VERSION 5.8 ;
BUSBITCHARS "[]" ;
DIVIDERCHAR "/" ;
UNITS
    DATABASE MICRONS 1000 ;
END UNITS

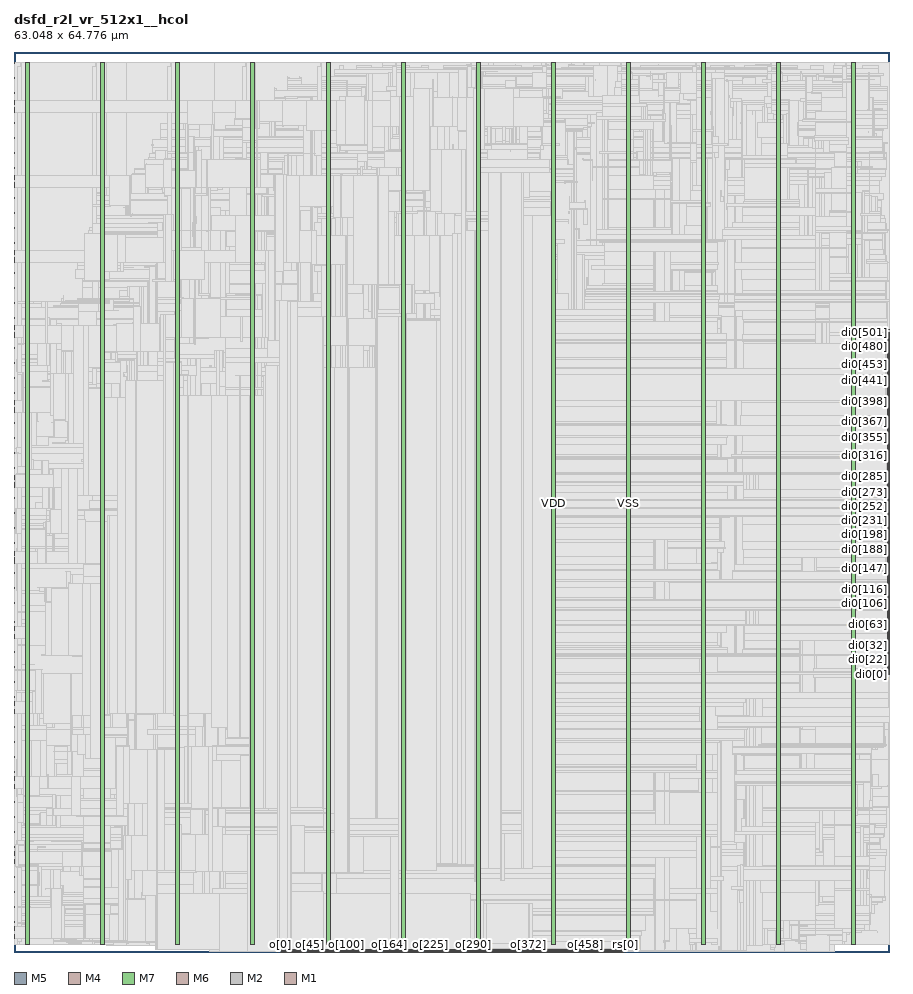
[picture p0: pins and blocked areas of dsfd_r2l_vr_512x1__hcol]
MACRO dsfd_r2l_vr_512x1__hcol
  FOREIGN dsfd_r2l_vr_512x1__hcol 0 0 ;
  CLASS BLOCK ;
  SIZE 63.048 BY 64.776 ;
  PIN ck[0]
    DIRECTION INPUT ;
    USE SIGNAL ;
    PORT
      LAYER M5 ;
        RECT  18.96 0 18.984 0.192 ;
    END
  END ck[0]
  PIN di0[0]
    DIRECTION INPUT ;
    USE SIGNAL ;
    PORT
      LAYER M4 ;
        RECT  62.856 19.968 63.048 19.992 ;
    END
  END di0[0]
  PIN di0[100]
    DIRECTION INPUT ;
    USE SIGNAL ;
    PORT
      LAYER M4 ;
        RECT  62.856 24.768 63.048 24.792 ;
    END
  END di0[100]
  PIN di0[101]
    DIRECTION INPUT ;
    USE SIGNAL ;
    PORT
      LAYER M4 ;
        RECT  62.856 24.816 63.048 24.84 ;
    END
  END di0[101]
  PIN di0[102]
    DIRECTION INPUT ;
    USE SIGNAL ;
    PORT
      LAYER M4 ;
        RECT  62.856 24.864 63.048 24.888 ;
    END
  END di0[102]
  PIN di0[103]
    DIRECTION INPUT ;
    USE SIGNAL ;
    PORT
      LAYER M4 ;
        RECT  62.856 24.912 63.048 24.936 ;
    END
  END di0[103]
  PIN di0[104]
    DIRECTION INPUT ;
    USE SIGNAL ;
    PORT
      LAYER M4 ;
        RECT  62.856 24.96 63.048 24.984 ;
    END
  END di0[104]
  PIN di0[105]
    DIRECTION INPUT ;
    USE SIGNAL ;
    PORT
      LAYER M4 ;
        RECT  62.856 25.008 63.048 25.032 ;
    END
  END di0[105]
  PIN di0[106]
    DIRECTION INPUT ;
    USE SIGNAL ;
    PORT
      LAYER M4 ;
        RECT  62.856 25.056 63.048 25.08 ;
    END
  END di0[106]
  PIN di0[107]
    DIRECTION INPUT ;
    USE SIGNAL ;
    PORT
      LAYER M4 ;
        RECT  62.856 25.104 63.048 25.128 ;
    END
  END di0[107]
  PIN di0[108]
    DIRECTION INPUT ;
    USE SIGNAL ;
    PORT
      LAYER M4 ;
        RECT  62.856 25.152 63.048 25.176 ;
    END
  END di0[108]
  PIN di0[109]
    DIRECTION INPUT ;
    USE SIGNAL ;
    PORT
      LAYER M4 ;
        RECT  62.856 25.2 63.048 25.224 ;
    END
  END di0[109]
  PIN di0[10]
    DIRECTION INPUT ;
    USE SIGNAL ;
    PORT
      LAYER M4 ;
        RECT  62.856 20.448 63.048 20.472 ;
    END
  END di0[10]
  PIN di0[110]
    DIRECTION INPUT ;
    USE SIGNAL ;
    PORT
      LAYER M4 ;
        RECT  62.856 25.248 63.048 25.272 ;
    END
  END di0[110]
  PIN di0[111]
    DIRECTION INPUT ;
    USE SIGNAL ;
    PORT
      LAYER M4 ;
        RECT  62.856 25.296 63.048 25.32 ;
    END
  END di0[111]
  PIN di0[112]
    DIRECTION INPUT ;
    USE SIGNAL ;
    PORT
      LAYER M4 ;
        RECT  62.856 25.344 63.048 25.368 ;
    END
  END di0[112]
  PIN di0[113]
    DIRECTION INPUT ;
    USE SIGNAL ;
    PORT
      LAYER M4 ;
        RECT  62.856 25.392 63.048 25.416 ;
    END
  END di0[113]
  PIN di0[114]
    DIRECTION INPUT ;
    USE SIGNAL ;
    PORT
      LAYER M4 ;
        RECT  62.856 25.44 63.048 25.464 ;
    END
  END di0[114]
  PIN di0[115]
    DIRECTION INPUT ;
    USE SIGNAL ;
    PORT
      LAYER M4 ;
        RECT  62.856 25.488 63.048 25.512 ;
    END
  END di0[115]
  PIN di0[116]
    DIRECTION INPUT ;
    USE SIGNAL ;
    PORT
      LAYER M4 ;
        RECT  62.856 25.536 63.048 25.56 ;
    END
  END di0[116]
  PIN di0[117]
    DIRECTION INPUT ;
    USE SIGNAL ;
    PORT
      LAYER M4 ;
        RECT  62.856 25.584 63.048 25.608 ;
    END
  END di0[117]
  PIN di0[118]
    DIRECTION INPUT ;
    USE SIGNAL ;
    PORT
      LAYER M4 ;
        RECT  62.856 25.632 63.048 25.656 ;
    END
  END di0[118]
  PIN di0[119]
    DIRECTION INPUT ;
    USE SIGNAL ;
    PORT
      LAYER M4 ;
        RECT  62.856 25.68 63.048 25.704 ;
    END
  END di0[119]
  PIN di0[11]
    DIRECTION INPUT ;
    USE SIGNAL ;
    PORT
      LAYER M4 ;
        RECT  62.856 20.496 63.048 20.52 ;
    END
  END di0[11]
  PIN di0[120]
    DIRECTION INPUT ;
    USE SIGNAL ;
    PORT
      LAYER M4 ;
        RECT  62.856 25.728 63.048 25.752 ;
    END
  END di0[120]
  PIN di0[121]
    DIRECTION INPUT ;
    USE SIGNAL ;
    PORT
      LAYER M4 ;
        RECT  62.856 25.776 63.048 25.8 ;
    END
  END di0[121]
  PIN di0[122]
    DIRECTION INPUT ;
    USE SIGNAL ;
    PORT
      LAYER M4 ;
        RECT  62.856 25.824 63.048 25.848 ;
    END
  END di0[122]
  PIN di0[123]
    DIRECTION INPUT ;
    USE SIGNAL ;
    PORT
      LAYER M4 ;
        RECT  62.856 25.872 63.048 25.896 ;
    END
  END di0[123]
  PIN di0[124]
    DIRECTION INPUT ;
    USE SIGNAL ;
    PORT
      LAYER M4 ;
        RECT  62.856 25.92 63.048 25.944 ;
    END
  END di0[124]
  PIN di0[125]
    DIRECTION INPUT ;
    USE SIGNAL ;
    PORT
      LAYER M4 ;
        RECT  62.856 25.968 63.048 25.992 ;
    END
  END di0[125]
  PIN di0[126]
    DIRECTION INPUT ;
    USE SIGNAL ;
    PORT
      LAYER M4 ;
        RECT  62.856 26.016 63.048 26.04 ;
    END
  END di0[126]
  PIN di0[127]
    DIRECTION INPUT ;
    USE SIGNAL ;
    PORT
      LAYER M4 ;
        RECT  62.856 26.064 63.048 26.088 ;
    END
  END di0[127]
  PIN di0[128]
    DIRECTION INPUT ;
    USE SIGNAL ;
    PORT
      LAYER M4 ;
        RECT  62.856 26.112 63.048 26.136 ;
    END
  END di0[128]
  PIN di0[129]
    DIRECTION INPUT ;
    USE SIGNAL ;
    PORT
      LAYER M4 ;
        RECT  62.856 26.16 63.048 26.184 ;
    END
  END di0[129]
  PIN di0[12]
    DIRECTION INPUT ;
    USE SIGNAL ;
    PORT
      LAYER M4 ;
        RECT  62.856 20.544 63.048 20.568 ;
    END
  END di0[12]
  PIN di0[130]
    DIRECTION INPUT ;
    USE SIGNAL ;
    PORT
      LAYER M4 ;
        RECT  62.856 26.208 63.048 26.232 ;
    END
  END di0[130]
  PIN di0[131]
    DIRECTION INPUT ;
    USE SIGNAL ;
    PORT
      LAYER M4 ;
        RECT  62.856 26.256 63.048 26.28 ;
    END
  END di0[131]
  PIN di0[132]
    DIRECTION INPUT ;
    USE SIGNAL ;
    PORT
      LAYER M4 ;
        RECT  62.856 26.304 63.048 26.328 ;
    END
  END di0[132]
  PIN di0[133]
    DIRECTION INPUT ;
    USE SIGNAL ;
    PORT
      LAYER M4 ;
        RECT  62.856 26.352 63.048 26.376 ;
    END
  END di0[133]
  PIN di0[134]
    DIRECTION INPUT ;
    USE SIGNAL ;
    PORT
      LAYER M4 ;
        RECT  62.856 26.4 63.048 26.424 ;
    END
  END di0[134]
  PIN di0[135]
    DIRECTION INPUT ;
    USE SIGNAL ;
    PORT
      LAYER M4 ;
        RECT  62.856 26.448 63.048 26.472 ;
    END
  END di0[135]
  PIN di0[136]
    DIRECTION INPUT ;
    USE SIGNAL ;
    PORT
      LAYER M4 ;
        RECT  62.856 26.496 63.048 26.52 ;
    END
  END di0[136]
  PIN di0[137]
    DIRECTION INPUT ;
    USE SIGNAL ;
    PORT
      LAYER M4 ;
        RECT  62.856 26.544 63.048 26.568 ;
    END
  END di0[137]
  PIN di0[138]
    DIRECTION INPUT ;
    USE SIGNAL ;
    PORT
      LAYER M4 ;
        RECT  62.856 26.592 63.048 26.616 ;
    END
  END di0[138]
  PIN di0[139]
    DIRECTION INPUT ;
    USE SIGNAL ;
    PORT
      LAYER M4 ;
        RECT  62.856 26.64 63.048 26.664 ;
    END
  END di0[139]
  PIN di0[13]
    DIRECTION INPUT ;
    USE SIGNAL ;
    PORT
      LAYER M4 ;
        RECT  62.856 20.592 63.048 20.616 ;
    END
  END di0[13]
  PIN di0[140]
    DIRECTION INPUT ;
    USE SIGNAL ;
    PORT
      LAYER M4 ;
        RECT  62.856 26.688 63.048 26.712 ;
    END
  END di0[140]
  PIN di0[141]
    DIRECTION INPUT ;
    USE SIGNAL ;
    PORT
      LAYER M4 ;
        RECT  62.856 26.736 63.048 26.76 ;
    END
  END di0[141]
  PIN di0[142]
    DIRECTION INPUT ;
    USE SIGNAL ;
    PORT
      LAYER M4 ;
        RECT  62.856 26.784 63.048 26.808 ;
    END
  END di0[142]
  PIN di0[143]
    DIRECTION INPUT ;
    USE SIGNAL ;
    PORT
      LAYER M4 ;
        RECT  62.856 26.832 63.048 26.856 ;
    END
  END di0[143]
  PIN di0[144]
    DIRECTION INPUT ;
    USE SIGNAL ;
    PORT
      LAYER M4 ;
        RECT  62.856 26.88 63.048 26.904 ;
    END
  END di0[144]
  PIN di0[145]
    DIRECTION INPUT ;
    USE SIGNAL ;
    PORT
      LAYER M4 ;
        RECT  62.856 26.928 63.048 26.952 ;
    END
  END di0[145]
  PIN di0[146]
    DIRECTION INPUT ;
    USE SIGNAL ;
    PORT
      LAYER M4 ;
        RECT  62.856 26.976 63.048 27 ;
    END
  END di0[146]
  PIN di0[147]
    DIRECTION INPUT ;
    USE SIGNAL ;
    PORT
      LAYER M4 ;
        RECT  62.856 27.024 63.048 27.048 ;
    END
  END di0[147]
  PIN di0[148]
    DIRECTION INPUT ;
    USE SIGNAL ;
    PORT
      LAYER M4 ;
        RECT  62.856 27.072 63.048 27.096 ;
    END
  END di0[148]
  PIN di0[149]
    DIRECTION INPUT ;
    USE SIGNAL ;
    PORT
      LAYER M4 ;
        RECT  62.856 27.12 63.048 27.144 ;
    END
  END di0[149]
  PIN di0[14]
    DIRECTION INPUT ;
    USE SIGNAL ;
    PORT
      LAYER M4 ;
        RECT  62.856 20.64 63.048 20.664 ;
    END
  END di0[14]
  PIN di0[150]
    DIRECTION INPUT ;
    USE SIGNAL ;
    PORT
      LAYER M4 ;
        RECT  62.856 27.168 63.048 27.192 ;
    END
  END di0[150]
  PIN di0[151]
    DIRECTION INPUT ;
    USE SIGNAL ;
    PORT
      LAYER M4 ;
        RECT  62.856 27.216 63.048 27.24 ;
    END
  END di0[151]
  PIN di0[152]
    DIRECTION INPUT ;
    USE SIGNAL ;
    PORT
      LAYER M4 ;
        RECT  62.856 27.264 63.048 27.288 ;
    END
  END di0[152]
  PIN di0[153]
    DIRECTION INPUT ;
    USE SIGNAL ;
    PORT
      LAYER M4 ;
        RECT  62.856 27.312 63.048 27.336 ;
    END
  END di0[153]
  PIN di0[154]
    DIRECTION INPUT ;
    USE SIGNAL ;
    PORT
      LAYER M4 ;
        RECT  62.856 27.36 63.048 27.384 ;
    END
  END di0[154]
  PIN di0[155]
    DIRECTION INPUT ;
    USE SIGNAL ;
    PORT
      LAYER M4 ;
        RECT  62.856 27.408 63.048 27.432 ;
    END
  END di0[155]
  PIN di0[156]
    DIRECTION INPUT ;
    USE SIGNAL ;
    PORT
      LAYER M4 ;
        RECT  62.856 27.456 63.048 27.48 ;
    END
  END di0[156]
  PIN di0[157]
    DIRECTION INPUT ;
    USE SIGNAL ;
    PORT
      LAYER M4 ;
        RECT  62.856 27.504 63.048 27.528 ;
    END
  END di0[157]
  PIN di0[158]
    DIRECTION INPUT ;
    USE SIGNAL ;
    PORT
      LAYER M4 ;
        RECT  62.856 27.552 63.048 27.576 ;
    END
  END di0[158]
  PIN di0[159]
    DIRECTION INPUT ;
    USE SIGNAL ;
    PORT
      LAYER M4 ;
        RECT  62.856 27.6 63.048 27.624 ;
    END
  END di0[159]
  PIN di0[15]
    DIRECTION INPUT ;
    USE SIGNAL ;
    PORT
      LAYER M4 ;
        RECT  62.856 20.688 63.048 20.712 ;
    END
  END di0[15]
  PIN di0[160]
    DIRECTION INPUT ;
    USE SIGNAL ;
    PORT
      LAYER M4 ;
        RECT  62.856 27.648 63.048 27.672 ;
    END
  END di0[160]
  PIN di0[161]
    DIRECTION INPUT ;
    USE SIGNAL ;
    PORT
      LAYER M4 ;
        RECT  62.856 27.696 63.048 27.72 ;
    END
  END di0[161]
  PIN di0[162]
    DIRECTION INPUT ;
    USE SIGNAL ;
    PORT
      LAYER M4 ;
        RECT  62.856 27.744 63.048 27.768 ;
    END
  END di0[162]
  PIN di0[163]
    DIRECTION INPUT ;
    USE SIGNAL ;
    PORT
      LAYER M4 ;
        RECT  62.856 27.792 63.048 27.816 ;
    END
  END di0[163]
  PIN di0[164]
    DIRECTION INPUT ;
    USE SIGNAL ;
    PORT
      LAYER M4 ;
        RECT  62.856 27.84 63.048 27.864 ;
    END
  END di0[164]
  PIN di0[165]
    DIRECTION INPUT ;
    USE SIGNAL ;
    PORT
      LAYER M4 ;
        RECT  62.856 27.888 63.048 27.912 ;
    END
  END di0[165]
  PIN di0[166]
    DIRECTION INPUT ;
    USE SIGNAL ;
    PORT
      LAYER M4 ;
        RECT  62.856 27.936 63.048 27.96 ;
    END
  END di0[166]
  PIN di0[167]
    DIRECTION INPUT ;
    USE SIGNAL ;
    PORT
      LAYER M4 ;
        RECT  62.856 27.984 63.048 28.008 ;
    END
  END di0[167]
  PIN di0[168]
    DIRECTION INPUT ;
    USE SIGNAL ;
    PORT
      LAYER M4 ;
        RECT  62.856 28.032 63.048 28.056 ;
    END
  END di0[168]
  PIN di0[169]
    DIRECTION INPUT ;
    USE SIGNAL ;
    PORT
      LAYER M4 ;
        RECT  62.856 28.08 63.048 28.104 ;
    END
  END di0[169]
  PIN di0[16]
    DIRECTION INPUT ;
    USE SIGNAL ;
    PORT
      LAYER M4 ;
        RECT  62.856 20.736 63.048 20.76 ;
    END
  END di0[16]
  PIN di0[170]
    DIRECTION INPUT ;
    USE SIGNAL ;
    PORT
      LAYER M4 ;
        RECT  62.856 28.128 63.048 28.152 ;
    END
  END di0[170]
  PIN di0[171]
    DIRECTION INPUT ;
    USE SIGNAL ;
    PORT
      LAYER M4 ;
        RECT  62.856 28.176 63.048 28.2 ;
    END
  END di0[171]
  PIN di0[172]
    DIRECTION INPUT ;
    USE SIGNAL ;
    PORT
      LAYER M4 ;
        RECT  62.856 28.224 63.048 28.248 ;
    END
  END di0[172]
  PIN di0[173]
    DIRECTION INPUT ;
    USE SIGNAL ;
    PORT
      LAYER M4 ;
        RECT  62.856 28.272 63.048 28.296 ;
    END
  END di0[173]
  PIN di0[174]
    DIRECTION INPUT ;
    USE SIGNAL ;
    PORT
      LAYER M4 ;
        RECT  62.856 28.32 63.048 28.344 ;
    END
  END di0[174]
  PIN di0[175]
    DIRECTION INPUT ;
    USE SIGNAL ;
    PORT
      LAYER M4 ;
        RECT  62.856 28.368 63.048 28.392 ;
    END
  END di0[175]
  PIN di0[176]
    DIRECTION INPUT ;
    USE SIGNAL ;
    PORT
      LAYER M4 ;
        RECT  62.856 28.416 63.048 28.44 ;
    END
  END di0[176]
  PIN di0[177]
    DIRECTION INPUT ;
    USE SIGNAL ;
    PORT
      LAYER M4 ;
        RECT  62.856 28.464 63.048 28.488 ;
    END
  END di0[177]
  PIN di0[178]
    DIRECTION INPUT ;
    USE SIGNAL ;
    PORT
      LAYER M4 ;
        RECT  62.856 28.512 63.048 28.536 ;
    END
  END di0[178]
  PIN di0[179]
    DIRECTION INPUT ;
    USE SIGNAL ;
    PORT
      LAYER M4 ;
        RECT  62.856 28.56 63.048 28.584 ;
    END
  END di0[179]
  PIN di0[17]
    DIRECTION INPUT ;
    USE SIGNAL ;
    PORT
      LAYER M4 ;
        RECT  62.856 20.784 63.048 20.808 ;
    END
  END di0[17]
  PIN di0[180]
    DIRECTION INPUT ;
    USE SIGNAL ;
    PORT
      LAYER M4 ;
        RECT  62.856 28.608 63.048 28.632 ;
    END
  END di0[180]
  PIN di0[181]
    DIRECTION INPUT ;
    USE SIGNAL ;
    PORT
      LAYER M4 ;
        RECT  62.856 28.656 63.048 28.68 ;
    END
  END di0[181]
  PIN di0[182]
    DIRECTION INPUT ;
    USE SIGNAL ;
    PORT
      LAYER M4 ;
        RECT  62.856 28.704 63.048 28.728 ;
    END
  END di0[182]
  PIN di0[183]
    DIRECTION INPUT ;
    USE SIGNAL ;
    PORT
      LAYER M4 ;
        RECT  62.856 28.752 63.048 28.776 ;
    END
  END di0[183]
  PIN di0[184]
    DIRECTION INPUT ;
    USE SIGNAL ;
    PORT
      LAYER M4 ;
        RECT  62.856 28.8 63.048 28.824 ;
    END
  END di0[184]
  PIN di0[185]
    DIRECTION INPUT ;
    USE SIGNAL ;
    PORT
      LAYER M4 ;
        RECT  62.856 28.848 63.048 28.872 ;
    END
  END di0[185]
  PIN di0[186]
    DIRECTION INPUT ;
    USE SIGNAL ;
    PORT
      LAYER M4 ;
        RECT  62.856 28.896 63.048 28.92 ;
    END
  END di0[186]
  PIN di0[187]
    DIRECTION INPUT ;
    USE SIGNAL ;
    PORT
      LAYER M4 ;
        RECT  62.856 28.944 63.048 28.968 ;
    END
  END di0[187]
  PIN di0[188]
    DIRECTION INPUT ;
    USE SIGNAL ;
    PORT
      LAYER M4 ;
        RECT  62.856 28.992 63.048 29.016 ;
    END
  END di0[188]
  PIN di0[189]
    DIRECTION INPUT ;
    USE SIGNAL ;
    PORT
      LAYER M4 ;
        RECT  62.856 29.04 63.048 29.064 ;
    END
  END di0[189]
  PIN di0[18]
    DIRECTION INPUT ;
    USE SIGNAL ;
    PORT
      LAYER M4 ;
        RECT  62.856 20.832 63.048 20.856 ;
    END
  END di0[18]
  PIN di0[190]
    DIRECTION INPUT ;
    USE SIGNAL ;
    PORT
      LAYER M4 ;
        RECT  62.856 29.088 63.048 29.112 ;
    END
  END di0[190]
  PIN di0[191]
    DIRECTION INPUT ;
    USE SIGNAL ;
    PORT
      LAYER M4 ;
        RECT  62.856 29.136 63.048 29.16 ;
    END
  END di0[191]
  PIN di0[192]
    DIRECTION INPUT ;
    USE SIGNAL ;
    PORT
      LAYER M4 ;
        RECT  62.856 29.184 63.048 29.208 ;
    END
  END di0[192]
  PIN di0[193]
    DIRECTION INPUT ;
    USE SIGNAL ;
    PORT
      LAYER M4 ;
        RECT  62.856 29.232 63.048 29.256 ;
    END
  END di0[193]
  PIN di0[194]
    DIRECTION INPUT ;
    USE SIGNAL ;
    PORT
      LAYER M4 ;
        RECT  62.856 29.28 63.048 29.304 ;
    END
  END di0[194]
  PIN di0[195]
    DIRECTION INPUT ;
    USE SIGNAL ;
    PORT
      LAYER M4 ;
        RECT  62.856 29.328 63.048 29.352 ;
    END
  END di0[195]
  PIN di0[196]
    DIRECTION INPUT ;
    USE SIGNAL ;
    PORT
      LAYER M4 ;
        RECT  62.856 29.376 63.048 29.4 ;
    END
  END di0[196]
  PIN di0[197]
    DIRECTION INPUT ;
    USE SIGNAL ;
    PORT
      LAYER M4 ;
        RECT  62.856 29.424 63.048 29.448 ;
    END
  END di0[197]
  PIN di0[198]
    DIRECTION INPUT ;
    USE SIGNAL ;
    PORT
      LAYER M4 ;
        RECT  62.856 29.472 63.048 29.496 ;
    END
  END di0[198]
  PIN di0[199]
    DIRECTION INPUT ;
    USE SIGNAL ;
    PORT
      LAYER M4 ;
        RECT  62.856 29.52 63.048 29.544 ;
    END
  END di0[199]
  PIN di0[19]
    DIRECTION INPUT ;
    USE SIGNAL ;
    PORT
      LAYER M4 ;
        RECT  62.856 20.88 63.048 20.904 ;
    END
  END di0[19]
  PIN di0[1]
    DIRECTION INPUT ;
    USE SIGNAL ;
    PORT
      LAYER M4 ;
        RECT  62.856 20.016 63.048 20.04 ;
    END
  END di0[1]
  PIN di0[200]
    DIRECTION INPUT ;
    USE SIGNAL ;
    PORT
      LAYER M4 ;
        RECT  62.856 29.568 63.048 29.592 ;
    END
  END di0[200]
  PIN di0[201]
    DIRECTION INPUT ;
    USE SIGNAL ;
    PORT
      LAYER M4 ;
        RECT  62.856 29.616 63.048 29.64 ;
    END
  END di0[201]
  PIN di0[202]
    DIRECTION INPUT ;
    USE SIGNAL ;
    PORT
      LAYER M4 ;
        RECT  62.856 29.664 63.048 29.688 ;
    END
  END di0[202]
  PIN di0[203]
    DIRECTION INPUT ;
    USE SIGNAL ;
    PORT
      LAYER M4 ;
        RECT  62.856 29.712 63.048 29.736 ;
    END
  END di0[203]
  PIN di0[204]
    DIRECTION INPUT ;
    USE SIGNAL ;
    PORT
      LAYER M4 ;
        RECT  62.856 29.76 63.048 29.784 ;
    END
  END di0[204]
  PIN di0[205]
    DIRECTION INPUT ;
    USE SIGNAL ;
    PORT
      LAYER M4 ;
        RECT  62.856 29.808 63.048 29.832 ;
    END
  END di0[205]
  PIN di0[206]
    DIRECTION INPUT ;
    USE SIGNAL ;
    PORT
      LAYER M4 ;
        RECT  62.856 29.856 63.048 29.88 ;
    END
  END di0[206]
  PIN di0[207]
    DIRECTION INPUT ;
    USE SIGNAL ;
    PORT
      LAYER M4 ;
        RECT  62.856 29.904 63.048 29.928 ;
    END
  END di0[207]
  PIN di0[208]
    DIRECTION INPUT ;
    USE SIGNAL ;
    PORT
      LAYER M4 ;
        RECT  62.856 29.952 63.048 29.976 ;
    END
  END di0[208]
  PIN di0[209]
    DIRECTION INPUT ;
    USE SIGNAL ;
    PORT
      LAYER M4 ;
        RECT  62.856 30 63.048 30.024 ;
    END
  END di0[209]
  PIN di0[20]
    DIRECTION INPUT ;
    USE SIGNAL ;
    PORT
      LAYER M4 ;
        RECT  62.856 20.928 63.048 20.952 ;
    END
  END di0[20]
  PIN di0[210]
    DIRECTION INPUT ;
    USE SIGNAL ;
    PORT
      LAYER M4 ;
        RECT  62.856 30.048 63.048 30.072 ;
    END
  END di0[210]
  PIN di0[211]
    DIRECTION INPUT ;
    USE SIGNAL ;
    PORT
      LAYER M4 ;
        RECT  62.856 30.096 63.048 30.12 ;
    END
  END di0[211]
  PIN di0[212]
    DIRECTION INPUT ;
    USE SIGNAL ;
    PORT
      LAYER M4 ;
        RECT  62.856 30.144 63.048 30.168 ;
    END
  END di0[212]
  PIN di0[213]
    DIRECTION INPUT ;
    USE SIGNAL ;
    PORT
      LAYER M4 ;
        RECT  62.856 30.192 63.048 30.216 ;
    END
  END di0[213]
  PIN di0[214]
    DIRECTION INPUT ;
    USE SIGNAL ;
    PORT
      LAYER M4 ;
        RECT  62.856 30.24 63.048 30.264 ;
    END
  END di0[214]
  PIN di0[215]
    DIRECTION INPUT ;
    USE SIGNAL ;
    PORT
      LAYER M4 ;
        RECT  62.856 30.288 63.048 30.312 ;
    END
  END di0[215]
  PIN di0[216]
    DIRECTION INPUT ;
    USE SIGNAL ;
    PORT
      LAYER M4 ;
        RECT  62.856 30.336 63.048 30.36 ;
    END
  END di0[216]
  PIN di0[217]
    DIRECTION INPUT ;
    USE SIGNAL ;
    PORT
      LAYER M4 ;
        RECT  62.856 30.384 63.048 30.408 ;
    END
  END di0[217]
  PIN di0[218]
    DIRECTION INPUT ;
    USE SIGNAL ;
    PORT
      LAYER M4 ;
        RECT  62.856 30.432 63.048 30.456 ;
    END
  END di0[218]
  PIN di0[219]
    DIRECTION INPUT ;
    USE SIGNAL ;
    PORT
      LAYER M4 ;
        RECT  62.856 30.48 63.048 30.504 ;
    END
  END di0[219]
  PIN di0[21]
    DIRECTION INPUT ;
    USE SIGNAL ;
    PORT
      LAYER M4 ;
        RECT  62.856 20.976 63.048 21 ;
    END
  END di0[21]
  PIN di0[220]
    DIRECTION INPUT ;
    USE SIGNAL ;
    PORT
      LAYER M4 ;
        RECT  62.856 30.528 63.048 30.552 ;
    END
  END di0[220]
  PIN di0[221]
    DIRECTION INPUT ;
    USE SIGNAL ;
    PORT
      LAYER M4 ;
        RECT  62.856 30.576 63.048 30.6 ;
    END
  END di0[221]
  PIN di0[222]
    DIRECTION INPUT ;
    USE SIGNAL ;
    PORT
      LAYER M4 ;
        RECT  62.856 30.624 63.048 30.648 ;
    END
  END di0[222]
  PIN di0[223]
    DIRECTION INPUT ;
    USE SIGNAL ;
    PORT
      LAYER M4 ;
        RECT  62.856 30.672 63.048 30.696 ;
    END
  END di0[223]
  PIN di0[224]
    DIRECTION INPUT ;
    USE SIGNAL ;
    PORT
      LAYER M4 ;
        RECT  62.856 30.72 63.048 30.744 ;
    END
  END di0[224]
  PIN di0[225]
    DIRECTION INPUT ;
    USE SIGNAL ;
    PORT
      LAYER M4 ;
        RECT  62.856 30.768 63.048 30.792 ;
    END
  END di0[225]
  PIN di0[226]
    DIRECTION INPUT ;
    USE SIGNAL ;
    PORT
      LAYER M4 ;
        RECT  62.856 30.816 63.048 30.84 ;
    END
  END di0[226]
  PIN di0[227]
    DIRECTION INPUT ;
    USE SIGNAL ;
    PORT
      LAYER M4 ;
        RECT  62.856 30.864 63.048 30.888 ;
    END
  END di0[227]
  PIN di0[228]
    DIRECTION INPUT ;
    USE SIGNAL ;
    PORT
      LAYER M4 ;
        RECT  62.856 30.912 63.048 30.936 ;
    END
  END di0[228]
  PIN di0[229]
    DIRECTION INPUT ;
    USE SIGNAL ;
    PORT
      LAYER M4 ;
        RECT  62.856 30.96 63.048 30.984 ;
    END
  END di0[229]
  PIN di0[22]
    DIRECTION INPUT ;
    USE SIGNAL ;
    PORT
      LAYER M4 ;
        RECT  62.856 21.024 63.048 21.048 ;
    END
  END di0[22]
  PIN di0[230]
    DIRECTION INPUT ;
    USE SIGNAL ;
    PORT
      LAYER M4 ;
        RECT  62.856 31.008 63.048 31.032 ;
    END
  END di0[230]
  PIN di0[231]
    DIRECTION INPUT ;
    USE SIGNAL ;
    PORT
      LAYER M4 ;
        RECT  62.856 31.056 63.048 31.08 ;
    END
  END di0[231]
  PIN di0[232]
    DIRECTION INPUT ;
    USE SIGNAL ;
    PORT
      LAYER M4 ;
        RECT  62.856 31.104 63.048 31.128 ;
    END
  END di0[232]
  PIN di0[233]
    DIRECTION INPUT ;
    USE SIGNAL ;
    PORT
      LAYER M4 ;
        RECT  62.856 31.152 63.048 31.176 ;
    END
  END di0[233]
  PIN di0[234]
    DIRECTION INPUT ;
    USE SIGNAL ;
    PORT
      LAYER M4 ;
        RECT  62.856 31.2 63.048 31.224 ;
    END
  END di0[234]
  PIN di0[235]
    DIRECTION INPUT ;
    USE SIGNAL ;
    PORT
      LAYER M4 ;
        RECT  62.856 31.248 63.048 31.272 ;
    END
  END di0[235]
  PIN di0[236]
    DIRECTION INPUT ;
    USE SIGNAL ;
    PORT
      LAYER M4 ;
        RECT  62.856 31.296 63.048 31.32 ;
    END
  END di0[236]
  PIN di0[237]
    DIRECTION INPUT ;
    USE SIGNAL ;
    PORT
      LAYER M4 ;
        RECT  62.856 31.344 63.048 31.368 ;
    END
  END di0[237]
  PIN di0[238]
    DIRECTION INPUT ;
    USE SIGNAL ;
    PORT
      LAYER M4 ;
        RECT  62.856 31.392 63.048 31.416 ;
    END
  END di0[238]
  PIN di0[239]
    DIRECTION INPUT ;
    USE SIGNAL ;
    PORT
      LAYER M4 ;
        RECT  62.856 31.44 63.048 31.464 ;
    END
  END di0[239]
  PIN di0[23]
    DIRECTION INPUT ;
    USE SIGNAL ;
    PORT
      LAYER M4 ;
        RECT  62.856 21.072 63.048 21.096 ;
    END
  END di0[23]
  PIN di0[240]
    DIRECTION INPUT ;
    USE SIGNAL ;
    PORT
      LAYER M4 ;
        RECT  62.856 31.488 63.048 31.512 ;
    END
  END di0[240]
  PIN di0[241]
    DIRECTION INPUT ;
    USE SIGNAL ;
    PORT
      LAYER M4 ;
        RECT  62.856 31.536 63.048 31.56 ;
    END
  END di0[241]
  PIN di0[242]
    DIRECTION INPUT ;
    USE SIGNAL ;
    PORT
      LAYER M4 ;
        RECT  62.856 31.584 63.048 31.608 ;
    END
  END di0[242]
  PIN di0[243]
    DIRECTION INPUT ;
    USE SIGNAL ;
    PORT
      LAYER M4 ;
        RECT  62.856 31.632 63.048 31.656 ;
    END
  END di0[243]
  PIN di0[244]
    DIRECTION INPUT ;
    USE SIGNAL ;
    PORT
      LAYER M4 ;
        RECT  62.856 31.68 63.048 31.704 ;
    END
  END di0[244]
  PIN di0[245]
    DIRECTION INPUT ;
    USE SIGNAL ;
    PORT
      LAYER M4 ;
        RECT  62.856 31.728 63.048 31.752 ;
    END
  END di0[245]
  PIN di0[246]
    DIRECTION INPUT ;
    USE SIGNAL ;
    PORT
      LAYER M4 ;
        RECT  62.856 31.776 63.048 31.8 ;
    END
  END di0[246]
  PIN di0[247]
    DIRECTION INPUT ;
    USE SIGNAL ;
    PORT
      LAYER M4 ;
        RECT  62.856 31.824 63.048 31.848 ;
    END
  END di0[247]
  PIN di0[248]
    DIRECTION INPUT ;
    USE SIGNAL ;
    PORT
      LAYER M4 ;
        RECT  62.856 31.872 63.048 31.896 ;
    END
  END di0[248]
  PIN di0[249]
    DIRECTION INPUT ;
    USE SIGNAL ;
    PORT
      LAYER M4 ;
        RECT  62.856 31.92 63.048 31.944 ;
    END
  END di0[249]
  PIN di0[24]
    DIRECTION INPUT ;
    USE SIGNAL ;
    PORT
      LAYER M4 ;
        RECT  62.856 21.12 63.048 21.144 ;
    END
  END di0[24]
  PIN di0[250]
    DIRECTION INPUT ;
    USE SIGNAL ;
    PORT
      LAYER M4 ;
        RECT  62.856 31.968 63.048 31.992 ;
    END
  END di0[250]
  PIN di0[251]
    DIRECTION INPUT ;
    USE SIGNAL ;
    PORT
      LAYER M4 ;
        RECT  62.856 32.016 63.048 32.04 ;
    END
  END di0[251]
  PIN di0[252]
    DIRECTION INPUT ;
    USE SIGNAL ;
    PORT
      LAYER M4 ;
        RECT  62.856 32.064 63.048 32.088 ;
    END
  END di0[252]
  PIN di0[253]
    DIRECTION INPUT ;
    USE SIGNAL ;
    PORT
      LAYER M4 ;
        RECT  62.856 32.112 63.048 32.136 ;
    END
  END di0[253]
  PIN di0[254]
    DIRECTION INPUT ;
    USE SIGNAL ;
    PORT
      LAYER M4 ;
        RECT  62.856 32.16 63.048 32.184 ;
    END
  END di0[254]
  PIN di0[255]
    DIRECTION INPUT ;
    USE SIGNAL ;
    PORT
      LAYER M4 ;
        RECT  62.856 32.208 63.048 32.232 ;
    END
  END di0[255]
  PIN di0[256]
    DIRECTION INPUT ;
    USE SIGNAL ;
    PORT
      LAYER M4 ;
        RECT  62.856 32.256 63.048 32.28 ;
    END
  END di0[256]
  PIN di0[257]
    DIRECTION INPUT ;
    USE SIGNAL ;
    PORT
      LAYER M4 ;
        RECT  62.856 32.304 63.048 32.328 ;
    END
  END di0[257]
  PIN di0[258]
    DIRECTION INPUT ;
    USE SIGNAL ;
    PORT
      LAYER M4 ;
        RECT  62.856 32.352 63.048 32.376 ;
    END
  END di0[258]
  PIN di0[259]
    DIRECTION INPUT ;
    USE SIGNAL ;
    PORT
      LAYER M4 ;
        RECT  62.856 32.4 63.048 32.424 ;
    END
  END di0[259]
  PIN di0[25]
    DIRECTION INPUT ;
    USE SIGNAL ;
    PORT
      LAYER M4 ;
        RECT  62.856 21.168 63.048 21.192 ;
    END
  END di0[25]
  PIN di0[260]
    DIRECTION INPUT ;
    USE SIGNAL ;
    PORT
      LAYER M4 ;
        RECT  62.856 32.448 63.048 32.472 ;
    END
  END di0[260]
  PIN di0[261]
    DIRECTION INPUT ;
    USE SIGNAL ;
    PORT
      LAYER M4 ;
        RECT  62.856 32.496 63.048 32.52 ;
    END
  END di0[261]
  PIN di0[262]
    DIRECTION INPUT ;
    USE SIGNAL ;
    PORT
      LAYER M4 ;
        RECT  62.856 32.544 63.048 32.568 ;
    END
  END di0[262]
  PIN di0[263]
    DIRECTION INPUT ;
    USE SIGNAL ;
    PORT
      LAYER M4 ;
        RECT  62.856 32.592 63.048 32.616 ;
    END
  END di0[263]
  PIN di0[264]
    DIRECTION INPUT ;
    USE SIGNAL ;
    PORT
      LAYER M4 ;
        RECT  62.856 32.64 63.048 32.664 ;
    END
  END di0[264]
  PIN di0[265]
    DIRECTION INPUT ;
    USE SIGNAL ;
    PORT
      LAYER M4 ;
        RECT  62.856 32.688 63.048 32.712 ;
    END
  END di0[265]
  PIN di0[266]
    DIRECTION INPUT ;
    USE SIGNAL ;
    PORT
      LAYER M4 ;
        RECT  62.856 32.736 63.048 32.76 ;
    END
  END di0[266]
  PIN di0[267]
    DIRECTION INPUT ;
    USE SIGNAL ;
    PORT
      LAYER M4 ;
        RECT  62.856 32.784 63.048 32.808 ;
    END
  END di0[267]
  PIN di0[268]
    DIRECTION INPUT ;
    USE SIGNAL ;
    PORT
      LAYER M4 ;
        RECT  62.856 32.832 63.048 32.856 ;
    END
  END di0[268]
  PIN di0[269]
    DIRECTION INPUT ;
    USE SIGNAL ;
    PORT
      LAYER M4 ;
        RECT  62.856 32.88 63.048 32.904 ;
    END
  END di0[269]
  PIN di0[26]
    DIRECTION INPUT ;
    USE SIGNAL ;
    PORT
      LAYER M4 ;
        RECT  62.856 21.216 63.048 21.24 ;
    END
  END di0[26]
  PIN di0[270]
    DIRECTION INPUT ;
    USE SIGNAL ;
    PORT
      LAYER M4 ;
        RECT  62.856 32.928 63.048 32.952 ;
    END
  END di0[270]
  PIN di0[271]
    DIRECTION INPUT ;
    USE SIGNAL ;
    PORT
      LAYER M4 ;
        RECT  62.856 32.976 63.048 33 ;
    END
  END di0[271]
  PIN di0[272]
    DIRECTION INPUT ;
    USE SIGNAL ;
    PORT
      LAYER M4 ;
        RECT  62.856 33.024 63.048 33.048 ;
    END
  END di0[272]
  PIN di0[273]
    DIRECTION INPUT ;
    USE SIGNAL ;
    PORT
      LAYER M4 ;
        RECT  62.856 33.072 63.048 33.096 ;
    END
  END di0[273]
  PIN di0[274]
    DIRECTION INPUT ;
    USE SIGNAL ;
    PORT
      LAYER M4 ;
        RECT  62.856 33.12 63.048 33.144 ;
    END
  END di0[274]
  PIN di0[275]
    DIRECTION INPUT ;
    USE SIGNAL ;
    PORT
      LAYER M4 ;
        RECT  62.856 33.168 63.048 33.192 ;
    END
  END di0[275]
  PIN di0[276]
    DIRECTION INPUT ;
    USE SIGNAL ;
    PORT
      LAYER M4 ;
        RECT  62.856 33.216 63.048 33.24 ;
    END
  END di0[276]
  PIN di0[277]
    DIRECTION INPUT ;
    USE SIGNAL ;
    PORT
      LAYER M4 ;
        RECT  62.856 33.264 63.048 33.288 ;
    END
  END di0[277]
  PIN di0[278]
    DIRECTION INPUT ;
    USE SIGNAL ;
    PORT
      LAYER M4 ;
        RECT  62.856 33.312 63.048 33.336 ;
    END
  END di0[278]
  PIN di0[279]
    DIRECTION INPUT ;
    USE SIGNAL ;
    PORT
      LAYER M4 ;
        RECT  62.856 33.36 63.048 33.384 ;
    END
  END di0[279]
  PIN di0[27]
    DIRECTION INPUT ;
    USE SIGNAL ;
    PORT
      LAYER M4 ;
        RECT  62.856 21.264 63.048 21.288 ;
    END
  END di0[27]
  PIN di0[280]
    DIRECTION INPUT ;
    USE SIGNAL ;
    PORT
      LAYER M4 ;
        RECT  62.856 33.408 63.048 33.432 ;
    END
  END di0[280]
  PIN di0[281]
    DIRECTION INPUT ;
    USE SIGNAL ;
    PORT
      LAYER M4 ;
        RECT  62.856 33.456 63.048 33.48 ;
    END
  END di0[281]
  PIN di0[282]
    DIRECTION INPUT ;
    USE SIGNAL ;
    PORT
      LAYER M4 ;
        RECT  62.856 33.504 63.048 33.528 ;
    END
  END di0[282]
  PIN di0[283]
    DIRECTION INPUT ;
    USE SIGNAL ;
    PORT
      LAYER M4 ;
        RECT  62.856 33.552 63.048 33.576 ;
    END
  END di0[283]
  PIN di0[284]
    DIRECTION INPUT ;
    USE SIGNAL ;
    PORT
      LAYER M4 ;
        RECT  62.856 33.6 63.048 33.624 ;
    END
  END di0[284]
  PIN di0[285]
    DIRECTION INPUT ;
    USE SIGNAL ;
    PORT
      LAYER M4 ;
        RECT  62.856 33.648 63.048 33.672 ;
    END
  END di0[285]
  PIN di0[286]
    DIRECTION INPUT ;
    USE SIGNAL ;
    PORT
      LAYER M4 ;
        RECT  62.856 33.696 63.048 33.72 ;
    END
  END di0[286]
  PIN di0[287]
    DIRECTION INPUT ;
    USE SIGNAL ;
    PORT
      LAYER M4 ;
        RECT  62.856 33.744 63.048 33.768 ;
    END
  END di0[287]
  PIN di0[288]
    DIRECTION INPUT ;
    USE SIGNAL ;
    PORT
      LAYER M4 ;
        RECT  62.856 33.792 63.048 33.816 ;
    END
  END di0[288]
  PIN di0[289]
    DIRECTION INPUT ;
    USE SIGNAL ;
    PORT
      LAYER M4 ;
        RECT  62.856 33.84 63.048 33.864 ;
    END
  END di0[289]
  PIN di0[28]
    DIRECTION INPUT ;
    USE SIGNAL ;
    PORT
      LAYER M4 ;
        RECT  62.856 21.312 63.048 21.336 ;
    END
  END di0[28]
  PIN di0[290]
    DIRECTION INPUT ;
    USE SIGNAL ;
    PORT
      LAYER M4 ;
        RECT  62.856 33.888 63.048 33.912 ;
    END
  END di0[290]
  PIN di0[291]
    DIRECTION INPUT ;
    USE SIGNAL ;
    PORT
      LAYER M4 ;
        RECT  62.856 33.936 63.048 33.96 ;
    END
  END di0[291]
  PIN di0[292]
    DIRECTION INPUT ;
    USE SIGNAL ;
    PORT
      LAYER M4 ;
        RECT  62.856 33.984 63.048 34.008 ;
    END
  END di0[292]
  PIN di0[293]
    DIRECTION INPUT ;
    USE SIGNAL ;
    PORT
      LAYER M4 ;
        RECT  62.856 34.032 63.048 34.056 ;
    END
  END di0[293]
  PIN di0[294]
    DIRECTION INPUT ;
    USE SIGNAL ;
    PORT
      LAYER M4 ;
        RECT  62.856 34.08 63.048 34.104 ;
    END
  END di0[294]
  PIN di0[295]
    DIRECTION INPUT ;
    USE SIGNAL ;
    PORT
      LAYER M4 ;
        RECT  62.856 34.128 63.048 34.152 ;
    END
  END di0[295]
  PIN di0[296]
    DIRECTION INPUT ;
    USE SIGNAL ;
    PORT
      LAYER M4 ;
        RECT  62.856 34.176 63.048 34.2 ;
    END
  END di0[296]
  PIN di0[297]
    DIRECTION INPUT ;
    USE SIGNAL ;
    PORT
      LAYER M4 ;
        RECT  62.856 34.224 63.048 34.248 ;
    END
  END di0[297]
  PIN di0[298]
    DIRECTION INPUT ;
    USE SIGNAL ;
    PORT
      LAYER M4 ;
        RECT  62.856 34.272 63.048 34.296 ;
    END
  END di0[298]
  PIN di0[299]
    DIRECTION INPUT ;
    USE SIGNAL ;
    PORT
      LAYER M4 ;
        RECT  62.856 34.32 63.048 34.344 ;
    END
  END di0[299]
  PIN di0[29]
    DIRECTION INPUT ;
    USE SIGNAL ;
    PORT
      LAYER M4 ;
        RECT  62.856 21.36 63.048 21.384 ;
    END
  END di0[29]
  PIN di0[2]
    DIRECTION INPUT ;
    USE SIGNAL ;
    PORT
      LAYER M4 ;
        RECT  62.856 20.064 63.048 20.088 ;
    END
  END di0[2]
  PIN di0[300]
    DIRECTION INPUT ;
    USE SIGNAL ;
    PORT
      LAYER M4 ;
        RECT  62.856 34.368 63.048 34.392 ;
    END
  END di0[300]
  PIN di0[301]
    DIRECTION INPUT ;
    USE SIGNAL ;
    PORT
      LAYER M4 ;
        RECT  62.856 34.416 63.048 34.44 ;
    END
  END di0[301]
  PIN di0[302]
    DIRECTION INPUT ;
    USE SIGNAL ;
    PORT
      LAYER M4 ;
        RECT  62.856 34.464 63.048 34.488 ;
    END
  END di0[302]
  PIN di0[303]
    DIRECTION INPUT ;
    USE SIGNAL ;
    PORT
      LAYER M4 ;
        RECT  62.856 34.512 63.048 34.536 ;
    END
  END di0[303]
  PIN di0[304]
    DIRECTION INPUT ;
    USE SIGNAL ;
    PORT
      LAYER M4 ;
        RECT  62.856 34.56 63.048 34.584 ;
    END
  END di0[304]
  PIN di0[305]
    DIRECTION INPUT ;
    USE SIGNAL ;
    PORT
      LAYER M4 ;
        RECT  62.856 34.608 63.048 34.632 ;
    END
  END di0[305]
  PIN di0[306]
    DIRECTION INPUT ;
    USE SIGNAL ;
    PORT
      LAYER M4 ;
        RECT  62.856 34.656 63.048 34.68 ;
    END
  END di0[306]
  PIN di0[307]
    DIRECTION INPUT ;
    USE SIGNAL ;
    PORT
      LAYER M4 ;
        RECT  62.856 34.704 63.048 34.728 ;
    END
  END di0[307]
  PIN di0[308]
    DIRECTION INPUT ;
    USE SIGNAL ;
    PORT
      LAYER M4 ;
        RECT  62.856 34.752 63.048 34.776 ;
    END
  END di0[308]
  PIN di0[309]
    DIRECTION INPUT ;
    USE SIGNAL ;
    PORT
      LAYER M4 ;
        RECT  62.856 34.8 63.048 34.824 ;
    END
  END di0[309]
  PIN di0[30]
    DIRECTION INPUT ;
    USE SIGNAL ;
    PORT
      LAYER M4 ;
        RECT  62.856 21.408 63.048 21.432 ;
    END
  END di0[30]
  PIN di0[310]
    DIRECTION INPUT ;
    USE SIGNAL ;
    PORT
      LAYER M4 ;
        RECT  62.856 34.848 63.048 34.872 ;
    END
  END di0[310]
  PIN di0[311]
    DIRECTION INPUT ;
    USE SIGNAL ;
    PORT
      LAYER M4 ;
        RECT  62.856 34.896 63.048 34.92 ;
    END
  END di0[311]
  PIN di0[312]
    DIRECTION INPUT ;
    USE SIGNAL ;
    PORT
      LAYER M4 ;
        RECT  62.856 34.944 63.048 34.968 ;
    END
  END di0[312]
  PIN di0[313]
    DIRECTION INPUT ;
    USE SIGNAL ;
    PORT
      LAYER M4 ;
        RECT  62.856 34.992 63.048 35.016 ;
    END
  END di0[313]
  PIN di0[314]
    DIRECTION INPUT ;
    USE SIGNAL ;
    PORT
      LAYER M4 ;
        RECT  62.856 35.04 63.048 35.064 ;
    END
  END di0[314]
  PIN di0[315]
    DIRECTION INPUT ;
    USE SIGNAL ;
    PORT
      LAYER M4 ;
        RECT  62.856 35.088 63.048 35.112 ;
    END
  END di0[315]
  PIN di0[316]
    DIRECTION INPUT ;
    USE SIGNAL ;
    PORT
      LAYER M4 ;
        RECT  62.856 35.136 63.048 35.16 ;
    END
  END di0[316]
  PIN di0[317]
    DIRECTION INPUT ;
    USE SIGNAL ;
    PORT
      LAYER M4 ;
        RECT  62.856 35.184 63.048 35.208 ;
    END
  END di0[317]
  PIN di0[318]
    DIRECTION INPUT ;
    USE SIGNAL ;
    PORT
      LAYER M4 ;
        RECT  62.856 35.232 63.048 35.256 ;
    END
  END di0[318]
  PIN di0[319]
    DIRECTION INPUT ;
    USE SIGNAL ;
    PORT
      LAYER M4 ;
        RECT  62.856 35.28 63.048 35.304 ;
    END
  END di0[319]
  PIN di0[31]
    DIRECTION INPUT ;
    USE SIGNAL ;
    PORT
      LAYER M4 ;
        RECT  62.856 21.456 63.048 21.48 ;
    END
  END di0[31]
  PIN di0[320]
    DIRECTION INPUT ;
    USE SIGNAL ;
    PORT
      LAYER M4 ;
        RECT  62.856 35.328 63.048 35.352 ;
    END
  END di0[320]
  PIN di0[321]
    DIRECTION INPUT ;
    USE SIGNAL ;
    PORT
      LAYER M4 ;
        RECT  62.856 35.376 63.048 35.4 ;
    END
  END di0[321]
  PIN di0[322]
    DIRECTION INPUT ;
    USE SIGNAL ;
    PORT
      LAYER M4 ;
        RECT  62.856 35.424 63.048 35.448 ;
    END
  END di0[322]
  PIN di0[323]
    DIRECTION INPUT ;
    USE SIGNAL ;
    PORT
      LAYER M4 ;
        RECT  62.856 35.472 63.048 35.496 ;
    END
  END di0[323]
  PIN di0[324]
    DIRECTION INPUT ;
    USE SIGNAL ;
    PORT
      LAYER M4 ;
        RECT  62.856 35.52 63.048 35.544 ;
    END
  END di0[324]
  PIN di0[325]
    DIRECTION INPUT ;
    USE SIGNAL ;
    PORT
      LAYER M4 ;
        RECT  62.856 35.568 63.048 35.592 ;
    END
  END di0[325]
  PIN di0[326]
    DIRECTION INPUT ;
    USE SIGNAL ;
    PORT
      LAYER M4 ;
        RECT  62.856 35.616 63.048 35.64 ;
    END
  END di0[326]
  PIN di0[327]
    DIRECTION INPUT ;
    USE SIGNAL ;
    PORT
      LAYER M4 ;
        RECT  62.856 35.664 63.048 35.688 ;
    END
  END di0[327]
  PIN di0[328]
    DIRECTION INPUT ;
    USE SIGNAL ;
    PORT
      LAYER M4 ;
        RECT  62.856 35.712 63.048 35.736 ;
    END
  END di0[328]
  PIN di0[329]
    DIRECTION INPUT ;
    USE SIGNAL ;
    PORT
      LAYER M4 ;
        RECT  62.856 35.76 63.048 35.784 ;
    END
  END di0[329]
  PIN di0[32]
    DIRECTION INPUT ;
    USE SIGNAL ;
    PORT
      LAYER M4 ;
        RECT  62.856 21.504 63.048 21.528 ;
    END
  END di0[32]
  PIN di0[330]
    DIRECTION INPUT ;
    USE SIGNAL ;
    PORT
      LAYER M4 ;
        RECT  62.856 35.808 63.048 35.832 ;
    END
  END di0[330]
  PIN di0[331]
    DIRECTION INPUT ;
    USE SIGNAL ;
    PORT
      LAYER M4 ;
        RECT  62.856 35.856 63.048 35.88 ;
    END
  END di0[331]
  PIN di0[332]
    DIRECTION INPUT ;
    USE SIGNAL ;
    PORT
      LAYER M4 ;
        RECT  62.856 35.904 63.048 35.928 ;
    END
  END di0[332]
  PIN di0[333]
    DIRECTION INPUT ;
    USE SIGNAL ;
    PORT
      LAYER M4 ;
        RECT  62.856 35.952 63.048 35.976 ;
    END
  END di0[333]
  PIN di0[334]
    DIRECTION INPUT ;
    USE SIGNAL ;
    PORT
      LAYER M4 ;
        RECT  62.856 36 63.048 36.024 ;
    END
  END di0[334]
  PIN di0[335]
    DIRECTION INPUT ;
    USE SIGNAL ;
    PORT
      LAYER M4 ;
        RECT  62.856 36.048 63.048 36.072 ;
    END
  END di0[335]
  PIN di0[336]
    DIRECTION INPUT ;
    USE SIGNAL ;
    PORT
      LAYER M4 ;
        RECT  62.856 36.096 63.048 36.12 ;
    END
  END di0[336]
  PIN di0[337]
    DIRECTION INPUT ;
    USE SIGNAL ;
    PORT
      LAYER M4 ;
        RECT  62.856 36.144 63.048 36.168 ;
    END
  END di0[337]
  PIN di0[338]
    DIRECTION INPUT ;
    USE SIGNAL ;
    PORT
      LAYER M4 ;
        RECT  62.856 36.192 63.048 36.216 ;
    END
  END di0[338]
  PIN di0[339]
    DIRECTION INPUT ;
    USE SIGNAL ;
    PORT
      LAYER M4 ;
        RECT  62.856 36.24 63.048 36.264 ;
    END
  END di0[339]
  PIN di0[33]
    DIRECTION INPUT ;
    USE SIGNAL ;
    PORT
      LAYER M4 ;
        RECT  62.856 21.552 63.048 21.576 ;
    END
  END di0[33]
  PIN di0[340]
    DIRECTION INPUT ;
    USE SIGNAL ;
    PORT
      LAYER M4 ;
        RECT  62.856 36.288 63.048 36.312 ;
    END
  END di0[340]
  PIN di0[341]
    DIRECTION INPUT ;
    USE SIGNAL ;
    PORT
      LAYER M4 ;
        RECT  62.856 36.336 63.048 36.36 ;
    END
  END di0[341]
  PIN di0[342]
    DIRECTION INPUT ;
    USE SIGNAL ;
    PORT
      LAYER M4 ;
        RECT  62.856 36.384 63.048 36.408 ;
    END
  END di0[342]
  PIN di0[343]
    DIRECTION INPUT ;
    USE SIGNAL ;
    PORT
      LAYER M4 ;
        RECT  62.856 36.432 63.048 36.456 ;
    END
  END di0[343]
  PIN di0[344]
    DIRECTION INPUT ;
    USE SIGNAL ;
    PORT
      LAYER M4 ;
        RECT  62.856 36.48 63.048 36.504 ;
    END
  END di0[344]
  PIN di0[345]
    DIRECTION INPUT ;
    USE SIGNAL ;
    PORT
      LAYER M4 ;
        RECT  62.856 36.528 63.048 36.552 ;
    END
  END di0[345]
  PIN di0[346]
    DIRECTION INPUT ;
    USE SIGNAL ;
    PORT
      LAYER M4 ;
        RECT  62.856 36.576 63.048 36.6 ;
    END
  END di0[346]
  PIN di0[347]
    DIRECTION INPUT ;
    USE SIGNAL ;
    PORT
      LAYER M4 ;
        RECT  62.856 36.624 63.048 36.648 ;
    END
  END di0[347]
  PIN di0[348]
    DIRECTION INPUT ;
    USE SIGNAL ;
    PORT
      LAYER M4 ;
        RECT  62.856 36.672 63.048 36.696 ;
    END
  END di0[348]
  PIN di0[349]
    DIRECTION INPUT ;
    USE SIGNAL ;
    PORT
      LAYER M4 ;
        RECT  62.856 36.72 63.048 36.744 ;
    END
  END di0[349]
  PIN di0[34]
    DIRECTION INPUT ;
    USE SIGNAL ;
    PORT
      LAYER M4 ;
        RECT  62.856 21.6 63.048 21.624 ;
    END
  END di0[34]
  PIN di0[350]
    DIRECTION INPUT ;
    USE SIGNAL ;
    PORT
      LAYER M4 ;
        RECT  62.856 36.768 63.048 36.792 ;
    END
  END di0[350]
  PIN di0[351]
    DIRECTION INPUT ;
    USE SIGNAL ;
    PORT
      LAYER M4 ;
        RECT  62.856 36.816 63.048 36.84 ;
    END
  END di0[351]
  PIN di0[352]
    DIRECTION INPUT ;
    USE SIGNAL ;
    PORT
      LAYER M4 ;
        RECT  62.856 36.864 63.048 36.888 ;
    END
  END di0[352]
  PIN di0[353]
    DIRECTION INPUT ;
    USE SIGNAL ;
    PORT
      LAYER M4 ;
        RECT  62.856 36.912 63.048 36.936 ;
    END
  END di0[353]
  PIN di0[354]
    DIRECTION INPUT ;
    USE SIGNAL ;
    PORT
      LAYER M4 ;
        RECT  62.856 36.96 63.048 36.984 ;
    END
  END di0[354]
  PIN di0[355]
    DIRECTION INPUT ;
    USE SIGNAL ;
    PORT
      LAYER M4 ;
        RECT  62.856 37.008 63.048 37.032 ;
    END
  END di0[355]
  PIN di0[356]
    DIRECTION INPUT ;
    USE SIGNAL ;
    PORT
      LAYER M4 ;
        RECT  62.856 37.056 63.048 37.08 ;
    END
  END di0[356]
  PIN di0[357]
    DIRECTION INPUT ;
    USE SIGNAL ;
    PORT
      LAYER M4 ;
        RECT  62.856 37.104 63.048 37.128 ;
    END
  END di0[357]
  PIN di0[358]
    DIRECTION INPUT ;
    USE SIGNAL ;
    PORT
      LAYER M4 ;
        RECT  62.856 37.152 63.048 37.176 ;
    END
  END di0[358]
  PIN di0[359]
    DIRECTION INPUT ;
    USE SIGNAL ;
    PORT
      LAYER M4 ;
        RECT  62.856 37.2 63.048 37.224 ;
    END
  END di0[359]
  PIN di0[35]
    DIRECTION INPUT ;
    USE SIGNAL ;
    PORT
      LAYER M4 ;
        RECT  62.856 21.648 63.048 21.672 ;
    END
  END di0[35]
  PIN di0[360]
    DIRECTION INPUT ;
    USE SIGNAL ;
    PORT
      LAYER M4 ;
        RECT  62.856 37.248 63.048 37.272 ;
    END
  END di0[360]
  PIN di0[361]
    DIRECTION INPUT ;
    USE SIGNAL ;
    PORT
      LAYER M4 ;
        RECT  62.856 37.296 63.048 37.32 ;
    END
  END di0[361]
  PIN di0[362]
    DIRECTION INPUT ;
    USE SIGNAL ;
    PORT
      LAYER M4 ;
        RECT  62.856 37.344 63.048 37.368 ;
    END
  END di0[362]
  PIN di0[363]
    DIRECTION INPUT ;
    USE SIGNAL ;
    PORT
      LAYER M4 ;
        RECT  62.856 37.392 63.048 37.416 ;
    END
  END di0[363]
  PIN di0[364]
    DIRECTION INPUT ;
    USE SIGNAL ;
    PORT
      LAYER M4 ;
        RECT  62.856 37.44 63.048 37.464 ;
    END
  END di0[364]
  PIN di0[365]
    DIRECTION INPUT ;
    USE SIGNAL ;
    PORT
      LAYER M4 ;
        RECT  62.856 37.488 63.048 37.512 ;
    END
  END di0[365]
  PIN di0[366]
    DIRECTION INPUT ;
    USE SIGNAL ;
    PORT
      LAYER M4 ;
        RECT  62.856 37.536 63.048 37.56 ;
    END
  END di0[366]
  PIN di0[367]
    DIRECTION INPUT ;
    USE SIGNAL ;
    PORT
      LAYER M4 ;
        RECT  62.856 37.584 63.048 37.608 ;
    END
  END di0[367]
  PIN di0[368]
    DIRECTION INPUT ;
    USE SIGNAL ;
    PORT
      LAYER M4 ;
        RECT  62.856 37.632 63.048 37.656 ;
    END
  END di0[368]
  PIN di0[369]
    DIRECTION INPUT ;
    USE SIGNAL ;
    PORT
      LAYER M4 ;
        RECT  62.856 37.68 63.048 37.704 ;
    END
  END di0[369]
  PIN di0[36]
    DIRECTION INPUT ;
    USE SIGNAL ;
    PORT
      LAYER M4 ;
        RECT  62.856 21.696 63.048 21.72 ;
    END
  END di0[36]
  PIN di0[370]
    DIRECTION INPUT ;
    USE SIGNAL ;
    PORT
      LAYER M4 ;
        RECT  62.856 37.728 63.048 37.752 ;
    END
  END di0[370]
  PIN di0[371]
    DIRECTION INPUT ;
    USE SIGNAL ;
    PORT
      LAYER M4 ;
        RECT  62.856 37.776 63.048 37.8 ;
    END
  END di0[371]
  PIN di0[372]
    DIRECTION INPUT ;
    USE SIGNAL ;
    PORT
      LAYER M4 ;
        RECT  62.856 37.824 63.048 37.848 ;
    END
  END di0[372]
  PIN di0[373]
    DIRECTION INPUT ;
    USE SIGNAL ;
    PORT
      LAYER M4 ;
        RECT  62.856 37.872 63.048 37.896 ;
    END
  END di0[373]
  PIN di0[374]
    DIRECTION INPUT ;
    USE SIGNAL ;
    PORT
      LAYER M4 ;
        RECT  62.856 37.92 63.048 37.944 ;
    END
  END di0[374]
  PIN di0[375]
    DIRECTION INPUT ;
    USE SIGNAL ;
    PORT
      LAYER M4 ;
        RECT  62.856 37.968 63.048 37.992 ;
    END
  END di0[375]
  PIN di0[376]
    DIRECTION INPUT ;
    USE SIGNAL ;
    PORT
      LAYER M4 ;
        RECT  62.856 38.016 63.048 38.04 ;
    END
  END di0[376]
  PIN di0[377]
    DIRECTION INPUT ;
    USE SIGNAL ;
    PORT
      LAYER M4 ;
        RECT  62.856 38.064 63.048 38.088 ;
    END
  END di0[377]
  PIN di0[378]
    DIRECTION INPUT ;
    USE SIGNAL ;
    PORT
      LAYER M4 ;
        RECT  62.856 38.112 63.048 38.136 ;
    END
  END di0[378]
  PIN di0[379]
    DIRECTION INPUT ;
    USE SIGNAL ;
    PORT
      LAYER M4 ;
        RECT  62.856 38.16 63.048 38.184 ;
    END
  END di0[379]
  PIN di0[37]
    DIRECTION INPUT ;
    USE SIGNAL ;
    PORT
      LAYER M4 ;
        RECT  62.856 21.744 63.048 21.768 ;
    END
  END di0[37]
  PIN di0[380]
    DIRECTION INPUT ;
    USE SIGNAL ;
    PORT
      LAYER M4 ;
        RECT  62.856 38.208 63.048 38.232 ;
    END
  END di0[380]
  PIN di0[381]
    DIRECTION INPUT ;
    USE SIGNAL ;
    PORT
      LAYER M4 ;
        RECT  62.856 38.256 63.048 38.28 ;
    END
  END di0[381]
  PIN di0[382]
    DIRECTION INPUT ;
    USE SIGNAL ;
    PORT
      LAYER M4 ;
        RECT  62.856 38.304 63.048 38.328 ;
    END
  END di0[382]
  PIN di0[383]
    DIRECTION INPUT ;
    USE SIGNAL ;
    PORT
      LAYER M4 ;
        RECT  62.856 38.352 63.048 38.376 ;
    END
  END di0[383]
  PIN di0[384]
    DIRECTION INPUT ;
    USE SIGNAL ;
    PORT
      LAYER M4 ;
        RECT  62.856 38.4 63.048 38.424 ;
    END
  END di0[384]
  PIN di0[385]
    DIRECTION INPUT ;
    USE SIGNAL ;
    PORT
      LAYER M4 ;
        RECT  62.856 38.448 63.048 38.472 ;
    END
  END di0[385]
  PIN di0[386]
    DIRECTION INPUT ;
    USE SIGNAL ;
    PORT
      LAYER M4 ;
        RECT  62.856 38.496 63.048 38.52 ;
    END
  END di0[386]
  PIN di0[387]
    DIRECTION INPUT ;
    USE SIGNAL ;
    PORT
      LAYER M4 ;
        RECT  62.856 38.544 63.048 38.568 ;
    END
  END di0[387]
  PIN di0[388]
    DIRECTION INPUT ;
    USE SIGNAL ;
    PORT
      LAYER M4 ;
        RECT  62.856 38.592 63.048 38.616 ;
    END
  END di0[388]
  PIN di0[389]
    DIRECTION INPUT ;
    USE SIGNAL ;
    PORT
      LAYER M4 ;
        RECT  62.856 38.64 63.048 38.664 ;
    END
  END di0[389]
  PIN di0[38]
    DIRECTION INPUT ;
    USE SIGNAL ;
    PORT
      LAYER M4 ;
        RECT  62.856 21.792 63.048 21.816 ;
    END
  END di0[38]
  PIN di0[390]
    DIRECTION INPUT ;
    USE SIGNAL ;
    PORT
      LAYER M4 ;
        RECT  62.856 38.688 63.048 38.712 ;
    END
  END di0[390]
  PIN di0[391]
    DIRECTION INPUT ;
    USE SIGNAL ;
    PORT
      LAYER M4 ;
        RECT  62.856 38.736 63.048 38.76 ;
    END
  END di0[391]
  PIN di0[392]
    DIRECTION INPUT ;
    USE SIGNAL ;
    PORT
      LAYER M4 ;
        RECT  62.856 38.784 63.048 38.808 ;
    END
  END di0[392]
  PIN di0[393]
    DIRECTION INPUT ;
    USE SIGNAL ;
    PORT
      LAYER M4 ;
        RECT  62.856 38.832 63.048 38.856 ;
    END
  END di0[393]
  PIN di0[394]
    DIRECTION INPUT ;
    USE SIGNAL ;
    PORT
      LAYER M4 ;
        RECT  62.856 38.88 63.048 38.904 ;
    END
  END di0[394]
  PIN di0[395]
    DIRECTION INPUT ;
    USE SIGNAL ;
    PORT
      LAYER M4 ;
        RECT  62.856 38.928 63.048 38.952 ;
    END
  END di0[395]
  PIN di0[396]
    DIRECTION INPUT ;
    USE SIGNAL ;
    PORT
      LAYER M4 ;
        RECT  62.856 38.976 63.048 39 ;
    END
  END di0[396]
  PIN di0[397]
    DIRECTION INPUT ;
    USE SIGNAL ;
    PORT
      LAYER M4 ;
        RECT  62.856 39.024 63.048 39.048 ;
    END
  END di0[397]
  PIN di0[398]
    DIRECTION INPUT ;
    USE SIGNAL ;
    PORT
      LAYER M4 ;
        RECT  62.856 39.072 63.048 39.096 ;
    END
  END di0[398]
  PIN di0[399]
    DIRECTION INPUT ;
    USE SIGNAL ;
    PORT
      LAYER M4 ;
        RECT  62.856 39.12 63.048 39.144 ;
    END
  END di0[399]
  PIN di0[39]
    DIRECTION INPUT ;
    USE SIGNAL ;
    PORT
      LAYER M4 ;
        RECT  62.856 21.84 63.048 21.864 ;
    END
  END di0[39]
  PIN di0[3]
    DIRECTION INPUT ;
    USE SIGNAL ;
    PORT
      LAYER M4 ;
        RECT  62.856 20.112 63.048 20.136 ;
    END
  END di0[3]
  PIN di0[400]
    DIRECTION INPUT ;
    USE SIGNAL ;
    PORT
      LAYER M4 ;
        RECT  62.856 39.168 63.048 39.192 ;
    END
  END di0[400]
  PIN di0[401]
    DIRECTION INPUT ;
    USE SIGNAL ;
    PORT
      LAYER M4 ;
        RECT  62.856 39.216 63.048 39.24 ;
    END
  END di0[401]
  PIN di0[402]
    DIRECTION INPUT ;
    USE SIGNAL ;
    PORT
      LAYER M4 ;
        RECT  62.856 39.264 63.048 39.288 ;
    END
  END di0[402]
  PIN di0[403]
    DIRECTION INPUT ;
    USE SIGNAL ;
    PORT
      LAYER M4 ;
        RECT  62.856 39.312 63.048 39.336 ;
    END
  END di0[403]
  PIN di0[404]
    DIRECTION INPUT ;
    USE SIGNAL ;
    PORT
      LAYER M4 ;
        RECT  62.856 39.36 63.048 39.384 ;
    END
  END di0[404]
  PIN di0[405]
    DIRECTION INPUT ;
    USE SIGNAL ;
    PORT
      LAYER M4 ;
        RECT  62.856 39.408 63.048 39.432 ;
    END
  END di0[405]
  PIN di0[406]
    DIRECTION INPUT ;
    USE SIGNAL ;
    PORT
      LAYER M4 ;
        RECT  62.856 39.456 63.048 39.48 ;
    END
  END di0[406]
  PIN di0[407]
    DIRECTION INPUT ;
    USE SIGNAL ;
    PORT
      LAYER M4 ;
        RECT  62.856 39.504 63.048 39.528 ;
    END
  END di0[407]
  PIN di0[408]
    DIRECTION INPUT ;
    USE SIGNAL ;
    PORT
      LAYER M4 ;
        RECT  62.856 39.552 63.048 39.576 ;
    END
  END di0[408]
  PIN di0[409]
    DIRECTION INPUT ;
    USE SIGNAL ;
    PORT
      LAYER M4 ;
        RECT  62.856 39.6 63.048 39.624 ;
    END
  END di0[409]
  PIN di0[40]
    DIRECTION INPUT ;
    USE SIGNAL ;
    PORT
      LAYER M4 ;
        RECT  62.856 21.888 63.048 21.912 ;
    END
  END di0[40]
  PIN di0[410]
    DIRECTION INPUT ;
    USE SIGNAL ;
    PORT
      LAYER M4 ;
        RECT  62.856 39.648 63.048 39.672 ;
    END
  END di0[410]
  PIN di0[411]
    DIRECTION INPUT ;
    USE SIGNAL ;
    PORT
      LAYER M4 ;
        RECT  62.856 39.696 63.048 39.72 ;
    END
  END di0[411]
  PIN di0[412]
    DIRECTION INPUT ;
    USE SIGNAL ;
    PORT
      LAYER M4 ;
        RECT  62.856 39.744 63.048 39.768 ;
    END
  END di0[412]
  PIN di0[413]
    DIRECTION INPUT ;
    USE SIGNAL ;
    PORT
      LAYER M4 ;
        RECT  62.856 39.792 63.048 39.816 ;
    END
  END di0[413]
  PIN di0[414]
    DIRECTION INPUT ;
    USE SIGNAL ;
    PORT
      LAYER M4 ;
        RECT  62.856 39.84 63.048 39.864 ;
    END
  END di0[414]
  PIN di0[415]
    DIRECTION INPUT ;
    USE SIGNAL ;
    PORT
      LAYER M4 ;
        RECT  62.856 39.888 63.048 39.912 ;
    END
  END di0[415]
  PIN di0[416]
    DIRECTION INPUT ;
    USE SIGNAL ;
    PORT
      LAYER M4 ;
        RECT  62.856 39.936 63.048 39.96 ;
    END
  END di0[416]
  PIN di0[417]
    DIRECTION INPUT ;
    USE SIGNAL ;
    PORT
      LAYER M4 ;
        RECT  62.856 39.984 63.048 40.008 ;
    END
  END di0[417]
  PIN di0[418]
    DIRECTION INPUT ;
    USE SIGNAL ;
    PORT
      LAYER M4 ;
        RECT  62.856 40.032 63.048 40.056 ;
    END
  END di0[418]
  PIN di0[419]
    DIRECTION INPUT ;
    USE SIGNAL ;
    PORT
      LAYER M4 ;
        RECT  62.856 40.08 63.048 40.104 ;
    END
  END di0[419]
  PIN di0[41]
    DIRECTION INPUT ;
    USE SIGNAL ;
    PORT
      LAYER M4 ;
        RECT  62.856 21.936 63.048 21.96 ;
    END
  END di0[41]
  PIN di0[420]
    DIRECTION INPUT ;
    USE SIGNAL ;
    PORT
      LAYER M4 ;
        RECT  62.856 40.128 63.048 40.152 ;
    END
  END di0[420]
  PIN di0[421]
    DIRECTION INPUT ;
    USE SIGNAL ;
    PORT
      LAYER M4 ;
        RECT  62.856 40.176 63.048 40.2 ;
    END
  END di0[421]
  PIN di0[422]
    DIRECTION INPUT ;
    USE SIGNAL ;
    PORT
      LAYER M4 ;
        RECT  62.856 40.224 63.048 40.248 ;
    END
  END di0[422]
  PIN di0[423]
    DIRECTION INPUT ;
    USE SIGNAL ;
    PORT
      LAYER M4 ;
        RECT  62.856 40.272 63.048 40.296 ;
    END
  END di0[423]
  PIN di0[424]
    DIRECTION INPUT ;
    USE SIGNAL ;
    PORT
      LAYER M4 ;
        RECT  62.856 40.32 63.048 40.344 ;
    END
  END di0[424]
  PIN di0[425]
    DIRECTION INPUT ;
    USE SIGNAL ;
    PORT
      LAYER M4 ;
        RECT  62.856 40.368 63.048 40.392 ;
    END
  END di0[425]
  PIN di0[426]
    DIRECTION INPUT ;
    USE SIGNAL ;
    PORT
      LAYER M4 ;
        RECT  62.856 40.416 63.048 40.44 ;
    END
  END di0[426]
  PIN di0[427]
    DIRECTION INPUT ;
    USE SIGNAL ;
    PORT
      LAYER M4 ;
        RECT  62.856 40.464 63.048 40.488 ;
    END
  END di0[427]
  PIN di0[428]
    DIRECTION INPUT ;
    USE SIGNAL ;
    PORT
      LAYER M4 ;
        RECT  62.856 40.512 63.048 40.536 ;
    END
  END di0[428]
  PIN di0[429]
    DIRECTION INPUT ;
    USE SIGNAL ;
    PORT
      LAYER M4 ;
        RECT  62.856 40.56 63.048 40.584 ;
    END
  END di0[429]
  PIN di0[42]
    DIRECTION INPUT ;
    USE SIGNAL ;
    PORT
      LAYER M4 ;
        RECT  62.856 21.984 63.048 22.008 ;
    END
  END di0[42]
  PIN di0[430]
    DIRECTION INPUT ;
    USE SIGNAL ;
    PORT
      LAYER M4 ;
        RECT  62.856 40.608 63.048 40.632 ;
    END
  END di0[430]
  PIN di0[431]
    DIRECTION INPUT ;
    USE SIGNAL ;
    PORT
      LAYER M4 ;
        RECT  62.856 40.656 63.048 40.68 ;
    END
  END di0[431]
  PIN di0[432]
    DIRECTION INPUT ;
    USE SIGNAL ;
    PORT
      LAYER M4 ;
        RECT  62.856 40.704 63.048 40.728 ;
    END
  END di0[432]
  PIN di0[433]
    DIRECTION INPUT ;
    USE SIGNAL ;
    PORT
      LAYER M4 ;
        RECT  62.856 40.752 63.048 40.776 ;
    END
  END di0[433]
  PIN di0[434]
    DIRECTION INPUT ;
    USE SIGNAL ;
    PORT
      LAYER M4 ;
        RECT  62.856 40.8 63.048 40.824 ;
    END
  END di0[434]
  PIN di0[435]
    DIRECTION INPUT ;
    USE SIGNAL ;
    PORT
      LAYER M4 ;
        RECT  62.856 40.848 63.048 40.872 ;
    END
  END di0[435]
  PIN di0[436]
    DIRECTION INPUT ;
    USE SIGNAL ;
    PORT
      LAYER M4 ;
        RECT  62.856 40.896 63.048 40.92 ;
    END
  END di0[436]
  PIN di0[437]
    DIRECTION INPUT ;
    USE SIGNAL ;
    PORT
      LAYER M4 ;
        RECT  62.856 40.944 63.048 40.968 ;
    END
  END di0[437]
  PIN di0[438]
    DIRECTION INPUT ;
    USE SIGNAL ;
    PORT
      LAYER M4 ;
        RECT  62.856 40.992 63.048 41.016 ;
    END
  END di0[438]
  PIN di0[439]
    DIRECTION INPUT ;
    USE SIGNAL ;
    PORT
      LAYER M4 ;
        RECT  62.856 41.04 63.048 41.064 ;
    END
  END di0[439]
  PIN di0[43]
    DIRECTION INPUT ;
    USE SIGNAL ;
    PORT
      LAYER M4 ;
        RECT  62.856 22.032 63.048 22.056 ;
    END
  END di0[43]
  PIN di0[440]
    DIRECTION INPUT ;
    USE SIGNAL ;
    PORT
      LAYER M4 ;
        RECT  62.856 41.088 63.048 41.112 ;
    END
  END di0[440]
  PIN di0[441]
    DIRECTION INPUT ;
    USE SIGNAL ;
    PORT
      LAYER M4 ;
        RECT  62.856 41.136 63.048 41.16 ;
    END
  END di0[441]
  PIN di0[442]
    DIRECTION INPUT ;
    USE SIGNAL ;
    PORT
      LAYER M4 ;
        RECT  62.856 41.184 63.048 41.208 ;
    END
  END di0[442]
  PIN di0[443]
    DIRECTION INPUT ;
    USE SIGNAL ;
    PORT
      LAYER M4 ;
        RECT  62.856 41.232 63.048 41.256 ;
    END
  END di0[443]
  PIN di0[444]
    DIRECTION INPUT ;
    USE SIGNAL ;
    PORT
      LAYER M4 ;
        RECT  62.856 41.28 63.048 41.304 ;
    END
  END di0[444]
  PIN di0[445]
    DIRECTION INPUT ;
    USE SIGNAL ;
    PORT
      LAYER M4 ;
        RECT  62.856 41.328 63.048 41.352 ;
    END
  END di0[445]
  PIN di0[446]
    DIRECTION INPUT ;
    USE SIGNAL ;
    PORT
      LAYER M4 ;
        RECT  62.856 41.376 63.048 41.4 ;
    END
  END di0[446]
  PIN di0[447]
    DIRECTION INPUT ;
    USE SIGNAL ;
    PORT
      LAYER M4 ;
        RECT  62.856 41.424 63.048 41.448 ;
    END
  END di0[447]
  PIN di0[448]
    DIRECTION INPUT ;
    USE SIGNAL ;
    PORT
      LAYER M4 ;
        RECT  62.856 41.472 63.048 41.496 ;
    END
  END di0[448]
  PIN di0[449]
    DIRECTION INPUT ;
    USE SIGNAL ;
    PORT
      LAYER M4 ;
        RECT  62.856 41.52 63.048 41.544 ;
    END
  END di0[449]
  PIN di0[44]
    DIRECTION INPUT ;
    USE SIGNAL ;
    PORT
      LAYER M4 ;
        RECT  62.856 22.08 63.048 22.104 ;
    END
  END di0[44]
  PIN di0[450]
    DIRECTION INPUT ;
    USE SIGNAL ;
    PORT
      LAYER M4 ;
        RECT  62.856 41.568 63.048 41.592 ;
    END
  END di0[450]
  PIN di0[451]
    DIRECTION INPUT ;
    USE SIGNAL ;
    PORT
      LAYER M4 ;
        RECT  62.856 41.616 63.048 41.64 ;
    END
  END di0[451]
  PIN di0[452]
    DIRECTION INPUT ;
    USE SIGNAL ;
    PORT
      LAYER M4 ;
        RECT  62.856 41.664 63.048 41.688 ;
    END
  END di0[452]
  PIN di0[453]
    DIRECTION INPUT ;
    USE SIGNAL ;
    PORT
      LAYER M4 ;
        RECT  62.856 41.712 63.048 41.736 ;
    END
  END di0[453]
  PIN di0[454]
    DIRECTION INPUT ;
    USE SIGNAL ;
    PORT
      LAYER M4 ;
        RECT  62.856 41.76 63.048 41.784 ;
    END
  END di0[454]
  PIN di0[455]
    DIRECTION INPUT ;
    USE SIGNAL ;
    PORT
      LAYER M4 ;
        RECT  62.856 41.808 63.048 41.832 ;
    END
  END di0[455]
  PIN di0[456]
    DIRECTION INPUT ;
    USE SIGNAL ;
    PORT
      LAYER M4 ;
        RECT  62.856 41.856 63.048 41.88 ;
    END
  END di0[456]
  PIN di0[457]
    DIRECTION INPUT ;
    USE SIGNAL ;
    PORT
      LAYER M4 ;
        RECT  62.856 41.904 63.048 41.928 ;
    END
  END di0[457]
  PIN di0[458]
    DIRECTION INPUT ;
    USE SIGNAL ;
    PORT
      LAYER M4 ;
        RECT  62.856 41.952 63.048 41.976 ;
    END
  END di0[458]
  PIN di0[459]
    DIRECTION INPUT ;
    USE SIGNAL ;
    PORT
      LAYER M4 ;
        RECT  62.856 42 63.048 42.024 ;
    END
  END di0[459]
  PIN di0[45]
    DIRECTION INPUT ;
    USE SIGNAL ;
    PORT
      LAYER M4 ;
        RECT  62.856 22.128 63.048 22.152 ;
    END
  END di0[45]
  PIN di0[460]
    DIRECTION INPUT ;
    USE SIGNAL ;
    PORT
      LAYER M4 ;
        RECT  62.856 42.048 63.048 42.072 ;
    END
  END di0[460]
  PIN di0[461]
    DIRECTION INPUT ;
    USE SIGNAL ;
    PORT
      LAYER M4 ;
        RECT  62.856 42.096 63.048 42.12 ;
    END
  END di0[461]
  PIN di0[462]
    DIRECTION INPUT ;
    USE SIGNAL ;
    PORT
      LAYER M4 ;
        RECT  62.856 42.144 63.048 42.168 ;
    END
  END di0[462]
  PIN di0[463]
    DIRECTION INPUT ;
    USE SIGNAL ;
    PORT
      LAYER M4 ;
        RECT  62.856 42.192 63.048 42.216 ;
    END
  END di0[463]
  PIN di0[464]
    DIRECTION INPUT ;
    USE SIGNAL ;
    PORT
      LAYER M4 ;
        RECT  62.856 42.24 63.048 42.264 ;
    END
  END di0[464]
  PIN di0[465]
    DIRECTION INPUT ;
    USE SIGNAL ;
    PORT
      LAYER M4 ;
        RECT  62.856 42.288 63.048 42.312 ;
    END
  END di0[465]
  PIN di0[466]
    DIRECTION INPUT ;
    USE SIGNAL ;
    PORT
      LAYER M4 ;
        RECT  62.856 42.336 63.048 42.36 ;
    END
  END di0[466]
  PIN di0[467]
    DIRECTION INPUT ;
    USE SIGNAL ;
    PORT
      LAYER M4 ;
        RECT  62.856 42.384 63.048 42.408 ;
    END
  END di0[467]
  PIN di0[468]
    DIRECTION INPUT ;
    USE SIGNAL ;
    PORT
      LAYER M4 ;
        RECT  62.856 42.432 63.048 42.456 ;
    END
  END di0[468]
  PIN di0[469]
    DIRECTION INPUT ;
    USE SIGNAL ;
    PORT
      LAYER M4 ;
        RECT  62.856 42.48 63.048 42.504 ;
    END
  END di0[469]
  PIN di0[46]
    DIRECTION INPUT ;
    USE SIGNAL ;
    PORT
      LAYER M4 ;
        RECT  62.856 22.176 63.048 22.2 ;
    END
  END di0[46]
  PIN di0[470]
    DIRECTION INPUT ;
    USE SIGNAL ;
    PORT
      LAYER M4 ;
        RECT  62.856 42.528 63.048 42.552 ;
    END
  END di0[470]
  PIN di0[471]
    DIRECTION INPUT ;
    USE SIGNAL ;
    PORT
      LAYER M4 ;
        RECT  62.856 42.576 63.048 42.6 ;
    END
  END di0[471]
  PIN di0[472]
    DIRECTION INPUT ;
    USE SIGNAL ;
    PORT
      LAYER M4 ;
        RECT  62.856 42.624 63.048 42.648 ;
    END
  END di0[472]
  PIN di0[473]
    DIRECTION INPUT ;
    USE SIGNAL ;
    PORT
      LAYER M4 ;
        RECT  62.856 42.672 63.048 42.696 ;
    END
  END di0[473]
  PIN di0[474]
    DIRECTION INPUT ;
    USE SIGNAL ;
    PORT
      LAYER M4 ;
        RECT  62.856 42.72 63.048 42.744 ;
    END
  END di0[474]
  PIN di0[475]
    DIRECTION INPUT ;
    USE SIGNAL ;
    PORT
      LAYER M4 ;
        RECT  62.856 42.768 63.048 42.792 ;
    END
  END di0[475]
  PIN di0[476]
    DIRECTION INPUT ;
    USE SIGNAL ;
    PORT
      LAYER M4 ;
        RECT  62.856 42.816 63.048 42.84 ;
    END
  END di0[476]
  PIN di0[477]
    DIRECTION INPUT ;
    USE SIGNAL ;
    PORT
      LAYER M4 ;
        RECT  62.856 42.864 63.048 42.888 ;
    END
  END di0[477]
  PIN di0[478]
    DIRECTION INPUT ;
    USE SIGNAL ;
    PORT
      LAYER M4 ;
        RECT  62.856 42.912 63.048 42.936 ;
    END
  END di0[478]
  PIN di0[479]
    DIRECTION INPUT ;
    USE SIGNAL ;
    PORT
      LAYER M4 ;
        RECT  62.856 42.96 63.048 42.984 ;
    END
  END di0[479]
  PIN di0[47]
    DIRECTION INPUT ;
    USE SIGNAL ;
    PORT
      LAYER M4 ;
        RECT  62.856 22.224 63.048 22.248 ;
    END
  END di0[47]
  PIN di0[480]
    DIRECTION INPUT ;
    USE SIGNAL ;
    PORT
      LAYER M4 ;
        RECT  62.856 43.008 63.048 43.032 ;
    END
  END di0[480]
  PIN di0[481]
    DIRECTION INPUT ;
    USE SIGNAL ;
    PORT
      LAYER M4 ;
        RECT  62.856 43.056 63.048 43.08 ;
    END
  END di0[481]
  PIN di0[482]
    DIRECTION INPUT ;
    USE SIGNAL ;
    PORT
      LAYER M4 ;
        RECT  62.856 43.104 63.048 43.128 ;
    END
  END di0[482]
  PIN di0[483]
    DIRECTION INPUT ;
    USE SIGNAL ;
    PORT
      LAYER M4 ;
        RECT  62.856 43.152 63.048 43.176 ;
    END
  END di0[483]
  PIN di0[484]
    DIRECTION INPUT ;
    USE SIGNAL ;
    PORT
      LAYER M4 ;
        RECT  62.856 43.2 63.048 43.224 ;
    END
  END di0[484]
  PIN di0[485]
    DIRECTION INPUT ;
    USE SIGNAL ;
    PORT
      LAYER M4 ;
        RECT  62.856 43.248 63.048 43.272 ;
    END
  END di0[485]
  PIN di0[486]
    DIRECTION INPUT ;
    USE SIGNAL ;
    PORT
      LAYER M4 ;
        RECT  62.856 43.296 63.048 43.32 ;
    END
  END di0[486]
  PIN di0[487]
    DIRECTION INPUT ;
    USE SIGNAL ;
    PORT
      LAYER M4 ;
        RECT  62.856 43.344 63.048 43.368 ;
    END
  END di0[487]
  PIN di0[488]
    DIRECTION INPUT ;
    USE SIGNAL ;
    PORT
      LAYER M4 ;
        RECT  62.856 43.392 63.048 43.416 ;
    END
  END di0[488]
  PIN di0[489]
    DIRECTION INPUT ;
    USE SIGNAL ;
    PORT
      LAYER M4 ;
        RECT  62.856 43.44 63.048 43.464 ;
    END
  END di0[489]
  PIN di0[48]
    DIRECTION INPUT ;
    USE SIGNAL ;
    PORT
      LAYER M4 ;
        RECT  62.856 22.272 63.048 22.296 ;
    END
  END di0[48]
  PIN di0[490]
    DIRECTION INPUT ;
    USE SIGNAL ;
    PORT
      LAYER M4 ;
        RECT  62.856 43.488 63.048 43.512 ;
    END
  END di0[490]
  PIN di0[491]
    DIRECTION INPUT ;
    USE SIGNAL ;
    PORT
      LAYER M4 ;
        RECT  62.856 43.536 63.048 43.56 ;
    END
  END di0[491]
  PIN di0[492]
    DIRECTION INPUT ;
    USE SIGNAL ;
    PORT
      LAYER M4 ;
        RECT  62.856 43.584 63.048 43.608 ;
    END
  END di0[492]
  PIN di0[493]
    DIRECTION INPUT ;
    USE SIGNAL ;
    PORT
      LAYER M4 ;
        RECT  62.856 43.632 63.048 43.656 ;
    END
  END di0[493]
  PIN di0[494]
    DIRECTION INPUT ;
    USE SIGNAL ;
    PORT
      LAYER M4 ;
        RECT  62.856 43.68 63.048 43.704 ;
    END
  END di0[494]
  PIN di0[495]
    DIRECTION INPUT ;
    USE SIGNAL ;
    PORT
      LAYER M4 ;
        RECT  62.856 43.728 63.048 43.752 ;
    END
  END di0[495]
  PIN di0[496]
    DIRECTION INPUT ;
    USE SIGNAL ;
    PORT
      LAYER M4 ;
        RECT  62.856 43.776 63.048 43.8 ;
    END
  END di0[496]
  PIN di0[497]
    DIRECTION INPUT ;
    USE SIGNAL ;
    PORT
      LAYER M4 ;
        RECT  62.856 43.824 63.048 43.848 ;
    END
  END di0[497]
  PIN di0[498]
    DIRECTION INPUT ;
    USE SIGNAL ;
    PORT
      LAYER M4 ;
        RECT  62.856 43.872 63.048 43.896 ;
    END
  END di0[498]
  PIN di0[499]
    DIRECTION INPUT ;
    USE SIGNAL ;
    PORT
      LAYER M4 ;
        RECT  62.856 43.92 63.048 43.944 ;
    END
  END di0[499]
  PIN di0[49]
    DIRECTION INPUT ;
    USE SIGNAL ;
    PORT
      LAYER M4 ;
        RECT  62.856 22.32 63.048 22.344 ;
    END
  END di0[49]
  PIN di0[4]
    DIRECTION INPUT ;
    USE SIGNAL ;
    PORT
      LAYER M4 ;
        RECT  62.856 20.16 63.048 20.184 ;
    END
  END di0[4]
  PIN di0[500]
    DIRECTION INPUT ;
    USE SIGNAL ;
    PORT
      LAYER M4 ;
        RECT  62.856 43.968 63.048 43.992 ;
    END
  END di0[500]
  PIN di0[501]
    DIRECTION INPUT ;
    USE SIGNAL ;
    PORT
      LAYER M4 ;
        RECT  62.856 44.016 63.048 44.04 ;
    END
  END di0[501]
  PIN di0[502]
    DIRECTION INPUT ;
    USE SIGNAL ;
    PORT
      LAYER M4 ;
        RECT  62.856 44.064 63.048 44.088 ;
    END
  END di0[502]
  PIN di0[503]
    DIRECTION INPUT ;
    USE SIGNAL ;
    PORT
      LAYER M4 ;
        RECT  62.856 44.112 63.048 44.136 ;
    END
  END di0[503]
  PIN di0[504]
    DIRECTION INPUT ;
    USE SIGNAL ;
    PORT
      LAYER M4 ;
        RECT  62.856 44.16 63.048 44.184 ;
    END
  END di0[504]
  PIN di0[505]
    DIRECTION INPUT ;
    USE SIGNAL ;
    PORT
      LAYER M4 ;
        RECT  62.856 44.208 63.048 44.232 ;
    END
  END di0[505]
  PIN di0[506]
    DIRECTION INPUT ;
    USE SIGNAL ;
    PORT
      LAYER M4 ;
        RECT  62.856 44.256 63.048 44.28 ;
    END
  END di0[506]
  PIN di0[507]
    DIRECTION INPUT ;
    USE SIGNAL ;
    PORT
      LAYER M4 ;
        RECT  62.856 44.304 63.048 44.328 ;
    END
  END di0[507]
  PIN di0[508]
    DIRECTION INPUT ;
    USE SIGNAL ;
    PORT
      LAYER M4 ;
        RECT  62.856 44.352 63.048 44.376 ;
    END
  END di0[508]
  PIN di0[509]
    DIRECTION INPUT ;
    USE SIGNAL ;
    PORT
      LAYER M4 ;
        RECT  62.856 44.4 63.048 44.424 ;
    END
  END di0[509]
  PIN di0[50]
    DIRECTION INPUT ;
    USE SIGNAL ;
    PORT
      LAYER M4 ;
        RECT  62.856 22.368 63.048 22.392 ;
    END
  END di0[50]
  PIN di0[510]
    DIRECTION INPUT ;
    USE SIGNAL ;
    PORT
      LAYER M4 ;
        RECT  62.856 44.448 63.048 44.472 ;
    END
  END di0[510]
  PIN di0[511]
    DIRECTION INPUT ;
    USE SIGNAL ;
    PORT
      LAYER M4 ;
        RECT  62.856 44.496 63.048 44.52 ;
    END
  END di0[511]
  PIN di0[512]
    DIRECTION INPUT ;
    USE SIGNAL ;
    PORT
      LAYER M4 ;
        RECT  62.856 44.544 63.048 44.568 ;
    END
  END di0[512]
  PIN di0[513]
    DIRECTION INPUT ;
    USE SIGNAL ;
    PORT
      LAYER M4 ;
        RECT  62.856 44.592 63.048 44.616 ;
    END
  END di0[513]
  PIN di0[51]
    DIRECTION INPUT ;
    USE SIGNAL ;
    PORT
      LAYER M4 ;
        RECT  62.856 22.416 63.048 22.44 ;
    END
  END di0[51]
  PIN di0[52]
    DIRECTION INPUT ;
    USE SIGNAL ;
    PORT
      LAYER M4 ;
        RECT  62.856 22.464 63.048 22.488 ;
    END
  END di0[52]
  PIN di0[53]
    DIRECTION INPUT ;
    USE SIGNAL ;
    PORT
      LAYER M4 ;
        RECT  62.856 22.512 63.048 22.536 ;
    END
  END di0[53]
  PIN di0[54]
    DIRECTION INPUT ;
    USE SIGNAL ;
    PORT
      LAYER M4 ;
        RECT  62.856 22.56 63.048 22.584 ;
    END
  END di0[54]
  PIN di0[55]
    DIRECTION INPUT ;
    USE SIGNAL ;
    PORT
      LAYER M4 ;
        RECT  62.856 22.608 63.048 22.632 ;
    END
  END di0[55]
  PIN di0[56]
    DIRECTION INPUT ;
    USE SIGNAL ;
    PORT
      LAYER M4 ;
        RECT  62.856 22.656 63.048 22.68 ;
    END
  END di0[56]
  PIN di0[57]
    DIRECTION INPUT ;
    USE SIGNAL ;
    PORT
      LAYER M4 ;
        RECT  62.856 22.704 63.048 22.728 ;
    END
  END di0[57]
  PIN di0[58]
    DIRECTION INPUT ;
    USE SIGNAL ;
    PORT
      LAYER M4 ;
        RECT  62.856 22.752 63.048 22.776 ;
    END
  END di0[58]
  PIN di0[59]
    DIRECTION INPUT ;
    USE SIGNAL ;
    PORT
      LAYER M4 ;
        RECT  62.856 22.8 63.048 22.824 ;
    END
  END di0[59]
  PIN di0[5]
    DIRECTION INPUT ;
    USE SIGNAL ;
    PORT
      LAYER M4 ;
        RECT  62.856 20.208 63.048 20.232 ;
    END
  END di0[5]
  PIN di0[60]
    DIRECTION INPUT ;
    USE SIGNAL ;
    PORT
      LAYER M4 ;
        RECT  62.856 22.848 63.048 22.872 ;
    END
  END di0[60]
  PIN di0[61]
    DIRECTION INPUT ;
    USE SIGNAL ;
    PORT
      LAYER M4 ;
        RECT  62.856 22.896 63.048 22.92 ;
    END
  END di0[61]
  PIN di0[62]
    DIRECTION INPUT ;
    USE SIGNAL ;
    PORT
      LAYER M4 ;
        RECT  62.856 22.944 63.048 22.968 ;
    END
  END di0[62]
  PIN di0[63]
    DIRECTION INPUT ;
    USE SIGNAL ;
    PORT
      LAYER M4 ;
        RECT  62.856 22.992 63.048 23.016 ;
    END
  END di0[63]
  PIN di0[64]
    DIRECTION INPUT ;
    USE SIGNAL ;
    PORT
      LAYER M4 ;
        RECT  62.856 23.04 63.048 23.064 ;
    END
  END di0[64]
  PIN di0[65]
    DIRECTION INPUT ;
    USE SIGNAL ;
    PORT
      LAYER M4 ;
        RECT  62.856 23.088 63.048 23.112 ;
    END
  END di0[65]
  PIN di0[66]
    DIRECTION INPUT ;
    USE SIGNAL ;
    PORT
      LAYER M4 ;
        RECT  62.856 23.136 63.048 23.16 ;
    END
  END di0[66]
  PIN di0[67]
    DIRECTION INPUT ;
    USE SIGNAL ;
    PORT
      LAYER M4 ;
        RECT  62.856 23.184 63.048 23.208 ;
    END
  END di0[67]
  PIN di0[68]
    DIRECTION INPUT ;
    USE SIGNAL ;
    PORT
      LAYER M4 ;
        RECT  62.856 23.232 63.048 23.256 ;
    END
  END di0[68]
  PIN di0[69]
    DIRECTION INPUT ;
    USE SIGNAL ;
    PORT
      LAYER M4 ;
        RECT  62.856 23.28 63.048 23.304 ;
    END
  END di0[69]
  PIN di0[6]
    DIRECTION INPUT ;
    USE SIGNAL ;
    PORT
      LAYER M4 ;
        RECT  62.856 20.256 63.048 20.28 ;
    END
  END di0[6]
  PIN di0[70]
    DIRECTION INPUT ;
    USE SIGNAL ;
    PORT
      LAYER M4 ;
        RECT  62.856 23.328 63.048 23.352 ;
    END
  END di0[70]
  PIN di0[71]
    DIRECTION INPUT ;
    USE SIGNAL ;
    PORT
      LAYER M4 ;
        RECT  62.856 23.376 63.048 23.4 ;
    END
  END di0[71]
  PIN di0[72]
    DIRECTION INPUT ;
    USE SIGNAL ;
    PORT
      LAYER M4 ;
        RECT  62.856 23.424 63.048 23.448 ;
    END
  END di0[72]
  PIN di0[73]
    DIRECTION INPUT ;
    USE SIGNAL ;
    PORT
      LAYER M4 ;
        RECT  62.856 23.472 63.048 23.496 ;
    END
  END di0[73]
  PIN di0[74]
    DIRECTION INPUT ;
    USE SIGNAL ;
    PORT
      LAYER M4 ;
        RECT  62.856 23.52 63.048 23.544 ;
    END
  END di0[74]
  PIN di0[75]
    DIRECTION INPUT ;
    USE SIGNAL ;
    PORT
      LAYER M4 ;
        RECT  62.856 23.568 63.048 23.592 ;
    END
  END di0[75]
  PIN di0[76]
    DIRECTION INPUT ;
    USE SIGNAL ;
    PORT
      LAYER M4 ;
        RECT  62.856 23.616 63.048 23.64 ;
    END
  END di0[76]
  PIN di0[77]
    DIRECTION INPUT ;
    USE SIGNAL ;
    PORT
      LAYER M4 ;
        RECT  62.856 23.664 63.048 23.688 ;
    END
  END di0[77]
  PIN di0[78]
    DIRECTION INPUT ;
    USE SIGNAL ;
    PORT
      LAYER M4 ;
        RECT  62.856 23.712 63.048 23.736 ;
    END
  END di0[78]
  PIN di0[79]
    DIRECTION INPUT ;
    USE SIGNAL ;
    PORT
      LAYER M4 ;
        RECT  62.856 23.76 63.048 23.784 ;
    END
  END di0[79]
  PIN di0[7]
    DIRECTION INPUT ;
    USE SIGNAL ;
    PORT
      LAYER M4 ;
        RECT  62.856 20.304 63.048 20.328 ;
    END
  END di0[7]
  PIN di0[80]
    DIRECTION INPUT ;
    USE SIGNAL ;
    PORT
      LAYER M4 ;
        RECT  62.856 23.808 63.048 23.832 ;
    END
  END di0[80]
  PIN di0[81]
    DIRECTION INPUT ;
    USE SIGNAL ;
    PORT
      LAYER M4 ;
        RECT  62.856 23.856 63.048 23.88 ;
    END
  END di0[81]
  PIN di0[82]
    DIRECTION INPUT ;
    USE SIGNAL ;
    PORT
      LAYER M4 ;
        RECT  62.856 23.904 63.048 23.928 ;
    END
  END di0[82]
  PIN di0[83]
    DIRECTION INPUT ;
    USE SIGNAL ;
    PORT
      LAYER M4 ;
        RECT  62.856 23.952 63.048 23.976 ;
    END
  END di0[83]
  PIN di0[84]
    DIRECTION INPUT ;
    USE SIGNAL ;
    PORT
      LAYER M4 ;
        RECT  62.856 24 63.048 24.024 ;
    END
  END di0[84]
  PIN di0[85]
    DIRECTION INPUT ;
    USE SIGNAL ;
    PORT
      LAYER M4 ;
        RECT  62.856 24.048 63.048 24.072 ;
    END
  END di0[85]
  PIN di0[86]
    DIRECTION INPUT ;
    USE SIGNAL ;
    PORT
      LAYER M4 ;
        RECT  62.856 24.096 63.048 24.12 ;
    END
  END di0[86]
  PIN di0[87]
    DIRECTION INPUT ;
    USE SIGNAL ;
    PORT
      LAYER M4 ;
        RECT  62.856 24.144 63.048 24.168 ;
    END
  END di0[87]
  PIN di0[88]
    DIRECTION INPUT ;
    USE SIGNAL ;
    PORT
      LAYER M4 ;
        RECT  62.856 24.192 63.048 24.216 ;
    END
  END di0[88]
  PIN di0[89]
    DIRECTION INPUT ;
    USE SIGNAL ;
    PORT
      LAYER M4 ;
        RECT  62.856 24.24 63.048 24.264 ;
    END
  END di0[89]
  PIN di0[8]
    DIRECTION INPUT ;
    USE SIGNAL ;
    PORT
      LAYER M4 ;
        RECT  62.856 20.352 63.048 20.376 ;
    END
  END di0[8]
  PIN di0[90]
    DIRECTION INPUT ;
    USE SIGNAL ;
    PORT
      LAYER M4 ;
        RECT  62.856 24.288 63.048 24.312 ;
    END
  END di0[90]
  PIN di0[91]
    DIRECTION INPUT ;
    USE SIGNAL ;
    PORT
      LAYER M4 ;
        RECT  62.856 24.336 63.048 24.36 ;
    END
  END di0[91]
  PIN di0[92]
    DIRECTION INPUT ;
    USE SIGNAL ;
    PORT
      LAYER M4 ;
        RECT  62.856 24.384 63.048 24.408 ;
    END
  END di0[92]
  PIN di0[93]
    DIRECTION INPUT ;
    USE SIGNAL ;
    PORT
      LAYER M4 ;
        RECT  62.856 24.432 63.048 24.456 ;
    END
  END di0[93]
  PIN di0[94]
    DIRECTION INPUT ;
    USE SIGNAL ;
    PORT
      LAYER M4 ;
        RECT  62.856 24.48 63.048 24.504 ;
    END
  END di0[94]
  PIN di0[95]
    DIRECTION INPUT ;
    USE SIGNAL ;
    PORT
      LAYER M4 ;
        RECT  62.856 24.528 63.048 24.552 ;
    END
  END di0[95]
  PIN di0[96]
    DIRECTION INPUT ;
    USE SIGNAL ;
    PORT
      LAYER M4 ;
        RECT  62.856 24.576 63.048 24.6 ;
    END
  END di0[96]
  PIN di0[97]
    DIRECTION INPUT ;
    USE SIGNAL ;
    PORT
      LAYER M4 ;
        RECT  62.856 24.624 63.048 24.648 ;
    END
  END di0[97]
  PIN di0[98]
    DIRECTION INPUT ;
    USE SIGNAL ;
    PORT
      LAYER M4 ;
        RECT  62.856 24.672 63.048 24.696 ;
    END
  END di0[98]
  PIN di0[99]
    DIRECTION INPUT ;
    USE SIGNAL ;
    PORT
      LAYER M4 ;
        RECT  62.856 24.72 63.048 24.744 ;
    END
  END di0[99]
  PIN di0[9]
    DIRECTION INPUT ;
    USE SIGNAL ;
    PORT
      LAYER M4 ;
        RECT  62.856 20.4 63.048 20.424 ;
    END
  END di0[9]
  PIN fi0[0]
    DIRECTION INPUT ;
    USE SIGNAL ;
    PORT
      LAYER M4 ;
        RECT  62.856 44.784 63.048 44.808 ;
    END
  END fi0[0]
  PIN o[0]
    DIRECTION OUTPUT ;
    USE SIGNAL ;
    PORT
      LAYER M5 ;
        RECT  19.152 0 19.176 0.192 ;
    END
  END o[0]
  PIN o[100]
    DIRECTION OUTPUT ;
    USE SIGNAL ;
    PORT
      LAYER M5 ;
        RECT  23.952 0 23.976 0.192 ;
    END
  END o[100]
  PIN o[101]
    DIRECTION OUTPUT ;
    USE SIGNAL ;
    PORT
      LAYER M5 ;
        RECT  24 0 24.024 0.192 ;
    END
  END o[101]
  PIN o[102]
    DIRECTION OUTPUT ;
    USE SIGNAL ;
    PORT
      LAYER M5 ;
        RECT  24.048 0 24.072 0.192 ;
    END
  END o[102]
  PIN o[103]
    DIRECTION OUTPUT ;
    USE SIGNAL ;
    PORT
      LAYER M5 ;
        RECT  24.096 0 24.12 0.192 ;
    END
  END o[103]
  PIN o[104]
    DIRECTION OUTPUT ;
    USE SIGNAL ;
    PORT
      LAYER M5 ;
        RECT  24.144 0 24.168 0.192 ;
    END
  END o[104]
  PIN o[105]
    DIRECTION OUTPUT ;
    USE SIGNAL ;
    PORT
      LAYER M5 ;
        RECT  24.192 0 24.216 0.192 ;
    END
  END o[105]
  PIN o[106]
    DIRECTION OUTPUT ;
    USE SIGNAL ;
    PORT
      LAYER M5 ;
        RECT  24.24 0 24.264 0.192 ;
    END
  END o[106]
  PIN o[107]
    DIRECTION OUTPUT ;
    USE SIGNAL ;
    PORT
      LAYER M5 ;
        RECT  24.288 0 24.312 0.192 ;
    END
  END o[107]
  PIN o[108]
    DIRECTION OUTPUT ;
    USE SIGNAL ;
    PORT
      LAYER M5 ;
        RECT  24.336 0 24.36 0.192 ;
    END
  END o[108]
  PIN o[109]
    DIRECTION OUTPUT ;
    USE SIGNAL ;
    PORT
      LAYER M5 ;
        RECT  24.384 0 24.408 0.192 ;
    END
  END o[109]
  PIN o[10]
    DIRECTION OUTPUT ;
    USE SIGNAL ;
    PORT
      LAYER M5 ;
        RECT  19.632 0 19.656 0.192 ;
    END
  END o[10]
  PIN o[110]
    DIRECTION OUTPUT ;
    USE SIGNAL ;
    PORT
      LAYER M5 ;
        RECT  24.432 0 24.456 0.192 ;
    END
  END o[110]
  PIN o[111]
    DIRECTION OUTPUT ;
    USE SIGNAL ;
    PORT
      LAYER M5 ;
        RECT  24.48 0 24.504 0.192 ;
    END
  END o[111]
  PIN o[112]
    DIRECTION OUTPUT ;
    USE SIGNAL ;
    PORT
      LAYER M5 ;
        RECT  24.528 0 24.552 0.192 ;
    END
  END o[112]
  PIN o[113]
    DIRECTION OUTPUT ;
    USE SIGNAL ;
    PORT
      LAYER M5 ;
        RECT  24.576 0 24.6 0.192 ;
    END
  END o[113]
  PIN o[114]
    DIRECTION OUTPUT ;
    USE SIGNAL ;
    PORT
      LAYER M5 ;
        RECT  24.624 0 24.648 0.192 ;
    END
  END o[114]
  PIN o[115]
    DIRECTION OUTPUT ;
    USE SIGNAL ;
    PORT
      LAYER M5 ;
        RECT  24.672 0 24.696 0.192 ;
    END
  END o[115]
  PIN o[116]
    DIRECTION OUTPUT ;
    USE SIGNAL ;
    PORT
      LAYER M5 ;
        RECT  24.72 0 24.744 0.192 ;
    END
  END o[116]
  PIN o[117]
    DIRECTION OUTPUT ;
    USE SIGNAL ;
    PORT
      LAYER M5 ;
        RECT  24.768 0 24.792 0.192 ;
    END
  END o[117]
  PIN o[118]
    DIRECTION OUTPUT ;
    USE SIGNAL ;
    PORT
      LAYER M5 ;
        RECT  24.816 0 24.84 0.192 ;
    END
  END o[118]
  PIN o[119]
    DIRECTION OUTPUT ;
    USE SIGNAL ;
    PORT
      LAYER M5 ;
        RECT  24.864 0 24.888 0.192 ;
    END
  END o[119]
  PIN o[11]
    DIRECTION OUTPUT ;
    USE SIGNAL ;
    PORT
      LAYER M5 ;
        RECT  19.68 0 19.704 0.192 ;
    END
  END o[11]
  PIN o[120]
    DIRECTION OUTPUT ;
    USE SIGNAL ;
    PORT
      LAYER M5 ;
        RECT  24.912 0 24.936 0.192 ;
    END
  END o[120]
  PIN o[121]
    DIRECTION OUTPUT ;
    USE SIGNAL ;
    PORT
      LAYER M5 ;
        RECT  24.96 0 24.984 0.192 ;
    END
  END o[121]
  PIN o[122]
    DIRECTION OUTPUT ;
    USE SIGNAL ;
    PORT
      LAYER M5 ;
        RECT  25.008 0 25.032 0.192 ;
    END
  END o[122]
  PIN o[123]
    DIRECTION OUTPUT ;
    USE SIGNAL ;
    PORT
      LAYER M5 ;
        RECT  25.056 0 25.08 0.192 ;
    END
  END o[123]
  PIN o[124]
    DIRECTION OUTPUT ;
    USE SIGNAL ;
    PORT
      LAYER M5 ;
        RECT  25.104 0 25.128 0.192 ;
    END
  END o[124]
  PIN o[125]
    DIRECTION OUTPUT ;
    USE SIGNAL ;
    PORT
      LAYER M5 ;
        RECT  25.152 0 25.176 0.192 ;
    END
  END o[125]
  PIN o[126]
    DIRECTION OUTPUT ;
    USE SIGNAL ;
    PORT
      LAYER M5 ;
        RECT  25.2 0 25.224 0.192 ;
    END
  END o[126]
  PIN o[127]
    DIRECTION OUTPUT ;
    USE SIGNAL ;
    PORT
      LAYER M5 ;
        RECT  25.248 0 25.272 0.192 ;
    END
  END o[127]
  PIN o[128]
    DIRECTION OUTPUT ;
    USE SIGNAL ;
    PORT
      LAYER M5 ;
        RECT  25.296 0 25.32 0.192 ;
    END
  END o[128]
  PIN o[129]
    DIRECTION OUTPUT ;
    USE SIGNAL ;
    PORT
      LAYER M5 ;
        RECT  25.344 0 25.368 0.192 ;
    END
  END o[129]
  PIN o[12]
    DIRECTION OUTPUT ;
    USE SIGNAL ;
    PORT
      LAYER M5 ;
        RECT  19.728 0 19.752 0.192 ;
    END
  END o[12]
  PIN o[130]
    DIRECTION OUTPUT ;
    USE SIGNAL ;
    PORT
      LAYER M5 ;
        RECT  25.392 0 25.416 0.192 ;
    END
  END o[130]
  PIN o[131]
    DIRECTION OUTPUT ;
    USE SIGNAL ;
    PORT
      LAYER M5 ;
        RECT  25.44 0 25.464 0.192 ;
    END
  END o[131]
  PIN o[132]
    DIRECTION OUTPUT ;
    USE SIGNAL ;
    PORT
      LAYER M5 ;
        RECT  25.488 0 25.512 0.192 ;
    END
  END o[132]
  PIN o[133]
    DIRECTION OUTPUT ;
    USE SIGNAL ;
    PORT
      LAYER M5 ;
        RECT  25.536 0 25.56 0.192 ;
    END
  END o[133]
  PIN o[134]
    DIRECTION OUTPUT ;
    USE SIGNAL ;
    PORT
      LAYER M5 ;
        RECT  25.584 0 25.608 0.192 ;
    END
  END o[134]
  PIN o[135]
    DIRECTION OUTPUT ;
    USE SIGNAL ;
    PORT
      LAYER M5 ;
        RECT  25.632 0 25.656 0.192 ;
    END
  END o[135]
  PIN o[136]
    DIRECTION OUTPUT ;
    USE SIGNAL ;
    PORT
      LAYER M5 ;
        RECT  25.68 0 25.704 0.192 ;
    END
  END o[136]
  PIN o[137]
    DIRECTION OUTPUT ;
    USE SIGNAL ;
    PORT
      LAYER M5 ;
        RECT  25.728 0 25.752 0.192 ;
    END
  END o[137]
  PIN o[138]
    DIRECTION OUTPUT ;
    USE SIGNAL ;
    PORT
      LAYER M5 ;
        RECT  25.776 0 25.8 0.192 ;
    END
  END o[138]
  PIN o[139]
    DIRECTION OUTPUT ;
    USE SIGNAL ;
    PORT
      LAYER M5 ;
        RECT  25.824 0 25.848 0.192 ;
    END
  END o[139]
  PIN o[13]
    DIRECTION OUTPUT ;
    USE SIGNAL ;
    PORT
      LAYER M5 ;
        RECT  19.776 0 19.8 0.192 ;
    END
  END o[13]
  PIN o[140]
    DIRECTION OUTPUT ;
    USE SIGNAL ;
    PORT
      LAYER M5 ;
        RECT  25.872 0 25.896 0.192 ;
    END
  END o[140]
  PIN o[141]
    DIRECTION OUTPUT ;
    USE SIGNAL ;
    PORT
      LAYER M5 ;
        RECT  25.92 0 25.944 0.192 ;
    END
  END o[141]
  PIN o[142]
    DIRECTION OUTPUT ;
    USE SIGNAL ;
    PORT
      LAYER M5 ;
        RECT  25.968 0 25.992 0.192 ;
    END
  END o[142]
  PIN o[143]
    DIRECTION OUTPUT ;
    USE SIGNAL ;
    PORT
      LAYER M5 ;
        RECT  26.016 0 26.04 0.192 ;
    END
  END o[143]
  PIN o[144]
    DIRECTION OUTPUT ;
    USE SIGNAL ;
    PORT
      LAYER M5 ;
        RECT  26.064 0 26.088 0.192 ;
    END
  END o[144]
  PIN o[145]
    DIRECTION OUTPUT ;
    USE SIGNAL ;
    PORT
      LAYER M5 ;
        RECT  26.112 0 26.136 0.192 ;
    END
  END o[145]
  PIN o[146]
    DIRECTION OUTPUT ;
    USE SIGNAL ;
    PORT
      LAYER M5 ;
        RECT  26.16 0 26.184 0.192 ;
    END
  END o[146]
  PIN o[147]
    DIRECTION OUTPUT ;
    USE SIGNAL ;
    PORT
      LAYER M5 ;
        RECT  26.208 0 26.232 0.192 ;
    END
  END o[147]
  PIN o[148]
    DIRECTION OUTPUT ;
    USE SIGNAL ;
    PORT
      LAYER M5 ;
        RECT  26.256 0 26.28 0.192 ;
    END
  END o[148]
  PIN o[149]
    DIRECTION OUTPUT ;
    USE SIGNAL ;
    PORT
      LAYER M5 ;
        RECT  26.304 0 26.328 0.192 ;
    END
  END o[149]
  PIN o[14]
    DIRECTION OUTPUT ;
    USE SIGNAL ;
    PORT
      LAYER M5 ;
        RECT  19.824 0 19.848 0.192 ;
    END
  END o[14]
  PIN o[150]
    DIRECTION OUTPUT ;
    USE SIGNAL ;
    PORT
      LAYER M5 ;
        RECT  26.352 0 26.376 0.192 ;
    END
  END o[150]
  PIN o[151]
    DIRECTION OUTPUT ;
    USE SIGNAL ;
    PORT
      LAYER M5 ;
        RECT  26.4 0 26.424 0.192 ;
    END
  END o[151]
  PIN o[152]
    DIRECTION OUTPUT ;
    USE SIGNAL ;
    PORT
      LAYER M5 ;
        RECT  26.448 0 26.472 0.192 ;
    END
  END o[152]
  PIN o[153]
    DIRECTION OUTPUT ;
    USE SIGNAL ;
    PORT
      LAYER M5 ;
        RECT  26.496 0 26.52 0.192 ;
    END
  END o[153]
  PIN o[154]
    DIRECTION OUTPUT ;
    USE SIGNAL ;
    PORT
      LAYER M5 ;
        RECT  26.544 0 26.568 0.192 ;
    END
  END o[154]
  PIN o[155]
    DIRECTION OUTPUT ;
    USE SIGNAL ;
    PORT
      LAYER M5 ;
        RECT  26.592 0 26.616 0.192 ;
    END
  END o[155]
  PIN o[156]
    DIRECTION OUTPUT ;
    USE SIGNAL ;
    PORT
      LAYER M5 ;
        RECT  26.64 0 26.664 0.192 ;
    END
  END o[156]
  PIN o[157]
    DIRECTION OUTPUT ;
    USE SIGNAL ;
    PORT
      LAYER M5 ;
        RECT  26.688 0 26.712 0.192 ;
    END
  END o[157]
  PIN o[158]
    DIRECTION OUTPUT ;
    USE SIGNAL ;
    PORT
      LAYER M5 ;
        RECT  26.736 0 26.76 0.192 ;
    END
  END o[158]
  PIN o[159]
    DIRECTION OUTPUT ;
    USE SIGNAL ;
    PORT
      LAYER M5 ;
        RECT  26.784 0 26.808 0.192 ;
    END
  END o[159]
  PIN o[15]
    DIRECTION OUTPUT ;
    USE SIGNAL ;
    PORT
      LAYER M5 ;
        RECT  19.872 0 19.896 0.192 ;
    END
  END o[15]
  PIN o[160]
    DIRECTION OUTPUT ;
    USE SIGNAL ;
    PORT
      LAYER M5 ;
        RECT  26.832 0 26.856 0.192 ;
    END
  END o[160]
  PIN o[161]
    DIRECTION OUTPUT ;
    USE SIGNAL ;
    PORT
      LAYER M5 ;
        RECT  26.88 0 26.904 0.192 ;
    END
  END o[161]
  PIN o[162]
    DIRECTION OUTPUT ;
    USE SIGNAL ;
    PORT
      LAYER M5 ;
        RECT  26.928 0 26.952 0.192 ;
    END
  END o[162]
  PIN o[163]
    DIRECTION OUTPUT ;
    USE SIGNAL ;
    PORT
      LAYER M5 ;
        RECT  26.976 0 27 0.192 ;
    END
  END o[163]
  PIN o[164]
    DIRECTION OUTPUT ;
    USE SIGNAL ;
    PORT
      LAYER M5 ;
        RECT  27.024 0 27.048 0.192 ;
    END
  END o[164]
  PIN o[165]
    DIRECTION OUTPUT ;
    USE SIGNAL ;
    PORT
      LAYER M5 ;
        RECT  27.072 0 27.096 0.192 ;
    END
  END o[165]
  PIN o[166]
    DIRECTION OUTPUT ;
    USE SIGNAL ;
    PORT
      LAYER M5 ;
        RECT  27.12 0 27.144 0.192 ;
    END
  END o[166]
  PIN o[167]
    DIRECTION OUTPUT ;
    USE SIGNAL ;
    PORT
      LAYER M5 ;
        RECT  27.168 0 27.192 0.192 ;
    END
  END o[167]
  PIN o[168]
    DIRECTION OUTPUT ;
    USE SIGNAL ;
    PORT
      LAYER M5 ;
        RECT  27.216 0 27.24 0.192 ;
    END
  END o[168]
  PIN o[169]
    DIRECTION OUTPUT ;
    USE SIGNAL ;
    PORT
      LAYER M5 ;
        RECT  27.264 0 27.288 0.192 ;
    END
  END o[169]
  PIN o[16]
    DIRECTION OUTPUT ;
    USE SIGNAL ;
    PORT
      LAYER M5 ;
        RECT  19.92 0 19.944 0.192 ;
    END
  END o[16]
  PIN o[170]
    DIRECTION OUTPUT ;
    USE SIGNAL ;
    PORT
      LAYER M5 ;
        RECT  27.312 0 27.336 0.192 ;
    END
  END o[170]
  PIN o[171]
    DIRECTION OUTPUT ;
    USE SIGNAL ;
    PORT
      LAYER M5 ;
        RECT  27.36 0 27.384 0.192 ;
    END
  END o[171]
  PIN o[172]
    DIRECTION OUTPUT ;
    USE SIGNAL ;
    PORT
      LAYER M5 ;
        RECT  27.408 0 27.432 0.192 ;
    END
  END o[172]
  PIN o[173]
    DIRECTION OUTPUT ;
    USE SIGNAL ;
    PORT
      LAYER M5 ;
        RECT  27.456 0 27.48 0.192 ;
    END
  END o[173]
  PIN o[174]
    DIRECTION OUTPUT ;
    USE SIGNAL ;
    PORT
      LAYER M5 ;
        RECT  27.504 0 27.528 0.192 ;
    END
  END o[174]
  PIN o[175]
    DIRECTION OUTPUT ;
    USE SIGNAL ;
    PORT
      LAYER M5 ;
        RECT  27.552 0 27.576 0.192 ;
    END
  END o[175]
  PIN o[176]
    DIRECTION OUTPUT ;
    USE SIGNAL ;
    PORT
      LAYER M5 ;
        RECT  27.6 0 27.624 0.192 ;
    END
  END o[176]
  PIN o[177]
    DIRECTION OUTPUT ;
    USE SIGNAL ;
    PORT
      LAYER M5 ;
        RECT  27.648 0 27.672 0.192 ;
    END
  END o[177]
  PIN o[178]
    DIRECTION OUTPUT ;
    USE SIGNAL ;
    PORT
      LAYER M5 ;
        RECT  27.696 0 27.72 0.192 ;
    END
  END o[178]
  PIN o[179]
    DIRECTION OUTPUT ;
    USE SIGNAL ;
    PORT
      LAYER M5 ;
        RECT  27.744 0 27.768 0.192 ;
    END
  END o[179]
  PIN o[17]
    DIRECTION OUTPUT ;
    USE SIGNAL ;
    PORT
      LAYER M5 ;
        RECT  19.968 0 19.992 0.192 ;
    END
  END o[17]
  PIN o[180]
    DIRECTION OUTPUT ;
    USE SIGNAL ;
    PORT
      LAYER M5 ;
        RECT  27.792 0 27.816 0.192 ;
    END
  END o[180]
  PIN o[181]
    DIRECTION OUTPUT ;
    USE SIGNAL ;
    PORT
      LAYER M5 ;
        RECT  27.84 0 27.864 0.192 ;
    END
  END o[181]
  PIN o[182]
    DIRECTION OUTPUT ;
    USE SIGNAL ;
    PORT
      LAYER M5 ;
        RECT  27.888 0 27.912 0.192 ;
    END
  END o[182]
  PIN o[183]
    DIRECTION OUTPUT ;
    USE SIGNAL ;
    PORT
      LAYER M5 ;
        RECT  27.936 0 27.96 0.192 ;
    END
  END o[183]
  PIN o[184]
    DIRECTION OUTPUT ;
    USE SIGNAL ;
    PORT
      LAYER M5 ;
        RECT  27.984 0 28.008 0.192 ;
    END
  END o[184]
  PIN o[185]
    DIRECTION OUTPUT ;
    USE SIGNAL ;
    PORT
      LAYER M5 ;
        RECT  28.032 0 28.056 0.192 ;
    END
  END o[185]
  PIN o[186]
    DIRECTION OUTPUT ;
    USE SIGNAL ;
    PORT
      LAYER M5 ;
        RECT  28.08 0 28.104 0.192 ;
    END
  END o[186]
  PIN o[187]
    DIRECTION OUTPUT ;
    USE SIGNAL ;
    PORT
      LAYER M5 ;
        RECT  28.128 0 28.152 0.192 ;
    END
  END o[187]
  PIN o[188]
    DIRECTION OUTPUT ;
    USE SIGNAL ;
    PORT
      LAYER M5 ;
        RECT  28.176 0 28.2 0.192 ;
    END
  END o[188]
  PIN o[189]
    DIRECTION OUTPUT ;
    USE SIGNAL ;
    PORT
      LAYER M5 ;
        RECT  28.224 0 28.248 0.192 ;
    END
  END o[189]
  PIN o[18]
    DIRECTION OUTPUT ;
    USE SIGNAL ;
    PORT
      LAYER M5 ;
        RECT  20.016 0 20.04 0.192 ;
    END
  END o[18]
  PIN o[190]
    DIRECTION OUTPUT ;
    USE SIGNAL ;
    PORT
      LAYER M5 ;
        RECT  28.272 0 28.296 0.192 ;
    END
  END o[190]
  PIN o[191]
    DIRECTION OUTPUT ;
    USE SIGNAL ;
    PORT
      LAYER M5 ;
        RECT  28.32 0 28.344 0.192 ;
    END
  END o[191]
  PIN o[192]
    DIRECTION OUTPUT ;
    USE SIGNAL ;
    PORT
      LAYER M5 ;
        RECT  28.368 0 28.392 0.192 ;
    END
  END o[192]
  PIN o[193]
    DIRECTION OUTPUT ;
    USE SIGNAL ;
    PORT
      LAYER M5 ;
        RECT  28.416 0 28.44 0.192 ;
    END
  END o[193]
  PIN o[194]
    DIRECTION OUTPUT ;
    USE SIGNAL ;
    PORT
      LAYER M5 ;
        RECT  28.464 0 28.488 0.192 ;
    END
  END o[194]
  PIN o[195]
    DIRECTION OUTPUT ;
    USE SIGNAL ;
    PORT
      LAYER M5 ;
        RECT  28.512 0 28.536 0.192 ;
    END
  END o[195]
  PIN o[196]
    DIRECTION OUTPUT ;
    USE SIGNAL ;
    PORT
      LAYER M5 ;
        RECT  28.56 0 28.584 0.192 ;
    END
  END o[196]
  PIN o[197]
    DIRECTION OUTPUT ;
    USE SIGNAL ;
    PORT
      LAYER M5 ;
        RECT  28.608 0 28.632 0.192 ;
    END
  END o[197]
  PIN o[198]
    DIRECTION OUTPUT ;
    USE SIGNAL ;
    PORT
      LAYER M5 ;
        RECT  28.656 0 28.68 0.192 ;
    END
  END o[198]
  PIN o[199]
    DIRECTION OUTPUT ;
    USE SIGNAL ;
    PORT
      LAYER M5 ;
        RECT  28.704 0 28.728 0.192 ;
    END
  END o[199]
  PIN o[19]
    DIRECTION OUTPUT ;
    USE SIGNAL ;
    PORT
      LAYER M5 ;
        RECT  20.064 0 20.088 0.192 ;
    END
  END o[19]
  PIN o[1]
    DIRECTION OUTPUT ;
    USE SIGNAL ;
    PORT
      LAYER M5 ;
        RECT  19.2 0 19.224 0.192 ;
    END
  END o[1]
  PIN o[200]
    DIRECTION OUTPUT ;
    USE SIGNAL ;
    PORT
      LAYER M5 ;
        RECT  28.752 0 28.776 0.192 ;
    END
  END o[200]
  PIN o[201]
    DIRECTION OUTPUT ;
    USE SIGNAL ;
    PORT
      LAYER M5 ;
        RECT  28.8 0 28.824 0.192 ;
    END
  END o[201]
  PIN o[202]
    DIRECTION OUTPUT ;
    USE SIGNAL ;
    PORT
      LAYER M5 ;
        RECT  28.848 0 28.872 0.192 ;
    END
  END o[202]
  PIN o[203]
    DIRECTION OUTPUT ;
    USE SIGNAL ;
    PORT
      LAYER M5 ;
        RECT  28.896 0 28.92 0.192 ;
    END
  END o[203]
  PIN o[204]
    DIRECTION OUTPUT ;
    USE SIGNAL ;
    PORT
      LAYER M5 ;
        RECT  28.944 0 28.968 0.192 ;
    END
  END o[204]
  PIN o[205]
    DIRECTION OUTPUT ;
    USE SIGNAL ;
    PORT
      LAYER M5 ;
        RECT  28.992 0 29.016 0.192 ;
    END
  END o[205]
  PIN o[206]
    DIRECTION OUTPUT ;
    USE SIGNAL ;
    PORT
      LAYER M5 ;
        RECT  29.04 0 29.064 0.192 ;
    END
  END o[206]
  PIN o[207]
    DIRECTION OUTPUT ;
    USE SIGNAL ;
    PORT
      LAYER M5 ;
        RECT  29.088 0 29.112 0.192 ;
    END
  END o[207]
  PIN o[208]
    DIRECTION OUTPUT ;
    USE SIGNAL ;
    PORT
      LAYER M5 ;
        RECT  29.136 0 29.16 0.192 ;
    END
  END o[208]
  PIN o[209]
    DIRECTION OUTPUT ;
    USE SIGNAL ;
    PORT
      LAYER M5 ;
        RECT  29.184 0 29.208 0.192 ;
    END
  END o[209]
  PIN o[20]
    DIRECTION OUTPUT ;
    USE SIGNAL ;
    PORT
      LAYER M5 ;
        RECT  20.112 0 20.136 0.192 ;
    END
  END o[20]
  PIN o[210]
    DIRECTION OUTPUT ;
    USE SIGNAL ;
    PORT
      LAYER M5 ;
        RECT  29.232 0 29.256 0.192 ;
    END
  END o[210]
  PIN o[211]
    DIRECTION OUTPUT ;
    USE SIGNAL ;
    PORT
      LAYER M5 ;
        RECT  29.28 0 29.304 0.192 ;
    END
  END o[211]
  PIN o[212]
    DIRECTION OUTPUT ;
    USE SIGNAL ;
    PORT
      LAYER M5 ;
        RECT  29.328 0 29.352 0.192 ;
    END
  END o[212]
  PIN o[213]
    DIRECTION OUTPUT ;
    USE SIGNAL ;
    PORT
      LAYER M5 ;
        RECT  29.376 0 29.4 0.192 ;
    END
  END o[213]
  PIN o[214]
    DIRECTION OUTPUT ;
    USE SIGNAL ;
    PORT
      LAYER M5 ;
        RECT  29.424 0 29.448 0.192 ;
    END
  END o[214]
  PIN o[215]
    DIRECTION OUTPUT ;
    USE SIGNAL ;
    PORT
      LAYER M5 ;
        RECT  29.472 0 29.496 0.192 ;
    END
  END o[215]
  PIN o[216]
    DIRECTION OUTPUT ;
    USE SIGNAL ;
    PORT
      LAYER M5 ;
        RECT  29.52 0 29.544 0.192 ;
    END
  END o[216]
  PIN o[217]
    DIRECTION OUTPUT ;
    USE SIGNAL ;
    PORT
      LAYER M5 ;
        RECT  29.568 0 29.592 0.192 ;
    END
  END o[217]
  PIN o[218]
    DIRECTION OUTPUT ;
    USE SIGNAL ;
    PORT
      LAYER M5 ;
        RECT  29.616 0 29.64 0.192 ;
    END
  END o[218]
  PIN o[219]
    DIRECTION OUTPUT ;
    USE SIGNAL ;
    PORT
      LAYER M5 ;
        RECT  29.664 0 29.688 0.192 ;
    END
  END o[219]
  PIN o[21]
    DIRECTION OUTPUT ;
    USE SIGNAL ;
    PORT
      LAYER M5 ;
        RECT  20.16 0 20.184 0.192 ;
    END
  END o[21]
  PIN o[220]
    DIRECTION OUTPUT ;
    USE SIGNAL ;
    PORT
      LAYER M5 ;
        RECT  29.712 0 29.736 0.192 ;
    END
  END o[220]
  PIN o[221]
    DIRECTION OUTPUT ;
    USE SIGNAL ;
    PORT
      LAYER M5 ;
        RECT  29.76 0 29.784 0.192 ;
    END
  END o[221]
  PIN o[222]
    DIRECTION OUTPUT ;
    USE SIGNAL ;
    PORT
      LAYER M5 ;
        RECT  29.808 0 29.832 0.192 ;
    END
  END o[222]
  PIN o[223]
    DIRECTION OUTPUT ;
    USE SIGNAL ;
    PORT
      LAYER M5 ;
        RECT  29.856 0 29.88 0.192 ;
    END
  END o[223]
  PIN o[224]
    DIRECTION OUTPUT ;
    USE SIGNAL ;
    PORT
      LAYER M5 ;
        RECT  29.904 0 29.928 0.192 ;
    END
  END o[224]
  PIN o[225]
    DIRECTION OUTPUT ;
    USE SIGNAL ;
    PORT
      LAYER M5 ;
        RECT  29.952 0 29.976 0.192 ;
    END
  END o[225]
  PIN o[226]
    DIRECTION OUTPUT ;
    USE SIGNAL ;
    PORT
      LAYER M5 ;
        RECT  30 0 30.024 0.192 ;
    END
  END o[226]
  PIN o[227]
    DIRECTION OUTPUT ;
    USE SIGNAL ;
    PORT
      LAYER M5 ;
        RECT  30.048 0 30.072 0.192 ;
    END
  END o[227]
  PIN o[228]
    DIRECTION OUTPUT ;
    USE SIGNAL ;
    PORT
      LAYER M5 ;
        RECT  30.096 0 30.12 0.192 ;
    END
  END o[228]
  PIN o[229]
    DIRECTION OUTPUT ;
    USE SIGNAL ;
    PORT
      LAYER M5 ;
        RECT  30.144 0 30.168 0.192 ;
    END
  END o[229]
  PIN o[22]
    DIRECTION OUTPUT ;
    USE SIGNAL ;
    PORT
      LAYER M5 ;
        RECT  20.208 0 20.232 0.192 ;
    END
  END o[22]
  PIN o[230]
    DIRECTION OUTPUT ;
    USE SIGNAL ;
    PORT
      LAYER M5 ;
        RECT  30.192 0 30.216 0.192 ;
    END
  END o[230]
  PIN o[231]
    DIRECTION OUTPUT ;
    USE SIGNAL ;
    PORT
      LAYER M5 ;
        RECT  30.24 0 30.264 0.192 ;
    END
  END o[231]
  PIN o[232]
    DIRECTION OUTPUT ;
    USE SIGNAL ;
    PORT
      LAYER M5 ;
        RECT  30.288 0 30.312 0.192 ;
    END
  END o[232]
  PIN o[233]
    DIRECTION OUTPUT ;
    USE SIGNAL ;
    PORT
      LAYER M5 ;
        RECT  30.336 0 30.36 0.192 ;
    END
  END o[233]
  PIN o[234]
    DIRECTION OUTPUT ;
    USE SIGNAL ;
    PORT
      LAYER M5 ;
        RECT  30.384 0 30.408 0.192 ;
    END
  END o[234]
  PIN o[235]
    DIRECTION OUTPUT ;
    USE SIGNAL ;
    PORT
      LAYER M5 ;
        RECT  30.432 0 30.456 0.192 ;
    END
  END o[235]
  PIN o[236]
    DIRECTION OUTPUT ;
    USE SIGNAL ;
    PORT
      LAYER M5 ;
        RECT  30.48 0 30.504 0.192 ;
    END
  END o[236]
  PIN o[237]
    DIRECTION OUTPUT ;
    USE SIGNAL ;
    PORT
      LAYER M5 ;
        RECT  30.528 0 30.552 0.192 ;
    END
  END o[237]
  PIN o[238]
    DIRECTION OUTPUT ;
    USE SIGNAL ;
    PORT
      LAYER M5 ;
        RECT  30.576 0 30.6 0.192 ;
    END
  END o[238]
  PIN o[239]
    DIRECTION OUTPUT ;
    USE SIGNAL ;
    PORT
      LAYER M5 ;
        RECT  30.624 0 30.648 0.192 ;
    END
  END o[239]
  PIN o[23]
    DIRECTION OUTPUT ;
    USE SIGNAL ;
    PORT
      LAYER M5 ;
        RECT  20.256 0 20.28 0.192 ;
    END
  END o[23]
  PIN o[240]
    DIRECTION OUTPUT ;
    USE SIGNAL ;
    PORT
      LAYER M5 ;
        RECT  30.672 0 30.696 0.192 ;
    END
  END o[240]
  PIN o[241]
    DIRECTION OUTPUT ;
    USE SIGNAL ;
    PORT
      LAYER M5 ;
        RECT  30.72 0 30.744 0.192 ;
    END
  END o[241]
  PIN o[242]
    DIRECTION OUTPUT ;
    USE SIGNAL ;
    PORT
      LAYER M5 ;
        RECT  30.768 0 30.792 0.192 ;
    END
  END o[242]
  PIN o[243]
    DIRECTION OUTPUT ;
    USE SIGNAL ;
    PORT
      LAYER M5 ;
        RECT  30.816 0 30.84 0.192 ;
    END
  END o[243]
  PIN o[244]
    DIRECTION OUTPUT ;
    USE SIGNAL ;
    PORT
      LAYER M5 ;
        RECT  30.864 0 30.888 0.192 ;
    END
  END o[244]
  PIN o[245]
    DIRECTION OUTPUT ;
    USE SIGNAL ;
    PORT
      LAYER M5 ;
        RECT  30.912 0 30.936 0.192 ;
    END
  END o[245]
  PIN o[246]
    DIRECTION OUTPUT ;
    USE SIGNAL ;
    PORT
      LAYER M5 ;
        RECT  30.96 0 30.984 0.192 ;
    END
  END o[246]
  PIN o[247]
    DIRECTION OUTPUT ;
    USE SIGNAL ;
    PORT
      LAYER M5 ;
        RECT  31.008 0 31.032 0.192 ;
    END
  END o[247]
  PIN o[248]
    DIRECTION OUTPUT ;
    USE SIGNAL ;
    PORT
      LAYER M5 ;
        RECT  31.056 0 31.08 0.192 ;
    END
  END o[248]
  PIN o[249]
    DIRECTION OUTPUT ;
    USE SIGNAL ;
    PORT
      LAYER M5 ;
        RECT  31.104 0 31.128 0.192 ;
    END
  END o[249]
  PIN o[24]
    DIRECTION OUTPUT ;
    USE SIGNAL ;
    PORT
      LAYER M5 ;
        RECT  20.304 0 20.328 0.192 ;
    END
  END o[24]
  PIN o[250]
    DIRECTION OUTPUT ;
    USE SIGNAL ;
    PORT
      LAYER M5 ;
        RECT  31.152 0 31.176 0.192 ;
    END
  END o[250]
  PIN o[251]
    DIRECTION OUTPUT ;
    USE SIGNAL ;
    PORT
      LAYER M5 ;
        RECT  31.2 0 31.224 0.192 ;
    END
  END o[251]
  PIN o[252]
    DIRECTION OUTPUT ;
    USE SIGNAL ;
    PORT
      LAYER M5 ;
        RECT  31.248 0 31.272 0.192 ;
    END
  END o[252]
  PIN o[253]
    DIRECTION OUTPUT ;
    USE SIGNAL ;
    PORT
      LAYER M5 ;
        RECT  31.296 0 31.32 0.192 ;
    END
  END o[253]
  PIN o[254]
    DIRECTION OUTPUT ;
    USE SIGNAL ;
    PORT
      LAYER M5 ;
        RECT  31.344 0 31.368 0.192 ;
    END
  END o[254]
  PIN o[255]
    DIRECTION OUTPUT ;
    USE SIGNAL ;
    PORT
      LAYER M5 ;
        RECT  31.392 0 31.416 0.192 ;
    END
  END o[255]
  PIN o[256]
    DIRECTION OUTPUT ;
    USE SIGNAL ;
    PORT
      LAYER M5 ;
        RECT  31.44 0 31.464 0.192 ;
    END
  END o[256]
  PIN o[257]
    DIRECTION OUTPUT ;
    USE SIGNAL ;
    PORT
      LAYER M5 ;
        RECT  31.488 0 31.512 0.192 ;
    END
  END o[257]
  PIN o[258]
    DIRECTION OUTPUT ;
    USE SIGNAL ;
    PORT
      LAYER M5 ;
        RECT  31.536 0 31.56 0.192 ;
    END
  END o[258]
  PIN o[259]
    DIRECTION OUTPUT ;
    USE SIGNAL ;
    PORT
      LAYER M5 ;
        RECT  31.584 0 31.608 0.192 ;
    END
  END o[259]
  PIN o[25]
    DIRECTION OUTPUT ;
    USE SIGNAL ;
    PORT
      LAYER M5 ;
        RECT  20.352 0 20.376 0.192 ;
    END
  END o[25]
  PIN o[260]
    DIRECTION OUTPUT ;
    USE SIGNAL ;
    PORT
      LAYER M5 ;
        RECT  31.632 0 31.656 0.192 ;
    END
  END o[260]
  PIN o[261]
    DIRECTION OUTPUT ;
    USE SIGNAL ;
    PORT
      LAYER M5 ;
        RECT  31.68 0 31.704 0.192 ;
    END
  END o[261]
  PIN o[262]
    DIRECTION OUTPUT ;
    USE SIGNAL ;
    PORT
      LAYER M5 ;
        RECT  31.728 0 31.752 0.192 ;
    END
  END o[262]
  PIN o[263]
    DIRECTION OUTPUT ;
    USE SIGNAL ;
    PORT
      LAYER M5 ;
        RECT  31.776 0 31.8 0.192 ;
    END
  END o[263]
  PIN o[264]
    DIRECTION OUTPUT ;
    USE SIGNAL ;
    PORT
      LAYER M5 ;
        RECT  31.824 0 31.848 0.192 ;
    END
  END o[264]
  PIN o[265]
    DIRECTION OUTPUT ;
    USE SIGNAL ;
    PORT
      LAYER M5 ;
        RECT  31.872 0 31.896 0.192 ;
    END
  END o[265]
  PIN o[266]
    DIRECTION OUTPUT ;
    USE SIGNAL ;
    PORT
      LAYER M5 ;
        RECT  31.92 0 31.944 0.192 ;
    END
  END o[266]
  PIN o[267]
    DIRECTION OUTPUT ;
    USE SIGNAL ;
    PORT
      LAYER M5 ;
        RECT  31.968 0 31.992 0.192 ;
    END
  END o[267]
  PIN o[268]
    DIRECTION OUTPUT ;
    USE SIGNAL ;
    PORT
      LAYER M5 ;
        RECT  32.016 0 32.04 0.192 ;
    END
  END o[268]
  PIN o[269]
    DIRECTION OUTPUT ;
    USE SIGNAL ;
    PORT
      LAYER M5 ;
        RECT  32.064 0 32.088 0.192 ;
    END
  END o[269]
  PIN o[26]
    DIRECTION OUTPUT ;
    USE SIGNAL ;
    PORT
      LAYER M5 ;
        RECT  20.4 0 20.424 0.192 ;
    END
  END o[26]
  PIN o[270]
    DIRECTION OUTPUT ;
    USE SIGNAL ;
    PORT
      LAYER M5 ;
        RECT  32.112 0 32.136 0.192 ;
    END
  END o[270]
  PIN o[271]
    DIRECTION OUTPUT ;
    USE SIGNAL ;
    PORT
      LAYER M5 ;
        RECT  32.16 0 32.184 0.192 ;
    END
  END o[271]
  PIN o[272]
    DIRECTION OUTPUT ;
    USE SIGNAL ;
    PORT
      LAYER M5 ;
        RECT  32.208 0 32.232 0.192 ;
    END
  END o[272]
  PIN o[273]
    DIRECTION OUTPUT ;
    USE SIGNAL ;
    PORT
      LAYER M5 ;
        RECT  32.256 0 32.28 0.192 ;
    END
  END o[273]
  PIN o[274]
    DIRECTION OUTPUT ;
    USE SIGNAL ;
    PORT
      LAYER M5 ;
        RECT  32.304 0 32.328 0.192 ;
    END
  END o[274]
  PIN o[275]
    DIRECTION OUTPUT ;
    USE SIGNAL ;
    PORT
      LAYER M5 ;
        RECT  32.352 0 32.376 0.192 ;
    END
  END o[275]
  PIN o[276]
    DIRECTION OUTPUT ;
    USE SIGNAL ;
    PORT
      LAYER M5 ;
        RECT  32.4 0 32.424 0.192 ;
    END
  END o[276]
  PIN o[277]
    DIRECTION OUTPUT ;
    USE SIGNAL ;
    PORT
      LAYER M5 ;
        RECT  32.448 0 32.472 0.192 ;
    END
  END o[277]
  PIN o[278]
    DIRECTION OUTPUT ;
    USE SIGNAL ;
    PORT
      LAYER M5 ;
        RECT  32.496 0 32.52 0.192 ;
    END
  END o[278]
  PIN o[279]
    DIRECTION OUTPUT ;
    USE SIGNAL ;
    PORT
      LAYER M5 ;
        RECT  32.544 0 32.568 0.192 ;
    END
  END o[279]
  PIN o[27]
    DIRECTION OUTPUT ;
    USE SIGNAL ;
    PORT
      LAYER M5 ;
        RECT  20.448 0 20.472 0.192 ;
    END
  END o[27]
  PIN o[280]
    DIRECTION OUTPUT ;
    USE SIGNAL ;
    PORT
      LAYER M5 ;
        RECT  32.592 0 32.616 0.192 ;
    END
  END o[280]
  PIN o[281]
    DIRECTION OUTPUT ;
    USE SIGNAL ;
    PORT
      LAYER M5 ;
        RECT  32.64 0 32.664 0.192 ;
    END
  END o[281]
  PIN o[282]
    DIRECTION OUTPUT ;
    USE SIGNAL ;
    PORT
      LAYER M5 ;
        RECT  32.688 0 32.712 0.192 ;
    END
  END o[282]
  PIN o[283]
    DIRECTION OUTPUT ;
    USE SIGNAL ;
    PORT
      LAYER M5 ;
        RECT  32.736 0 32.76 0.192 ;
    END
  END o[283]
  PIN o[284]
    DIRECTION OUTPUT ;
    USE SIGNAL ;
    PORT
      LAYER M5 ;
        RECT  32.784 0 32.808 0.192 ;
    END
  END o[284]
  PIN o[285]
    DIRECTION OUTPUT ;
    USE SIGNAL ;
    PORT
      LAYER M5 ;
        RECT  32.832 0 32.856 0.192 ;
    END
  END o[285]
  PIN o[286]
    DIRECTION OUTPUT ;
    USE SIGNAL ;
    PORT
      LAYER M5 ;
        RECT  32.88 0 32.904 0.192 ;
    END
  END o[286]
  PIN o[287]
    DIRECTION OUTPUT ;
    USE SIGNAL ;
    PORT
      LAYER M5 ;
        RECT  32.928 0 32.952 0.192 ;
    END
  END o[287]
  PIN o[288]
    DIRECTION OUTPUT ;
    USE SIGNAL ;
    PORT
      LAYER M5 ;
        RECT  32.976 0 33 0.192 ;
    END
  END o[288]
  PIN o[289]
    DIRECTION OUTPUT ;
    USE SIGNAL ;
    PORT
      LAYER M5 ;
        RECT  33.024 0 33.048 0.192 ;
    END
  END o[289]
  PIN o[28]
    DIRECTION OUTPUT ;
    USE SIGNAL ;
    PORT
      LAYER M5 ;
        RECT  20.496 0 20.52 0.192 ;
    END
  END o[28]
  PIN o[290]
    DIRECTION OUTPUT ;
    USE SIGNAL ;
    PORT
      LAYER M5 ;
        RECT  33.072 0 33.096 0.192 ;
    END
  END o[290]
  PIN o[291]
    DIRECTION OUTPUT ;
    USE SIGNAL ;
    PORT
      LAYER M5 ;
        RECT  33.12 0 33.144 0.192 ;
    END
  END o[291]
  PIN o[292]
    DIRECTION OUTPUT ;
    USE SIGNAL ;
    PORT
      LAYER M5 ;
        RECT  33.168 0 33.192 0.192 ;
    END
  END o[292]
  PIN o[293]
    DIRECTION OUTPUT ;
    USE SIGNAL ;
    PORT
      LAYER M5 ;
        RECT  33.216 0 33.24 0.192 ;
    END
  END o[293]
  PIN o[294]
    DIRECTION OUTPUT ;
    USE SIGNAL ;
    PORT
      LAYER M5 ;
        RECT  33.264 0 33.288 0.192 ;
    END
  END o[294]
  PIN o[295]
    DIRECTION OUTPUT ;
    USE SIGNAL ;
    PORT
      LAYER M5 ;
        RECT  33.312 0 33.336 0.192 ;
    END
  END o[295]
  PIN o[296]
    DIRECTION OUTPUT ;
    USE SIGNAL ;
    PORT
      LAYER M5 ;
        RECT  33.36 0 33.384 0.192 ;
    END
  END o[296]
  PIN o[297]
    DIRECTION OUTPUT ;
    USE SIGNAL ;
    PORT
      LAYER M5 ;
        RECT  33.408 0 33.432 0.192 ;
    END
  END o[297]
  PIN o[298]
    DIRECTION OUTPUT ;
    USE SIGNAL ;
    PORT
      LAYER M5 ;
        RECT  33.456 0 33.48 0.192 ;
    END
  END o[298]
  PIN o[299]
    DIRECTION OUTPUT ;
    USE SIGNAL ;
    PORT
      LAYER M5 ;
        RECT  33.504 0 33.528 0.192 ;
    END
  END o[299]
  PIN o[29]
    DIRECTION OUTPUT ;
    USE SIGNAL ;
    PORT
      LAYER M5 ;
        RECT  20.544 0 20.568 0.192 ;
    END
  END o[29]
  PIN o[2]
    DIRECTION OUTPUT ;
    USE SIGNAL ;
    PORT
      LAYER M5 ;
        RECT  19.248 0 19.272 0.192 ;
    END
  END o[2]
  PIN o[300]
    DIRECTION OUTPUT ;
    USE SIGNAL ;
    PORT
      LAYER M5 ;
        RECT  33.552 0 33.576 0.192 ;
    END
  END o[300]
  PIN o[301]
    DIRECTION OUTPUT ;
    USE SIGNAL ;
    PORT
      LAYER M5 ;
        RECT  33.6 0 33.624 0.192 ;
    END
  END o[301]
  PIN o[302]
    DIRECTION OUTPUT ;
    USE SIGNAL ;
    PORT
      LAYER M5 ;
        RECT  33.648 0 33.672 0.192 ;
    END
  END o[302]
  PIN o[303]
    DIRECTION OUTPUT ;
    USE SIGNAL ;
    PORT
      LAYER M5 ;
        RECT  33.696 0 33.72 0.192 ;
    END
  END o[303]
  PIN o[304]
    DIRECTION OUTPUT ;
    USE SIGNAL ;
    PORT
      LAYER M5 ;
        RECT  33.744 0 33.768 0.192 ;
    END
  END o[304]
  PIN o[305]
    DIRECTION OUTPUT ;
    USE SIGNAL ;
    PORT
      LAYER M5 ;
        RECT  33.792 0 33.816 0.192 ;
    END
  END o[305]
  PIN o[306]
    DIRECTION OUTPUT ;
    USE SIGNAL ;
    PORT
      LAYER M5 ;
        RECT  33.84 0 33.864 0.192 ;
    END
  END o[306]
  PIN o[307]
    DIRECTION OUTPUT ;
    USE SIGNAL ;
    PORT
      LAYER M5 ;
        RECT  33.888 0 33.912 0.192 ;
    END
  END o[307]
  PIN o[308]
    DIRECTION OUTPUT ;
    USE SIGNAL ;
    PORT
      LAYER M5 ;
        RECT  33.936 0 33.96 0.192 ;
    END
  END o[308]
  PIN o[309]
    DIRECTION OUTPUT ;
    USE SIGNAL ;
    PORT
      LAYER M5 ;
        RECT  33.984 0 34.008 0.192 ;
    END
  END o[309]
  PIN o[30]
    DIRECTION OUTPUT ;
    USE SIGNAL ;
    PORT
      LAYER M5 ;
        RECT  20.592 0 20.616 0.192 ;
    END
  END o[30]
  PIN o[310]
    DIRECTION OUTPUT ;
    USE SIGNAL ;
    PORT
      LAYER M5 ;
        RECT  34.032 0 34.056 0.192 ;
    END
  END o[310]
  PIN o[311]
    DIRECTION OUTPUT ;
    USE SIGNAL ;
    PORT
      LAYER M5 ;
        RECT  34.08 0 34.104 0.192 ;
    END
  END o[311]
  PIN o[312]
    DIRECTION OUTPUT ;
    USE SIGNAL ;
    PORT
      LAYER M5 ;
        RECT  34.128 0 34.152 0.192 ;
    END
  END o[312]
  PIN o[313]
    DIRECTION OUTPUT ;
    USE SIGNAL ;
    PORT
      LAYER M5 ;
        RECT  34.176 0 34.2 0.192 ;
    END
  END o[313]
  PIN o[314]
    DIRECTION OUTPUT ;
    USE SIGNAL ;
    PORT
      LAYER M5 ;
        RECT  34.224 0 34.248 0.192 ;
    END
  END o[314]
  PIN o[315]
    DIRECTION OUTPUT ;
    USE SIGNAL ;
    PORT
      LAYER M5 ;
        RECT  34.272 0 34.296 0.192 ;
    END
  END o[315]
  PIN o[316]
    DIRECTION OUTPUT ;
    USE SIGNAL ;
    PORT
      LAYER M5 ;
        RECT  34.32 0 34.344 0.192 ;
    END
  END o[316]
  PIN o[317]
    DIRECTION OUTPUT ;
    USE SIGNAL ;
    PORT
      LAYER M5 ;
        RECT  34.368 0 34.392 0.192 ;
    END
  END o[317]
  PIN o[318]
    DIRECTION OUTPUT ;
    USE SIGNAL ;
    PORT
      LAYER M5 ;
        RECT  34.416 0 34.44 0.192 ;
    END
  END o[318]
  PIN o[319]
    DIRECTION OUTPUT ;
    USE SIGNAL ;
    PORT
      LAYER M5 ;
        RECT  34.464 0 34.488 0.192 ;
    END
  END o[319]
  PIN o[31]
    DIRECTION OUTPUT ;
    USE SIGNAL ;
    PORT
      LAYER M5 ;
        RECT  20.64 0 20.664 0.192 ;
    END
  END o[31]
  PIN o[320]
    DIRECTION OUTPUT ;
    USE SIGNAL ;
    PORT
      LAYER M5 ;
        RECT  34.512 0 34.536 0.192 ;
    END
  END o[320]
  PIN o[321]
    DIRECTION OUTPUT ;
    USE SIGNAL ;
    PORT
      LAYER M5 ;
        RECT  34.56 0 34.584 0.192 ;
    END
  END o[321]
  PIN o[322]
    DIRECTION OUTPUT ;
    USE SIGNAL ;
    PORT
      LAYER M5 ;
        RECT  34.608 0 34.632 0.192 ;
    END
  END o[322]
  PIN o[323]
    DIRECTION OUTPUT ;
    USE SIGNAL ;
    PORT
      LAYER M5 ;
        RECT  34.656 0 34.68 0.192 ;
    END
  END o[323]
  PIN o[324]
    DIRECTION OUTPUT ;
    USE SIGNAL ;
    PORT
      LAYER M5 ;
        RECT  34.704 0 34.728 0.192 ;
    END
  END o[324]
  PIN o[325]
    DIRECTION OUTPUT ;
    USE SIGNAL ;
    PORT
      LAYER M5 ;
        RECT  34.752 0 34.776 0.192 ;
    END
  END o[325]
  PIN o[326]
    DIRECTION OUTPUT ;
    USE SIGNAL ;
    PORT
      LAYER M5 ;
        RECT  34.8 0 34.824 0.192 ;
    END
  END o[326]
  PIN o[327]
    DIRECTION OUTPUT ;
    USE SIGNAL ;
    PORT
      LAYER M5 ;
        RECT  34.848 0 34.872 0.192 ;
    END
  END o[327]
  PIN o[328]
    DIRECTION OUTPUT ;
    USE SIGNAL ;
    PORT
      LAYER M5 ;
        RECT  34.896 0 34.92 0.192 ;
    END
  END o[328]
  PIN o[329]
    DIRECTION OUTPUT ;
    USE SIGNAL ;
    PORT
      LAYER M5 ;
        RECT  34.944 0 34.968 0.192 ;
    END
  END o[329]
  PIN o[32]
    DIRECTION OUTPUT ;
    USE SIGNAL ;
    PORT
      LAYER M5 ;
        RECT  20.688 0 20.712 0.192 ;
    END
  END o[32]
  PIN o[330]
    DIRECTION OUTPUT ;
    USE SIGNAL ;
    PORT
      LAYER M5 ;
        RECT  34.992 0 35.016 0.192 ;
    END
  END o[330]
  PIN o[331]
    DIRECTION OUTPUT ;
    USE SIGNAL ;
    PORT
      LAYER M5 ;
        RECT  35.04 0 35.064 0.192 ;
    END
  END o[331]
  PIN o[332]
    DIRECTION OUTPUT ;
    USE SIGNAL ;
    PORT
      LAYER M5 ;
        RECT  35.088 0 35.112 0.192 ;
    END
  END o[332]
  PIN o[333]
    DIRECTION OUTPUT ;
    USE SIGNAL ;
    PORT
      LAYER M5 ;
        RECT  35.136 0 35.16 0.192 ;
    END
  END o[333]
  PIN o[334]
    DIRECTION OUTPUT ;
    USE SIGNAL ;
    PORT
      LAYER M5 ;
        RECT  35.184 0 35.208 0.192 ;
    END
  END o[334]
  PIN o[335]
    DIRECTION OUTPUT ;
    USE SIGNAL ;
    PORT
      LAYER M5 ;
        RECT  35.232 0 35.256 0.192 ;
    END
  END o[335]
  PIN o[336]
    DIRECTION OUTPUT ;
    USE SIGNAL ;
    PORT
      LAYER M5 ;
        RECT  35.28 0 35.304 0.192 ;
    END
  END o[336]
  PIN o[337]
    DIRECTION OUTPUT ;
    USE SIGNAL ;
    PORT
      LAYER M5 ;
        RECT  35.328 0 35.352 0.192 ;
    END
  END o[337]
  PIN o[338]
    DIRECTION OUTPUT ;
    USE SIGNAL ;
    PORT
      LAYER M5 ;
        RECT  35.376 0 35.4 0.192 ;
    END
  END o[338]
  PIN o[339]
    DIRECTION OUTPUT ;
    USE SIGNAL ;
    PORT
      LAYER M5 ;
        RECT  35.424 0 35.448 0.192 ;
    END
  END o[339]
  PIN o[33]
    DIRECTION OUTPUT ;
    USE SIGNAL ;
    PORT
      LAYER M5 ;
        RECT  20.736 0 20.76 0.192 ;
    END
  END o[33]
  PIN o[340]
    DIRECTION OUTPUT ;
    USE SIGNAL ;
    PORT
      LAYER M5 ;
        RECT  35.472 0 35.496 0.192 ;
    END
  END o[340]
  PIN o[341]
    DIRECTION OUTPUT ;
    USE SIGNAL ;
    PORT
      LAYER M5 ;
        RECT  35.52 0 35.544 0.192 ;
    END
  END o[341]
  PIN o[342]
    DIRECTION OUTPUT ;
    USE SIGNAL ;
    PORT
      LAYER M5 ;
        RECT  35.568 0 35.592 0.192 ;
    END
  END o[342]
  PIN o[343]
    DIRECTION OUTPUT ;
    USE SIGNAL ;
    PORT
      LAYER M5 ;
        RECT  35.616 0 35.64 0.192 ;
    END
  END o[343]
  PIN o[344]
    DIRECTION OUTPUT ;
    USE SIGNAL ;
    PORT
      LAYER M5 ;
        RECT  35.664 0 35.688 0.192 ;
    END
  END o[344]
  PIN o[345]
    DIRECTION OUTPUT ;
    USE SIGNAL ;
    PORT
      LAYER M5 ;
        RECT  35.712 0 35.736 0.192 ;
    END
  END o[345]
  PIN o[346]
    DIRECTION OUTPUT ;
    USE SIGNAL ;
    PORT
      LAYER M5 ;
        RECT  35.76 0 35.784 0.192 ;
    END
  END o[346]
  PIN o[347]
    DIRECTION OUTPUT ;
    USE SIGNAL ;
    PORT
      LAYER M5 ;
        RECT  35.808 0 35.832 0.192 ;
    END
  END o[347]
  PIN o[348]
    DIRECTION OUTPUT ;
    USE SIGNAL ;
    PORT
      LAYER M5 ;
        RECT  35.856 0 35.88 0.192 ;
    END
  END o[348]
  PIN o[349]
    DIRECTION OUTPUT ;
    USE SIGNAL ;
    PORT
      LAYER M5 ;
        RECT  35.904 0 35.928 0.192 ;
    END
  END o[349]
  PIN o[34]
    DIRECTION OUTPUT ;
    USE SIGNAL ;
    PORT
      LAYER M5 ;
        RECT  20.784 0 20.808 0.192 ;
    END
  END o[34]
  PIN o[350]
    DIRECTION OUTPUT ;
    USE SIGNAL ;
    PORT
      LAYER M5 ;
        RECT  35.952 0 35.976 0.192 ;
    END
  END o[350]
  PIN o[351]
    DIRECTION OUTPUT ;
    USE SIGNAL ;
    PORT
      LAYER M5 ;
        RECT  36 0 36.024 0.192 ;
    END
  END o[351]
  PIN o[352]
    DIRECTION OUTPUT ;
    USE SIGNAL ;
    PORT
      LAYER M5 ;
        RECT  36.048 0 36.072 0.192 ;
    END
  END o[352]
  PIN o[353]
    DIRECTION OUTPUT ;
    USE SIGNAL ;
    PORT
      LAYER M5 ;
        RECT  36.096 0 36.12 0.192 ;
    END
  END o[353]
  PIN o[354]
    DIRECTION OUTPUT ;
    USE SIGNAL ;
    PORT
      LAYER M5 ;
        RECT  36.144 0 36.168 0.192 ;
    END
  END o[354]
  PIN o[355]
    DIRECTION OUTPUT ;
    USE SIGNAL ;
    PORT
      LAYER M5 ;
        RECT  36.192 0 36.216 0.192 ;
    END
  END o[355]
  PIN o[356]
    DIRECTION OUTPUT ;
    USE SIGNAL ;
    PORT
      LAYER M5 ;
        RECT  36.24 0 36.264 0.192 ;
    END
  END o[356]
  PIN o[357]
    DIRECTION OUTPUT ;
    USE SIGNAL ;
    PORT
      LAYER M5 ;
        RECT  36.288 0 36.312 0.192 ;
    END
  END o[357]
  PIN o[358]
    DIRECTION OUTPUT ;
    USE SIGNAL ;
    PORT
      LAYER M5 ;
        RECT  36.336 0 36.36 0.192 ;
    END
  END o[358]
  PIN o[359]
    DIRECTION OUTPUT ;
    USE SIGNAL ;
    PORT
      LAYER M5 ;
        RECT  36.384 0 36.408 0.192 ;
    END
  END o[359]
  PIN o[35]
    DIRECTION OUTPUT ;
    USE SIGNAL ;
    PORT
      LAYER M5 ;
        RECT  20.832 0 20.856 0.192 ;
    END
  END o[35]
  PIN o[360]
    DIRECTION OUTPUT ;
    USE SIGNAL ;
    PORT
      LAYER M5 ;
        RECT  36.432 0 36.456 0.192 ;
    END
  END o[360]
  PIN o[361]
    DIRECTION OUTPUT ;
    USE SIGNAL ;
    PORT
      LAYER M5 ;
        RECT  36.48 0 36.504 0.192 ;
    END
  END o[361]
  PIN o[362]
    DIRECTION OUTPUT ;
    USE SIGNAL ;
    PORT
      LAYER M5 ;
        RECT  36.528 0 36.552 0.192 ;
    END
  END o[362]
  PIN o[363]
    DIRECTION OUTPUT ;
    USE SIGNAL ;
    PORT
      LAYER M5 ;
        RECT  36.576 0 36.6 0.192 ;
    END
  END o[363]
  PIN o[364]
    DIRECTION OUTPUT ;
    USE SIGNAL ;
    PORT
      LAYER M5 ;
        RECT  36.624 0 36.648 0.192 ;
    END
  END o[364]
  PIN o[365]
    DIRECTION OUTPUT ;
    USE SIGNAL ;
    PORT
      LAYER M5 ;
        RECT  36.672 0 36.696 0.192 ;
    END
  END o[365]
  PIN o[366]
    DIRECTION OUTPUT ;
    USE SIGNAL ;
    PORT
      LAYER M5 ;
        RECT  36.72 0 36.744 0.192 ;
    END
  END o[366]
  PIN o[367]
    DIRECTION OUTPUT ;
    USE SIGNAL ;
    PORT
      LAYER M5 ;
        RECT  36.768 0 36.792 0.192 ;
    END
  END o[367]
  PIN o[368]
    DIRECTION OUTPUT ;
    USE SIGNAL ;
    PORT
      LAYER M5 ;
        RECT  36.816 0 36.84 0.192 ;
    END
  END o[368]
  PIN o[369]
    DIRECTION OUTPUT ;
    USE SIGNAL ;
    PORT
      LAYER M5 ;
        RECT  36.864 0 36.888 0.192 ;
    END
  END o[369]
  PIN o[36]
    DIRECTION OUTPUT ;
    USE SIGNAL ;
    PORT
      LAYER M5 ;
        RECT  20.88 0 20.904 0.192 ;
    END
  END o[36]
  PIN o[370]
    DIRECTION OUTPUT ;
    USE SIGNAL ;
    PORT
      LAYER M5 ;
        RECT  36.912 0 36.936 0.192 ;
    END
  END o[370]
  PIN o[371]
    DIRECTION OUTPUT ;
    USE SIGNAL ;
    PORT
      LAYER M5 ;
        RECT  36.96 0 36.984 0.192 ;
    END
  END o[371]
  PIN o[372]
    DIRECTION OUTPUT ;
    USE SIGNAL ;
    PORT
      LAYER M5 ;
        RECT  37.008 0 37.032 0.192 ;
    END
  END o[372]
  PIN o[373]
    DIRECTION OUTPUT ;
    USE SIGNAL ;
    PORT
      LAYER M5 ;
        RECT  37.056 0 37.08 0.192 ;
    END
  END o[373]
  PIN o[374]
    DIRECTION OUTPUT ;
    USE SIGNAL ;
    PORT
      LAYER M5 ;
        RECT  37.104 0 37.128 0.192 ;
    END
  END o[374]
  PIN o[375]
    DIRECTION OUTPUT ;
    USE SIGNAL ;
    PORT
      LAYER M5 ;
        RECT  37.152 0 37.176 0.192 ;
    END
  END o[375]
  PIN o[376]
    DIRECTION OUTPUT ;
    USE SIGNAL ;
    PORT
      LAYER M5 ;
        RECT  37.2 0 37.224 0.192 ;
    END
  END o[376]
  PIN o[377]
    DIRECTION OUTPUT ;
    USE SIGNAL ;
    PORT
      LAYER M5 ;
        RECT  37.248 0 37.272 0.192 ;
    END
  END o[377]
  PIN o[378]
    DIRECTION OUTPUT ;
    USE SIGNAL ;
    PORT
      LAYER M5 ;
        RECT  37.296 0 37.32 0.192 ;
    END
  END o[378]
  PIN o[379]
    DIRECTION OUTPUT ;
    USE SIGNAL ;
    PORT
      LAYER M5 ;
        RECT  37.344 0 37.368 0.192 ;
    END
  END o[379]
  PIN o[37]
    DIRECTION OUTPUT ;
    USE SIGNAL ;
    PORT
      LAYER M5 ;
        RECT  20.928 0 20.952 0.192 ;
    END
  END o[37]
  PIN o[380]
    DIRECTION OUTPUT ;
    USE SIGNAL ;
    PORT
      LAYER M5 ;
        RECT  37.392 0 37.416 0.192 ;
    END
  END o[380]
  PIN o[381]
    DIRECTION OUTPUT ;
    USE SIGNAL ;
    PORT
      LAYER M5 ;
        RECT  37.44 0 37.464 0.192 ;
    END
  END o[381]
  PIN o[382]
    DIRECTION OUTPUT ;
    USE SIGNAL ;
    PORT
      LAYER M5 ;
        RECT  37.488 0 37.512 0.192 ;
    END
  END o[382]
  PIN o[383]
    DIRECTION OUTPUT ;
    USE SIGNAL ;
    PORT
      LAYER M5 ;
        RECT  37.536 0 37.56 0.192 ;
    END
  END o[383]
  PIN o[384]
    DIRECTION OUTPUT ;
    USE SIGNAL ;
    PORT
      LAYER M5 ;
        RECT  37.584 0 37.608 0.192 ;
    END
  END o[384]
  PIN o[385]
    DIRECTION OUTPUT ;
    USE SIGNAL ;
    PORT
      LAYER M5 ;
        RECT  37.632 0 37.656 0.192 ;
    END
  END o[385]
  PIN o[386]
    DIRECTION OUTPUT ;
    USE SIGNAL ;
    PORT
      LAYER M5 ;
        RECT  37.68 0 37.704 0.192 ;
    END
  END o[386]
  PIN o[387]
    DIRECTION OUTPUT ;
    USE SIGNAL ;
    PORT
      LAYER M5 ;
        RECT  37.728 0 37.752 0.192 ;
    END
  END o[387]
  PIN o[388]
    DIRECTION OUTPUT ;
    USE SIGNAL ;
    PORT
      LAYER M5 ;
        RECT  37.776 0 37.8 0.192 ;
    END
  END o[388]
  PIN o[389]
    DIRECTION OUTPUT ;
    USE SIGNAL ;
    PORT
      LAYER M5 ;
        RECT  37.824 0 37.848 0.192 ;
    END
  END o[389]
  PIN o[38]
    DIRECTION OUTPUT ;
    USE SIGNAL ;
    PORT
      LAYER M5 ;
        RECT  20.976 0 21 0.192 ;
    END
  END o[38]
  PIN o[390]
    DIRECTION OUTPUT ;
    USE SIGNAL ;
    PORT
      LAYER M5 ;
        RECT  37.872 0 37.896 0.192 ;
    END
  END o[390]
  PIN o[391]
    DIRECTION OUTPUT ;
    USE SIGNAL ;
    PORT
      LAYER M5 ;
        RECT  37.92 0 37.944 0.192 ;
    END
  END o[391]
  PIN o[392]
    DIRECTION OUTPUT ;
    USE SIGNAL ;
    PORT
      LAYER M5 ;
        RECT  37.968 0 37.992 0.192 ;
    END
  END o[392]
  PIN o[393]
    DIRECTION OUTPUT ;
    USE SIGNAL ;
    PORT
      LAYER M5 ;
        RECT  38.016 0 38.04 0.192 ;
    END
  END o[393]
  PIN o[394]
    DIRECTION OUTPUT ;
    USE SIGNAL ;
    PORT
      LAYER M5 ;
        RECT  38.064 0 38.088 0.192 ;
    END
  END o[394]
  PIN o[395]
    DIRECTION OUTPUT ;
    USE SIGNAL ;
    PORT
      LAYER M5 ;
        RECT  38.112 0 38.136 0.192 ;
    END
  END o[395]
  PIN o[396]
    DIRECTION OUTPUT ;
    USE SIGNAL ;
    PORT
      LAYER M5 ;
        RECT  38.16 0 38.184 0.192 ;
    END
  END o[396]
  PIN o[397]
    DIRECTION OUTPUT ;
    USE SIGNAL ;
    PORT
      LAYER M5 ;
        RECT  38.208 0 38.232 0.192 ;
    END
  END o[397]
  PIN o[398]
    DIRECTION OUTPUT ;
    USE SIGNAL ;
    PORT
      LAYER M5 ;
        RECT  38.256 0 38.28 0.192 ;
    END
  END o[398]
  PIN o[399]
    DIRECTION OUTPUT ;
    USE SIGNAL ;
    PORT
      LAYER M5 ;
        RECT  38.304 0 38.328 0.192 ;
    END
  END o[399]
  PIN o[39]
    DIRECTION OUTPUT ;
    USE SIGNAL ;
    PORT
      LAYER M5 ;
        RECT  21.024 0 21.048 0.192 ;
    END
  END o[39]
  PIN o[3]
    DIRECTION OUTPUT ;
    USE SIGNAL ;
    PORT
      LAYER M5 ;
        RECT  19.296 0 19.32 0.192 ;
    END
  END o[3]
  PIN o[400]
    DIRECTION OUTPUT ;
    USE SIGNAL ;
    PORT
      LAYER M5 ;
        RECT  38.352 0 38.376 0.192 ;
    END
  END o[400]
  PIN o[401]
    DIRECTION OUTPUT ;
    USE SIGNAL ;
    PORT
      LAYER M5 ;
        RECT  38.4 0 38.424 0.192 ;
    END
  END o[401]
  PIN o[402]
    DIRECTION OUTPUT ;
    USE SIGNAL ;
    PORT
      LAYER M5 ;
        RECT  38.448 0 38.472 0.192 ;
    END
  END o[402]
  PIN o[403]
    DIRECTION OUTPUT ;
    USE SIGNAL ;
    PORT
      LAYER M5 ;
        RECT  38.496 0 38.52 0.192 ;
    END
  END o[403]
  PIN o[404]
    DIRECTION OUTPUT ;
    USE SIGNAL ;
    PORT
      LAYER M5 ;
        RECT  38.544 0 38.568 0.192 ;
    END
  END o[404]
  PIN o[405]
    DIRECTION OUTPUT ;
    USE SIGNAL ;
    PORT
      LAYER M5 ;
        RECT  38.592 0 38.616 0.192 ;
    END
  END o[405]
  PIN o[406]
    DIRECTION OUTPUT ;
    USE SIGNAL ;
    PORT
      LAYER M5 ;
        RECT  38.64 0 38.664 0.192 ;
    END
  END o[406]
  PIN o[407]
    DIRECTION OUTPUT ;
    USE SIGNAL ;
    PORT
      LAYER M5 ;
        RECT  38.688 0 38.712 0.192 ;
    END
  END o[407]
  PIN o[408]
    DIRECTION OUTPUT ;
    USE SIGNAL ;
    PORT
      LAYER M5 ;
        RECT  38.736 0 38.76 0.192 ;
    END
  END o[408]
  PIN o[409]
    DIRECTION OUTPUT ;
    USE SIGNAL ;
    PORT
      LAYER M5 ;
        RECT  38.784 0 38.808 0.192 ;
    END
  END o[409]
  PIN o[40]
    DIRECTION OUTPUT ;
    USE SIGNAL ;
    PORT
      LAYER M5 ;
        RECT  21.072 0 21.096 0.192 ;
    END
  END o[40]
  PIN o[410]
    DIRECTION OUTPUT ;
    USE SIGNAL ;
    PORT
      LAYER M5 ;
        RECT  38.832 0 38.856 0.192 ;
    END
  END o[410]
  PIN o[411]
    DIRECTION OUTPUT ;
    USE SIGNAL ;
    PORT
      LAYER M5 ;
        RECT  38.88 0 38.904 0.192 ;
    END
  END o[411]
  PIN o[412]
    DIRECTION OUTPUT ;
    USE SIGNAL ;
    PORT
      LAYER M5 ;
        RECT  38.928 0 38.952 0.192 ;
    END
  END o[412]
  PIN o[413]
    DIRECTION OUTPUT ;
    USE SIGNAL ;
    PORT
      LAYER M5 ;
        RECT  38.976 0 39 0.192 ;
    END
  END o[413]
  PIN o[414]
    DIRECTION OUTPUT ;
    USE SIGNAL ;
    PORT
      LAYER M5 ;
        RECT  39.024 0 39.048 0.192 ;
    END
  END o[414]
  PIN o[415]
    DIRECTION OUTPUT ;
    USE SIGNAL ;
    PORT
      LAYER M5 ;
        RECT  39.072 0 39.096 0.192 ;
    END
  END o[415]
  PIN o[416]
    DIRECTION OUTPUT ;
    USE SIGNAL ;
    PORT
      LAYER M5 ;
        RECT  39.12 0 39.144 0.192 ;
    END
  END o[416]
  PIN o[417]
    DIRECTION OUTPUT ;
    USE SIGNAL ;
    PORT
      LAYER M5 ;
        RECT  39.168 0 39.192 0.192 ;
    END
  END o[417]
  PIN o[418]
    DIRECTION OUTPUT ;
    USE SIGNAL ;
    PORT
      LAYER M5 ;
        RECT  39.216 0 39.24 0.192 ;
    END
  END o[418]
  PIN o[419]
    DIRECTION OUTPUT ;
    USE SIGNAL ;
    PORT
      LAYER M5 ;
        RECT  39.264 0 39.288 0.192 ;
    END
  END o[419]
  PIN o[41]
    DIRECTION OUTPUT ;
    USE SIGNAL ;
    PORT
      LAYER M5 ;
        RECT  21.12 0 21.144 0.192 ;
    END
  END o[41]
  PIN o[420]
    DIRECTION OUTPUT ;
    USE SIGNAL ;
    PORT
      LAYER M5 ;
        RECT  39.312 0 39.336 0.192 ;
    END
  END o[420]
  PIN o[421]
    DIRECTION OUTPUT ;
    USE SIGNAL ;
    PORT
      LAYER M5 ;
        RECT  39.36 0 39.384 0.192 ;
    END
  END o[421]
  PIN o[422]
    DIRECTION OUTPUT ;
    USE SIGNAL ;
    PORT
      LAYER M5 ;
        RECT  39.408 0 39.432 0.192 ;
    END
  END o[422]
  PIN o[423]
    DIRECTION OUTPUT ;
    USE SIGNAL ;
    PORT
      LAYER M5 ;
        RECT  39.456 0 39.48 0.192 ;
    END
  END o[423]
  PIN o[424]
    DIRECTION OUTPUT ;
    USE SIGNAL ;
    PORT
      LAYER M5 ;
        RECT  39.504 0 39.528 0.192 ;
    END
  END o[424]
  PIN o[425]
    DIRECTION OUTPUT ;
    USE SIGNAL ;
    PORT
      LAYER M5 ;
        RECT  39.552 0 39.576 0.192 ;
    END
  END o[425]
  PIN o[426]
    DIRECTION OUTPUT ;
    USE SIGNAL ;
    PORT
      LAYER M5 ;
        RECT  39.6 0 39.624 0.192 ;
    END
  END o[426]
  PIN o[427]
    DIRECTION OUTPUT ;
    USE SIGNAL ;
    PORT
      LAYER M5 ;
        RECT  39.648 0 39.672 0.192 ;
    END
  END o[427]
  PIN o[428]
    DIRECTION OUTPUT ;
    USE SIGNAL ;
    PORT
      LAYER M5 ;
        RECT  39.696 0 39.72 0.192 ;
    END
  END o[428]
  PIN o[429]
    DIRECTION OUTPUT ;
    USE SIGNAL ;
    PORT
      LAYER M5 ;
        RECT  39.744 0 39.768 0.192 ;
    END
  END o[429]
  PIN o[42]
    DIRECTION OUTPUT ;
    USE SIGNAL ;
    PORT
      LAYER M5 ;
        RECT  21.168 0 21.192 0.192 ;
    END
  END o[42]
  PIN o[430]
    DIRECTION OUTPUT ;
    USE SIGNAL ;
    PORT
      LAYER M5 ;
        RECT  39.792 0 39.816 0.192 ;
    END
  END o[430]
  PIN o[431]
    DIRECTION OUTPUT ;
    USE SIGNAL ;
    PORT
      LAYER M5 ;
        RECT  39.84 0 39.864 0.192 ;
    END
  END o[431]
  PIN o[432]
    DIRECTION OUTPUT ;
    USE SIGNAL ;
    PORT
      LAYER M5 ;
        RECT  39.888 0 39.912 0.192 ;
    END
  END o[432]
  PIN o[433]
    DIRECTION OUTPUT ;
    USE SIGNAL ;
    PORT
      LAYER M5 ;
        RECT  39.936 0 39.96 0.192 ;
    END
  END o[433]
  PIN o[434]
    DIRECTION OUTPUT ;
    USE SIGNAL ;
    PORT
      LAYER M5 ;
        RECT  39.984 0 40.008 0.192 ;
    END
  END o[434]
  PIN o[435]
    DIRECTION OUTPUT ;
    USE SIGNAL ;
    PORT
      LAYER M5 ;
        RECT  40.032 0 40.056 0.192 ;
    END
  END o[435]
  PIN o[436]
    DIRECTION OUTPUT ;
    USE SIGNAL ;
    PORT
      LAYER M5 ;
        RECT  40.08 0 40.104 0.192 ;
    END
  END o[436]
  PIN o[437]
    DIRECTION OUTPUT ;
    USE SIGNAL ;
    PORT
      LAYER M5 ;
        RECT  40.128 0 40.152 0.192 ;
    END
  END o[437]
  PIN o[438]
    DIRECTION OUTPUT ;
    USE SIGNAL ;
    PORT
      LAYER M5 ;
        RECT  40.176 0 40.2 0.192 ;
    END
  END o[438]
  PIN o[439]
    DIRECTION OUTPUT ;
    USE SIGNAL ;
    PORT
      LAYER M5 ;
        RECT  40.224 0 40.248 0.192 ;
    END
  END o[439]
  PIN o[43]
    DIRECTION OUTPUT ;
    USE SIGNAL ;
    PORT
      LAYER M5 ;
        RECT  21.216 0 21.24 0.192 ;
    END
  END o[43]
  PIN o[440]
    DIRECTION OUTPUT ;
    USE SIGNAL ;
    PORT
      LAYER M5 ;
        RECT  40.272 0 40.296 0.192 ;
    END
  END o[440]
  PIN o[441]
    DIRECTION OUTPUT ;
    USE SIGNAL ;
    PORT
      LAYER M5 ;
        RECT  40.32 0 40.344 0.192 ;
    END
  END o[441]
  PIN o[442]
    DIRECTION OUTPUT ;
    USE SIGNAL ;
    PORT
      LAYER M5 ;
        RECT  40.368 0 40.392 0.192 ;
    END
  END o[442]
  PIN o[443]
    DIRECTION OUTPUT ;
    USE SIGNAL ;
    PORT
      LAYER M5 ;
        RECT  40.416 0 40.44 0.192 ;
    END
  END o[443]
  PIN o[444]
    DIRECTION OUTPUT ;
    USE SIGNAL ;
    PORT
      LAYER M5 ;
        RECT  40.464 0 40.488 0.192 ;
    END
  END o[444]
  PIN o[445]
    DIRECTION OUTPUT ;
    USE SIGNAL ;
    PORT
      LAYER M5 ;
        RECT  40.512 0 40.536 0.192 ;
    END
  END o[445]
  PIN o[446]
    DIRECTION OUTPUT ;
    USE SIGNAL ;
    PORT
      LAYER M5 ;
        RECT  40.56 0 40.584 0.192 ;
    END
  END o[446]
  PIN o[447]
    DIRECTION OUTPUT ;
    USE SIGNAL ;
    PORT
      LAYER M5 ;
        RECT  40.608 0 40.632 0.192 ;
    END
  END o[447]
  PIN o[448]
    DIRECTION OUTPUT ;
    USE SIGNAL ;
    PORT
      LAYER M5 ;
        RECT  40.656 0 40.68 0.192 ;
    END
  END o[448]
  PIN o[449]
    DIRECTION OUTPUT ;
    USE SIGNAL ;
    PORT
      LAYER M5 ;
        RECT  40.704 0 40.728 0.192 ;
    END
  END o[449]
  PIN o[44]
    DIRECTION OUTPUT ;
    USE SIGNAL ;
    PORT
      LAYER M5 ;
        RECT  21.264 0 21.288 0.192 ;
    END
  END o[44]
  PIN o[450]
    DIRECTION OUTPUT ;
    USE SIGNAL ;
    PORT
      LAYER M5 ;
        RECT  40.752 0 40.776 0.192 ;
    END
  END o[450]
  PIN o[451]
    DIRECTION OUTPUT ;
    USE SIGNAL ;
    PORT
      LAYER M5 ;
        RECT  40.8 0 40.824 0.192 ;
    END
  END o[451]
  PIN o[452]
    DIRECTION OUTPUT ;
    USE SIGNAL ;
    PORT
      LAYER M5 ;
        RECT  40.848 0 40.872 0.192 ;
    END
  END o[452]
  PIN o[453]
    DIRECTION OUTPUT ;
    USE SIGNAL ;
    PORT
      LAYER M5 ;
        RECT  40.896 0 40.92 0.192 ;
    END
  END o[453]
  PIN o[454]
    DIRECTION OUTPUT ;
    USE SIGNAL ;
    PORT
      LAYER M5 ;
        RECT  40.944 0 40.968 0.192 ;
    END
  END o[454]
  PIN o[455]
    DIRECTION OUTPUT ;
    USE SIGNAL ;
    PORT
      LAYER M5 ;
        RECT  40.992 0 41.016 0.192 ;
    END
  END o[455]
  PIN o[456]
    DIRECTION OUTPUT ;
    USE SIGNAL ;
    PORT
      LAYER M5 ;
        RECT  41.04 0 41.064 0.192 ;
    END
  END o[456]
  PIN o[457]
    DIRECTION OUTPUT ;
    USE SIGNAL ;
    PORT
      LAYER M5 ;
        RECT  41.088 0 41.112 0.192 ;
    END
  END o[457]
  PIN o[458]
    DIRECTION OUTPUT ;
    USE SIGNAL ;
    PORT
      LAYER M5 ;
        RECT  41.136 0 41.16 0.192 ;
    END
  END o[458]
  PIN o[459]
    DIRECTION OUTPUT ;
    USE SIGNAL ;
    PORT
      LAYER M5 ;
        RECT  41.184 0 41.208 0.192 ;
    END
  END o[459]
  PIN o[45]
    DIRECTION OUTPUT ;
    USE SIGNAL ;
    PORT
      LAYER M5 ;
        RECT  21.312 0 21.336 0.192 ;
    END
  END o[45]
  PIN o[460]
    DIRECTION OUTPUT ;
    USE SIGNAL ;
    PORT
      LAYER M5 ;
        RECT  41.232 0 41.256 0.192 ;
    END
  END o[460]
  PIN o[461]
    DIRECTION OUTPUT ;
    USE SIGNAL ;
    PORT
      LAYER M5 ;
        RECT  41.28 0 41.304 0.192 ;
    END
  END o[461]
  PIN o[462]
    DIRECTION OUTPUT ;
    USE SIGNAL ;
    PORT
      LAYER M5 ;
        RECT  41.328 0 41.352 0.192 ;
    END
  END o[462]
  PIN o[463]
    DIRECTION OUTPUT ;
    USE SIGNAL ;
    PORT
      LAYER M5 ;
        RECT  41.376 0 41.4 0.192 ;
    END
  END o[463]
  PIN o[464]
    DIRECTION OUTPUT ;
    USE SIGNAL ;
    PORT
      LAYER M5 ;
        RECT  41.424 0 41.448 0.192 ;
    END
  END o[464]
  PIN o[465]
    DIRECTION OUTPUT ;
    USE SIGNAL ;
    PORT
      LAYER M5 ;
        RECT  41.472 0 41.496 0.192 ;
    END
  END o[465]
  PIN o[466]
    DIRECTION OUTPUT ;
    USE SIGNAL ;
    PORT
      LAYER M5 ;
        RECT  41.52 0 41.544 0.192 ;
    END
  END o[466]
  PIN o[467]
    DIRECTION OUTPUT ;
    USE SIGNAL ;
    PORT
      LAYER M5 ;
        RECT  41.568 0 41.592 0.192 ;
    END
  END o[467]
  PIN o[468]
    DIRECTION OUTPUT ;
    USE SIGNAL ;
    PORT
      LAYER M5 ;
        RECT  41.616 0 41.64 0.192 ;
    END
  END o[468]
  PIN o[469]
    DIRECTION OUTPUT ;
    USE SIGNAL ;
    PORT
      LAYER M5 ;
        RECT  41.664 0 41.688 0.192 ;
    END
  END o[469]
  PIN o[46]
    DIRECTION OUTPUT ;
    USE SIGNAL ;
    PORT
      LAYER M5 ;
        RECT  21.36 0 21.384 0.192 ;
    END
  END o[46]
  PIN o[470]
    DIRECTION OUTPUT ;
    USE SIGNAL ;
    PORT
      LAYER M5 ;
        RECT  41.712 0 41.736 0.192 ;
    END
  END o[470]
  PIN o[471]
    DIRECTION OUTPUT ;
    USE SIGNAL ;
    PORT
      LAYER M5 ;
        RECT  41.76 0 41.784 0.192 ;
    END
  END o[471]
  PIN o[472]
    DIRECTION OUTPUT ;
    USE SIGNAL ;
    PORT
      LAYER M5 ;
        RECT  41.808 0 41.832 0.192 ;
    END
  END o[472]
  PIN o[473]
    DIRECTION OUTPUT ;
    USE SIGNAL ;
    PORT
      LAYER M5 ;
        RECT  41.856 0 41.88 0.192 ;
    END
  END o[473]
  PIN o[474]
    DIRECTION OUTPUT ;
    USE SIGNAL ;
    PORT
      LAYER M5 ;
        RECT  41.904 0 41.928 0.192 ;
    END
  END o[474]
  PIN o[475]
    DIRECTION OUTPUT ;
    USE SIGNAL ;
    PORT
      LAYER M5 ;
        RECT  41.952 0 41.976 0.192 ;
    END
  END o[475]
  PIN o[476]
    DIRECTION OUTPUT ;
    USE SIGNAL ;
    PORT
      LAYER M5 ;
        RECT  42 0 42.024 0.192 ;
    END
  END o[476]
  PIN o[477]
    DIRECTION OUTPUT ;
    USE SIGNAL ;
    PORT
      LAYER M5 ;
        RECT  42.048 0 42.072 0.192 ;
    END
  END o[477]
  PIN o[478]
    DIRECTION OUTPUT ;
    USE SIGNAL ;
    PORT
      LAYER M5 ;
        RECT  42.096 0 42.12 0.192 ;
    END
  END o[478]
  PIN o[479]
    DIRECTION OUTPUT ;
    USE SIGNAL ;
    PORT
      LAYER M5 ;
        RECT  42.144 0 42.168 0.192 ;
    END
  END o[479]
  PIN o[47]
    DIRECTION OUTPUT ;
    USE SIGNAL ;
    PORT
      LAYER M5 ;
        RECT  21.408 0 21.432 0.192 ;
    END
  END o[47]
  PIN o[480]
    DIRECTION OUTPUT ;
    USE SIGNAL ;
    PORT
      LAYER M5 ;
        RECT  42.192 0 42.216 0.192 ;
    END
  END o[480]
  PIN o[481]
    DIRECTION OUTPUT ;
    USE SIGNAL ;
    PORT
      LAYER M5 ;
        RECT  42.24 0 42.264 0.192 ;
    END
  END o[481]
  PIN o[482]
    DIRECTION OUTPUT ;
    USE SIGNAL ;
    PORT
      LAYER M5 ;
        RECT  42.288 0 42.312 0.192 ;
    END
  END o[482]
  PIN o[483]
    DIRECTION OUTPUT ;
    USE SIGNAL ;
    PORT
      LAYER M5 ;
        RECT  42.336 0 42.36 0.192 ;
    END
  END o[483]
  PIN o[484]
    DIRECTION OUTPUT ;
    USE SIGNAL ;
    PORT
      LAYER M5 ;
        RECT  42.384 0 42.408 0.192 ;
    END
  END o[484]
  PIN o[485]
    DIRECTION OUTPUT ;
    USE SIGNAL ;
    PORT
      LAYER M5 ;
        RECT  42.432 0 42.456 0.192 ;
    END
  END o[485]
  PIN o[486]
    DIRECTION OUTPUT ;
    USE SIGNAL ;
    PORT
      LAYER M5 ;
        RECT  42.48 0 42.504 0.192 ;
    END
  END o[486]
  PIN o[487]
    DIRECTION OUTPUT ;
    USE SIGNAL ;
    PORT
      LAYER M5 ;
        RECT  42.528 0 42.552 0.192 ;
    END
  END o[487]
  PIN o[488]
    DIRECTION OUTPUT ;
    USE SIGNAL ;
    PORT
      LAYER M5 ;
        RECT  42.576 0 42.6 0.192 ;
    END
  END o[488]
  PIN o[489]
    DIRECTION OUTPUT ;
    USE SIGNAL ;
    PORT
      LAYER M5 ;
        RECT  42.624 0 42.648 0.192 ;
    END
  END o[489]
  PIN o[48]
    DIRECTION OUTPUT ;
    USE SIGNAL ;
    PORT
      LAYER M5 ;
        RECT  21.456 0 21.48 0.192 ;
    END
  END o[48]
  PIN o[490]
    DIRECTION OUTPUT ;
    USE SIGNAL ;
    PORT
      LAYER M5 ;
        RECT  42.672 0 42.696 0.192 ;
    END
  END o[490]
  PIN o[491]
    DIRECTION OUTPUT ;
    USE SIGNAL ;
    PORT
      LAYER M5 ;
        RECT  42.72 0 42.744 0.192 ;
    END
  END o[491]
  PIN o[492]
    DIRECTION OUTPUT ;
    USE SIGNAL ;
    PORT
      LAYER M5 ;
        RECT  42.768 0 42.792 0.192 ;
    END
  END o[492]
  PIN o[493]
    DIRECTION OUTPUT ;
    USE SIGNAL ;
    PORT
      LAYER M5 ;
        RECT  42.816 0 42.84 0.192 ;
    END
  END o[493]
  PIN o[494]
    DIRECTION OUTPUT ;
    USE SIGNAL ;
    PORT
      LAYER M5 ;
        RECT  42.864 0 42.888 0.192 ;
    END
  END o[494]
  PIN o[495]
    DIRECTION OUTPUT ;
    USE SIGNAL ;
    PORT
      LAYER M5 ;
        RECT  42.912 0 42.936 0.192 ;
    END
  END o[495]
  PIN o[496]
    DIRECTION OUTPUT ;
    USE SIGNAL ;
    PORT
      LAYER M5 ;
        RECT  42.96 0 42.984 0.192 ;
    END
  END o[496]
  PIN o[497]
    DIRECTION OUTPUT ;
    USE SIGNAL ;
    PORT
      LAYER M5 ;
        RECT  43.008 0 43.032 0.192 ;
    END
  END o[497]
  PIN o[498]
    DIRECTION OUTPUT ;
    USE SIGNAL ;
    PORT
      LAYER M5 ;
        RECT  43.056 0 43.08 0.192 ;
    END
  END o[498]
  PIN o[499]
    DIRECTION OUTPUT ;
    USE SIGNAL ;
    PORT
      LAYER M5 ;
        RECT  43.104 0 43.128 0.192 ;
    END
  END o[499]
  PIN o[49]
    DIRECTION OUTPUT ;
    USE SIGNAL ;
    PORT
      LAYER M5 ;
        RECT  21.504 0 21.528 0.192 ;
    END
  END o[49]
  PIN o[4]
    DIRECTION OUTPUT ;
    USE SIGNAL ;
    PORT
      LAYER M5 ;
        RECT  19.344 0 19.368 0.192 ;
    END
  END o[4]
  PIN o[500]
    DIRECTION OUTPUT ;
    USE SIGNAL ;
    PORT
      LAYER M5 ;
        RECT  43.152 0 43.176 0.192 ;
    END
  END o[500]
  PIN o[501]
    DIRECTION OUTPUT ;
    USE SIGNAL ;
    PORT
      LAYER M5 ;
        RECT  43.2 0 43.224 0.192 ;
    END
  END o[501]
  PIN o[502]
    DIRECTION OUTPUT ;
    USE SIGNAL ;
    PORT
      LAYER M5 ;
        RECT  43.248 0 43.272 0.192 ;
    END
  END o[502]
  PIN o[503]
    DIRECTION OUTPUT ;
    USE SIGNAL ;
    PORT
      LAYER M5 ;
        RECT  43.296 0 43.32 0.192 ;
    END
  END o[503]
  PIN o[504]
    DIRECTION OUTPUT ;
    USE SIGNAL ;
    PORT
      LAYER M5 ;
        RECT  43.344 0 43.368 0.192 ;
    END
  END o[504]
  PIN o[505]
    DIRECTION OUTPUT ;
    USE SIGNAL ;
    PORT
      LAYER M5 ;
        RECT  43.392 0 43.416 0.192 ;
    END
  END o[505]
  PIN o[506]
    DIRECTION OUTPUT ;
    USE SIGNAL ;
    PORT
      LAYER M5 ;
        RECT  43.44 0 43.464 0.192 ;
    END
  END o[506]
  PIN o[507]
    DIRECTION OUTPUT ;
    USE SIGNAL ;
    PORT
      LAYER M5 ;
        RECT  43.488 0 43.512 0.192 ;
    END
  END o[507]
  PIN o[508]
    DIRECTION OUTPUT ;
    USE SIGNAL ;
    PORT
      LAYER M5 ;
        RECT  43.536 0 43.56 0.192 ;
    END
  END o[508]
  PIN o[509]
    DIRECTION OUTPUT ;
    USE SIGNAL ;
    PORT
      LAYER M5 ;
        RECT  43.584 0 43.608 0.192 ;
    END
  END o[509]
  PIN o[50]
    DIRECTION OUTPUT ;
    USE SIGNAL ;
    PORT
      LAYER M5 ;
        RECT  21.552 0 21.576 0.192 ;
    END
  END o[50]
  PIN o[510]
    DIRECTION OUTPUT ;
    USE SIGNAL ;
    PORT
      LAYER M5 ;
        RECT  43.632 0 43.656 0.192 ;
    END
  END o[510]
  PIN o[511]
    DIRECTION OUTPUT ;
    USE SIGNAL ;
    PORT
      LAYER M5 ;
        RECT  43.68 0 43.704 0.192 ;
    END
  END o[511]
  PIN o[512]
    DIRECTION OUTPUT ;
    USE SIGNAL ;
    PORT
      LAYER M5 ;
        RECT  43.728 0 43.752 0.192 ;
    END
  END o[512]
  PIN o[513]
    DIRECTION OUTPUT ;
    USE SIGNAL ;
    PORT
      LAYER M5 ;
        RECT  43.776 0 43.8 0.192 ;
    END
  END o[513]
  PIN o[514]
    DIRECTION OUTPUT ;
    USE SIGNAL ;
    PORT
      LAYER M5 ;
        RECT  43.824 0 43.848 0.192 ;
    END
  END o[514]
  PIN o[51]
    DIRECTION OUTPUT ;
    USE SIGNAL ;
    PORT
      LAYER M5 ;
        RECT  21.6 0 21.624 0.192 ;
    END
  END o[51]
  PIN o[52]
    DIRECTION OUTPUT ;
    USE SIGNAL ;
    PORT
      LAYER M5 ;
        RECT  21.648 0 21.672 0.192 ;
    END
  END o[52]
  PIN o[53]
    DIRECTION OUTPUT ;
    USE SIGNAL ;
    PORT
      LAYER M5 ;
        RECT  21.696 0 21.72 0.192 ;
    END
  END o[53]
  PIN o[54]
    DIRECTION OUTPUT ;
    USE SIGNAL ;
    PORT
      LAYER M5 ;
        RECT  21.744 0 21.768 0.192 ;
    END
  END o[54]
  PIN o[55]
    DIRECTION OUTPUT ;
    USE SIGNAL ;
    PORT
      LAYER M5 ;
        RECT  21.792 0 21.816 0.192 ;
    END
  END o[55]
  PIN o[56]
    DIRECTION OUTPUT ;
    USE SIGNAL ;
    PORT
      LAYER M5 ;
        RECT  21.84 0 21.864 0.192 ;
    END
  END o[56]
  PIN o[57]
    DIRECTION OUTPUT ;
    USE SIGNAL ;
    PORT
      LAYER M5 ;
        RECT  21.888 0 21.912 0.192 ;
    END
  END o[57]
  PIN o[58]
    DIRECTION OUTPUT ;
    USE SIGNAL ;
    PORT
      LAYER M5 ;
        RECT  21.936 0 21.96 0.192 ;
    END
  END o[58]
  PIN o[59]
    DIRECTION OUTPUT ;
    USE SIGNAL ;
    PORT
      LAYER M5 ;
        RECT  21.984 0 22.008 0.192 ;
    END
  END o[59]
  PIN o[5]
    DIRECTION OUTPUT ;
    USE SIGNAL ;
    PORT
      LAYER M5 ;
        RECT  19.392 0 19.416 0.192 ;
    END
  END o[5]
  PIN o[60]
    DIRECTION OUTPUT ;
    USE SIGNAL ;
    PORT
      LAYER M5 ;
        RECT  22.032 0 22.056 0.192 ;
    END
  END o[60]
  PIN o[61]
    DIRECTION OUTPUT ;
    USE SIGNAL ;
    PORT
      LAYER M5 ;
        RECT  22.08 0 22.104 0.192 ;
    END
  END o[61]
  PIN o[62]
    DIRECTION OUTPUT ;
    USE SIGNAL ;
    PORT
      LAYER M5 ;
        RECT  22.128 0 22.152 0.192 ;
    END
  END o[62]
  PIN o[63]
    DIRECTION OUTPUT ;
    USE SIGNAL ;
    PORT
      LAYER M5 ;
        RECT  22.176 0 22.2 0.192 ;
    END
  END o[63]
  PIN o[64]
    DIRECTION OUTPUT ;
    USE SIGNAL ;
    PORT
      LAYER M5 ;
        RECT  22.224 0 22.248 0.192 ;
    END
  END o[64]
  PIN o[65]
    DIRECTION OUTPUT ;
    USE SIGNAL ;
    PORT
      LAYER M5 ;
        RECT  22.272 0 22.296 0.192 ;
    END
  END o[65]
  PIN o[66]
    DIRECTION OUTPUT ;
    USE SIGNAL ;
    PORT
      LAYER M5 ;
        RECT  22.32 0 22.344 0.192 ;
    END
  END o[66]
  PIN o[67]
    DIRECTION OUTPUT ;
    USE SIGNAL ;
    PORT
      LAYER M5 ;
        RECT  22.368 0 22.392 0.192 ;
    END
  END o[67]
  PIN o[68]
    DIRECTION OUTPUT ;
    USE SIGNAL ;
    PORT
      LAYER M5 ;
        RECT  22.416 0 22.44 0.192 ;
    END
  END o[68]
  PIN o[69]
    DIRECTION OUTPUT ;
    USE SIGNAL ;
    PORT
      LAYER M5 ;
        RECT  22.464 0 22.488 0.192 ;
    END
  END o[69]
  PIN o[6]
    DIRECTION OUTPUT ;
    USE SIGNAL ;
    PORT
      LAYER M5 ;
        RECT  19.44 0 19.464 0.192 ;
    END
  END o[6]
  PIN o[70]
    DIRECTION OUTPUT ;
    USE SIGNAL ;
    PORT
      LAYER M5 ;
        RECT  22.512 0 22.536 0.192 ;
    END
  END o[70]
  PIN o[71]
    DIRECTION OUTPUT ;
    USE SIGNAL ;
    PORT
      LAYER M5 ;
        RECT  22.56 0 22.584 0.192 ;
    END
  END o[71]
  PIN o[72]
    DIRECTION OUTPUT ;
    USE SIGNAL ;
    PORT
      LAYER M5 ;
        RECT  22.608 0 22.632 0.192 ;
    END
  END o[72]
  PIN o[73]
    DIRECTION OUTPUT ;
    USE SIGNAL ;
    PORT
      LAYER M5 ;
        RECT  22.656 0 22.68 0.192 ;
    END
  END o[73]
  PIN o[74]
    DIRECTION OUTPUT ;
    USE SIGNAL ;
    PORT
      LAYER M5 ;
        RECT  22.704 0 22.728 0.192 ;
    END
  END o[74]
  PIN o[75]
    DIRECTION OUTPUT ;
    USE SIGNAL ;
    PORT
      LAYER M5 ;
        RECT  22.752 0 22.776 0.192 ;
    END
  END o[75]
  PIN o[76]
    DIRECTION OUTPUT ;
    USE SIGNAL ;
    PORT
      LAYER M5 ;
        RECT  22.8 0 22.824 0.192 ;
    END
  END o[76]
  PIN o[77]
    DIRECTION OUTPUT ;
    USE SIGNAL ;
    PORT
      LAYER M5 ;
        RECT  22.848 0 22.872 0.192 ;
    END
  END o[77]
  PIN o[78]
    DIRECTION OUTPUT ;
    USE SIGNAL ;
    PORT
      LAYER M5 ;
        RECT  22.896 0 22.92 0.192 ;
    END
  END o[78]
  PIN o[79]
    DIRECTION OUTPUT ;
    USE SIGNAL ;
    PORT
      LAYER M5 ;
        RECT  22.944 0 22.968 0.192 ;
    END
  END o[79]
  PIN o[7]
    DIRECTION OUTPUT ;
    USE SIGNAL ;
    PORT
      LAYER M5 ;
        RECT  19.488 0 19.512 0.192 ;
    END
  END o[7]
  PIN o[80]
    DIRECTION OUTPUT ;
    USE SIGNAL ;
    PORT
      LAYER M5 ;
        RECT  22.992 0 23.016 0.192 ;
    END
  END o[80]
  PIN o[81]
    DIRECTION OUTPUT ;
    USE SIGNAL ;
    PORT
      LAYER M5 ;
        RECT  23.04 0 23.064 0.192 ;
    END
  END o[81]
  PIN o[82]
    DIRECTION OUTPUT ;
    USE SIGNAL ;
    PORT
      LAYER M5 ;
        RECT  23.088 0 23.112 0.192 ;
    END
  END o[82]
  PIN o[83]
    DIRECTION OUTPUT ;
    USE SIGNAL ;
    PORT
      LAYER M5 ;
        RECT  23.136 0 23.16 0.192 ;
    END
  END o[83]
  PIN o[84]
    DIRECTION OUTPUT ;
    USE SIGNAL ;
    PORT
      LAYER M5 ;
        RECT  23.184 0 23.208 0.192 ;
    END
  END o[84]
  PIN o[85]
    DIRECTION OUTPUT ;
    USE SIGNAL ;
    PORT
      LAYER M5 ;
        RECT  23.232 0 23.256 0.192 ;
    END
  END o[85]
  PIN o[86]
    DIRECTION OUTPUT ;
    USE SIGNAL ;
    PORT
      LAYER M5 ;
        RECT  23.28 0 23.304 0.192 ;
    END
  END o[86]
  PIN o[87]
    DIRECTION OUTPUT ;
    USE SIGNAL ;
    PORT
      LAYER M5 ;
        RECT  23.328 0 23.352 0.192 ;
    END
  END o[87]
  PIN o[88]
    DIRECTION OUTPUT ;
    USE SIGNAL ;
    PORT
      LAYER M5 ;
        RECT  23.376 0 23.4 0.192 ;
    END
  END o[88]
  PIN o[89]
    DIRECTION OUTPUT ;
    USE SIGNAL ;
    PORT
      LAYER M5 ;
        RECT  23.424 0 23.448 0.192 ;
    END
  END o[89]
  PIN o[8]
    DIRECTION OUTPUT ;
    USE SIGNAL ;
    PORT
      LAYER M5 ;
        RECT  19.536 0 19.56 0.192 ;
    END
  END o[8]
  PIN o[90]
    DIRECTION OUTPUT ;
    USE SIGNAL ;
    PORT
      LAYER M5 ;
        RECT  23.472 0 23.496 0.192 ;
    END
  END o[90]
  PIN o[91]
    DIRECTION OUTPUT ;
    USE SIGNAL ;
    PORT
      LAYER M5 ;
        RECT  23.52 0 23.544 0.192 ;
    END
  END o[91]
  PIN o[92]
    DIRECTION OUTPUT ;
    USE SIGNAL ;
    PORT
      LAYER M5 ;
        RECT  23.568 0 23.592 0.192 ;
    END
  END o[92]
  PIN o[93]
    DIRECTION OUTPUT ;
    USE SIGNAL ;
    PORT
      LAYER M5 ;
        RECT  23.616 0 23.64 0.192 ;
    END
  END o[93]
  PIN o[94]
    DIRECTION OUTPUT ;
    USE SIGNAL ;
    PORT
      LAYER M5 ;
        RECT  23.664 0 23.688 0.192 ;
    END
  END o[94]
  PIN o[95]
    DIRECTION OUTPUT ;
    USE SIGNAL ;
    PORT
      LAYER M5 ;
        RECT  23.712 0 23.736 0.192 ;
    END
  END o[95]
  PIN o[96]
    DIRECTION OUTPUT ;
    USE SIGNAL ;
    PORT
      LAYER M5 ;
        RECT  23.76 0 23.784 0.192 ;
    END
  END o[96]
  PIN o[97]
    DIRECTION OUTPUT ;
    USE SIGNAL ;
    PORT
      LAYER M5 ;
        RECT  23.808 0 23.832 0.192 ;
    END
  END o[97]
  PIN o[98]
    DIRECTION OUTPUT ;
    USE SIGNAL ;
    PORT
      LAYER M5 ;
        RECT  23.856 0 23.88 0.192 ;
    END
  END o[98]
  PIN o[99]
    DIRECTION OUTPUT ;
    USE SIGNAL ;
    PORT
      LAYER M5 ;
        RECT  23.904 0 23.928 0.192 ;
    END
  END o[99]
  PIN o[9]
    DIRECTION OUTPUT ;
    USE SIGNAL ;
    PORT
      LAYER M5 ;
        RECT  19.584 0 19.608 0.192 ;
    END
  END o[9]
  PIN rs[0]
    DIRECTION INPUT ;
    USE SIGNAL ;
    PORT
      LAYER M5 ;
        RECT  44.016 0 44.04 0.192 ;
    END
  END rs[0]
  PIN VDD
    DIRECTION INOUT ;
    USE POWER ;
    PORT
      LAYER M7 ;
        RECT  60.256 0.531 60.544 63.999 ;
        RECT  49.456 0.531 49.744 63.999 ;
        RECT  38.656 0.531 38.944 63.999 ;
        RECT  27.856 0.531 28.144 63.999 ;
        RECT  17.056 0.531 17.344 63.999 ;
        RECT  6.256 0.531 6.544 63.999 ;
      LAYER M6 ;
        RECT  0 60.972 0.032 61.26 ;
        RECT  0 55.572 0.032 55.86 ;
        RECT  0 50.172 0.032 50.46 ;
        RECT  0 44.772 0.032 45.06 ;
        RECT  0 39.372 0.032 39.66 ;
        RECT  0 33.972 0.032 34.26 ;
        RECT  0 28.572 0.032 28.86 ;
        RECT  0 23.172 0.032 23.46 ;
        RECT  0 17.772 0.032 18.06 ;
        RECT  0 12.372 0.032 12.66 ;
        RECT  0 6.972 0.032 7.26 ;
        RECT  0 1.572 0.032 1.86 ;
      LAYER M2 ;
        RECT  0 63.981 0.018 63.999 ;
        RECT  0 63.441 0.018 63.459 ;
        RECT  0 62.901 0.018 62.919 ;
        RECT  0 62.361 0.018 62.379 ;
        RECT  0 61.821 0.018 61.839 ;
        RECT  0 61.281 0.018 61.299 ;
        RECT  0 60.741 0.018 60.759 ;
        RECT  0 60.201 0.018 60.219 ;
        RECT  0 59.661 0.018 59.679 ;
        RECT  0 59.121 0.018 59.139 ;
        RECT  0 58.581 0.018 58.599 ;
        RECT  0 58.041 0.018 58.059 ;
        RECT  0 57.501 0.018 57.519 ;
        RECT  0 56.961 0.018 56.979 ;
        RECT  0 56.421 0.018 56.439 ;
        RECT  0 55.881 0.018 55.899 ;
        RECT  0 55.341 0.018 55.359 ;
        RECT  0 54.801 0.018 54.819 ;
        RECT  0 54.261 0.018 54.279 ;
        RECT  0 53.721 0.018 53.739 ;
        RECT  0 53.181 0.018 53.199 ;
        RECT  0 52.641 0.018 52.659 ;
        RECT  0 52.101 0.018 52.119 ;
        RECT  0 51.561 0.018 51.579 ;
        RECT  0 51.021 0.018 51.039 ;
        RECT  0 50.481 0.018 50.499 ;
        RECT  0 49.941 0.018 49.959 ;
        RECT  0 49.401 0.018 49.419 ;
        RECT  0 48.861 0.018 48.879 ;
        RECT  0 48.321 0.018 48.339 ;
        RECT  0 47.781 0.018 47.799 ;
        RECT  0 47.241 0.018 47.259 ;
        RECT  0 46.701 0.018 46.719 ;
        RECT  0 46.161 0.018 46.179 ;
        RECT  0 45.621 0.018 45.639 ;
        RECT  0 45.081 0.018 45.099 ;
        RECT  0 44.541 0.018 44.559 ;
        RECT  0 44.001 0.018 44.019 ;
        RECT  0 43.461 0.018 43.479 ;
        RECT  0 42.921 0.018 42.939 ;
        RECT  0 42.381 0.018 42.399 ;
        RECT  0 41.841 0.018 41.859 ;
        RECT  0 41.301 0.018 41.319 ;
        RECT  0 40.761 0.018 40.779 ;
        RECT  0 40.221 0.018 40.239 ;
        RECT  0 39.681 0.018 39.699 ;
        RECT  0 39.141 0.018 39.159 ;
        RECT  0 38.601 0.018 38.619 ;
        RECT  0 38.061 0.018 38.079 ;
        RECT  0 37.521 0.018 37.539 ;
        RECT  0 36.981 0.018 36.999 ;
        RECT  0 36.441 0.018 36.459 ;
        RECT  0 35.901 0.018 35.919 ;
        RECT  0 35.361 0.018 35.379 ;
        RECT  0 34.821 0.018 34.839 ;
        RECT  0 34.281 0.018 34.299 ;
        RECT  0 33.741 0.018 33.759 ;
        RECT  0 33.201 0.018 33.219 ;
        RECT  0 32.661 0.018 32.679 ;
        RECT  0 32.121 0.018 32.139 ;
        RECT  0 31.581 0.018 31.599 ;
        RECT  0 31.041 0.018 31.059 ;
        RECT  0 30.501 0.018 30.519 ;
        RECT  0 29.961 0.018 29.979 ;
        RECT  0 29.421 0.018 29.439 ;
        RECT  0 28.881 0.018 28.899 ;
        RECT  0 28.341 0.018 28.359 ;
        RECT  0 27.801 0.018 27.819 ;
        RECT  0 27.261 0.018 27.279 ;
        RECT  0 26.721 0.018 26.739 ;
        RECT  0 26.181 0.018 26.199 ;
        RECT  0 25.641 0.018 25.659 ;
        RECT  0 25.101 0.018 25.119 ;
        RECT  0 24.561 0.018 24.579 ;
        RECT  0 24.021 0.018 24.039 ;
        RECT  0 23.481 0.018 23.499 ;
        RECT  0 22.941 0.018 22.959 ;
        RECT  0 22.401 0.018 22.419 ;
        RECT  0 21.861 0.018 21.879 ;
        RECT  0 21.321 0.018 21.339 ;
        RECT  0 20.781 0.018 20.799 ;
        RECT  0 20.241 0.018 20.259 ;
        RECT  0 19.701 0.018 19.719 ;
        RECT  0 19.161 0.018 19.179 ;
        RECT  0 18.621 0.018 18.639 ;
        RECT  0 18.081 0.018 18.099 ;
        RECT  0 17.541 0.018 17.559 ;
        RECT  0 17.001 0.018 17.019 ;
        RECT  0 16.461 0.018 16.479 ;
        RECT  0 15.921 0.018 15.939 ;
        RECT  0 15.381 0.018 15.399 ;
        RECT  0 14.841 0.018 14.859 ;
        RECT  0 14.301 0.018 14.319 ;
        RECT  0 13.761 0.018 13.779 ;
        RECT  0 13.221 0.018 13.239 ;
        RECT  0 12.681 0.018 12.699 ;
        RECT  0 12.141 0.018 12.159 ;
        RECT  0 11.601 0.018 11.619 ;
        RECT  0 11.061 0.018 11.079 ;
        RECT  0 10.521 0.018 10.539 ;
        RECT  0 9.981 0.018 9.999 ;
        RECT  0 9.441 0.018 9.459 ;
        RECT  0 8.901 0.018 8.919 ;
        RECT  0 8.361 0.018 8.379 ;
        RECT  0 7.821 0.018 7.839 ;
        RECT  0 7.281 0.018 7.299 ;
        RECT  0 6.741 0.018 6.759 ;
        RECT  0 6.201 0.018 6.219 ;
        RECT  0 5.661 0.018 5.679 ;
        RECT  0 5.121 0.018 5.139 ;
        RECT  0 4.581 0.018 4.599 ;
        RECT  0 4.041 0.018 4.059 ;
        RECT  0 3.501 0.018 3.519 ;
        RECT  0 2.961 0.018 2.979 ;
        RECT  0 2.421 0.018 2.439 ;
        RECT  0 1.881 0.018 1.899 ;
        RECT  0 1.341 0.018 1.359 ;
        RECT  0 0.801 0.018 0.819 ;
      LAYER M1 ;
        RECT  0 63.981 0.018 63.999 ;
        RECT  0 63.441 0.018 63.459 ;
        RECT  0 62.901 0.018 62.919 ;
        RECT  0 62.361 0.018 62.379 ;
        RECT  0 61.821 0.018 61.839 ;
        RECT  0 61.281 0.018 61.299 ;
        RECT  0 60.741 0.018 60.759 ;
        RECT  0 60.201 0.018 60.219 ;
        RECT  0 59.661 0.018 59.679 ;
        RECT  0 59.121 0.018 59.139 ;
        RECT  0 58.581 0.018 58.599 ;
        RECT  0 58.041 0.018 58.059 ;
        RECT  0 57.501 0.018 57.519 ;
        RECT  0 56.961 0.018 56.979 ;
        RECT  0 56.421 0.018 56.439 ;
        RECT  0 55.881 0.018 55.899 ;
        RECT  0 55.341 0.018 55.359 ;
        RECT  0 54.801 0.018 54.819 ;
        RECT  0 54.261 0.018 54.279 ;
        RECT  0 53.721 0.018 53.739 ;
        RECT  0 53.181 0.018 53.199 ;
        RECT  0 52.641 0.018 52.659 ;
        RECT  0 52.101 0.018 52.119 ;
        RECT  0 51.561 0.018 51.579 ;
        RECT  0 51.021 0.018 51.039 ;
        RECT  0 50.481 0.018 50.499 ;
        RECT  0 49.941 0.018 49.959 ;
        RECT  0 49.401 0.018 49.419 ;
        RECT  0 48.861 0.018 48.879 ;
        RECT  0 48.321 0.018 48.339 ;
        RECT  0 47.781 0.018 47.799 ;
        RECT  0 47.241 0.018 47.259 ;
        RECT  0 46.701 0.018 46.719 ;
        RECT  0 46.161 0.018 46.179 ;
        RECT  0 45.621 0.018 45.639 ;
        RECT  0 45.081 0.018 45.099 ;
        RECT  0 44.541 0.018 44.559 ;
        RECT  0 44.001 0.018 44.019 ;
        RECT  0 43.461 0.018 43.479 ;
        RECT  0 42.921 0.018 42.939 ;
        RECT  0 42.381 0.018 42.399 ;
        RECT  0 41.841 0.018 41.859 ;
        RECT  0 41.301 0.018 41.319 ;
        RECT  0 40.761 0.018 40.779 ;
        RECT  0 40.221 0.018 40.239 ;
        RECT  0 39.681 0.018 39.699 ;
        RECT  0 39.141 0.018 39.159 ;
        RECT  0 38.601 0.018 38.619 ;
        RECT  0 38.061 0.018 38.079 ;
        RECT  0 37.521 0.018 37.539 ;
        RECT  0 36.981 0.018 36.999 ;
        RECT  0 36.441 0.018 36.459 ;
        RECT  0 35.901 0.018 35.919 ;
        RECT  0 35.361 0.018 35.379 ;
        RECT  0 34.821 0.018 34.839 ;
        RECT  0 34.281 0.018 34.299 ;
        RECT  0 33.741 0.018 33.759 ;
        RECT  0 33.201 0.018 33.219 ;
        RECT  0 32.661 0.018 32.679 ;
        RECT  0 32.121 0.018 32.139 ;
        RECT  0 31.581 0.018 31.599 ;
        RECT  0 31.041 0.018 31.059 ;
        RECT  0 30.501 0.018 30.519 ;
        RECT  0 29.961 0.018 29.979 ;
        RECT  0 29.421 0.018 29.439 ;
        RECT  0 28.881 0.018 28.899 ;
        RECT  0 28.341 0.018 28.359 ;
        RECT  0 27.801 0.018 27.819 ;
        RECT  0 27.261 0.018 27.279 ;
        RECT  0 26.721 0.018 26.739 ;
        RECT  0 26.181 0.018 26.199 ;
        RECT  0 25.641 0.018 25.659 ;
        RECT  0 25.101 0.018 25.119 ;
        RECT  0 24.561 0.018 24.579 ;
        RECT  0 24.021 0.018 24.039 ;
        RECT  0 23.481 0.018 23.499 ;
        RECT  0 22.941 0.018 22.959 ;
        RECT  0 22.401 0.018 22.419 ;
        RECT  0 21.861 0.018 21.879 ;
        RECT  0 21.321 0.018 21.339 ;
        RECT  0 20.781 0.018 20.799 ;
        RECT  0 20.241 0.018 20.259 ;
        RECT  0 19.701 0.018 19.719 ;
        RECT  0 19.161 0.018 19.179 ;
        RECT  0 18.621 0.018 18.639 ;
        RECT  0 18.081 0.018 18.099 ;
        RECT  0 17.541 0.018 17.559 ;
        RECT  0 17.001 0.018 17.019 ;
        RECT  0 16.461 0.018 16.479 ;
        RECT  0 15.921 0.018 15.939 ;
        RECT  0 15.381 0.018 15.399 ;
        RECT  0 14.841 0.018 14.859 ;
        RECT  0 14.301 0.018 14.319 ;
        RECT  0 13.761 0.018 13.779 ;
        RECT  0 13.221 0.018 13.239 ;
        RECT  0 12.681 0.018 12.699 ;
        RECT  0 12.141 0.018 12.159 ;
        RECT  0 11.601 0.018 11.619 ;
        RECT  0 11.061 0.018 11.079 ;
        RECT  0 10.521 0.018 10.539 ;
        RECT  0 9.981 0.018 9.999 ;
        RECT  0 9.441 0.018 9.459 ;
        RECT  0 8.901 0.018 8.919 ;
        RECT  0 8.361 0.018 8.379 ;
        RECT  0 7.821 0.018 7.839 ;
        RECT  0 7.281 0.018 7.299 ;
        RECT  0 6.741 0.018 6.759 ;
        RECT  0 6.201 0.018 6.219 ;
        RECT  0 5.661 0.018 5.679 ;
        RECT  0 5.121 0.018 5.139 ;
        RECT  0 4.581 0.018 4.599 ;
        RECT  0 4.041 0.018 4.059 ;
        RECT  0 3.501 0.018 3.519 ;
        RECT  0 2.961 0.018 2.979 ;
        RECT  0 2.421 0.018 2.439 ;
        RECT  0 1.881 0.018 1.899 ;
        RECT  0 1.341 0.018 1.359 ;
        RECT  0 0.801 0.018 0.819 ;
    END
  END VDD
  PIN VSS
    DIRECTION INOUT ;
    USE GROUND ;
    PORT
      LAYER M7 ;
        RECT  54.856 0.531 55.144 63.999 ;
        RECT  44.056 0.531 44.344 63.999 ;
        RECT  33.256 0.531 33.544 63.999 ;
        RECT  22.456 0.531 22.744 63.999 ;
        RECT  11.656 0.531 11.944 63.999 ;
        RECT  0.856 0.531 1.144 63.999 ;
      LAYER M6 ;
        RECT  0 60.396 0.032 60.684 ;
        RECT  0 54.996 0.032 55.284 ;
        RECT  0 49.596 0.032 49.884 ;
        RECT  0 44.196 0.032 44.484 ;
        RECT  0 38.796 0.032 39.084 ;
        RECT  0 33.396 0.032 33.684 ;
        RECT  0 27.996 0.032 28.284 ;
        RECT  0 22.596 0.032 22.884 ;
        RECT  0 17.196 0.032 17.484 ;
        RECT  0 11.796 0.032 12.084 ;
        RECT  0 6.396 0.032 6.684 ;
        RECT  0 0.996 0.032 1.284 ;
      LAYER M2 ;
        RECT  0 63.711 0.018 63.729 ;
        RECT  0 63.171 0.018 63.189 ;
        RECT  0 62.631 0.018 62.649 ;
        RECT  0 62.091 0.018 62.109 ;
        RECT  0 61.551 0.018 61.569 ;
        RECT  0 61.011 0.018 61.029 ;
        RECT  0 60.471 0.018 60.489 ;
        RECT  0 59.931 0.018 59.949 ;
        RECT  0 59.391 0.018 59.409 ;
        RECT  0 58.851 0.018 58.869 ;
        RECT  0 58.311 0.018 58.329 ;
        RECT  0 57.771 0.018 57.789 ;
        RECT  0 57.231 0.018 57.249 ;
        RECT  0 56.691 0.018 56.709 ;
        RECT  0 56.151 0.018 56.169 ;
        RECT  0 55.611 0.018 55.629 ;
        RECT  0 55.071 0.018 55.089 ;
        RECT  0 54.531 0.018 54.549 ;
        RECT  0 53.991 0.018 54.009 ;
        RECT  0 53.451 0.018 53.469 ;
        RECT  0 52.911 0.018 52.929 ;
        RECT  0 52.371 0.018 52.389 ;
        RECT  0 51.831 0.018 51.849 ;
        RECT  0 51.291 0.018 51.309 ;
        RECT  0 50.751 0.018 50.769 ;
        RECT  0 50.211 0.018 50.229 ;
        RECT  0 49.671 0.018 49.689 ;
        RECT  0 49.131 0.018 49.149 ;
        RECT  0 48.591 0.018 48.609 ;
        RECT  0 48.051 0.018 48.069 ;
        RECT  0 47.511 0.018 47.529 ;
        RECT  0 46.971 0.018 46.989 ;
        RECT  0 46.431 0.018 46.449 ;
        RECT  0 45.891 0.018 45.909 ;
        RECT  0 45.351 0.018 45.369 ;
        RECT  0 44.811 0.018 44.829 ;
        RECT  0 44.271 0.018 44.289 ;
        RECT  0 43.731 0.018 43.749 ;
        RECT  0 43.191 0.018 43.209 ;
        RECT  0 42.651 0.018 42.669 ;
        RECT  0 42.111 0.018 42.129 ;
        RECT  0 41.571 0.018 41.589 ;
        RECT  0 41.031 0.018 41.049 ;
        RECT  0 40.491 0.018 40.509 ;
        RECT  0 39.951 0.018 39.969 ;
        RECT  0 39.411 0.018 39.429 ;
        RECT  0 38.871 0.018 38.889 ;
        RECT  0 38.331 0.018 38.349 ;
        RECT  0 37.791 0.018 37.809 ;
        RECT  0 37.251 0.018 37.269 ;
        RECT  0 36.711 0.018 36.729 ;
        RECT  0 36.171 0.018 36.189 ;
        RECT  0 35.631 0.018 35.649 ;
        RECT  0 35.091 0.018 35.109 ;
        RECT  0 34.551 0.018 34.569 ;
        RECT  0 34.011 0.018 34.029 ;
        RECT  0 33.471 0.018 33.489 ;
        RECT  0 32.931 0.018 32.949 ;
        RECT  0 32.391 0.018 32.409 ;
        RECT  0 31.851 0.018 31.869 ;
        RECT  0 31.311 0.018 31.329 ;
        RECT  0 30.771 0.018 30.789 ;
        RECT  0 30.231 0.018 30.249 ;
        RECT  0 29.691 0.018 29.709 ;
        RECT  0 29.151 0.018 29.169 ;
        RECT  0 28.611 0.018 28.629 ;
        RECT  0 28.071 0.018 28.089 ;
        RECT  0 27.531 0.018 27.549 ;
        RECT  0 26.991 0.018 27.009 ;
        RECT  0 26.451 0.018 26.469 ;
        RECT  0 25.911 0.018 25.929 ;
        RECT  0 25.371 0.018 25.389 ;
        RECT  0 24.831 0.018 24.849 ;
        RECT  0 24.291 0.018 24.309 ;
        RECT  0 23.751 0.018 23.769 ;
        RECT  0 23.211 0.018 23.229 ;
        RECT  0 22.671 0.018 22.689 ;
        RECT  0 22.131 0.018 22.149 ;
        RECT  0 21.591 0.018 21.609 ;
        RECT  0 21.051 0.018 21.069 ;
        RECT  0 20.511 0.018 20.529 ;
        RECT  0 19.971 0.018 19.989 ;
        RECT  0 19.431 0.018 19.449 ;
        RECT  0 18.891 0.018 18.909 ;
        RECT  0 18.351 0.018 18.369 ;
        RECT  0 17.811 0.018 17.829 ;
        RECT  0 17.271 0.018 17.289 ;
        RECT  0 16.731 0.018 16.749 ;
        RECT  0 16.191 0.018 16.209 ;
        RECT  0 15.651 0.018 15.669 ;
        RECT  0 15.111 0.018 15.129 ;
        RECT  0 14.571 0.018 14.589 ;
        RECT  0 14.031 0.018 14.049 ;
        RECT  0 13.491 0.018 13.509 ;
        RECT  0 12.951 0.018 12.969 ;
        RECT  0 12.411 0.018 12.429 ;
        RECT  0 11.871 0.018 11.889 ;
        RECT  0 11.331 0.018 11.349 ;
        RECT  0 10.791 0.018 10.809 ;
        RECT  0 10.251 0.018 10.269 ;
        RECT  0 9.711 0.018 9.729 ;
        RECT  0 9.171 0.018 9.189 ;
        RECT  0 8.631 0.018 8.649 ;
        RECT  0 8.091 0.018 8.109 ;
        RECT  0 7.551 0.018 7.569 ;
        RECT  0 7.011 0.018 7.029 ;
        RECT  0 6.471 0.018 6.489 ;
        RECT  0 5.931 0.018 5.949 ;
        RECT  0 5.391 0.018 5.409 ;
        RECT  0 4.851 0.018 4.869 ;
        RECT  0 4.311 0.018 4.329 ;
        RECT  0 3.771 0.018 3.789 ;
        RECT  0 3.231 0.018 3.249 ;
        RECT  0 2.691 0.018 2.709 ;
        RECT  0 2.151 0.018 2.169 ;
        RECT  0 1.611 0.018 1.629 ;
        RECT  0 1.071 0.018 1.089 ;
        RECT  0 0.531 0.018 0.549 ;
      LAYER M1 ;
        RECT  0 63.711 0.018 63.729 ;
        RECT  0 63.171 0.018 63.189 ;
        RECT  0 62.631 0.018 62.649 ;
        RECT  0 62.091 0.018 62.109 ;
        RECT  0 61.551 0.018 61.569 ;
        RECT  0 61.011 0.018 61.029 ;
        RECT  0 60.471 0.018 60.489 ;
        RECT  0 59.931 0.018 59.949 ;
        RECT  0 59.391 0.018 59.409 ;
        RECT  0 58.851 0.018 58.869 ;
        RECT  0 58.311 0.018 58.329 ;
        RECT  0 57.771 0.018 57.789 ;
        RECT  0 57.231 0.018 57.249 ;
        RECT  0 56.691 0.018 56.709 ;
        RECT  0 56.151 0.018 56.169 ;
        RECT  0 55.611 0.018 55.629 ;
        RECT  0 55.071 0.018 55.089 ;
        RECT  0 54.531 0.018 54.549 ;
        RECT  0 53.991 0.018 54.009 ;
        RECT  0 53.451 0.018 53.469 ;
        RECT  0 52.911 0.018 52.929 ;
        RECT  0 52.371 0.018 52.389 ;
        RECT  0 51.831 0.018 51.849 ;
        RECT  0 51.291 0.018 51.309 ;
        RECT  0 50.751 0.018 50.769 ;
        RECT  0 50.211 0.018 50.229 ;
        RECT  0 49.671 0.018 49.689 ;
        RECT  0 49.131 0.018 49.149 ;
        RECT  0 48.591 0.018 48.609 ;
        RECT  0 48.051 0.018 48.069 ;
        RECT  0 47.511 0.018 47.529 ;
        RECT  0 46.971 0.018 46.989 ;
        RECT  0 46.431 0.018 46.449 ;
        RECT  0 45.891 0.018 45.909 ;
        RECT  0 45.351 0.018 45.369 ;
        RECT  0 44.811 0.018 44.829 ;
        RECT  0 44.271 0.018 44.289 ;
        RECT  0 43.731 0.018 43.749 ;
        RECT  0 43.191 0.018 43.209 ;
        RECT  0 42.651 0.018 42.669 ;
        RECT  0 42.111 0.018 42.129 ;
        RECT  0 41.571 0.018 41.589 ;
        RECT  0 41.031 0.018 41.049 ;
        RECT  0 40.491 0.018 40.509 ;
        RECT  0 39.951 0.018 39.969 ;
        RECT  0 39.411 0.018 39.429 ;
        RECT  0 38.871 0.018 38.889 ;
        RECT  0 38.331 0.018 38.349 ;
        RECT  0 37.791 0.018 37.809 ;
        RECT  0 37.251 0.018 37.269 ;
        RECT  0 36.711 0.018 36.729 ;
        RECT  0 36.171 0.018 36.189 ;
        RECT  0 35.631 0.018 35.649 ;
        RECT  0 35.091 0.018 35.109 ;
        RECT  0 34.551 0.018 34.569 ;
        RECT  0 34.011 0.018 34.029 ;
        RECT  0 33.471 0.018 33.489 ;
        RECT  0 32.931 0.018 32.949 ;
        RECT  0 32.391 0.018 32.409 ;
        RECT  0 31.851 0.018 31.869 ;
        RECT  0 31.311 0.018 31.329 ;
        RECT  0 30.771 0.018 30.789 ;
        RECT  0 30.231 0.018 30.249 ;
        RECT  0 29.691 0.018 29.709 ;
        RECT  0 29.151 0.018 29.169 ;
        RECT  0 28.611 0.018 28.629 ;
        RECT  0 28.071 0.018 28.089 ;
        RECT  0 27.531 0.018 27.549 ;
        RECT  0 26.991 0.018 27.009 ;
        RECT  0 26.451 0.018 26.469 ;
        RECT  0 25.911 0.018 25.929 ;
        RECT  0 25.371 0.018 25.389 ;
        RECT  0 24.831 0.018 24.849 ;
        RECT  0 24.291 0.018 24.309 ;
        RECT  0 23.751 0.018 23.769 ;
        RECT  0 23.211 0.018 23.229 ;
        RECT  0 22.671 0.018 22.689 ;
        RECT  0 22.131 0.018 22.149 ;
        RECT  0 21.591 0.018 21.609 ;
        RECT  0 21.051 0.018 21.069 ;
        RECT  0 20.511 0.018 20.529 ;
        RECT  0 19.971 0.018 19.989 ;
        RECT  0 19.431 0.018 19.449 ;
        RECT  0 18.891 0.018 18.909 ;
        RECT  0 18.351 0.018 18.369 ;
        RECT  0 17.811 0.018 17.829 ;
        RECT  0 17.271 0.018 17.289 ;
        RECT  0 16.731 0.018 16.749 ;
        RECT  0 16.191 0.018 16.209 ;
        RECT  0 15.651 0.018 15.669 ;
        RECT  0 15.111 0.018 15.129 ;
        RECT  0 14.571 0.018 14.589 ;
        RECT  0 14.031 0.018 14.049 ;
        RECT  0 13.491 0.018 13.509 ;
        RECT  0 12.951 0.018 12.969 ;
        RECT  0 12.411 0.018 12.429 ;
        RECT  0 11.871 0.018 11.889 ;
        RECT  0 11.331 0.018 11.349 ;
        RECT  0 10.791 0.018 10.809 ;
        RECT  0 10.251 0.018 10.269 ;
        RECT  0 9.711 0.018 9.729 ;
        RECT  0 9.171 0.018 9.189 ;
        RECT  0 8.631 0.018 8.649 ;
        RECT  0 8.091 0.018 8.109 ;
        RECT  0 7.551 0.018 7.569 ;
        RECT  0 7.011 0.018 7.029 ;
        RECT  0 6.471 0.018 6.489 ;
        RECT  0 5.931 0.018 5.949 ;
        RECT  0 5.391 0.018 5.409 ;
        RECT  0 4.851 0.018 4.869 ;
        RECT  0 4.311 0.018 4.329 ;
        RECT  0 3.771 0.018 3.789 ;
        RECT  0 3.231 0.018 3.249 ;
        RECT  0 2.691 0.018 2.709 ;
        RECT  0 2.151 0.018 2.169 ;
        RECT  0 1.611 0.018 1.629 ;
        RECT  0 1.071 0.018 1.089 ;
        RECT  0 0.531 0.018 0.549 ;
    END
  END VSS
  OBS
    LAYER RVTN ;
     RECT  0 0.54 63.018 0.675 ;
     RECT  0 0.945 63.018 1.215 ;
     RECT  0 1.485 63.018 1.755 ;
     RECT  0 2.025 63.018 2.295 ;
     RECT  0 2.565 63.018 2.835 ;
     RECT  0 3.105 63.018 3.375 ;
     RECT  0 3.645 63.018 3.915 ;
     RECT  0 4.185 63.018 4.455 ;
     RECT  0 4.725 63.018 4.995 ;
     RECT  0 5.265 63.018 5.535 ;
     RECT  0 5.805 63.018 6.075 ;
     RECT  0 6.345 63.018 6.615 ;
     RECT  0 6.885 63.018 7.155 ;
     RECT  0 7.425 63.018 7.695 ;
     RECT  0 7.965 63.018 8.235 ;
     RECT  0 8.505 63.018 8.775 ;
     RECT  0 9.045 63.018 9.315 ;
     RECT  0 9.585 63.018 9.855 ;
     RECT  0 10.125 63.018 10.395 ;
     RECT  0 10.665 63.018 10.935 ;
     RECT  0 11.205 63.018 11.475 ;
     RECT  0 11.745 63.018 12.015 ;
     RECT  0 12.285 63.018 12.555 ;
     RECT  0 12.825 63.018 13.095 ;
     RECT  0 13.365 63.018 13.635 ;
     RECT  0 13.905 63.018 14.175 ;
     RECT  0 14.445 63.018 14.715 ;
     RECT  0 14.985 63.018 15.255 ;
     RECT  0 15.525 63.018 15.795 ;
     RECT  0 16.065 63.018 16.335 ;
     RECT  0 16.605 63.018 16.875 ;
     RECT  0 17.145 63.018 17.415 ;
     RECT  0 17.685 63.018 17.955 ;
     RECT  0 18.225 63.018 18.495 ;
     RECT  0 18.765 63.018 19.035 ;
     RECT  0 19.305 63.018 19.575 ;
     RECT  0 19.845 63.018 20.115 ;
     RECT  0 20.385 63.018 20.655 ;
     RECT  0 20.925 63.018 21.195 ;
     RECT  0 21.465 63.018 21.735 ;
     RECT  0 22.005 63.018 22.275 ;
     RECT  0 22.545 63.018 22.815 ;
     RECT  0 23.085 63.018 23.355 ;
     RECT  0 23.625 63.018 23.895 ;
     RECT  0 24.165 63.018 24.435 ;
     RECT  0 24.705 63.018 24.975 ;
     RECT  0 25.245 63.018 25.515 ;
     RECT  0 25.785 63.018 26.055 ;
     RECT  0 26.325 63.018 26.595 ;
     RECT  0 26.865 63.018 27.135 ;
     RECT  0 27.405 63.018 27.675 ;
     RECT  0 27.945 63.018 28.215 ;
     RECT  0 28.485 63.018 28.755 ;
     RECT  0 29.025 63.018 29.295 ;
     RECT  0 29.565 63.018 29.835 ;
     RECT  0 30.105 63.018 30.375 ;
     RECT  0 30.645 63.018 30.915 ;
     RECT  0 31.185 63.018 31.455 ;
     RECT  0 31.725 63.018 31.995 ;
     RECT  0 32.265 63.018 32.535 ;
     RECT  0 32.805 63.018 33.075 ;
     RECT  0 33.345 63.018 33.615 ;
     RECT  0 33.885 63.018 34.155 ;
     RECT  0 34.425 63.018 34.695 ;
     RECT  0 34.965 63.018 35.235 ;
     RECT  0 35.505 63.018 35.775 ;
     RECT  0 36.045 63.018 36.315 ;
     RECT  0 36.585 63.018 36.855 ;
     RECT  0 37.125 63.018 37.395 ;
     RECT  0 37.665 63.018 37.935 ;
     RECT  0 38.205 63.018 38.475 ;
     RECT  0 38.745 63.018 39.015 ;
     RECT  0 39.285 63.018 39.555 ;
     RECT  0 39.825 63.018 40.095 ;
     RECT  0 40.365 63.018 40.635 ;
     RECT  0 40.905 63.018 41.175 ;
     RECT  0 41.445 63.018 41.715 ;
     RECT  0 41.985 63.018 42.255 ;
     RECT  0 42.525 63.018 42.795 ;
     RECT  0 43.065 63.018 43.335 ;
     RECT  0 43.605 63.018 43.875 ;
     RECT  0 44.145 63.018 44.415 ;
     RECT  0 44.685 63.018 44.955 ;
     RECT  0 45.225 63.018 45.495 ;
     RECT  0 45.765 63.018 46.035 ;
     RECT  0 46.305 63.018 46.575 ;
     RECT  0 46.845 63.018 47.115 ;
     RECT  0 47.385 63.018 47.655 ;
     RECT  0 47.925 63.018 48.195 ;
     RECT  0 48.465 63.018 48.735 ;
     RECT  0 49.005 63.018 49.275 ;
     RECT  0 49.545 63.018 49.815 ;
     RECT  0 50.085 63.018 50.355 ;
     RECT  0 50.625 63.018 50.895 ;
     RECT  0 51.165 63.018 51.435 ;
     RECT  0 51.705 63.018 51.975 ;
     RECT  0 52.245 63.018 52.515 ;
     RECT  0 52.785 63.018 53.055 ;
     RECT  0 53.325 63.018 53.595 ;
     RECT  0 53.865 63.018 54.135 ;
     RECT  0 54.405 63.018 54.675 ;
     RECT  0 54.945 63.018 55.215 ;
     RECT  0 55.485 63.018 55.755 ;
     RECT  0 56.025 63.018 56.295 ;
     RECT  0 56.565 63.018 56.835 ;
     RECT  0 57.105 63.018 57.375 ;
     RECT  0 57.645 63.018 57.915 ;
     RECT  0 58.185 63.018 58.455 ;
     RECT  0 58.725 63.018 58.995 ;
     RECT  0 59.265 63.018 59.535 ;
     RECT  0 59.805 63.018 60.075 ;
     RECT  0 60.345 63.018 60.615 ;
     RECT  0 60.885 63.018 61.155 ;
     RECT  0 61.425 63.018 61.695 ;
     RECT  0 61.965 63.018 62.235 ;
     RECT  0 62.505 63.018 62.775 ;
     RECT  0 63.045 63.018 63.315 ;
     RECT  0 63.585 63.018 63.855 ;
    LAYER RVTP ;
     RECT  0 0.675 63.018 0.945 ;
     RECT  0 1.215 63.018 1.485 ;
     RECT  0 1.755 63.018 2.025 ;
     RECT  0 2.295 63.018 2.565 ;
     RECT  0 2.835 63.018 3.105 ;
     RECT  0 3.375 63.018 3.645 ;
     RECT  0 3.915 63.018 4.185 ;
     RECT  0 4.455 63.018 4.725 ;
     RECT  0 4.995 63.018 5.265 ;
     RECT  0 5.535 63.018 5.805 ;
     RECT  0 6.075 63.018 6.345 ;
     RECT  0 6.615 63.018 6.885 ;
     RECT  0 7.155 63.018 7.425 ;
     RECT  0 7.695 63.018 7.965 ;
     RECT  0 8.235 63.018 8.505 ;
     RECT  0 8.775 63.018 9.045 ;
     RECT  0 9.315 63.018 9.585 ;
     RECT  0 9.855 63.018 10.125 ;
     RECT  0 10.395 63.018 10.665 ;
     RECT  0 10.935 63.018 11.205 ;
     RECT  0 11.475 63.018 11.745 ;
     RECT  0 12.015 63.018 12.285 ;
     RECT  0 12.555 63.018 12.825 ;
     RECT  0 13.095 63.018 13.365 ;
     RECT  0 13.635 63.018 13.905 ;
     RECT  0 14.175 63.018 14.445 ;
     RECT  0 14.715 63.018 14.985 ;
     RECT  0 15.255 63.018 15.525 ;
     RECT  0 15.795 63.018 16.065 ;
     RECT  0 16.335 63.018 16.605 ;
     RECT  0 16.875 63.018 17.145 ;
     RECT  0 17.415 63.018 17.685 ;
     RECT  0 17.955 63.018 18.225 ;
     RECT  0 18.495 63.018 18.765 ;
     RECT  0 19.035 63.018 19.305 ;
     RECT  0 19.575 63.018 19.845 ;
     RECT  0 20.115 63.018 20.385 ;
     RECT  0 20.655 63.018 20.925 ;
     RECT  0 21.195 63.018 21.465 ;
     RECT  0 21.735 63.018 22.005 ;
     RECT  0 22.275 63.018 22.545 ;
     RECT  0 22.815 63.018 23.085 ;
     RECT  0 23.355 63.018 23.625 ;
     RECT  0 23.895 63.018 24.165 ;
     RECT  0 24.435 63.018 24.705 ;
     RECT  0 24.975 63.018 25.245 ;
     RECT  0 25.515 63.018 25.785 ;
     RECT  0 26.055 63.018 26.325 ;
     RECT  0 26.595 63.018 26.865 ;
     RECT  0 27.135 63.018 27.405 ;
     RECT  0 27.675 63.018 27.945 ;
     RECT  0 28.215 63.018 28.485 ;
     RECT  0 28.755 63.018 29.025 ;
     RECT  0 29.295 63.018 29.565 ;
     RECT  0 29.835 63.018 30.105 ;
     RECT  0 30.375 63.018 30.645 ;
     RECT  0 30.915 63.018 31.185 ;
     RECT  0 31.455 63.018 31.725 ;
     RECT  0 31.995 63.018 32.265 ;
     RECT  0 32.535 63.018 32.805 ;
     RECT  0 33.075 63.018 33.345 ;
     RECT  0 33.615 63.018 33.885 ;
     RECT  0 34.155 63.018 34.425 ;
     RECT  0 34.695 63.018 34.965 ;
     RECT  0 35.235 63.018 35.505 ;
     RECT  0 35.775 63.018 36.045 ;
     RECT  0 36.315 63.018 36.585 ;
     RECT  0 36.855 63.018 37.125 ;
     RECT  0 37.395 63.018 37.665 ;
     RECT  0 37.935 63.018 38.205 ;
     RECT  0 38.475 63.018 38.745 ;
     RECT  0 39.015 63.018 39.285 ;
     RECT  0 39.555 63.018 39.825 ;
     RECT  0 40.095 63.018 40.365 ;
     RECT  0 40.635 63.018 40.905 ;
     RECT  0 41.175 63.018 41.445 ;
     RECT  0 41.715 63.018 41.985 ;
     RECT  0 42.255 63.018 42.525 ;
     RECT  0 42.795 63.018 43.065 ;
     RECT  0 43.335 63.018 43.605 ;
     RECT  0 43.875 63.018 44.145 ;
     RECT  0 44.415 63.018 44.685 ;
     RECT  0 44.955 63.018 45.225 ;
     RECT  0 45.495 63.018 45.765 ;
     RECT  0 46.035 63.018 46.305 ;
     RECT  0 46.575 63.018 46.845 ;
     RECT  0 47.115 63.018 47.385 ;
     RECT  0 47.655 63.018 47.925 ;
     RECT  0 48.195 63.018 48.465 ;
     RECT  0 48.735 63.018 49.005 ;
     RECT  0 49.275 63.018 49.545 ;
     RECT  0 49.815 63.018 50.085 ;
     RECT  0 50.355 63.018 50.625 ;
     RECT  0 50.895 63.018 51.165 ;
     RECT  0 51.435 63.018 51.705 ;
     RECT  0 51.975 63.018 52.245 ;
     RECT  0 52.515 63.018 52.785 ;
     RECT  0 53.055 63.018 53.325 ;
     RECT  0 53.595 63.018 53.865 ;
     RECT  0 54.135 63.018 54.405 ;
     RECT  0 54.675 63.018 54.945 ;
     RECT  0 55.215 63.018 55.485 ;
     RECT  0 55.755 63.018 56.025 ;
     RECT  0 56.295 63.018 56.565 ;
     RECT  0 56.835 63.018 57.105 ;
     RECT  0 57.375 63.018 57.645 ;
     RECT  0 57.915 63.018 58.185 ;
     RECT  0 58.455 63.018 58.725 ;
     RECT  0 58.995 63.018 59.265 ;
     RECT  0 59.535 63.018 59.805 ;
     RECT  0 60.075 63.018 60.345 ;
     RECT  0 60.615 63.018 60.885 ;
     RECT  0 61.155 63.018 61.425 ;
     RECT  0 61.695 63.018 61.965 ;
     RECT  0 62.235 63.018 62.505 ;
     RECT  0 62.775 63.018 63.045 ;
     RECT  0 63.315 63.018 63.585 ;
     RECT  0 63.855 63.018 63.99 ;
    LAYER M1 ;
     RECT  0 0.531 63.018 63.999 ;
    LAYER M2 ;
     RECT  0 0.531 6.691 63.999 ;
     RECT  6.691 0.486 8.095 63.999 ;
     RECT  8.095 0.45 14.395 63.999 ;
     RECT  14.395 0.072 17.347 63.999 ;
     RECT  17.347 0.036 26.519 63.999 ;
     RECT  26.519 0.072 27.967 63.999 ;
     RECT  27.967 0.036 34.187 63.999 ;
     RECT  34.187 0.216 34.547 63.999 ;
     RECT  34.547 0.531 37.939 63.999 ;
     RECT  37.939 0.486 38.623 63.999 ;
     RECT  38.623 0.342 38.795 63.999 ;
     RECT  38.795 0.531 40.135 63.999 ;
     RECT  40.135 0.261 40.999 63.999 ;
     RECT  40.999 0.216 41.035 63.999 ;
     RECT  41.035 0.144 42.151 63.999 ;
     RECT  42.151 0.036 59.027 63.999 ;
     RECT  59.027 0.531 63.018 63.999 ;
    LAYER M3 ;
     RECT  22.68 0.031 22.77 0.043 ;
     RECT  42.156 0.031 42.174 0.043 ;
     RECT  14.076 0.043 14.094 0.067 ;
     RECT  17.352 0.031 17.37 0.067 ;
     RECT  33.336 0.043 33.354 0.067 ;
     RECT  34.164 0.031 34.182 0.067 ;
     RECT  42.156 0.043 42.462 0.067 ;
     RECT  59.004 0.031 59.022 0.067 ;
     RECT  14.076 0.067 14.418 0.091 ;
     RECT  17.1 0.067 17.406 0.091 ;
     RECT  19.836 0.043 19.854 0.091 ;
     RECT  21.348 0.067 21.438 0.091 ;
     RECT  22.464 0.043 23.202 0.091 ;
     RECT  26.496 0.031 26.514 0.091 ;
     RECT  44.064 0.043 44.082 0.091 ;
     RECT  16.632 0.091 17.406 0.103 ;
     RECT  25.992 0.091 26.514 0.103 ;
     RECT  42.156 0.067 42.498 0.103 ;
     RECT  14.076 0.091 14.706 0.139 ;
     RECT  18.684 0.091 18.702 0.139 ;
     RECT  19.476 0.091 19.854 0.139 ;
     RECT  25.308 0.103 26.514 0.139 ;
     RECT  28.98 0.043 29.106 0.139 ;
     RECT  31.608 0.043 31.842 0.139 ;
     RECT  33.336 0.067 34.182 0.139 ;
     RECT  42.156 0.103 42.75 0.139 ;
     RECT  52.704 0.091 52.722 0.139 ;
     RECT  18.612 0.139 19.854 0.175 ;
     RECT  57.024 0.103 57.042 0.175 ;
     RECT  16.236 0.103 17.406 0.187 ;
     RECT  21.348 0.091 23.202 0.187 ;
     RECT  24.696 0.139 26.514 0.187 ;
     RECT  27.972 0.031 27.99 0.187 ;
     RECT  28.98 0.139 29.25 0.187 ;
     RECT  30.132 0.139 30.402 0.187 ;
     RECT  31.608 0.139 31.95 0.187 ;
     RECT  33.156 0.139 34.182 0.187 ;
     RECT  40.32 0.139 41.058 0.187 ;
     RECT  42.156 0.139 42.822 0.187 ;
     RECT  52.164 0.139 52.722 0.187 ;
     RECT  24.372 0.187 27.99 0.211 ;
     RECT  31.608 0.187 34.182 0.211 ;
     RECT  46.656 0.139 46.674 0.211 ;
     RECT  15.948 0.187 17.406 0.235 ;
     RECT  18.612 0.175 20.214 0.235 ;
     RECT  31.608 0.211 34.542 0.235 ;
     RECT  37.404 0.187 37.926 0.235 ;
     RECT  38.664 0.187 39.042 0.235 ;
     RECT  40.32 0.187 42.822 0.235 ;
     RECT  43.596 0.091 44.874 0.235 ;
     RECT  18.612 0.235 20.574 0.256 ;
     RECT  21.348 0.187 23.454 0.256 ;
     RECT  24.372 0.211 28.206 0.256 ;
     RECT  28.944 0.187 30.402 0.256 ;
     RECT  40.176 0.235 44.874 0.256 ;
     RECT  18.612 0.256 23.454 0.283 ;
     RECT  24.372 0.256 30.69 0.283 ;
     RECT  31.5 0.235 34.542 0.283 ;
     RECT  35.316 0.187 35.334 0.283 ;
     RECT  37.404 0.235 39.042 0.283 ;
     RECT  40.14 0.256 44.874 0.283 ;
     RECT  18.612 0.283 44.874 0.301 ;
     RECT  15.804 0.235 17.406 0.331 ;
     RECT  15.804 0.331 17.73 0.337 ;
     RECT  18.54 0.301 44.874 0.337 ;
     RECT  15.804 0.337 45.162 0.379 ;
     RECT  14.076 0.139 15.066 0.445 ;
     RECT  13.68 0.445 15.066 0.472 ;
     RECT  15.804 0.379 45.306 0.472 ;
     RECT  48.312 0.283 48.33 0.481 ;
     RECT  11.268 0.475 11.286 0.523 ;
     RECT  53.82 0.475 53.838 0.523 ;
     RECT  58.716 0.067 59.022 0.523 ;
     RECT  6.696 0.481 6.714 0.571 ;
     RECT  11.055 0.523 11.286 0.571 ;
     RECT  13.68 0.472 45.306 0.571 ;
     RECT  46.656 0.211 47.25 0.571 ;
     RECT  48.312 0.481 49.086 0.571 ;
     RECT  50.364 0.235 50.382 0.571 ;
     RECT  53.82 0.523 54.345 0.571 ;
     RECT  55.44 0.139 55.458 0.571 ;
     RECT  3.924 0.571 4.482 0.607 ;
     RECT  11.016 0.571 11.97 0.607 ;
     RECT  12.744 0.571 12.762 0.607 ;
     RECT  13.5 0.571 45.306 0.607 ;
     RECT  51.768 0.187 52.722 0.607 ;
     RECT  53.82 0.571 55.458 0.607 ;
     RECT  56.628 0.175 57.042 0.607 ;
     RECT  10.908 0.607 11.97 0.619 ;
     RECT  46.188 0.571 49.086 0.619 ;
     RECT  50.184 0.571 51.03 0.619 ;
     RECT  3.924 0.607 4.842 0.643 ;
     RECT  8.1 0.445 8.118 0.643 ;
     RECT  9.72 0.571 9.738 0.643 ;
     RECT  10.836 0.619 11.97 0.643 ;
     RECT  12.744 0.607 45.306 0.643 ;
     RECT  8.1 0.643 8.262 0.679 ;
     RECT  46.188 0.619 51.03 0.679 ;
     RECT  3.888 0.643 4.842 0.715 ;
     RECT  5.655 0.523 5.745 0.715 ;
     RECT  6.48 0.571 7.182 0.715 ;
     RECT  8.1 0.679 8.766 0.715 ;
     RECT  9.504 0.643 9.738 0.715 ;
     RECT  10.836 0.643 45.306 0.715 ;
     RECT  2.844 0.643 2.862 0.751 ;
     RECT  3.78 0.715 4.842 0.751 ;
     RECT  5.655 0.715 45.378 0.751 ;
     RECT  46.116 0.679 51.03 0.751 ;
     RECT  51.768 0.607 55.458 0.751 ;
     RECT  56.52 0.607 57.042 0.751 ;
     RECT  0.255 0.523 0.345 0.793 ;
     RECT  58.716 0.523 59.745 0.793 ;
     RECT  2.844 0.751 55.458 0.811 ;
     RECT  56.232 0.751 57.042 0.811 ;
     RECT  2.844 0.811 57.042 1.111 ;
     RECT  2.7 1.111 57.042 1.219 ;
     RECT  58.716 0.793 59.937 1.219 ;
     RECT  58.536 1.219 59.937 1.255 ;
     RECT  2.7 1.219 57.654 1.291 ;
     RECT  58.536 1.255 60.138 1.291 ;
     RECT  62.136 1.381 62.154 1.481 ;
     RECT  0.255 0.793 0.537 1.525 ;
     RECT  2.7 1.291 60.138 1.525 ;
     RECT  60.948 1.381 60.966 1.525 ;
     RECT  2.7 1.525 60.966 1.561 ;
     RECT  62.028 1.525 62.046 1.565 ;
     RECT  0.255 1.525 1.17 1.687 ;
     RECT  1.944 1.561 61.218 1.687 ;
     RECT  0.255 1.687 61.218 1.957 ;
     RECT  0.255 1.957 61.614 2.263 ;
     RECT  0.216 2.263 61.614 2.605 ;
     RECT  0.216 2.605 61.65 2.803 ;
     RECT  0.216 2.803 61.902 3.451 ;
     RECT  0.216 3.451 62.118 3.541 ;
     RECT  0.216 3.541 62.478 3.685 ;
     RECT  0.216 3.685 62.694 3.965 ;
     RECT  0.216 3.965 62.658 5.881 ;
     RECT  0.216 5.881 62.694 6.143 ;
     RECT  0.252 6.143 62.694 6.173 ;
     RECT  0.255 6.173 62.694 6.961 ;
     RECT  0.255 6.961 62.766 7.195 ;
     RECT  0.255 7.195 62.802 7.349 ;
     RECT  0.255 7.349 62.694 7.385 ;
     RECT  0.255 7.385 62.334 7.712 ;
     RECT  0.18 7.712 62.334 7.997 ;
     RECT  0.255 7.997 62.334 8.275 ;
     RECT  0.255 8.275 62.586 8.491 ;
     RECT  0.255 8.491 62.622 8.977 ;
     RECT  0.255 8.977 62.766 9.121 ;
     RECT  0.255 9.121 62.802 9.239 ;
     RECT  0.255 9.239 62.766 9.895 ;
     RECT  0.252 9.895 62.766 10.205 ;
     RECT  0.255 10.205 62.766 10.411 ;
     RECT  0.255 10.411 62.91 11.209 ;
     RECT  0.18 11.209 62.91 13.865 ;
     RECT  0.216 13.865 62.91 15.989 ;
     RECT  0.255 15.989 62.91 17.419 ;
     RECT  0.216 17.419 62.91 17.879 ;
     RECT  0.255 17.879 62.91 18.811 ;
     RECT  0.216 18.811 62.91 22.811 ;
     RECT  0.216 22.811 62.874 23.189 ;
     RECT  0.255 23.189 62.874 23.621 ;
     RECT  0.255 23.621 62.766 24.077 ;
     RECT  0.255 24.077 62.586 24.943 ;
     RECT  0.255 24.943 62.802 25.825 ;
     RECT  0.216 25.825 62.802 25.987 ;
     RECT  0.18 25.987 62.802 27.599 ;
     RECT  0.18 27.599 62.766 29.021 ;
     RECT  0.216 29.021 62.766 29.219 ;
     RECT  0.216 29.219 62.586 30.379 ;
     RECT  0.18 30.379 62.586 30.451 ;
     RECT  0.18 30.451 62.694 30.721 ;
     RECT  0.18 30.721 62.802 30.811 ;
     RECT  0.108 30.811 62.802 31.145 ;
     RECT  0.108 31.145 62.658 31.415 ;
     RECT  0.216 31.415 62.658 32.765 ;
     RECT  0.255 32.765 62.658 32.809 ;
     RECT  0.255 32.809 62.802 33.547 ;
     RECT  0.216 33.547 62.802 34.051 ;
     RECT  0.216 34.051 62.838 34.157 ;
     RECT  0.216 34.157 62.766 34.397 ;
     RECT  0.255 34.397 62.766 35.159 ;
     RECT  0.255 35.159 62.73 35.851 ;
     RECT  0.216 35.851 62.73 36.275 ;
     RECT  0.216 36.275 62.694 37.129 ;
     RECT  0.216 37.129 62.838 39.353 ;
     RECT  0.216 39.353 62.766 40.171 ;
     RECT  0.216 40.171 62.802 40.675 ;
     RECT  0.216 40.675 62.874 41.791 ;
     RECT  0.18 41.791 62.874 42.449 ;
     RECT  0.18 42.449 62.838 42.629 ;
     RECT  0.255 42.629 62.838 42.719 ;
     RECT  0.255 42.719 62.802 42.989 ;
     RECT  0.255 42.989 62.766 44.221 ;
     RECT  0.255 44.221 62.802 45.547 ;
     RECT  0.255 45.547 62.874 45.599 ;
     RECT  0.255 45.599 62.766 46.373 ;
     RECT  2.844 46.373 62.766 46.381 ;
     RECT  2.844 46.381 62.838 46.445 ;
     RECT  2.844 46.445 62.73 46.535 ;
     RECT  3.348 46.535 62.73 46.679 ;
     RECT  0.255 46.373 1.998 46.685 ;
     RECT  3.384 46.679 62.73 46.769 ;
     RECT  1.404 46.685 1.998 46.805 ;
     RECT  4.644 46.769 62.73 46.805 ;
     RECT  3.384 46.769 3.762 46.829 ;
     RECT  1.98 46.805 1.998 46.841 ;
     RECT  3.384 46.829 3.582 47.039 ;
     RECT  4.644 46.805 62.694 47.039 ;
     RECT  3.564 47.039 3.582 47.219 ;
     RECT  4.896 47.039 62.694 47.803 ;
     RECT  4.896 47.803 62.802 48.271 ;
     RECT  4.896 48.271 62.874 48.317 ;
     RECT  4.896 48.317 62.766 48.505 ;
     RECT  4.428 48.505 62.766 49.109 ;
     RECT  4.572 49.109 62.766 49.432 ;
     RECT  4.572 49.432 62.802 50.141 ;
     RECT  4.572 50.141 62.694 50.153 ;
     RECT  4.68 50.153 62.694 50.315 ;
     RECT  5.256 50.315 62.694 50.855 ;
     RECT  36.684 50.855 62.694 51.355 ;
     RECT  5.256 50.855 35.946 51.637 ;
     RECT  5.112 51.637 35.946 51.677 ;
     RECT  5.4 51.677 35.946 51.745 ;
     RECT  36.684 51.355 62.73 51.745 ;
     RECT  5.4 51.745 62.73 51.781 ;
     RECT  5.4 51.781 62.838 51.821 ;
     RECT  5.4 51.821 62.802 52.169 ;
     RECT  5.655 52.169 62.802 52.445 ;
     RECT  5.655 52.445 62.73 52.781 ;
     RECT  5.655 52.781 62.658 52.979 ;
     RECT  5.655 52.979 62.514 53.015 ;
     RECT  5.655 53.015 62.406 54.095 ;
     RECT  8.028 54.095 62.406 54.175 ;
     RECT  5.655 54.095 7.254 54.437 ;
     RECT  5.655 54.437 6.462 54.599 ;
     RECT  7.236 54.437 7.254 54.599 ;
     RECT  8.028 54.175 62.55 54.599 ;
     RECT  5.655 54.599 6.318 54.635 ;
     RECT  8.028 54.599 62.262 55.175 ;
     RECT  8.244 55.175 62.262 55.517 ;
     RECT  8.496 55.517 62.262 55.525 ;
     RECT  8.496 55.525 62.442 55.795 ;
     RECT  8.496 55.795 62.73 55.997 ;
     RECT  8.676 55.997 62.73 56.335 ;
     RECT  8.676 56.335 62.766 56.399 ;
     RECT  9.396 56.399 62.766 57.065 ;
     RECT  9.684 57.065 62.766 57.173 ;
     RECT  9.756 57.173 62.766 57.479 ;
     RECT  9.972 57.479 62.766 57.569 ;
     RECT  9.972 57.569 62.622 57.875 ;
     RECT  9.972 57.875 62.514 58.451 ;
     RECT  10.548 58.451 62.514 58.649 ;
     RECT  14.184 58.649 62.514 58.691 ;
     RECT  14.292 58.691 62.514 59.161 ;
     RECT  10.548 58.649 13.374 59.225 ;
     RECT  14.292 59.161 62.55 59.225 ;
     RECT  15.228 59.225 62.55 59.305 ;
     RECT  14.292 59.225 14.454 59.459 ;
     RECT  15.228 59.305 62.874 59.459 ;
     RECT  15.588 59.459 62.874 59.495 ;
     RECT  14.292 59.459 14.31 59.603 ;
     RECT  10.548 59.225 11.337 59.639 ;
     RECT  12.204 59.225 13.374 59.648 ;
     RECT  12.924 59.648 13.374 59.765 ;
     RECT  12.924 59.765 12.942 59.837 ;
     RECT  15.876 59.495 62.874 59.999 ;
     RECT  16.308 59.999 62.874 60.269 ;
     RECT  16.455 60.269 62.874 60.539 ;
     RECT  18.108 60.539 62.874 60.989 ;
     RECT  18.144 60.989 62.874 61.115 ;
     RECT  18.216 61.115 62.874 61.259 ;
     RECT  18.72 61.259 62.874 62.033 ;
     RECT  18.72 62.033 18.882 62.159 ;
     RECT  19.656 62.033 62.874 62.159 ;
     RECT  18.72 62.159 18.738 62.195 ;
     RECT  19.692 62.159 62.874 62.303 ;
     RECT  19.692 62.303 62.334 62.429 ;
     RECT  19.692 62.429 20.718 62.699 ;
     RECT  19.692 62.699 20.682 62.879 ;
     RECT  19.692 62.879 19.818 62.969 ;
     RECT  20.556 62.879 20.682 62.969 ;
     RECT  19.692 62.969 19.71 63.005 ;
     RECT  20.556 62.969 20.574 63.005 ;
     RECT  21.855 62.429 62.334 63.005 ;
     RECT  23.04 63.005 62.334 63.049 ;
     RECT  23.04 63.049 62.55 63.239 ;
     RECT  23.04 63.239 58.23 63.509 ;
     RECT  23.04 63.509 29.826 63.545 ;
     RECT  30.924 63.509 58.23 63.545 ;
     RECT  30.924 63.545 56.394 63.617 ;
     RECT  59.004 63.239 62.226 63.617 ;
     RECT  24.66 63.545 29.826 63.653 ;
     RECT  39.42 63.617 56.394 63.653 ;
     RECT  24.66 63.653 28.494 63.689 ;
     RECT  30.924 63.617 38.682 63.689 ;
     RECT  39.42 63.653 41.886 63.689 ;
     RECT  45.108 63.653 51.858 63.689 ;
     RECT  0.255 46.685 0.537 63.737 ;
     RECT  5.655 54.635 5.937 63.737 ;
     RECT  11.055 59.639 11.337 63.737 ;
     RECT  16.455 60.539 16.737 63.737 ;
     RECT  21.855 63.005 22.137 63.737 ;
     RECT  23.436 63.545 23.706 63.779 ;
     RECT  24.66 63.689 25.722 63.779 ;
     RECT  26.532 63.689 28.494 63.779 ;
     RECT  29.304 63.653 29.826 63.779 ;
     RECT  30.924 63.689 36.522 63.779 ;
     RECT  37.368 63.689 38.682 63.779 ;
     RECT  39.924 63.689 41.886 63.779 ;
     RECT  42.66 63.653 44.298 63.779 ;
     RECT  45.108 63.689 49.338 63.779 ;
     RECT  50.148 63.689 51.858 63.779 ;
     RECT  52.596 63.653 56.394 63.779 ;
     RECT  57.348 63.545 58.23 63.779 ;
     RECT  59.004 63.617 60.21 63.779 ;
     RECT  61.056 63.617 62.226 63.779 ;
     RECT  25.38 63.779 25.398 63.815 ;
     RECT  29.808 63.779 29.826 63.815 ;
     RECT  31.68 63.779 31.698 63.815 ;
     RECT  32.544 63.779 33.678 63.815 ;
     RECT  34.776 63.779 34.794 63.815 ;
     RECT  41.616 63.779 41.742 63.815 ;
     RECT  46.404 63.779 47.142 63.815 ;
     RECT  48.132 63.779 48.15 63.815 ;
     RECT  50.364 63.779 50.382 63.815 ;
     RECT  51.444 63.779 51.462 63.815 ;
     RECT  53.352 63.779 54.918 63.815 ;
     RECT  56.232 63.779 56.25 63.815 ;
     RECT  57.348 63.779 57.366 63.815 ;
     RECT  59.847 63.779 60.102 63.815 ;
     RECT  61.056 63.779 61.074 63.815 ;
     RECT  62.064 63.779 62.082 63.815 ;
     RECT  41.724 63.815 41.742 63.821 ;
     RECT  42.804 63.779 42.822 63.824 ;
     RECT  32.544 63.815 32.937 63.851 ;
     RECT  36.072 63.779 36.09 63.851 ;
     RECT  38.247 63.779 38.502 63.851 ;
     RECT  39.924 63.779 40.338 63.851 ;
     RECT  46.404 63.815 46.422 63.851 ;
     RECT  53.352 63.815 54.537 63.851 ;
     RECT  0.447 63.737 0.537 64.007 ;
     RECT  5.847 63.737 5.937 64.007 ;
     RECT  11.247 63.737 11.337 64.007 ;
     RECT  16.647 63.737 16.737 64.007 ;
     RECT  22.047 63.737 22.137 64.007 ;
     RECT  27.447 63.779 27.537 64.007 ;
     RECT  32.847 63.851 32.937 64.007 ;
     RECT  38.247 63.851 38.337 64.007 ;
     RECT  43.647 63.779 43.737 64.007 ;
     RECT  49.047 63.779 49.137 64.007 ;
     RECT  54.447 63.851 54.537 64.007 ;
     RECT  59.847 63.815 59.937 64.007 ;
    LAYER M4 ;
     RECT  0.125 7.728 0.169 7.752 ;
     RECT  0.133 6.144 0.248 6.168 ;
     RECT  0.169 7.728 0.248 7.992 ;
     RECT  0.241 10.176 0.248 10.2 ;
     RECT  0.133 17.616 0.248 17.64 ;
     RECT  0.133 18.816 0.248 18.84 ;
     RECT  0.133 20.304 0.248 20.328 ;
     RECT  0.169 28.992 0.248 29.016 ;
     RECT  0.133 30.144 0.248 31.944 ;
     RECT  0.133 34.368 0.248 34.392 ;
     RECT  0.133 36.24 0.248 36.264 ;
     RECT  0.205 42.192 0.248 42.216 ;
     RECT  0.248 0.528 0.352 63.732 ;
     RECT  0.352 0.798 0.44 63.732 ;
     RECT  0.44 0.798 0.544 64.002 ;
     RECT  0.544 9.12 0.659 10.776 ;
     RECT  0.659 10.176 0.677 10.776 ;
     RECT  0.677 10.752 0.707 10.776 ;
     RECT  0.544 43.728 0.707 44.712 ;
     RECT  0.544 6.288 0.755 8.04 ;
     RECT  0.544 2.112 0.899 2.136 ;
     RECT  0.544 16.272 0.929 18.84 ;
     RECT  0.544 23.952 0.947 24.504 ;
     RECT  0.544 34.752 1.001 42.216 ;
     RECT  0.755 7.968 1.073 8.04 ;
     RECT  0.544 22.08 1.139 22.104 ;
     RECT  0.544 46.656 1.139 46.68 ;
     RECT  0.544 3.264 1.18 3.288 ;
     RECT  0.707 44.688 1.181 44.712 ;
     RECT  0.544 12.288 1.253 15.192 ;
     RECT  1.001 34.752 1.289 40.68 ;
     RECT  0.929 16.32 1.379 18.84 ;
     RECT  1.073 7.968 1.397 7.992 ;
     RECT  1.289 34.752 1.433 35.448 ;
     RECT  0.544 20.688 1.469 20.712 ;
     RECT  1.532 19.632 1.537 19.656 ;
     RECT  0.544 31.92 1.537 31.944 ;
     RECT  0.947 23.952 1.573 23.976 ;
     RECT  0.544 28.416 1.573 29.016 ;
     RECT  0.659 9.12 1.609 9.144 ;
     RECT  1.537 19.632 1.619 20.328 ;
     RECT  1.289 36.48 1.649 40.68 ;
     RECT  0.544 4.8 1.681 4.824 ;
     RECT  0.755 6.288 1.681 6.84 ;
     RECT  1.001 42.192 1.681 42.216 ;
     RECT  1.379 16.32 1.715 18.12 ;
     RECT  1.619 20.016 1.715 20.328 ;
     RECT  1.649 38.16 1.715 40.68 ;
     RECT  1.681 3.984 1.717 6.84 ;
     RECT  1.681 42.192 1.717 42.984 ;
     RECT  1.717 3.984 1.721 7.56 ;
     RECT  1.573 28.368 1.721 29.016 ;
     RECT  1.715 38.16 1.756 38.184 ;
     RECT  1.721 3.984 1.763 6.312 ;
     RECT  1.609 9.072 1.825 9.144 ;
     RECT  1.717 26.208 1.825 26.232 ;
     RECT  1.715 16.32 1.829 17.928 ;
     RECT  1.715 39.648 1.829 40.68 ;
     RECT  1.825 9.072 1.897 9.96 ;
     RECT  1.253 12.48 1.901 15.192 ;
     RECT  0.544 33.408 1.969 33.432 ;
     RECT  1.433 34.752 1.969 35.352 ;
     RECT  1.763 3.984 1.973 6.168 ;
     RECT  1.537 31.92 2.041 32.376 ;
     RECT  1.969 33.408 2.041 35.352 ;
     RECT  1.715 20.304 2.044 20.328 ;
     RECT  1.825 25.92 2.221 26.232 ;
     RECT  2.221 25.248 2.245 26.232 ;
     RECT  2.113 30.528 2.252 30.888 ;
     RECT  1.721 28.368 2.257 28.584 ;
     RECT  1.721 7.536 2.261 7.56 ;
     RECT  1.969 21.36 2.291 21.384 ;
     RECT  1.573 23.088 2.293 23.976 ;
     RECT  2.245 25.056 2.293 26.232 ;
     RECT  2.293 23.088 2.329 26.232 ;
     RECT  1.897 9.072 2.365 10.056 ;
     RECT  1.901 12.576 2.365 15.192 ;
     RECT  1.829 16.32 2.365 16.824 ;
     RECT  1.717 42.192 2.365 43.848 ;
     RECT  2.341 45.648 2.365 45.672 ;
     RECT  2.365 12.576 2.369 16.824 ;
     RECT  2.041 41.04 2.473 41.112 ;
     RECT  2.041 31.92 2.477 35.352 ;
     RECT  1.649 36.48 2.477 37.128 ;
     RECT  2.477 31.92 2.483 34.824 ;
     RECT  2.365 42.192 2.585 45.672 ;
     RECT  2.252 30 2.588 30.888 ;
     RECT  2.483 31.92 2.588 34.776 ;
     RECT  2.581 2.448 2.617 2.472 ;
     RECT  1.973 3.984 2.617 5.928 ;
     RECT  2.473 41.04 2.617 41.208 ;
     RECT  2.585 42.192 2.617 45.528 ;
     RECT  2.617 21.648 2.725 21.672 ;
     RECT  2.329 23.04 2.725 26.232 ;
     RECT  2.365 9.072 2.761 10.344 ;
     RECT  1.813 11.328 2.761 11.352 ;
     RECT  2.257 28.176 2.761 28.584 ;
     RECT  2.588 30 2.761 34.776 ;
     RECT  2.369 16.128 2.797 16.824 ;
     RECT  1.829 17.904 2.797 17.928 ;
     RECT  2.617 2.448 2.821 5.928 ;
     RECT  2.689 38.112 2.828 38.136 ;
     RECT  2.477 37.056 2.833 37.128 ;
     RECT  2.828 38.112 2.833 38.616 ;
     RECT  2.821 1.68 2.867 5.928 ;
     RECT  2.761 28.176 2.867 34.776 ;
     RECT  2.369 12.576 2.915 14.856 ;
     RECT  2.867 28.176 2.915 34.488 ;
     RECT  2.833 37.056 2.915 38.616 ;
     RECT  2.797 16.128 2.945 17.928 ;
     RECT  2.725 21.648 2.945 26.232 ;
     RECT  2.867 1.68 3.017 1.704 ;
     RECT  2.761 9.072 3.017 11.352 ;
     RECT  3.017 9.072 3.049 11.256 ;
     RECT  2.915 12.576 3.053 13.56 ;
     RECT  2.617 41.04 3.053 45.528 ;
     RECT  3.053 44.4 3.089 45.528 ;
     RECT  1.829 39.648 3.125 39.912 ;
     RECT  2.945 16.512 3.148 17.928 ;
     RECT  3.041 19.632 3.253 19.656 ;
     RECT  3.148 16.512 3.34 17.064 ;
     RECT  3.253 18.144 3.34 19.656 ;
     RECT  2.867 2.736 3.341 5.928 ;
     RECT  3.049 8.976 3.341 11.256 ;
     RECT  3.089 44.4 3.413 45.24 ;
     RECT  3.053 41.04 3.443 43.368 ;
     RECT  3.125 39.888 3.481 39.912 ;
     RECT  3.341 5.808 3.493 5.928 ;
     RECT  3.341 2.736 3.521 4.776 ;
     RECT  2.915 28.176 3.521 28.44 ;
     RECT  3.521 4.128 3.557 4.776 ;
     RECT  3.557 4.128 3.58 4.632 ;
     RECT  3.481 39.888 3.589 40.008 ;
     RECT  3.443 41.04 3.589 43.224 ;
     RECT  2.945 21.648 3.661 25.176 ;
     RECT  3.521 2.736 3.665 3.096 ;
     RECT  3.665 2.832 3.676 3.096 ;
     RECT  3.589 39.888 3.676 43.224 ;
     RECT  3.413 44.4 3.773 45 ;
     RECT  3.685 46.8 3.773 46.824 ;
     RECT  2.945 26.208 3.805 26.232 ;
     RECT  3.733 27.36 3.805 27.384 ;
     RECT  3.053 12.768 3.877 13.56 ;
     RECT  2.915 14.784 3.877 14.856 ;
     RECT  2.915 37.056 3.877 38.28 ;
     RECT  3.493 5.808 4.057 6.84 ;
     RECT  3.34 16.512 4.057 17.016 ;
     RECT  3.805 26.208 4.061 27.384 ;
     RECT  2.915 29.76 4.061 34.488 ;
     RECT  3.877 12.768 4.117 14.856 ;
     RECT  4.057 16.368 4.117 17.016 ;
     RECT  4.061 29.76 4.169 30.792 ;
     RECT  3.661 21.552 4.201 25.176 ;
     RECT  4.061 26.208 4.201 27.192 ;
     RECT  4.117 12.768 4.204 17.016 ;
     RECT  4.204 12.768 4.237 14.808 ;
     RECT  4.22 28.464 4.261 28.488 ;
     RECT  4.169 29.76 4.261 30.6 ;
     RECT  4.261 28.464 4.307 30.6 ;
     RECT  4.307 28.704 4.348 30.6 ;
     RECT  3.676 41.616 4.355 43.224 ;
     RECT  3.877 36.816 4.381 38.28 ;
     RECT  4.061 31.776 4.385 34.488 ;
     RECT  4.057 19.68 4.453 19.704 ;
     RECT  3.373 0.912 4.489 0.936 ;
     RECT  3.34 18.144 4.508 18.216 ;
     RECT  4.453 19.68 4.508 19.992 ;
     RECT  4.508 18.144 4.565 19.992 ;
     RECT  4.355 41.616 4.573 42.312 ;
     RECT  4.565 18.768 4.643 19.992 ;
     RECT  3.773 44.976 4.645 45 ;
     RECT  4.057 5.808 4.741 6.936 ;
     RECT  4.381 36.816 4.777 38.76 ;
     RECT  3.676 39.888 4.777 39.912 ;
     RECT  4.741 5.52 4.837 6.936 ;
     RECT  2.689 7.968 4.837 7.992 ;
     RECT  4.204 16.176 4.892 17.016 ;
     RECT  4.489 0.816 5.029 0.936 ;
     RECT  3.58 4.128 5.029 4.248 ;
     RECT  4.837 5.52 5.029 7.992 ;
     RECT  4.892 16.176 5.029 17.064 ;
     RECT  4.777 36.816 5.057 39.912 ;
     RECT  3.676 3.072 5.101 3.096 ;
     RECT  5.029 4.128 5.101 7.992 ;
     RECT  4.885 35.328 5.132 35.448 ;
     RECT  5.029 16.176 5.137 17.16 ;
     RECT  4.237 12.528 5.173 14.808 ;
     RECT  5.137 16.176 5.173 17.496 ;
     RECT  4.643 19.776 5.173 19.992 ;
     RECT  4.201 21.264 5.173 27.192 ;
     RECT  5.101 3.072 5.245 7.992 ;
     RECT  3.341 9.072 5.245 11.256 ;
     RECT  5.057 36.72 5.245 39.912 ;
     RECT  4.849 43.824 5.245 43.848 ;
     RECT  4.645 44.976 5.245 45.864 ;
     RECT  5.132 35.328 5.276 35.64 ;
     RECT  5.245 36.72 5.276 40.056 ;
     RECT  5.276 35.328 5.281 40.056 ;
     RECT  5.245 3.072 5.317 11.256 ;
     RECT  5.173 12.528 5.317 17.496 ;
     RECT  5.077 51.648 5.389 51.672 ;
     RECT  5.029 0.816 5.461 1.704 ;
     RECT  5.317 3.072 5.461 17.496 ;
     RECT  4.957 48.288 5.497 48.312 ;
     RECT  5.137 49.872 5.497 49.896 ;
     RECT  4.348 28.704 5.509 30.36 ;
     RECT  4.573 42.192 5.569 42.312 ;
     RECT  5.245 43.824 5.569 45.864 ;
     RECT  5.173 19.776 5.605 27.192 ;
     RECT  5.509 28.416 5.605 30.36 ;
     RECT  5.461 0.816 5.648 17.496 ;
     RECT  4.643 18.768 5.648 18.792 ;
     RECT  5.605 19.776 5.648 30.36 ;
     RECT  4.385 31.776 5.648 34.248 ;
     RECT  5.281 35.328 5.648 40.968 ;
     RECT  5.569 42.192 5.648 45.864 ;
     RECT  4.604 46.992 5.648 47.016 ;
     RECT  5.497 48.288 5.648 49.896 ;
     RECT  5.389 51.648 5.648 51.96 ;
     RECT  5.648 0.528 5.752 63.732 ;
     RECT  5.752 0.72 5.84 63.732 ;
     RECT  5.84 0.72 5.944 64.002 ;
     RECT  5.944 35.808 5.969 40.92 ;
     RECT  5.944 0.72 6.083 18.264 ;
     RECT  5.944 44.16 6.149 45 ;
     RECT  5.944 33.648 6.157 34.776 ;
     RECT  5.944 50.832 6.227 52.392 ;
     RECT  5.944 19.248 6.257 29.592 ;
     RECT  6.157 34.176 6.257 34.776 ;
     RECT  5.944 46.128 6.257 47.016 ;
     RECT  6.083 0.72 6.293 11.784 ;
     RECT  6.293 9.12 6.323 11.784 ;
     RECT  5.944 42.048 6.323 43.176 ;
     RECT  6.227 50.832 6.323 51.624 ;
     RECT  6.257 19.248 6.365 29.064 ;
     RECT  6.149 44.976 6.545 45 ;
     RECT  6.293 0.72 6.581 7.992 ;
     RECT  6.323 50.832 6.617 51.432 ;
     RECT  6.083 12.864 6.761 18.264 ;
     RECT  6.257 34.176 6.797 34.536 ;
     RECT  5.944 30.768 6.803 31.416 ;
     RECT  6.617 51.312 6.851 51.432 ;
     RECT  6.851 51.312 6.869 51.336 ;
     RECT  5.944 48.384 6.899 49.176 ;
     RECT  6.761 13.296 6.94 18.264 ;
     RECT  5.944 53.76 6.947 53.784 ;
     RECT  6.323 42.624 6.949 43.176 ;
     RECT  6.365 20.016 6.995 29.064 ;
     RECT  5.969 35.808 7.009 38.712 ;
     RECT  5.969 39.888 7.009 40.92 ;
     RECT  6.949 42.624 7.036 43.272 ;
     RECT  6.803 30.768 7.045 30.792 ;
     RECT  6.94 14.88 7.093 18.264 ;
     RECT  6.995 25.68 7.193 29.064 ;
     RECT  6.797 34.176 7.193 34.488 ;
     RECT  6.257 46.176 7.193 47.016 ;
     RECT  6.323 9.12 7.261 11.304 ;
     RECT  7.036 42.624 7.297 43.176 ;
     RECT  7.193 26.352 7.373 29.064 ;
     RECT  7.189 32.928 7.427 32.952 ;
     RECT  7.153 45.168 7.427 45.192 ;
     RECT  7.297 42.528 7.475 43.176 ;
     RECT  7.436 31.92 7.523 31.944 ;
     RECT  7.193 46.176 7.553 46.2 ;
     RECT  7.009 35.808 7.589 40.92 ;
     RECT  7.261 9.024 7.657 11.304 ;
     RECT  7.589 36.432 7.657 40.92 ;
     RECT  7.475 42.528 7.657 42.552 ;
     RECT  7.373 26.736 7.676 29.064 ;
     RECT  6.899 48.96 7.676 49.176 ;
     RECT  6.581 3.312 7.765 7.992 ;
     RECT  7.657 9.024 7.765 11.784 ;
     RECT  7.676 26.736 7.805 29.112 ;
     RECT  7.765 3.312 7.837 12.264 ;
     RECT  6.94 13.296 7.837 13.656 ;
     RECT  7.045 30.144 7.837 30.792 ;
     RECT  7.676 48.96 7.877 50.04 ;
     RECT  7.193 34.464 7.909 34.488 ;
     RECT  7.909 34.464 7.945 34.728 ;
     RECT  7.837 3.312 7.957 13.656 ;
     RECT  6.995 20.016 7.957 24.696 ;
     RECT  7.873 53.568 8.017 53.592 ;
     RECT  7.945 34.464 8.029 35.352 ;
     RECT  7.957 51.6 8.044 51.624 ;
     RECT  6.581 0.72 8.053 2.328 ;
     RECT  7.957 3.312 8.053 13.8 ;
     RECT  8.017 53.088 8.06 53.592 ;
     RECT  7.093 14.88 8.089 18.888 ;
     RECT  7.957 20.016 8.089 25.08 ;
     RECT  8.06 53.088 8.089 54.552 ;
     RECT  7.657 36.432 8.093 42.552 ;
     RECT  8.017 43.872 8.101 43.896 ;
     RECT  7.805 28.416 8.125 29.112 ;
     RECT  7.837 30.144 8.125 30.84 ;
     RECT  8.053 0.72 8.156 13.8 ;
     RECT  8.089 14.88 8.156 25.08 ;
     RECT  7.573 47.184 8.161 47.592 ;
     RECT  8.089 53.088 8.195 54.744 ;
     RECT  8.195 53.088 8.209 54.072 ;
     RECT  8.089 33.312 8.233 33.336 ;
     RECT  8.029 34.464 8.233 34.92 ;
     RECT  8.156 0.72 8.237 25.704 ;
     RECT  8.093 37.44 8.291 42.552 ;
     RECT  8.161 47.184 8.305 47.928 ;
     RECT  8.209 53.088 8.389 53.112 ;
     RECT  8.125 28.416 8.435 30.84 ;
     RECT  8.291 37.584 8.489 42.552 ;
     RECT  8.389 52.992 8.489 53.112 ;
     RECT  8.435 28.848 8.521 30.84 ;
     RECT  8.485 51.36 8.521 51.384 ;
     RECT  8.489 53.088 8.531 53.112 ;
     RECT  8.237 21.168 8.533 25.704 ;
     RECT  7.805 26.736 8.533 27.384 ;
     RECT  8.533 21.168 8.569 27.384 ;
     RECT  8.485 55.968 8.569 55.992 ;
     RECT  8.521 28.848 8.581 31.224 ;
     RECT  7.877 49.248 8.597 49.272 ;
     RECT  8.521 50.688 8.597 51.384 ;
     RECT  8.569 26.112 8.62 27.384 ;
     RECT  8.233 33.312 8.636 34.92 ;
     RECT  8.237 0.72 8.641 20.088 ;
     RECT  8.093 36.432 8.665 36.456 ;
     RECT  8.489 37.632 8.665 42.552 ;
     RECT  8.581 28.848 8.669 31.896 ;
     RECT  8.636 33.024 8.723 34.92 ;
     RECT  8.665 35.952 8.749 36.456 ;
     RECT  8.641 13.68 8.777 20.088 ;
     RECT  8.777 13.68 8.813 17.064 ;
     RECT  8.665 37.632 8.828 42.744 ;
     RECT  8.777 18.288 8.86 20.088 ;
     RECT  8.54 45.312 8.917 45.336 ;
     RECT  8.828 37.632 8.921 43.56 ;
     RECT  8.62 26.784 8.965 27.384 ;
     RECT  8.305 46.752 9.061 47.928 ;
     RECT  8.921 37.632 9.107 41.112 ;
     RECT  8.921 42.24 9.109 43.56 ;
     RECT  8.917 45.216 9.169 45.336 ;
     RECT  9.061 46.368 9.169 47.928 ;
     RECT  8.641 0.72 9.251 12.552 ;
     RECT  8.569 21.168 9.299 25.08 ;
     RECT  9.109 42.24 9.313 43.944 ;
     RECT  9.169 45.216 9.313 47.928 ;
     RECT  9.299 21.168 9.317 24.024 ;
     RECT  9.107 37.632 9.317 40.92 ;
     RECT  8.669 28.848 9.347 31.656 ;
     RECT  9.097 55.296 9.397 55.32 ;
     RECT  9.452 56.688 9.539 56.712 ;
     RECT  8.965 26.784 9.569 27.864 ;
     RECT  9.397 54.624 9.589 55.32 ;
     RECT  8.749 36.048 9.601 36.456 ;
     RECT  9.317 37.632 9.601 38.808 ;
     RECT  9.313 42.24 9.637 47.928 ;
     RECT  9.251 11.76 9.644 12.552 ;
     RECT  9.589 54.624 9.677 55.944 ;
     RECT  9.637 42.24 9.683 48.168 ;
     RECT  9.347 29.04 9.731 31.656 ;
     RECT  9.683 45.12 9.745 48.168 ;
     RECT  9.421 49.296 9.745 49.32 ;
     RECT  9.569 26.784 9.749 26.808 ;
     RECT  8.723 33.168 9.781 34.92 ;
     RECT  9.601 36.048 9.82 38.808 ;
     RECT  9.731 29.088 9.853 31.656 ;
     RECT  9.932 58.08 10.019 58.104 ;
     RECT  9.644 11.76 10.033 12.744 ;
     RECT  8.813 14.496 10.033 17.064 ;
     RECT  9.596 25.296 10.117 25.32 ;
     RECT  10.069 26.64 10.117 26.76 ;
     RECT  9.745 45.12 10.177 49.32 ;
     RECT  10.033 11.76 10.213 17.064 ;
     RECT  8.86 18.288 10.213 20.04 ;
     RECT  9.781 32.88 10.249 34.92 ;
     RECT  10.177 45.12 10.249 49.464 ;
     RECT  8.597 50.688 10.249 51.24 ;
     RECT  10.249 45.12 10.309 51.24 ;
     RECT  9.709 52.464 10.309 52.488 ;
     RECT  10.249 32.784 10.393 34.92 ;
     RECT  10.213 11.76 10.537 20.04 ;
     RECT  10.117 25.296 10.537 26.76 ;
     RECT  9.853 29.088 10.537 31.8 ;
     RECT  10.393 32.784 10.537 35.688 ;
     RECT  9.82 36.672 10.537 38.808 ;
     RECT  9.317 39.888 10.537 40.92 ;
     RECT  9.317 21.168 10.556 23.832 ;
     RECT  10.537 36.672 10.597 40.968 ;
     RECT  10.556 21.168 10.609 23.88 ;
     RECT  10.537 25.152 10.609 26.76 ;
     RECT  9.677 54.912 10.609 55.944 ;
     RECT  10.537 29.088 10.717 35.688 ;
     RECT  9.683 42.24 10.717 43.944 ;
     RECT  10.309 45.12 10.717 52.488 ;
     RECT  10.609 54.912 10.717 56.04 ;
     RECT  9.251 0.72 10.789 10.68 ;
     RECT  10.537 11.76 10.789 20.088 ;
     RECT  10.789 0.72 10.825 20.088 ;
     RECT  10.717 54.672 10.837 56.04 ;
     RECT  10.837 54.432 10.861 56.04 ;
     RECT  10.717 42.192 10.885 43.944 ;
     RECT  10.717 45.12 10.885 52.536 ;
     RECT  10.861 54.384 10.885 56.04 ;
     RECT  10.213 57.072 10.885 57.72 ;
     RECT  10.609 21.168 10.933 26.76 ;
     RECT  9.961 27.888 10.933 27.912 ;
     RECT  10.717 28.944 10.933 35.688 ;
     RECT  10.597 36.672 10.933 41.112 ;
     RECT  10.825 0.624 11.048 20.088 ;
     RECT  10.933 21.168 11.048 27.912 ;
     RECT  10.933 28.944 11.048 41.112 ;
     RECT  10.885 42.192 11.048 52.536 ;
     RECT  10.885 54.384 11.048 57.72 ;
     RECT  11.048 0.528 11.24 63.732 ;
     RECT  11.24 0.528 11.257 64.002 ;
     RECT  11.257 0.48 11.344 64.002 ;
     RECT  11.344 0.48 11.477 15.624 ;
     RECT  11.344 43.776 11.657 54.936 ;
     RECT  11.344 17.04 11.788 35.448 ;
     RECT  11.788 17.136 11.795 35.448 ;
     RECT  11.344 36.48 11.873 41.112 ;
     RECT  11.795 26.4 11.987 35.448 ;
     RECT  11.873 36.624 11.987 41.112 ;
     RECT  11.987 26.4 12.089 27.432 ;
     RECT  11.657 45.552 12.089 54.936 ;
     RECT  11.344 57.456 12.337 57.96 ;
     RECT  11.344 59.616 12.337 59.64 ;
     RECT  12.089 26.4 12.377 27.384 ;
     RECT  11.477 13.008 12.445 15.624 ;
     RECT  11.987 28.416 12.449 35.448 ;
     RECT  12.445 13.008 12.517 15.96 ;
     RECT  11.987 37.872 12.517 41.112 ;
     RECT  11.344 42.192 12.517 42.744 ;
     RECT  11.344 56.208 12.517 56.232 ;
     RECT  12.337 57.456 12.517 59.64 ;
     RECT  12.449 28.416 12.521 31.896 ;
     RECT  12.517 56.208 12.563 59.64 ;
     RECT  11.795 17.136 12.593 25.368 ;
     RECT  11.657 43.776 12.625 44.376 ;
     RECT  12.089 45.552 12.625 49.56 ;
     RECT  12.593 17.136 12.707 24.312 ;
     RECT  12.089 50.736 12.733 54.936 ;
     RECT  12.707 17.136 12.737 23.16 ;
     RECT  12.517 37.872 12.737 42.744 ;
     RECT  12.521 28.656 12.773 31.896 ;
     RECT  12.517 12.96 12.841 15.96 ;
     RECT  12.737 17.136 12.841 22.824 ;
     RECT  12.593 25.296 12.877 25.368 ;
     RECT  12.377 26.4 12.877 27.048 ;
     RECT  12.841 12.96 12.899 22.824 ;
     RECT  12.733 50.736 12.949 55.032 ;
     RECT  12.563 56.208 12.949 58.728 ;
     RECT  12.449 32.88 12.953 35.448 ;
     RECT  12.625 43.776 12.956 49.56 ;
     RECT  12.949 50.736 12.989 58.728 ;
     RECT  12.956 43.728 13.043 49.56 ;
     RECT  12.899 12.96 13.061 19.224 ;
     RECT  12.989 50.736 13.091 57.96 ;
     RECT  11.987 36.624 13.093 36.84 ;
     RECT  12.737 37.872 13.093 42.696 ;
     RECT  12.953 35.28 13.169 35.448 ;
     RECT  12.899 20.4 13.241 22.824 ;
     RECT  12.773 28.656 13.241 31.8 ;
     RECT  12.953 32.88 13.313 34.2 ;
     RECT  13.091 57.024 13.313 57.96 ;
     RECT  13.313 33.024 13.421 34.2 ;
     RECT  13.093 36.624 13.457 42.696 ;
     RECT  13.457 36.624 13.525 40.92 ;
     RECT  13.043 44.16 13.525 49.56 ;
     RECT  13.091 50.736 13.525 55.704 ;
     RECT  12.877 25.296 13.561 27.048 ;
     RECT  13.241 28.656 13.561 31.656 ;
     RECT  11.477 0.48 13.597 11.928 ;
     RECT  13.061 12.96 13.597 18.744 ;
     RECT  13.241 21.456 13.667 22.824 ;
     RECT  12.707 24.288 13.669 24.312 ;
     RECT  13.561 25.296 13.669 31.656 ;
     RECT  13.597 0.48 13.715 18.744 ;
     RECT  13.669 24.288 13.715 31.656 ;
     RECT  13.715 28.032 13.745 31.656 ;
     RECT  13.715 7.152 13.781 18.744 ;
     RECT  13.667 21.456 13.781 22.728 ;
     RECT  13.525 44.16 14.033 55.704 ;
     RECT  13.715 0.48 14.065 5.88 ;
     RECT  13.715 24.288 14.137 26.808 ;
     RECT  13.525 35.904 14.137 40.92 ;
     RECT  14.033 45.024 14.141 55.704 ;
     RECT  13.313 57.072 14.173 57.96 ;
     RECT  14.173 57.072 14.245 58.68 ;
     RECT  14.245 57.072 14.332 59.592 ;
     RECT  13.241 20.4 14.389 20.424 ;
     RECT  13.781 21.456 14.389 22.392 ;
     RECT  13.457 42.048 14.425 42.696 ;
     RECT  14.137 35.52 14.569 40.92 ;
     RECT  14.425 42.048 14.569 43.272 ;
     RECT  14.389 20.4 14.636 22.392 ;
     RECT  13.781 7.344 14.641 18.744 ;
     RECT  14.641 7.344 14.677 18.984 ;
     RECT  14.636 20.112 14.677 22.392 ;
     RECT  14.141 54.816 14.681 55.704 ;
     RECT  14.677 7.344 14.717 22.392 ;
     RECT  14.717 7.728 14.749 22.392 ;
     RECT  14.569 35.52 14.789 43.272 ;
     RECT  14.065 0.048 14.821 5.88 ;
     RECT  14.332 57.072 14.821 58.68 ;
     RECT  14.821 0.048 14.893 6.12 ;
     RECT  14.749 27.936 14.893 27.96 ;
     RECT  13.745 28.944 14.893 31.656 ;
     RECT  14.141 45.024 14.897 53.592 ;
     RECT  14.137 24.096 14.933 26.808 ;
     RECT  14.789 41.76 15.005 43.272 ;
     RECT  14.681 54.864 15.041 55.704 ;
     RECT  13.421 33.312 15.068 34.2 ;
     RECT  15.005 42.048 15.077 43.272 ;
     RECT  14.821 56.928 15.077 58.68 ;
     RECT  14.893 0.048 15.109 6.312 ;
     RECT  14.893 27.936 15.145 31.656 ;
     RECT  15.068 33.312 15.155 34.392 ;
     RECT  14.789 35.52 15.221 40.728 ;
     RECT  14.897 45.024 15.221 53.4 ;
     RECT  14.933 24.096 15.289 26.664 ;
     RECT  15.289 23.952 15.401 26.664 ;
     RECT  15.145 27.84 15.473 31.656 ;
     RECT  14.749 7.728 15.541 22.824 ;
     RECT  15.401 23.952 15.541 25.896 ;
     RECT  15.473 28.416 15.685 31.656 ;
     RECT  15.155 33.312 15.685 33.912 ;
     RECT  15.221 45.456 16.009 53.4 ;
     RECT  15.221 40.464 16.117 40.728 ;
     RECT  15.077 42.048 16.117 43.128 ;
     RECT  15.793 55.776 16.117 55.8 ;
     RECT  15.077 56.928 16.117 57.048 ;
     RECT  16.117 40.464 16.261 43.128 ;
     RECT  15.865 59.952 16.297 59.976 ;
     RECT  15.109 0.048 16.309 6.6 ;
     RECT  15.541 7.728 16.309 25.896 ;
     RECT  16.309 0.048 16.448 25.896 ;
     RECT  15.925 27.12 16.448 27.336 ;
     RECT  15.685 28.416 16.448 31.992 ;
     RECT  15.685 33.024 16.448 33.912 ;
     RECT  15.221 35.52 16.448 39.336 ;
     RECT  16.261 40.464 16.448 43.944 ;
     RECT  16.009 45.456 16.448 53.592 ;
     RECT  16.117 55.776 16.448 57.048 ;
     RECT  15.077 58.656 16.448 58.68 ;
     RECT  16.297 59.952 16.448 60.264 ;
     RECT  16.448 0.048 16.64 63.732 ;
     RECT  16.64 0.048 16.744 64.002 ;
     RECT  16.744 0.048 16.805 32.568 ;
     RECT  16.744 55.968 17.075 57.048 ;
     RECT  16.805 0.048 17.129 25.512 ;
     RECT  16.744 58.32 17.26 60.024 ;
     RECT  16.744 33.552 17.345 33.576 ;
     RECT  16.744 34.752 17.417 54.552 ;
     RECT  17.417 36.048 17.525 54.552 ;
     RECT  17.26 58.32 17.548 59.64 ;
     RECT  17.075 56.352 17.737 57.048 ;
     RECT  17.129 0.048 17.747 19.848 ;
     RECT  16.805 26.736 17.773 32.568 ;
     RECT  17.773 26.736 17.849 33.048 ;
     RECT  17.525 38.736 17.849 54.552 ;
     RECT  17.417 34.752 17.881 34.92 ;
     RECT  17.849 38.736 17.957 41.064 ;
     RECT  17.881 34.464 18.029 34.92 ;
     RECT  17.849 42.048 18.035 54.552 ;
     RECT  18.035 46.32 18.173 54.552 ;
     RECT  18.173 52.512 18.205 54.552 ;
     RECT  17.129 20.832 18.209 25.512 ;
     RECT  17.849 32.016 18.209 33.048 ;
     RECT  17.525 36.048 18.217 37.704 ;
     RECT  18.205 52.512 18.229 55.272 ;
     RECT  17.737 56.352 18.229 57.576 ;
     RECT  17.747 0.048 18.268 19.608 ;
     RECT  18.229 52.512 18.317 57.576 ;
     RECT  18.209 32.208 18.353 33.048 ;
     RECT  18.317 56.496 18.353 57.576 ;
     RECT  17.548 58.704 18.373 59.64 ;
     RECT  18.029 34.512 18.385 34.92 ;
     RECT  18.217 36.048 18.385 37.368 ;
     RECT  18.373 58.704 18.565 59.784 ;
     RECT  18.229 60.816 18.565 60.84 ;
     RECT  17.957 38.736 18.668 40.728 ;
     RECT  18.565 58.704 18.749 60.84 ;
     RECT  18.668 38.592 18.755 40.728 ;
     RECT  18.209 20.928 18.781 25.512 ;
     RECT  17.849 26.736 18.781 31.032 ;
     RECT  18.781 20.928 18.803 31.032 ;
     RECT  18.385 34.512 18.803 37.368 ;
     RECT  18.317 52.512 18.803 55.272 ;
     RECT  18.749 58.704 18.821 60.456 ;
     RECT  18.803 27.792 18.857 30.168 ;
     RECT  18.268 0.048 19.037 19.56 ;
     RECT  18.755 38.688 19.073 40.728 ;
     RECT  19.073 39.072 19.141 40.728 ;
     RECT  18.035 42.048 19.141 45 ;
     RECT  19.141 39.072 19.253 45 ;
     RECT  18.353 32.256 19.321 33.048 ;
     RECT  18.803 54.672 19.321 55.272 ;
     RECT  18.353 56.88 19.321 56.904 ;
     RECT  18.173 46.32 19.325 51.528 ;
     RECT  19.321 31.344 19.357 33.048 ;
     RECT  18.803 34.512 19.357 34.824 ;
     RECT  18.821 59.472 19.379 60.456 ;
     RECT  19.325 46.704 19.397 51.528 ;
     RECT  19.397 46.8 19.42 51.528 ;
     RECT  19.42 46.848 19.429 51.528 ;
     RECT  18.803 52.512 19.429 53.4 ;
     RECT  18.803 36 19.465 37.368 ;
     RECT  19.321 54.672 19.465 56.904 ;
     RECT  19.253 44.928 19.469 45 ;
     RECT  18.817 61.44 19.487 61.512 ;
     RECT  19.469 44.976 19.523 45 ;
     RECT  19.253 39.072 19.541 43.944 ;
     RECT  19.037 14.304 19.58 19.56 ;
     RECT  19.58 14.304 19.667 19.8 ;
     RECT  19.465 54.672 19.676 57.336 ;
     RECT  19.037 0.048 19.715 13.08 ;
     RECT  19.676 54.672 19.763 57.48 ;
     RECT  18.803 20.928 19.825 26.808 ;
     RECT  18.857 27.792 19.825 29.496 ;
     RECT  19.667 14.496 19.868 19.8 ;
     RECT  19.825 20.928 19.868 29.496 ;
     RECT  19.357 31.344 19.868 34.824 ;
     RECT  19.465 36 19.868 37.464 ;
     RECT  19.868 31.008 19.889 34.824 ;
     RECT  19.868 35.808 19.889 37.464 ;
     RECT  19.541 39.216 19.901 43.944 ;
     RECT  19.868 14.496 19.955 19.944 ;
     RECT  19.868 20.928 19.955 29.784 ;
     RECT  19.889 31.008 19.955 37.464 ;
     RECT  19.901 43.92 19.955 43.944 ;
     RECT  19.955 31.776 20.003 37.464 ;
     RECT  19.429 46.848 20.005 53.4 ;
     RECT  19.763 54.672 20.005 57.336 ;
     RECT  19.955 20.928 20.053 26.568 ;
     RECT  19.715 0.048 20.153 12.792 ;
     RECT  19.955 28.416 20.293 29.784 ;
     RECT  20.005 46.848 20.297 57.336 ;
     RECT  20.003 36.432 20.333 37.464 ;
     RECT  19.487 61.44 20.369 61.56 ;
     RECT  20.297 46.848 20.389 53.4 ;
     RECT  19.825 45.456 20.509 45.576 ;
     RECT  20.389 46.8 20.509 53.4 ;
     RECT  19.379 60.048 20.509 60.456 ;
     RECT  19.901 39.216 20.533 42.888 ;
     RECT  19.955 14.496 20.585 18.984 ;
     RECT  20.509 44.448 20.636 44.472 ;
     RECT  20.509 45.456 20.636 53.4 ;
     RECT  20.297 54.48 20.833 57.336 ;
     RECT  20.509 59.136 20.833 60.456 ;
     RECT  20.585 18.96 20.977 18.984 ;
     RECT  20.053 20.016 20.977 26.568 ;
     RECT  20.003 31.776 21.013 35.304 ;
     RECT  20.333 36.432 21.013 37.32 ;
     RECT  20.369 61.536 21.049 61.56 ;
     RECT  20.833 12.816 21.085 12.936 ;
     RECT  20.585 14.496 21.085 17.928 ;
     RECT  20.293 28.416 21.193 30.072 ;
     RECT  21.013 31.776 21.193 37.32 ;
     RECT  20.977 18.96 21.301 26.568 ;
     RECT  21.193 27.6 21.301 30.072 ;
     RECT  20.533 38.64 21.301 42.888 ;
     RECT  20.636 44.448 21.337 53.4 ;
     RECT  20.833 54.48 21.337 60.456 ;
     RECT  21.193 31.392 21.356 37.32 ;
     RECT  21.301 38.64 21.356 43.368 ;
     RECT  20.153 0.048 21.373 11.736 ;
     RECT  21.085 12.816 21.373 17.928 ;
     RECT  21.337 44.448 21.373 60.456 ;
     RECT  21.049 61.536 21.373 61.608 ;
     RECT  21.356 31.392 21.404 43.368 ;
     RECT  21.373 44.448 21.404 61.608 ;
     RECT  21.301 18.96 21.481 30.072 ;
     RECT  21.404 31.392 21.481 61.608 ;
     RECT  21.373 0.048 21.848 17.928 ;
     RECT  21.481 18.96 21.848 61.608 ;
     RECT  21.848 0.048 22.04 63.732 ;
     RECT  22.04 0.048 22.144 64.002 ;
     RECT  22.144 0.048 22.169 20.184 ;
     RECT  22.169 18.432 22.205 20.184 ;
     RECT  22.144 33.072 22.259 40.824 ;
     RECT  22.205 19.968 22.781 20.184 ;
     RECT  22.144 30.336 22.787 31.944 ;
     RECT  22.781 20.16 22.853 20.184 ;
     RECT  22.259 33.216 22.853 40.824 ;
     RECT  22.144 41.856 22.853 54.84 ;
     RECT  22.853 42.048 23.132 54.84 ;
     RECT  22.787 30.336 23.137 31.56 ;
     RECT  22.144 58.176 23.18 60.84 ;
     RECT  22.169 0.048 23.317 17.448 ;
     RECT  22.205 18.432 23.317 18.984 ;
     RECT  23.18 58.032 23.317 60.84 ;
     RECT  22.144 21.264 23.393 26.904 ;
     RECT  23.317 57.552 23.425 60.84 ;
     RECT  22.144 28.272 23.497 29.016 ;
     RECT  23.132 42.048 23.509 55.464 ;
     RECT  23.509 42.048 23.609 55.992 ;
     RECT  23.317 0.048 23.677 18.984 ;
     RECT  22.853 33.216 23.677 33.24 ;
     RECT  23.393 21.264 23.701 25.32 ;
     RECT  23.677 0.048 23.717 19.032 ;
     RECT  23.701 20.928 23.717 25.32 ;
     RECT  23.393 26.304 23.749 26.904 ;
     RECT  23.497 28.272 23.749 29.112 ;
     RECT  23.137 30.192 23.749 31.56 ;
     RECT  22.853 34.896 23.753 40.824 ;
     RECT  23.717 0.048 23.761 13.08 ;
     RECT  23.717 20.928 23.788 21.864 ;
     RECT  23.717 14.112 23.821 19.032 ;
     RECT  23.425 57.552 23.825 61.608 ;
     RECT  23.717 23.136 23.861 25.32 ;
     RECT  23.861 23.136 23.933 24.024 ;
     RECT  23.821 14.112 23.939 19.848 ;
     RECT  23.753 38.688 23.939 40.824 ;
     RECT  23.825 60.912 23.941 61.608 ;
     RECT  22.144 62.592 23.941 62.712 ;
     RECT  23.825 57.552 23.948 59.88 ;
     RECT  23.749 30.192 23.969 31.992 ;
     RECT  23.939 14.112 23.987 19.656 ;
     RECT  23.941 60.912 23.987 62.712 ;
     RECT  23.609 42.048 24.005 55.896 ;
     RECT  24.005 42.048 24.013 54.312 ;
     RECT  23.987 60.912 24.028 62.088 ;
     RECT  23.948 57.456 24.035 59.88 ;
     RECT  24.013 42.048 24.121 43.368 ;
     RECT  23.753 34.896 24.149 37.608 ;
     RECT  23.939 40.416 24.217 40.824 ;
     RECT  24.121 42.048 24.249 43.32 ;
     RECT  24.217 40.416 24.301 41.064 ;
     RECT  23.677 33.024 24.325 33.24 ;
     RECT  24.035 58.032 24.365 59.88 ;
     RECT  23.749 26.304 24.469 29.112 ;
     RECT  23.969 30.192 24.469 31.56 ;
     RECT  24.325 33.024 24.515 33.672 ;
     RECT  24.013 44.592 24.515 54.312 ;
     RECT  23.861 25.296 24.517 25.32 ;
     RECT  24.469 26.304 24.517 31.56 ;
     RECT  23.939 38.688 24.617 39.384 ;
     RECT  23.761 0.048 24.793 12.888 ;
     RECT  24.515 33.024 24.797 33.288 ;
     RECT  23.788 21.072 24.865 21.864 ;
     RECT  23.933 23.376 24.901 24.024 ;
     RECT  24.517 25.296 24.901 31.56 ;
     RECT  24.617 38.784 24.937 39.384 ;
     RECT  24.301 40.416 24.937 41.016 ;
     RECT  24.005 55.296 24.937 55.896 ;
     RECT  24.901 23.376 25.009 31.56 ;
     RECT  24.028 60.912 25.009 61.512 ;
     RECT  24.865 20.688 25.045 21.864 ;
     RECT  24.149 34.992 25.049 37.608 ;
     RECT  24.937 55.296 25.085 56.52 ;
     RECT  25.045 20.688 25.121 22.056 ;
     RECT  24.515 46.224 25.153 54.312 ;
     RECT  25.085 55.296 25.153 55.32 ;
     RECT  25.121 21.552 25.261 22.056 ;
     RECT  25.085 56.352 25.261 56.52 ;
     RECT  24.793 0.048 25.331 12.984 ;
     RECT  25.261 21.552 25.333 22.248 ;
     RECT  25.009 23.232 25.333 31.56 ;
     RECT  25.049 35.616 25.333 37.608 ;
     RECT  25.009 60.912 25.333 62.232 ;
     RECT  25.333 21.552 25.34 31.56 ;
     RECT  23.987 14.496 25.369 19.656 ;
     RECT  24.365 58.416 25.369 59.88 ;
     RECT  25.333 60.912 25.369 62.328 ;
     RECT  25.261 56.352 25.388 56.904 ;
     RECT  25.369 57.936 25.388 59.88 ;
     RECT  25.331 0.048 25.445 11.448 ;
     RECT  25.34 21.552 25.445 32.136 ;
     RECT  25.388 56.352 25.475 59.88 ;
     RECT  25.331 12.528 25.477 12.984 ;
     RECT  24.937 38.784 25.477 41.016 ;
     RECT  24.249 42.048 25.477 43.272 ;
     RECT  25.333 35.616 25.513 37.704 ;
     RECT  25.475 57.936 25.513 59.88 ;
     RECT  25.369 60.912 25.513 63.24 ;
     RECT  25.153 46.224 25.549 55.32 ;
     RECT  25.369 14.448 25.553 19.656 ;
     RECT  25.553 14.448 25.621 17.448 ;
     RECT  25.553 18.48 25.621 19.656 ;
     RECT  25.477 38.784 25.621 43.272 ;
     RECT  25.477 12.528 25.669 13.224 ;
     RECT  25.621 14.4 25.669 17.448 ;
     RECT  25.445 0.048 25.697 11.4 ;
     RECT  25.475 56.352 25.697 56.52 ;
     RECT  25.585 45.024 25.765 45.048 ;
     RECT  25.549 46.08 25.765 55.32 ;
     RECT  25.669 12.528 25.769 17.448 ;
     RECT  25.513 35.616 25.801 37.8 ;
     RECT  25.621 38.784 25.801 43.608 ;
     RECT  25.765 45.024 25.801 55.32 ;
     RECT  25.513 57.936 25.805 63.24 ;
     RECT  25.801 35.616 25.913 43.608 ;
     RECT  25.801 44.976 25.916 55.32 ;
     RECT  25.913 37.008 25.981 43.608 ;
     RECT  25.916 44.88 25.981 55.32 ;
     RECT  25.913 35.616 26.017 35.976 ;
     RECT  25.981 37.008 26.057 55.32 ;
     RECT  26.017 35.52 26.089 35.976 ;
     RECT  26.057 44.208 26.125 55.32 ;
     RECT  25.697 56.352 26.125 56.472 ;
     RECT  26.125 44.208 26.165 56.472 ;
     RECT  25.621 18.48 26.197 20.424 ;
     RECT  25.769 12.528 26.236 16.968 ;
     RECT  26.197 18.48 26.265 20.52 ;
     RECT  26.057 37.008 26.273 43.128 ;
     RECT  25.445 21.648 26.3 32.136 ;
     RECT  24.797 33.264 26.3 33.288 ;
     RECT  26.089 34.896 26.305 35.976 ;
     RECT  26.3 21.648 26.449 33.288 ;
     RECT  26.165 50.784 26.665 56.472 ;
     RECT  25.805 57.936 26.665 60.84 ;
     RECT  26.449 21.648 26.701 33.576 ;
     RECT  25.697 0.048 26.737 11.256 ;
     RECT  26.236 12.528 26.737 13.224 ;
     RECT  26.236 14.304 26.737 16.968 ;
     RECT  26.265 18.48 26.737 19.368 ;
     RECT  26.701 21.648 26.773 33.624 ;
     RECT  26.305 34.8 26.773 35.976 ;
     RECT  25.805 61.92 26.953 63.24 ;
     RECT  26.665 50.784 26.989 60.84 ;
     RECT  26.273 41.952 27.089 43.128 ;
     RECT  26.165 44.208 27.089 49.608 ;
     RECT  26.989 50.784 27.097 60.888 ;
     RECT  26.953 61.92 27.097 63.288 ;
     RECT  27.089 41.952 27.133 49.608 ;
     RECT  27.097 50.784 27.133 63.288 ;
     RECT  26.737 0.048 27.248 13.224 ;
     RECT  26.737 14.304 27.248 19.368 ;
     RECT  26.265 20.4 27.248 20.52 ;
     RECT  26.773 21.648 27.248 35.976 ;
     RECT  26.273 37.632 27.248 40.872 ;
     RECT  27.133 41.952 27.248 63.288 ;
     RECT  27.248 0.048 27.44 63.732 ;
     RECT  27.44 0.048 27.544 64.002 ;
     RECT  27.544 50.64 27.677 59.784 ;
     RECT  27.544 38.688 27.683 49.32 ;
     RECT  27.544 22.032 27.713 32.424 ;
     RECT  27.713 28.272 27.875 32.424 ;
     RECT  27.544 33.648 27.965 37.704 ;
     RECT  27.677 50.64 28.001 59.256 ;
     RECT  27.875 28.272 28.163 32.184 ;
     RECT  27.683 39.072 28.163 49.32 ;
     RECT  27.544 60.864 28.181 63.288 ;
     RECT  28.001 54.672 28.259 59.256 ;
     RECT  28.259 58.8 28.369 59.256 ;
     RECT  27.544 0.048 28.403 20.424 ;
     RECT  27.713 22.032 28.433 27.192 ;
     RECT  27.965 33.648 28.433 37.608 ;
     RECT  28.403 14.736 28.469 20.424 ;
     RECT  28.181 61.392 28.541 63.288 ;
     RECT  28.163 39.504 28.577 49.32 ;
     RECT  28.163 28.272 28.595 29.784 ;
     RECT  28.577 43.872 28.717 49.32 ;
     RECT  28.001 50.64 28.717 53.688 ;
     RECT  28.369 59.04 28.753 59.256 ;
     RECT  28.609 60.24 28.753 60.264 ;
     RECT  28.541 61.488 28.828 63.288 ;
     RECT  28.469 14.736 28.835 19.992 ;
     RECT  28.403 0.048 28.901 13.608 ;
     RECT  28.595 29.76 28.931 29.784 ;
     RECT  28.163 30.816 29.077 32.184 ;
     RECT  28.433 33.648 29.077 33.672 ;
     RECT  28.901 13.008 29.117 13.608 ;
     RECT  28.577 39.504 29.125 42.744 ;
     RECT  28.835 15.744 29.164 19.992 ;
     RECT  29.077 30.816 29.173 33.672 ;
     RECT  28.433 34.656 29.173 37.608 ;
     RECT  29.125 39.216 29.173 42.744 ;
     RECT  28.901 0.048 29.225 12.024 ;
     RECT  29.173 30.048 29.26 33.672 ;
     RECT  28.597 21.648 29.269 21.672 ;
     RECT  29.269 21.6 29.324 21.672 ;
     RECT  28.753 59.04 29.324 60.264 ;
     RECT  29.117 13.248 29.333 13.608 ;
     RECT  28.259 54.672 29.401 57.384 ;
     RECT  29.324 59.04 29.411 60.504 ;
     RECT  29.333 13.296 29.441 13.608 ;
     RECT  28.717 43.872 29.473 53.688 ;
     RECT  29.401 54.672 29.473 57.96 ;
     RECT  29.473 43.872 29.513 57.96 ;
     RECT  29.173 34.656 29.545 42.744 ;
     RECT  29.513 43.872 29.545 50.136 ;
     RECT  29.411 59.04 29.549 60.024 ;
     RECT  29.441 13.392 29.581 13.608 ;
     RECT  28.835 14.736 29.581 14.76 ;
     RECT  29.324 21.552 29.617 21.672 ;
     RECT  28.433 22.752 29.617 27.144 ;
     RECT  29.545 34.656 29.629 50.136 ;
     RECT  29.164 15.744 29.651 17.208 ;
     RECT  29.26 30.432 29.657 33.672 ;
     RECT  29.164 18.528 29.701 19.992 ;
     RECT  29.617 21.552 29.701 27.144 ;
     RECT  29.513 51.12 29.701 57.96 ;
     RECT  29.549 59.04 29.701 59.88 ;
     RECT  29.651 15.744 29.729 16.872 ;
     RECT  29.701 18.528 29.788 27.144 ;
     RECT  29.657 30.816 29.837 33.672 ;
     RECT  29.581 13.392 29.845 14.76 ;
     RECT  29.729 15.744 29.845 16.632 ;
     RECT  29.788 20.976 29.905 27.144 ;
     RECT  28.595 28.272 29.905 28.536 ;
     RECT  29.629 44.112 30.089 50.136 ;
     RECT  30.089 44.112 30.227 49.32 ;
     RECT  29.629 34.656 30.233 42.6 ;
     RECT  29.905 20.976 30.277 28.536 ;
     RECT  30.277 20.976 30.377 29.4 ;
     RECT  29.788 18.528 30.445 19.944 ;
     RECT  28.828 61.968 30.445 63.288 ;
     RECT  29.701 51.12 30.449 59.88 ;
     RECT  29.225 0.048 30.517 11.688 ;
     RECT  30.377 24.24 30.553 29.4 ;
     RECT  30.377 20.976 30.557 23.064 ;
     RECT  30.233 35.328 30.557 42.6 ;
     RECT  29.837 30.816 30.625 33.048 ;
     RECT  30.553 24.24 30.665 29.496 ;
     RECT  30.227 44.112 30.773 44.856 ;
     RECT  30.557 35.328 30.803 38.808 ;
     RECT  30.557 40.224 30.805 42.6 ;
     RECT  29.845 13.392 30.853 16.632 ;
     RECT  30.445 18.432 30.877 19.944 ;
     RECT  30.805 40.224 30.889 43.032 ;
     RECT  30.625 30.576 30.949 33.048 ;
     RECT  30.449 51.12 30.953 59.784 ;
     RECT  30.853 13.104 30.985 16.632 ;
     RECT  30.877 17.664 30.985 19.944 ;
     RECT  30.803 35.328 30.989 36.072 ;
     RECT  30.985 13.104 30.995 19.944 ;
     RECT  30.773 44.112 31.057 44.184 ;
     RECT  30.995 13.2 31.061 19.944 ;
     RECT  30.949 30.576 31.141 33.144 ;
     RECT  31.057 43.776 31.169 44.184 ;
     RECT  31.061 13.344 31.201 19.944 ;
     RECT  30.557 20.976 31.201 22.92 ;
     RECT  31.169 43.776 31.277 44.136 ;
     RECT  31.141 30.576 31.309 34.2 ;
     RECT  30.989 35.328 31.309 35.496 ;
     RECT  30.953 55.632 31.313 59.784 ;
     RECT  31.309 30.576 31.331 35.496 ;
     RECT  30.227 45.84 31.333 49.32 ;
     RECT  30.445 61.536 31.345 63.288 ;
     RECT  30.517 0.048 31.381 11.784 ;
     RECT  30.665 24.432 31.381 29.496 ;
     RECT  31.331 30.576 31.381 32.616 ;
     RECT  31.331 33.6 31.385 35.496 ;
     RECT  31.277 43.776 31.571 43.848 ;
     RECT  31.333 45.552 31.58 49.32 ;
     RECT  31.381 24.432 31.669 32.616 ;
     RECT  31.58 45.552 31.669 49.896 ;
     RECT  30.953 51.12 31.669 54.36 ;
     RECT  31.201 13.344 31.741 22.92 ;
     RECT  31.741 13.344 31.849 23.112 ;
     RECT  31.669 24.336 31.849 32.616 ;
     RECT  30.803 37.056 31.916 38.808 ;
     RECT  31.313 55.968 31.957 59.784 ;
     RECT  31.345 60.816 31.957 63.288 ;
     RECT  30.889 40.224 31.993 42.744 ;
     RECT  31.571 43.776 31.993 43.8 ;
     RECT  31.957 55.968 31.993 63.288 ;
     RECT  31.916 37.056 32.293 39.144 ;
     RECT  31.849 13.344 32.353 32.616 ;
     RECT  31.385 33.6 32.353 34.488 ;
     RECT  32.353 13.344 32.425 34.488 ;
     RECT  31.385 35.472 32.425 35.496 ;
     RECT  31.669 45.552 32.461 54.36 ;
     RECT  32.461 45.264 32.485 54.36 ;
     RECT  32.425 13.344 32.497 35.496 ;
     RECT  32.485 45.264 32.533 54.84 ;
     RECT  31.993 55.968 32.533 63.528 ;
     RECT  32.497 13.152 32.569 35.496 ;
     RECT  31.381 0.048 32.648 12.072 ;
     RECT  32.569 13.104 32.648 35.496 ;
     RECT  32.293 36.48 32.648 39.144 ;
     RECT  31.993 40.224 32.648 43.8 ;
     RECT  32.533 45.264 32.648 63.528 ;
     RECT  32.648 0.048 32.84 63.732 ;
     RECT  32.84 0.048 32.944 64.002 ;
     RECT  32.944 44.544 33.113 49.32 ;
     RECT  32.944 58.128 33.221 63.528 ;
     RECT  32.944 0.048 33.329 34.824 ;
     RECT  33.329 0.048 33.365 30.024 ;
     RECT  33.365 0.096 33.437 30.024 ;
     RECT  33.221 58.224 33.437 63.528 ;
     RECT  32.944 39.84 33.653 43.56 ;
     RECT  33.437 58.224 33.683 63.384 ;
     RECT  33.329 31.248 33.689 34.824 ;
     RECT  33.683 61.776 33.697 63.384 ;
     RECT  33.697 63.072 33.761 63.384 ;
     RECT  33.653 41.904 33.869 43.56 ;
     RECT  33.761 63.12 33.941 63.384 ;
     RECT  32.944 36.048 34.009 38.808 ;
     RECT  33.437 0.096 34.013 29.88 ;
     RECT  32.944 50.4 34.019 57.048 ;
     RECT  33.683 58.224 34.115 60.552 ;
     RECT  34.009 35.808 34.117 38.808 ;
     RECT  33.653 39.84 34.117 40.728 ;
     RECT  34.013 0.24 34.121 29.88 ;
     RECT  34.019 50.4 34.121 53.688 ;
     RECT  33.113 44.544 34.165 45.24 ;
     RECT  34.117 35.808 34.211 40.728 ;
     RECT  34.211 35.808 34.213 39.384 ;
     RECT  34.165 43.92 34.225 45.24 ;
     RECT  33.113 46.224 34.225 49.32 ;
     RECT  34.225 43.92 34.252 49.32 ;
     RECT  34.019 55.104 34.268 57.048 ;
     RECT  34.115 58.224 34.268 60.456 ;
     RECT  34.268 55.104 34.355 60.456 ;
     RECT  34.355 58.128 34.373 60.456 ;
     RECT  34.252 44.928 34.409 49.32 ;
     RECT  34.121 0.288 34.549 29.88 ;
     RECT  34.355 55.104 34.589 57.048 ;
     RECT  34.373 58.128 34.661 59.304 ;
     RECT  34.549 0.288 34.789 30.264 ;
     RECT  33.689 31.248 34.789 34.296 ;
     RECT  34.211 40.416 34.801 40.728 ;
     RECT  33.941 63.36 34.805 63.384 ;
     RECT  34.409 46.752 34.981 49.32 ;
     RECT  34.121 50.4 34.981 53.544 ;
     RECT  34.252 43.92 35.009 43.944 ;
     RECT  34.981 46.752 35.084 53.544 ;
     RECT  35.009 43.872 35.093 43.944 ;
     RECT  34.789 0.288 35.189 34.296 ;
     RECT  34.213 35.328 35.189 39.384 ;
     RECT  35.189 0.288 35.305 39.384 ;
     RECT  34.801 40.416 35.309 40.872 ;
     RECT  35.084 46.752 35.363 54.36 ;
     RECT  33.697 61.776 35.365 61.848 ;
     RECT  35.309 40.704 35.509 40.872 ;
     RECT  33.869 41.904 35.509 42.744 ;
     RECT  34.589 56.016 35.612 57.048 ;
     RECT  35.612 55.92 35.629 57.048 ;
     RECT  34.373 60.432 35.629 60.456 ;
     RECT  34.409 44.928 35.665 45.624 ;
     RECT  35.629 55.92 35.665 57.144 ;
     RECT  34.661 58.368 35.665 59.304 ;
     RECT  35.665 44.448 35.749 45.624 ;
     RECT  35.363 46.752 35.749 49.32 ;
     RECT  35.665 55.92 35.773 59.304 ;
     RECT  35.629 60.288 35.809 60.456 ;
     RECT  35.365 61.776 35.809 62.712 ;
     RECT  35.509 40.704 35.881 42.744 ;
     RECT  35.305 0.192 35.891 39.384 ;
     RECT  35.773 55.824 35.891 59.304 ;
     RECT  35.891 56.352 35.917 59.304 ;
     RECT  35.809 60.288 35.917 62.712 ;
     RECT  35.749 44.448 35.921 49.32 ;
     RECT  35.363 50.544 35.932 54.36 ;
     RECT  35.932 52.512 35.941 54.36 ;
     RECT  35.941 52.512 35.989 54.744 ;
     RECT  35.921 46.176 36.029 49.32 ;
     RECT  35.891 0.288 36.061 39.384 ;
     RECT  35.917 56.352 36.085 62.712 ;
     RECT  36.085 56.352 36.101 63 ;
     RECT  36.101 61.776 36.131 63 ;
     RECT  36.061 0.288 36.137 39.72 ;
     RECT  35.881 40.704 36.169 42.984 ;
     RECT  36.131 62.16 36.172 63 ;
     RECT  35.921 44.448 36.179 45.096 ;
     RECT  36.101 56.352 36.179 60.312 ;
     RECT  36.179 45.072 36.245 45.096 ;
     RECT  36.169 40.704 36.277 43.416 ;
     RECT  36.137 19.488 36.313 39.72 ;
     RECT  36.277 40.704 36.313 44.088 ;
     RECT  36.179 56.352 36.317 57.48 ;
     RECT  35.932 50.544 36.397 51.48 ;
     RECT  36.313 19.488 36.508 44.088 ;
     RECT  36.029 46.464 36.524 49.32 ;
     RECT  36.179 58.512 36.749 60.312 ;
     RECT  36.749 58.704 36.755 60.312 ;
     RECT  36.172 62.16 36.785 62.28 ;
     RECT  36.137 0.288 36.965 18.504 ;
     RECT  36.755 58.704 36.965 59.736 ;
     RECT  36.508 19.488 36.993 43.8 ;
     RECT  36.397 51.456 37.004 51.48 ;
     RECT  35.989 52.512 37.004 55.128 ;
     RECT  36.993 36 37.043 43.8 ;
     RECT  36.993 19.488 37.333 34.776 ;
     RECT  36.317 56.352 37.333 56.904 ;
     RECT  36.965 0.288 37.349 18.216 ;
     RECT  36.956 45.216 37.381 45.288 ;
     RECT  37.381 45.216 37.465 45.384 ;
     RECT  36.524 46.464 37.465 50.184 ;
     RECT  37.043 36.048 37.477 43.8 ;
     RECT  37.004 51.456 37.537 55.128 ;
     RECT  37.465 45.216 37.573 50.184 ;
     RECT  37.537 51.216 37.573 55.128 ;
     RECT  37.477 36.048 37.676 43.992 ;
     RECT  37.573 45.216 37.676 55.128 ;
     RECT  37.333 56.352 37.789 57.048 ;
     RECT  37.789 56.352 37.889 57.432 ;
     RECT  36.965 59.04 37.889 59.736 ;
     RECT  37.889 59.04 37.933 60.552 ;
     RECT  37.889 56.352 37.969 58.008 ;
     RECT  37.933 59.04 37.969 61.128 ;
     RECT  37.349 0.192 38.048 18.216 ;
     RECT  37.333 19.2 38.048 34.776 ;
     RECT  37.676 36.048 38.048 55.128 ;
     RECT  37.969 56.352 38.048 61.128 ;
     RECT  36.785 62.16 38.048 62.184 ;
     RECT  37.313 63.264 38.048 63.288 ;
     RECT  38.048 0.192 38.24 63.732 ;
     RECT  38.24 0.192 38.344 64.002 ;
     RECT  38.344 45.168 38.483 55.512 ;
     RECT  38.344 57.024 38.483 62.184 ;
     RECT  38.483 45.504 38.765 55.512 ;
     RECT  38.483 57.024 38.771 59.976 ;
     RECT  38.483 61.056 38.801 62.184 ;
     RECT  38.344 0.192 38.837 44.136 ;
     RECT  38.765 45.504 38.87 55.416 ;
     RECT  38.801 61.44 39.449 62.184 ;
     RECT  39.449 61.92 39.485 62.184 ;
     RECT  38.837 15.456 39.493 44.136 ;
     RECT  38.771 57.312 39.676 59.976 ;
     RECT  39.676 57.312 39.836 59.064 ;
     RECT  39.493 15.456 39.845 44.472 ;
     RECT  38.837 0.192 39.877 14.232 ;
     RECT  39.845 15.456 39.877 44.136 ;
     RECT  38.87 45.552 40.129 55.416 ;
     RECT  40.129 45.552 40.237 55.464 ;
     RECT  39.836 56.688 40.237 59.064 ;
     RECT  39.877 0.192 40.309 44.136 ;
     RECT  40.237 45.552 40.345 59.064 ;
     RECT  40.345 45.264 40.451 59.064 ;
     RECT  40.451 45.264 40.457 57.384 ;
     RECT  40.129 60.288 40.493 60.312 ;
     RECT  40.309 0.144 40.913 44.136 ;
     RECT  40.457 45.264 40.913 50.184 ;
     RECT  40.451 58.608 40.949 59.064 ;
     RECT  39.485 61.92 41.029 61.944 ;
     RECT  40.913 0.144 41.033 50.184 ;
     RECT  41.029 61.92 41.101 62.184 ;
     RECT  40.949 58.608 41.269 59.304 ;
     RECT  41.101 61.92 41.317 63 ;
     RECT  41.033 0.144 41.357 49.848 ;
     RECT  40.457 51.216 41.461 57.384 ;
     RECT  41.269 58.608 41.461 60.264 ;
     RECT  41.317 61.584 41.713 63 ;
     RECT  41.461 50.832 41.893 60.264 ;
     RECT  41.893 50.832 42.37 60.408 ;
     RECT  41.357 0.144 42.433 45.768 ;
     RECT  42.433 0.048 42.505 45.768 ;
     RECT  41.357 46.848 42.505 49.848 ;
     RECT  42.505 0.048 42.517 49.848 ;
     RECT  42.37 50.832 42.517 60.456 ;
     RECT  42.517 0.048 42.721 60.456 ;
     RECT  41.713 61.584 42.721 63.816 ;
     RECT  42.721 0.048 43.64 63.816 ;
     RECT  43.64 0.048 43.744 64.002 ;
     RECT  43.744 0.048 43.907 57.048 ;
     RECT  43.744 61.104 43.949 61.608 ;
     RECT  43.744 58.32 44.021 59.832 ;
     RECT  43.907 0.048 44.093 55.176 ;
     RECT  44.093 0.096 44.243 55.176 ;
     RECT  44.243 39.168 44.381 55.176 ;
     RECT  43.744 62.784 44.483 63.336 ;
     RECT  44.381 39.168 44.489 54.696 ;
     RECT  43.907 56.16 44.809 57.048 ;
     RECT  44.809 56.16 44.881 57.624 ;
     RECT  43.949 61.584 44.953 61.608 ;
     RECT  44.483 62.784 44.953 63.096 ;
     RECT  44.021 59.04 45.025 59.832 ;
     RECT  44.953 61.584 45.037 63.096 ;
     RECT  44.243 0.096 45.059 37.992 ;
     RECT  45.025 59.04 45.157 60.024 ;
     RECT  45.059 22.176 45.205 37.992 ;
     RECT  44.489 39.168 45.205 54.456 ;
     RECT  44.881 55.968 45.277 57.624 ;
     RECT  45.157 59.04 45.277 61.032 ;
     RECT  45.277 55.968 45.445 61.032 ;
     RECT  45.445 55.872 45.569 61.032 ;
     RECT  45.205 22.176 45.673 54.456 ;
     RECT  45.569 55.872 45.785 60.216 ;
     RECT  45.037 62.16 45.925 63.096 ;
     RECT  45.785 55.872 46.037 57.192 ;
     RECT  45.059 0.096 46.069 21.192 ;
     RECT  45.673 22.176 46.069 54.6 ;
     RECT  46.069 0.096 46.165 54.6 ;
     RECT  46.037 55.872 46.217 57.048 ;
     RECT  45.925 62.16 46.357 63.192 ;
     RECT  45.785 58.32 46.681 60.216 ;
     RECT  46.681 58.32 46.741 60.648 ;
     RECT  46.357 61.632 46.741 63.192 ;
     RECT  46.741 58.32 46.751 63.192 ;
     RECT  46.165 0.096 46.787 54.888 ;
     RECT  46.751 58.32 46.789 63.24 ;
     RECT  46.789 58.224 46.828 63.24 ;
     RECT  46.828 62.208 46.933 63.24 ;
     RECT  46.217 55.968 47.18 57.048 ;
     RECT  46.828 58.224 47.18 61.128 ;
     RECT  47.18 55.968 47.267 61.128 ;
     RECT  46.787 19.824 47.365 54.888 ;
     RECT  47.267 55.968 47.365 57.144 ;
     RECT  46.787 0.096 47.657 18.744 ;
     RECT  47.267 58.224 47.693 61.128 ;
     RECT  47.657 15.6 47.797 18.744 ;
     RECT  46.933 62.208 47.801 63.288 ;
     RECT  47.797 15.6 47.893 18.792 ;
     RECT  47.365 19.824 47.893 57.144 ;
     RECT  47.693 61.056 47.9 61.128 ;
     RECT  47.693 58.224 48.661 60.024 ;
     RECT  47.657 0.096 48.697 14.616 ;
     RECT  47.893 15.6 48.697 57.144 ;
     RECT  48.697 0.096 48.709 57.144 ;
     RECT  48.661 58.128 48.709 60.024 ;
     RECT  47.9 61.056 48.709 61.8 ;
     RECT  48.709 0.096 48.848 61.8 ;
     RECT  47.801 62.832 48.848 63.288 ;
     RECT  48.848 0.096 49.04 63.732 ;
     RECT  49.04 0.096 49.144 64.002 ;
     RECT  49.144 46.176 49.889 57.096 ;
     RECT  49.144 58.128 50.197 61.512 ;
     RECT  49.144 62.736 50.197 63.288 ;
     RECT  49.889 46.32 50.243 57.096 ;
     RECT  50.243 46.752 50.245 57.096 ;
     RECT  50.197 58.128 50.245 63.288 ;
     RECT  50.245 46.752 50.485 63.288 ;
     RECT  49.144 0.096 50.885 44.904 ;
     RECT  50.885 0.096 50.915 45.768 ;
     RECT  50.915 0.096 50.933 6.696 ;
     RECT  50.485 46.752 51.109 63.48 ;
     RECT  51.109 46.752 51.113 63.768 ;
     RECT  51.113 58.08 51.155 63.768 ;
     RECT  51.113 46.752 51.365 57.096 ;
     RECT  51.155 58.08 51.401 62.76 ;
     RECT  51.155 63.744 51.473 63.768 ;
     RECT  51.401 58.464 51.689 62.76 ;
     RECT  50.915 7.92 51.865 45.768 ;
     RECT  51.365 46.752 51.865 54.456 ;
     RECT  51.865 7.92 51.949 54.456 ;
     RECT  51.689 58.464 51.977 61.416 ;
     RECT  51.949 7.92 52.009 45.768 ;
     RECT  50.933 0.096 52.081 5.88 ;
     RECT  52.081 0.096 52.297 6.216 ;
     RECT  51.365 55.776 52.364 57.096 ;
     RECT  51.977 58.464 52.364 61.224 ;
     RECT  51.689 62.448 52.412 62.76 ;
     RECT  52.364 55.776 52.445 61.224 ;
     RECT  52.297 0.096 52.513 6.264 ;
     RECT  52.009 7.344 52.513 45.768 ;
     RECT  52.513 0.096 52.733 45.768 ;
     RECT  52.445 55.776 52.733 61.032 ;
     RECT  52.733 0.48 52.933 45.768 ;
     RECT  51.949 46.752 52.933 54.456 ;
     RECT  52.933 0.48 53.197 54.456 ;
     RECT  53.197 0.48 53.365 54.696 ;
     RECT  52.733 55.776 53.365 60.6 ;
     RECT  52.412 62.448 53.377 62.952 ;
     RECT  53.365 0.48 53.849 60.6 ;
     RECT  53.849 0.528 53.881 60.6 ;
     RECT  53.881 0.528 54.017 60.888 ;
     RECT  54.017 0.528 54.044 61.128 ;
     RECT  53.377 62.448 54.133 63.048 ;
     RECT  54.044 0.528 54.248 61.224 ;
     RECT  54.133 62.448 54.248 63.096 ;
     RECT  54.248 0.528 54.352 63.732 ;
     RECT  54.352 0.576 54.44 63.732 ;
     RECT  54.44 0.576 54.544 64.002 ;
     RECT  54.544 0.576 54.707 45.48 ;
     RECT  54.707 0.576 54.857 45.192 ;
     RECT  54.857 0.576 54.929 11.784 ;
     RECT  54.857 12.96 54.965 45.048 ;
     RECT  54.544 62.64 55.283 63.336 ;
     RECT  54.544 46.56 55.325 60.312 ;
     RECT  54.929 0.96 55.361 11.784 ;
     RECT  55.325 51.312 55.397 60.312 ;
     RECT  55.397 58.08 55.609 60.312 ;
     RECT  55.283 62.64 55.685 63.096 ;
     RECT  55.609 58.08 55.765 60.36 ;
     RECT  54.544 61.344 55.765 61.368 ;
     RECT  55.361 0.96 55.793 6.6 ;
     RECT  55.361 7.584 55.825 11.784 ;
     RECT  54.965 12.96 55.825 14.04 ;
     RECT  55.397 51.312 55.829 57.096 ;
     RECT  55.765 58.08 55.829 61.368 ;
     RECT  55.793 3.072 55.865 6.6 ;
     RECT  55.793 0.96 55.925 1.896 ;
     RECT  55.825 7.584 55.933 14.04 ;
     RECT  54.965 15.024 55.933 45.048 ;
     RECT  55.933 7.584 55.964 45.048 ;
     RECT  55.325 46.56 55.964 50.184 ;
     RECT  55.829 56.4 56.305 57.096 ;
     RECT  55.964 7.584 56.369 50.184 ;
     RECT  56.369 46.176 56.437 50.184 ;
     RECT  55.829 51.312 56.437 55.224 ;
     RECT  55.829 58.08 56.476 61.272 ;
     RECT  55.865 3.072 56.477 6.264 ;
     RECT  55.925 0.816 56.485 1.896 ;
     RECT  56.369 7.584 56.485 45.192 ;
     RECT  56.485 0.624 56.513 1.896 ;
     RECT  56.513 0.624 56.572 0.648 ;
     RECT  56.485 7.392 56.572 45.192 ;
     RECT  56.572 7.488 56.621 45.192 ;
     RECT  55.685 62.736 56.629 63.096 ;
     RECT  56.621 7.488 56.657 14.952 ;
     RECT  56.629 62.736 56.716 63.24 ;
     RECT  56.477 3.072 56.729 6.12 ;
     RECT  56.621 16.08 56.729 45.192 ;
     RECT  56.476 58.08 56.801 58.68 ;
     RECT  56.476 59.856 56.845 61.272 ;
     RECT  56.437 46.176 56.909 55.224 ;
     RECT  56.845 60 56.941 61.272 ;
     RECT  56.716 62.736 56.941 63.048 ;
     RECT  56.657 7.632 57.011 14.952 ;
     RECT  56.941 60 57.052 63.048 ;
     RECT  56.909 46.464 57.085 55.224 ;
     RECT  57.085 46.464 57.097 55.32 ;
     RECT  56.305 56.4 57.107 56.52 ;
     RECT  57.097 46.656 57.121 55.32 ;
     RECT  57.107 56.4 57.121 56.424 ;
     RECT  56.513 1.824 57.125 1.896 ;
     RECT  56.801 58.08 57.157 58.584 ;
     RECT  57.121 46.656 57.161 56.424 ;
     RECT  56.729 3.072 57.201 5.928 ;
     RECT  57.201 2.304 57.299 5.928 ;
     RECT  57.052 61.872 57.443 63.048 ;
     RECT  57.157 57.936 57.481 58.584 ;
     RECT  57.161 46.656 57.485 55.752 ;
     RECT  56.729 16.224 57.596 45.192 ;
     RECT  57.011 7.632 57.637 11.784 ;
     RECT  57.625 1.248 57.731 1.272 ;
     RECT  57.443 62.736 57.769 63.048 ;
     RECT  57.299 2.304 57.773 2.328 ;
     RECT  57.481 57.84 57.877 58.584 ;
     RECT  57.052 60 57.877 60.456 ;
     RECT  57.769 62.736 57.881 63.192 ;
     RECT  57.299 3.312 57.917 5.928 ;
     RECT  57.917 3.552 57.953 5.928 ;
     RECT  57.637 7.44 57.985 11.784 ;
     RECT  57.485 46.704 57.989 55.752 ;
     RECT  57.011 12.864 58.093 14.952 ;
     RECT  57.596 16.224 58.093 45.336 ;
     RECT  57.877 57.84 58.117 60.456 ;
     RECT  57.989 46.752 58.133 55.752 ;
     RECT  58.093 12.864 58.163 45.336 ;
     RECT  57.953 3.552 58.205 3.96 ;
     RECT  57.985 7.2 58.205 11.784 ;
     RECT  57.953 5.136 58.237 5.928 ;
     RECT  58.205 7.2 58.237 8.088 ;
     RECT  58.117 57.84 58.273 61.08 ;
     RECT  58.133 51.744 58.309 55.752 ;
     RECT  57.881 62.736 58.313 63.048 ;
     RECT  58.093 2.256 58.493 2.28 ;
     RECT  58.163 12.912 58.493 45.336 ;
     RECT  58.493 16.56 58.501 45.336 ;
     RECT  58.273 57.552 58.693 61.08 ;
     RECT  58.309 51.744 58.837 56.136 ;
     RECT  58.313 62.736 58.94 62.952 ;
     RECT  58.205 3.648 59.029 3.96 ;
     RECT  58.237 5.136 59.029 8.088 ;
     RECT  58.837 51.744 59.269 56.472 ;
     RECT  58.693 57.552 59.269 61.512 ;
     RECT  58.493 12.912 59.281 15.48 ;
     RECT  58.133 46.752 59.317 50.712 ;
     RECT  59.269 51.744 59.317 61.512 ;
     RECT  59.029 3.648 59.353 8.088 ;
     RECT  58.205 9.168 59.353 11.784 ;
     RECT  59.281 12.864 59.353 15.48 ;
     RECT  59.353 3.648 59.497 15.48 ;
     RECT  58.885 1.68 59.648 1.704 ;
     RECT  59.497 3.408 59.648 15.48 ;
     RECT  58.501 16.56 59.648 45.384 ;
     RECT  59.317 46.752 59.648 61.512 ;
     RECT  58.94 62.592 59.648 62.952 ;
     RECT  59.648 0.528 59.752 63.732 ;
     RECT  59.752 0.798 59.84 63.732 ;
     RECT  59.84 0.798 59.944 64.002 ;
     RECT  59.944 9.792 60.077 12.264 ;
     RECT  59.944 13.248 60.083 50.952 ;
     RECT  59.944 1.392 60.124 8.568 ;
     RECT  60.083 13.248 60.22 15.576 ;
     RECT  60.22 13.68 60.257 15.576 ;
     RECT  59.944 57.936 60.268 62.856 ;
     RECT  60.268 57.936 60.437 59.304 ;
     RECT  60.268 60.384 60.473 62.856 ;
     RECT  60.083 16.752 60.508 50.952 ;
     RECT  60.473 60.576 60.509 62.856 ;
     RECT  60.508 16.896 60.707 50.952 ;
     RECT  60.077 9.792 60.725 12.072 ;
     RECT  59.944 56.016 60.725 56.904 ;
     RECT  60.257 13.872 60.851 15.288 ;
     RECT  60.124 3.312 60.937 8.568 ;
     RECT  60.124 1.392 60.977 1.56 ;
     RECT  60.725 56.352 60.995 56.904 ;
     RECT  60.707 45.6 60.997 50.952 ;
     RECT  59.944 51.936 60.997 54.696 ;
     RECT  60.995 56.448 61.013 56.904 ;
     RECT  60.997 45.6 61.081 54.696 ;
     RECT  60.937 3.312 61.121 9.048 ;
     RECT  60.725 10.224 61.141 12.072 ;
     RECT  61.081 45.6 61.187 54.792 ;
     RECT  61.121 3.312 61.345 7.848 ;
     RECT  61.345 5.28 61.409 7.848 ;
     RECT  61.409 5.28 61.481 5.304 ;
     RECT  60.509 60.576 61.513 62.808 ;
     RECT  61.409 6.288 61.517 6.84 ;
     RECT  61.517 6.72 61.523 6.84 ;
     RECT  61.345 3.312 61.573 4.104 ;
     RECT  61.013 56.448 61.589 56.52 ;
     RECT  61.513 60.576 61.589 63.288 ;
     RECT  61.589 62.784 61.597 63.288 ;
     RECT  60.851 13.872 61.613 15.24 ;
     RECT  61.613 13.632 61.697 15.24 ;
     RECT  61.187 45.6 61.697 54.456 ;
     RECT  61.573 2.88 61.715 4.104 ;
     RECT  60.707 16.896 61.724 44.472 ;
     RECT  61.715 3.6 61.733 4.008 ;
     RECT  61.589 56.496 61.756 56.52 ;
     RECT  61.141 10.224 61.765 12.264 ;
     RECT  60.437 58.704 61.801 59.304 ;
     RECT  61.589 60.576 61.801 61.512 ;
     RECT  61.765 10.224 61.811 12.792 ;
     RECT  61.697 14.544 61.82 15.24 ;
     RECT  61.724 16.416 61.82 44.472 ;
     RECT  61.801 58.704 61.877 61.512 ;
     RECT  61.877 58.704 61.907 60.696 ;
     RECT  61.121 9.024 61.909 9.048 ;
     RECT  61.597 62.784 61.949 62.808 ;
     RECT  61.909 9.024 61.993 9.192 ;
     RECT  61.82 14.544 62.005 44.472 ;
     RECT  61.697 45.6 62.005 54.408 ;
     RECT  61.523 6.72 62.021 6.744 ;
     RECT  60.977 1.536 62.057 1.56 ;
     RECT  61.907 58.704 62.057 58.92 ;
     RECT  62.005 14.544 62.129 54.408 ;
     RECT  62.129 14.784 62.165 54.408 ;
     RECT  61.409 7.824 62.233 7.848 ;
     RECT  61.811 11.808 62.237 12.792 ;
     RECT  62.233 7.824 62.252 7.944 ;
     RECT  62.252 7.824 62.345 8.52 ;
     RECT  62.165 14.784 62.345 53.592 ;
     RECT  62.057 58.704 62.345 58.728 ;
     RECT  62.345 14.784 62.387 53.256 ;
     RECT  62.237 11.808 62.435 11.928 ;
     RECT  61.573 57.6 62.485 57.624 ;
     RECT  61.733 3.6 62.489 3.96 ;
     RECT  61.907 60.672 62.489 60.696 ;
     RECT  62.485 57.6 62.593 58.248 ;
     RECT  62.345 8.304 62.62 8.52 ;
     RECT  62.387 14.784 62.62 52.44 ;
     RECT  62.62 16.512 62.668 52.44 ;
     RECT  62.62 8.496 62.675 8.52 ;
     RECT  62.593 57.024 62.677 58.248 ;
     RECT  62.62 14.784 62.705 15.48 ;
     RECT  62.668 16.512 62.705 50.136 ;
     RECT  62.668 51.36 62.741 52.44 ;
     RECT  62.489 3.936 62.749 3.96 ;
     RECT  62.677 57.024 62.749 57.096 ;
     RECT  62.705 18.816 62.771 50.136 ;
     RECT  62.705 14.88 62.813 14.904 ;
     RECT  62.705 16.512 62.813 17.688 ;
     RECT  62.771 18.864 62.813 50.136 ;
     RECT  62.741 51.792 62.813 52.44 ;
     RECT  62.749 57.072 62.819 57.096 ;
     RECT  62.813 18.864 62.849 46.92 ;
     RECT  62.813 48.288 62.867 49.656 ;
     RECT  62.813 51.792 62.867 52.008 ;
     RECT  62.677 58.224 62.867 58.248 ;
     RECT  62.849 18.864 62.885 45.576 ;
     RECT  62.885 18.864 62.892 44.808 ;
     RECT  62.892 18.864 62.893 19.8 ;
     RECT  62.435 11.904 62.915 11.928 ;
     RECT  62.867 48.288 62.915 48.312 ;
     RECT  62.867 49.632 62.915 49.656 ;
     RECT  61.811 10.416 62.921 10.44 ;
     RECT  62.893 18.912 62.963 19.8 ;
     RECT  62.813 16.512 63.011 16.536 ;
     RECT  62.963 19.776 63.011 19.8 ;
     RECT  62.849 46.896 63.011 46.92 ;
     RECT  62.867 51.984 63.011 52.008 ;
    LAYER M5 ;
     RECT  19.056 0.037 19.08 0.144 ;
     RECT  18.96 0.144 44.04 0.147 ;
     RECT  54.72 0.053 54.744 0.181 ;
     RECT  18.864 0.147 44.04 0.229 ;
     RECT  14.832 0.053 14.856 0.235 ;
     RECT  54.432 0.181 54.744 0.309 ;
     RECT  50.736 0.117 50.76 0.363 ;
     RECT  17.616 0.325 17.64 0.421 ;
     RECT  10.224 0.181 10.248 0.517 ;
     RECT  17.52 0.421 17.64 0.517 ;
     RECT  54.432 0.309 54.84 0.517 ;
     RECT  15.36 0.309 15.384 0.531 ;
     RECT  16.44 0.517 17.64 0.531 ;
     RECT  48.84 0.517 48.96 0.565 ;
     RECT  46.848 0.245 46.872 0.661 ;
     RECT  48.624 0.565 48.96 0.661 ;
     RECT  50.208 0.565 50.616 0.661 ;
     RECT  15.36 0.531 17.64 0.757 ;
     RECT  18.864 0.229 45 0.757 ;
     RECT  46.752 0.661 46.872 0.757 ;
     RECT  0.24 0.517 0.36 0.787 ;
     RECT  5.64 0.517 5.76 0.787 ;
     RECT  10.224 0.517 11.16 0.787 ;
     RECT  59.64 0.517 59.76 0.787 ;
     RECT  56.496 0.613 56.52 0.805 ;
     RECT  5.64 0.787 5.952 0.821 ;
     RECT  46.752 0.757 47.208 0.851 ;
     RECT  55.968 0.805 56.52 0.889 ;
     RECT  48.624 0.661 50.616 0.995 ;
     RECT  8.16 0.757 8.184 1.093 ;
     RECT  10.224 0.787 11.352 1.093 ;
     RECT  15.36 0.757 45 1.189 ;
     RECT  8.16 1.093 11.352 1.331 ;
     RECT  48.624 0.995 49.152 1.333 ;
     RECT  10.656 1.331 11.352 1.363 ;
     RECT  59.64 0.787 59.952 1.381 ;
     RECT  14.208 1.093 14.232 1.451 ;
     RECT  15.36 1.189 45.192 1.475 ;
     RECT  20.112 1.475 45.192 1.525 ;
     RECT  54.24 0.517 54.84 1.573 ;
     RECT  5.64 0.821 6.936 1.669 ;
     RECT  10.656 1.363 11.448 1.669 ;
     RECT  12.528 1.573 12.552 1.669 ;
     RECT  15.36 1.475 18.984 1.669 ;
     RECT  47.184 0.851 47.208 1.669 ;
     RECT  48.576 1.333 49.152 1.669 ;
     RECT  54.24 1.573 55.416 1.669 ;
     RECT  59.64 1.381 60.456 1.669 ;
     RECT  5.088 1.669 6.936 1.973 ;
     RECT  0.24 0.787 0.552 2.067 ;
     RECT  0.24 2.067 0.888 2.155 ;
     RECT  15.216 1.669 18.984 2.219 ;
     RECT  53.904 1.669 55.416 2.293 ;
     RECT  56.496 0.889 56.52 2.293 ;
     RECT  57.696 1.237 57.72 2.293 ;
     RECT  2.832 1.669 2.856 2.437 ;
     RECT  14.112 1.669 14.136 2.437 ;
     RECT  15.216 2.219 18.216 2.437 ;
     RECT  20.112 1.525 45.48 2.629 ;
     RECT  8.16 1.331 9.528 2.677 ;
     RECT  10.656 1.669 12.552 2.677 ;
     RECT  20.112 2.629 46.056 2.731 ;
     RECT  2.64 2.437 2.856 2.783 ;
     RECT  2.64 2.783 3.624 2.867 ;
     RECT  8.16 2.677 12.552 2.869 ;
     RECT  61.584 1.525 61.608 2.869 ;
     RECT  20.112 2.731 46.008 2.917 ;
     RECT  50.64 1.669 50.664 2.917 ;
     RECT  19.488 2.917 46.008 3.107 ;
     RECT  0.24 2.155 0.552 3.189 ;
     RECT  14.112 2.437 18.216 3.205 ;
     RECT  0.24 3.189 1.128 3.299 ;
     RECT  8.16 2.869 12.696 3.301 ;
     RECT  14.112 3.205 18.264 3.301 ;
     RECT  4.992 1.973 6.936 3.397 ;
     RECT  8.16 3.301 18.264 3.397 ;
     RECT  19.488 3.107 22.248 3.397 ;
     RECT  4.992 3.397 18.264 3.499 ;
     RECT  2.64 2.867 2.904 3.539 ;
     RECT  52.512 0.997 52.536 3.541 ;
     RECT  23.376 3.107 46.008 3.695 ;
     RECT  47.184 1.669 49.152 3.695 ;
     RECT  23.376 3.695 49.152 3.779 ;
     RECT  4.992 3.499 12.888 3.819 ;
     RECT  61.584 2.869 61.704 3.925 ;
     RECT  61.584 3.925 62.712 4.011 ;
     RECT  9.168 3.819 12.888 4.075 ;
     RECT  61.584 4.011 61.704 4.115 ;
     RECT  23.376 3.779 46.008 4.165 ;
     RECT  14.256 3.499 18.264 4.213 ;
     RECT  47.184 3.779 49.152 4.213 ;
     RECT  50.16 2.917 50.664 4.213 ;
     RECT  53.904 2.293 57.72 4.261 ;
     RECT  9.168 4.075 9.192 4.307 ;
     RECT  19.392 3.397 22.248 4.345 ;
     RECT  3.264 4.277 3.288 4.365 ;
     RECT  52.224 3.541 52.536 4.405 ;
     RECT  59.04 1.669 60.456 4.453 ;
     RECT  61.584 4.115 61.608 4.453 ;
     RECT  52.08 4.405 52.536 4.533 ;
     RECT  2.256 4.501 2.28 4.587 ;
     RECT  47.184 4.213 50.664 4.587 ;
     RECT  59.04 4.453 61.608 4.587 ;
     RECT  14.256 4.213 18.312 4.595 ;
     RECT  51.648 4.533 52.536 4.691 ;
     RECT  3.504 4.597 3.528 4.739 ;
     RECT  10.272 4.075 12.888 4.883 ;
     RECT  15.216 4.595 18.312 4.933 ;
     RECT  19.392 4.345 22.152 4.933 ;
     RECT  50.16 4.587 50.664 5.125 ;
     RECT  52.512 4.691 52.536 5.125 ;
     RECT  53.712 4.261 57.72 5.125 ;
     RECT  59.04 4.587 60.552 5.125 ;
     RECT  4.992 3.819 8.184 5.237 ;
     RECT  4.992 5.237 8.472 5.291 ;
     RECT  23.232 4.165 46.008 5.317 ;
     RECT  50.16 5.125 51.096 5.411 ;
     RECT  15.216 4.933 22.152 5.685 ;
     RECT  23.232 5.317 46.2 5.685 ;
     RECT  1.776 4.789 1.8 5.699 ;
     RECT  10.32 4.883 12.888 5.749 ;
     RECT  10.32 5.749 13.128 5.893 ;
     RECT  52.512 5.125 60.552 5.971 ;
     RECT  61.584 4.587 61.608 5.971 ;
     RECT  0.24 3.299 0.552 6.099 ;
     RECT  52.512 5.971 61.608 6.131 ;
     RECT  8.16 5.291 8.472 6.181 ;
     RECT  0.144 6.099 0.552 6.187 ;
     RECT  15.216 5.685 46.2 6.187 ;
     RECT  52.512 6.131 52.632 6.191 ;
     RECT  19.392 6.187 46.2 6.227 ;
     RECT  53.904 6.131 61.608 6.251 ;
     RECT  0.24 6.187 0.552 6.261 ;
     RECT  1.728 6.133 1.752 6.261 ;
     RECT  8.16 6.181 9.096 6.265 ;
     RECT  52.416 6.191 52.632 6.275 ;
     RECT  19.536 6.227 46.2 6.285 ;
     RECT  0.24 6.261 1.752 6.323 ;
     RECT  10.32 5.893 13.416 6.805 ;
     RECT  0.24 6.323 1.416 6.827 ;
     RECT  23.232 6.285 46.2 6.837 ;
     RECT  47.184 4.587 49.152 6.837 ;
     RECT  3.504 5.845 3.528 6.851 ;
     RECT  59.04 6.251 61.608 6.851 ;
     RECT  4.992 5.291 6.936 7.189 ;
     RECT  19.536 6.285 22.152 7.189 ;
     RECT  15.216 6.187 18.264 7.237 ;
     RECT  19.392 7.189 22.152 7.285 ;
     RECT  23.232 6.837 49.152 7.285 ;
     RECT  4.992 7.189 7.032 7.333 ;
     RECT  10.32 6.805 13.704 7.333 ;
     RECT  15.216 7.237 18.36 7.333 ;
     RECT  4.992 7.333 7.176 7.381 ;
     RECT  8.16 6.265 8.184 7.381 ;
     RECT  10.32 7.333 18.36 7.403 ;
     RECT  4.992 7.381 8.184 7.417 ;
     RECT  10.32 7.403 18.312 7.417 ;
     RECT  50.16 5.411 50.664 7.541 ;
     RECT  50.16 7.541 50.904 7.629 ;
     RECT  0.24 6.827 0.744 7.669 ;
     RECT  0.144 7.669 0.744 7.763 ;
     RECT  4.992 7.417 6.936 7.797 ;
     RECT  7.92 7.417 8.184 7.859 ;
     RECT  8.16 7.859 8.184 7.861 ;
     RECT  10.32 7.417 14.136 7.861 ;
     RECT  4.848 7.797 6.936 7.885 ;
     RECT  52.608 6.275 52.632 7.909 ;
     RECT  61.584 6.851 61.608 7.909 ;
     RECT  8.16 7.861 9.096 7.945 ;
     RECT  10.272 7.861 14.136 7.957 ;
     RECT  9.648 7.957 14.136 7.979 ;
     RECT  19.392 7.285 49.152 7.989 ;
     RECT  13.68 7.979 14.136 8.003 ;
     RECT  0.24 7.763 0.744 8.051 ;
     RECT  61.584 7.909 62.28 8.275 ;
     RECT  19.296 7.989 49.152 8.303 ;
     RECT  50.16 7.629 50.664 8.303 ;
     RECT  51.84 7.909 52.632 8.437 ;
     RECT  53.904 6.251 57.72 8.437 ;
     RECT  61.584 8.275 62.568 8.467 ;
     RECT  15.216 7.417 18.312 8.485 ;
     RECT  19.296 8.303 50.664 8.485 ;
     RECT  9.648 7.979 12.696 8.521 ;
     RECT  61.584 8.467 62.664 8.555 ;
     RECT  51.84 8.437 57.72 8.675 ;
     RECT  15.216 8.485 50.664 8.747 ;
     RECT  23.28 8.747 50.664 8.771 ;
     RECT  14.112 8.003 14.136 8.821 ;
     RECT  14.112 8.821 14.232 8.979 ;
     RECT  15.216 8.747 22.296 8.979 ;
     RECT  52.368 8.675 57.72 9.011 ;
     RECT  53.664 9.011 57.72 9.037 ;
     RECT  14.112 8.979 22.296 9.067 ;
     RECT  4.992 7.885 6.936 9.109 ;
     RECT  8.16 7.945 8.184 9.109 ;
     RECT  59.04 6.851 60.552 9.119 ;
     RECT  14.112 9.067 14.232 9.203 ;
     RECT  23.328 8.771 50.664 9.203 ;
     RECT  58.704 9.119 60.552 9.203 ;
     RECT  61.584 8.555 61.944 9.203 ;
     RECT  0.24 8.051 0.552 9.349 ;
     RECT  53.904 9.037 57.72 9.349 ;
     RECT  52.368 9.011 52.632 9.635 ;
     RECT  10.32 8.521 12.696 9.647 ;
     RECT  4.992 9.109 8.184 9.747 ;
     RECT  14.016 9.363 14.04 9.925 ;
     RECT  15.216 9.067 22.296 9.973 ;
     RECT  23.328 9.203 46.2 9.973 ;
     RECT  9.648 9.647 12.696 10.067 ;
     RECT  15.216 9.973 46.2 10.067 ;
     RECT  3.408 10.003 3.432 10.091 ;
     RECT  23.328 10.067 46.2 10.155 ;
     RECT  15.216 10.067 22.296 10.211 ;
     RECT  13.776 9.925 14.04 10.213 ;
     RECT  53.904 9.349 58.008 10.213 ;
     RECT  59.04 9.203 60.552 10.213 ;
     RECT  61.584 9.203 61.608 10.213 ;
     RECT  10.32 10.067 12.696 10.271 ;
     RECT  13.776 10.213 14.232 10.271 ;
     RECT  4.512 9.747 8.184 10.293 ;
     RECT  10.32 10.271 14.232 10.323 ;
     RECT  15.216 10.211 18.312 10.323 ;
     RECT  53.904 10.213 60.552 10.323 ;
     RECT  61.584 10.213 61.8 10.323 ;
     RECT  2.832 10.271 2.856 10.355 ;
     RECT  10.32 10.323 18.312 10.404 ;
     RECT  10.32 10.404 18.264 10.411 ;
     RECT  53.904 10.323 61.8 10.411 ;
     RECT  0.24 9.349 0.648 10.741 ;
     RECT  10.32 10.411 14.232 10.795 ;
     RECT  14.208 10.795 14.232 10.883 ;
     RECT  61.584 10.411 61.8 10.883 ;
     RECT  4.176 10.293 8.184 10.931 ;
     RECT  52.608 9.635 52.632 10.981 ;
     RECT  4.416 10.931 8.184 11.017 ;
     RECT  4.416 11.017 6.936 11.075 ;
     RECT  0.24 10.741 0.696 11.307 ;
     RECT  23.328 10.155 46.008 11.315 ;
     RECT  19.392 10.211 22.296 11.317 ;
     RECT  23.328 11.315 30.888 11.317 ;
     RECT  1.824 11.253 1.848 11.363 ;
     RECT  15.216 10.411 18.264 11.381 ;
     RECT  19.392 11.317 30.888 11.381 ;
     RECT  15.216 11.381 30.888 11.411 ;
     RECT  47.184 9.203 50.664 11.469 ;
     RECT  10.32 10.795 13.176 11.563 ;
     RECT  15.216 11.411 22.296 11.563 ;
     RECT  32.256 11.315 46.008 11.567 ;
     RECT  47.184 11.469 49.272 11.567 ;
     RECT  10.32 11.563 13.08 11.603 ;
     RECT  32.256 11.567 49.272 11.651 ;
     RECT  19.392 11.563 22.296 11.747 ;
     RECT  61.68 10.883 61.8 11.797 ;
     RECT  61.68 11.797 62.424 11.883 ;
     RECT  61.68 11.883 61.8 11.939 ;
     RECT  8.16 11.017 8.184 11.941 ;
     RECT  9.216 11.269 9.24 11.941 ;
     RECT  62.88 11.893 62.904 11.977 ;
     RECT  51.984 10.981 52.632 11.989 ;
     RECT  53.904 10.411 60.552 11.989 ;
     RECT  51.984 11.989 60.552 12.133 ;
     RECT  4.992 11.075 6.936 12.213 ;
     RECT  8.16 11.941 9.24 12.213 ;
     RECT  51.84 12.133 60.552 12.213 ;
     RECT  61.68 11.939 61.704 12.213 ;
     RECT  51.84 12.213 61.704 12.217 ;
     RECT  23.28 11.411 30.888 12.275 ;
     RECT  51.888 12.217 61.704 12.301 ;
     RECT  47.184 11.651 49.272 12.517 ;
     RECT  50.256 11.469 50.664 12.517 ;
     RECT  4.992 12.213 9.24 12.563 ;
     RECT  10.32 11.603 12.696 12.691 ;
     RECT  9.696 12.691 12.696 12.779 ;
     RECT  51.888 12.301 60.552 12.779 ;
     RECT  2.448 12.709 2.472 12.793 ;
     RECT  32.256 11.651 46.008 12.917 ;
     RECT  47.184 12.517 50.664 12.917 ;
     RECT  15.216 11.563 18.264 13.011 ;
     RECT  19.392 11.747 22.152 13.011 ;
     RECT  32.256 12.917 50.664 13.043 ;
     RECT  52.032 12.779 60.552 13.043 ;
     RECT  15.216 13.011 22.152 13.093 ;
     RECT  23.328 12.275 30.888 13.093 ;
     RECT  4.992 12.563 8.616 13.099 ;
     RECT  14.592 13.093 22.152 13.099 ;
     RECT  10.32 12.779 12.696 13.109 ;
     RECT  4.992 13.099 8.28 13.187 ;
     RECT  52.608 13.043 60.552 13.235 ;
     RECT  23.328 13.093 30.984 13.295 ;
     RECT  32.256 13.043 49.152 13.295 ;
     RECT  10.32 13.109 13.368 13.331 ;
     RECT  23.328 13.295 49.152 13.379 ;
     RECT  32.16 13.379 49.152 13.483 ;
     RECT  61.68 12.301 61.704 13.621 ;
     RECT  19.392 13.099 22.152 13.685 ;
     RECT  23.328 13.379 30.984 13.685 ;
     RECT  7.968 13.187 8.28 13.811 ;
     RECT  19.392 13.685 30.984 13.867 ;
     RECT  52.608 13.235 56.52 14.163 ;
     RECT  4.992 13.187 6.936 14.197 ;
     RECT  14.592 13.099 18.264 14.197 ;
     RECT  19.392 13.867 22.152 14.197 ;
     RECT  57.6 13.235 60.552 14.197 ;
     RECT  61.632 13.621 61.704 14.197 ;
     RECT  1.872 13.045 1.896 14.243 ;
     RECT  32.256 13.483 49.152 14.245 ;
     RECT  50.256 13.043 50.664 14.245 ;
     RECT  52.368 14.163 56.52 14.245 ;
     RECT  4.608 14.197 6.936 14.281 ;
     RECT  51.744 14.245 56.52 14.303 ;
     RECT  57.6 14.197 61.704 14.303 ;
     RECT  2.88 14.197 2.904 14.443 ;
     RECT  10.32 13.331 12.696 14.629 ;
     RECT  10.32 14.629 13.176 14.713 ;
     RECT  51.744 14.303 61.704 14.739 ;
     RECT  14.592 14.197 22.152 14.773 ;
     RECT  51.744 14.739 62.616 14.819 ;
     RECT  8.16 13.811 8.28 14.827 ;
     RECT  53.568 14.819 62.616 14.831 ;
     RECT  14.256 14.773 22.152 14.857 ;
     RECT  53.568 14.831 62.76 14.905 ;
     RECT  53.808 14.905 62.76 14.915 ;
     RECT  15.216 14.857 22.152 14.917 ;
     RECT  23.328 13.867 30.984 14.917 ;
     RECT  53.808 14.915 62.568 14.989 ;
     RECT  32.256 14.245 50.664 15.093 ;
     RECT  32.256 15.093 50.76 15.187 ;
     RECT  51.744 14.819 52.584 15.187 ;
     RECT  15.216 14.917 30.984 15.349 ;
     RECT  32.256 15.187 52.584 15.349 ;
     RECT  4.992 14.281 6.936 15.413 ;
     RECT  8.16 14.827 8.184 15.413 ;
     RECT  4.992 15.413 8.184 15.571 ;
     RECT  4.128 15.571 8.184 15.659 ;
     RECT  10.32 14.713 13.08 15.685 ;
     RECT  15.216 15.349 52.584 15.989 ;
     RECT  9.6 15.685 13.08 16.019 ;
     RECT  15.216 15.989 52.776 16.043 ;
     RECT  15.216 16.043 49.512 16.067 ;
     RECT  4.992 15.659 8.184 16.163 ;
     RECT  50.64 16.043 52.776 16.165 ;
     RECT  53.808 14.989 56.52 16.165 ;
     RECT  10.32 16.019 13.08 16.213 ;
     RECT  50.64 16.165 56.52 16.213 ;
     RECT  57.696 14.989 62.568 16.213 ;
     RECT  15.216 16.067 30.984 16.437 ;
     RECT  50.64 16.213 62.568 16.501 ;
     RECT  2.16 16.437 2.184 16.525 ;
     RECT  14.688 16.437 30.984 16.525 ;
     RECT  32.112 16.067 49.512 16.555 ;
     RECT  8.16 16.163 8.184 16.645 ;
     RECT  8.16 16.645 8.76 16.747 ;
     RECT  15.216 16.525 30.984 16.835 ;
     RECT  50.64 16.501 63 16.939 ;
     RECT  50.64 16.939 52.872 17.003 ;
     RECT  4.992 16.163 6.936 17.013 ;
     RECT  50.64 17.003 52.536 17.013 ;
     RECT  23.328 16.835 30.984 17.043 ;
     RECT  32.112 16.555 49.368 17.043 ;
     RECT  3.264 16.437 3.288 17.075 ;
     RECT  4.944 17.013 6.936 17.101 ;
     RECT  23.328 17.043 49.368 17.131 ;
     RECT  15.216 16.835 22.296 17.171 ;
     RECT  10.32 16.213 13.608 17.219 ;
     RECT  53.904 16.939 63 17.579 ;
     RECT  0.24 11.307 0.552 17.605 ;
     RECT  32.256 17.131 49.368 17.653 ;
     RECT  50.496 17.013 52.536 17.653 ;
     RECT  3.072 17.589 3.096 17.677 ;
     RECT  23.328 17.131 30.984 17.699 ;
     RECT  32.256 17.653 52.536 17.989 ;
     RECT  1.68 17.077 1.704 18.131 ;
     RECT  4.992 17.101 6.936 18.133 ;
     RECT  32.256 17.989 52.68 18.229 ;
     RECT  53.904 17.579 62.952 18.229 ;
     RECT  15.216 17.171 22.152 18.253 ;
     RECT  4.992 18.133 7.032 18.565 ;
     RECT  8.16 16.747 8.184 18.565 ;
     RECT  32.256 18.229 62.952 18.659 ;
     RECT  0.144 17.605 0.552 18.709 ;
     RECT  19.392 18.253 22.152 18.709 ;
     RECT  4.992 18.565 8.184 18.719 ;
     RECT  10.32 17.219 12.696 18.757 ;
     RECT  0.144 18.709 1.368 18.795 ;
     RECT  3.264 18.709 3.288 18.795 ;
     RECT  19.392 18.709 22.296 18.795 ;
     RECT  0.144 18.795 0.552 18.851 ;
     RECT  4.56 18.719 8.184 18.899 ;
     RECT  8.16 18.899 8.184 18.997 ;
     RECT  9.744 18.757 12.696 18.997 ;
     RECT  32.256 18.659 56.568 19.295 ;
     RECT  15.216 18.253 18.264 19.333 ;
     RECT  19.392 18.795 22.152 19.333 ;
     RECT  31.296 19.295 56.568 19.379 ;
     RECT  8.16 18.997 12.696 19.523 ;
     RECT  15.216 19.333 22.152 19.571 ;
     RECT  10.32 19.523 12.696 19.621 ;
     RECT  4.56 18.899 6.936 19.631 ;
     RECT  15.216 19.571 18.264 19.631 ;
     RECT  1.584 19.603 1.608 19.691 ;
     RECT  3.072 19.621 3.096 19.705 ;
     RECT  4.512 19.631 6.936 19.715 ;
     RECT  8.16 19.523 9.288 19.755 ;
     RECT  57.696 18.659 62.952 19.765 ;
     RECT  14.784 19.631 18.264 19.859 ;
     RECT  14.784 19.859 17.16 19.893 ;
     RECT  31.824 19.379 56.568 19.957 ;
     RECT  57.552 19.765 63 19.957 ;
     RECT  4.992 19.715 6.936 19.987 ;
     RECT  1.68 20.005 1.704 20.089 ;
     RECT  31.824 19.957 63 20.089 ;
     RECT  8.16 19.755 8.808 20.099 ;
     RECT  14.688 19.893 17.16 20.147 ;
     RECT  50.64 20.089 63 20.203 ;
     RECT  0.24 18.851 0.552 20.255 ;
     RECT  0.144 20.255 0.552 20.339 ;
     RECT  1.968 20.277 1.992 20.365 ;
     RECT  57.552 20.203 63 20.395 ;
     RECT  10.32 19.621 12.888 20.437 ;
     RECT  10.32 20.437 13.176 20.675 ;
     RECT  4.992 19.987 7.128 20.725 ;
     RECT  8.16 20.099 8.184 20.725 ;
     RECT  23.328 17.699 30.264 20.965 ;
     RECT  18.24 19.859 18.264 21.013 ;
     RECT  19.392 19.571 22.152 21.013 ;
     RECT  31.824 20.089 49.32 21.109 ;
     RECT  31.824 21.109 49.512 21.253 ;
     RECT  50.64 20.203 56.52 21.253 ;
     RECT  31.824 21.253 56.52 21.359 ;
     RECT  57.792 20.395 63 21.359 ;
     RECT  4.992 20.725 8.184 21.397 ;
     RECT  2.256 21.349 2.28 21.433 ;
     RECT  31.824 21.359 63 21.443 ;
     RECT  4.992 21.397 8.664 21.483 ;
     RECT  31.824 21.443 56.568 21.483 ;
     RECT  4.992 21.483 8.184 21.491 ;
     RECT  13.68 21.407 13.704 21.557 ;
     RECT  15.216 20.147 17.16 21.557 ;
     RECT  13.68 21.557 17.16 21.599 ;
     RECT  18.24 21.013 22.152 21.599 ;
     RECT  23.328 20.965 30.84 21.683 ;
     RECT  7.968 21.491 8.184 21.739 ;
     RECT  52.416 21.483 56.568 21.779 ;
     RECT  31.824 21.483 51.336 21.781 ;
     RECT  52.56 21.779 56.568 21.837 ;
     RECT  31.44 21.781 51.336 21.923 ;
     RECT  31.44 21.923 50.808 22.067 ;
     RECT  0.24 20.339 0.552 22.069 ;
     RECT  3.792 21.781 3.816 22.123 ;
     RECT  0.24 22.069 1.128 22.153 ;
     RECT  13.68 21.599 22.152 22.153 ;
     RECT  4.992 21.491 6.936 22.165 ;
     RECT  31.44 22.067 50.664 22.251 ;
     RECT  10.32 20.675 12.696 22.325 ;
     RECT  13.68 22.153 14.04 22.325 ;
     RECT  10.32 22.325 14.04 22.443 ;
     RECT  57.6 21.443 63 22.443 ;
     RECT  10.32 22.443 13.656 22.453 ;
     RECT  23.328 21.683 30.264 22.453 ;
     RECT  52.608 21.837 56.568 22.453 ;
     RECT  57.6 22.443 62.952 22.453 ;
     RECT  23.184 22.453 30.264 22.595 ;
     RECT  9.552 22.453 13.656 22.739 ;
     RECT  10.32 22.739 13.656 22.835 ;
     RECT  52.608 22.453 62.952 22.943 ;
     RECT  31.968 22.251 50.664 23.029 ;
     RECT  52.56 22.943 62.952 23.509 ;
     RECT  8.16 21.739 8.184 23.519 ;
     RECT  31.968 23.029 51.288 23.519 ;
     RECT  52.416 23.509 62.952 23.519 ;
     RECT  7.968 23.519 8.184 23.541 ;
     RECT  31.968 23.519 62.952 23.595 ;
     RECT  23.328 22.595 30.264 23.605 ;
     RECT  23.232 23.605 30.312 23.699 ;
     RECT  2.592 22.995 2.616 23.701 ;
     RECT  4.032 22.165 6.936 23.701 ;
     RECT  7.968 23.541 9.096 23.701 ;
     RECT  2.496 23.701 2.616 23.733 ;
     RECT  4.032 23.701 9.096 23.733 ;
     RECT  2.496 23.733 9.096 23.787 ;
     RECT  3.408 23.787 9.096 23.797 ;
     RECT  10.32 22.835 12.696 23.797 ;
     RECT  3.408 23.797 12.696 23.881 ;
     RECT  31.968 23.595 52.632 23.893 ;
     RECT  1.632 23.903 2.328 23.987 ;
     RECT  3.408 23.881 9.288 23.987 ;
     RECT  15.216 22.153 22.152 24.095 ;
     RECT  10.32 23.881 12.696 24.117 ;
     RECT  3.408 23.987 7.032 24.265 ;
     RECT  10.32 24.117 13.224 24.299 ;
     RECT  15.216 24.095 22.248 24.427 ;
     RECT  0.24 22.153 0.552 24.437 ;
     RECT  19.296 24.427 22.248 24.469 ;
     RECT  23.232 23.699 30.264 24.469 ;
     RECT  0.24 24.437 0.936 24.525 ;
     RECT  31.92 23.893 52.632 24.565 ;
     RECT  53.616 23.595 62.952 24.565 ;
     RECT  31.92 24.565 62.952 24.661 ;
     RECT  15.216 24.427 18.312 24.805 ;
     RECT  13.68 24.723 13.992 24.811 ;
     RECT  19.296 24.469 30.264 24.821 ;
     RECT  31.344 24.661 62.952 24.821 ;
     RECT  13.68 24.811 13.704 24.875 ;
     RECT  14.976 24.805 18.312 24.939 ;
     RECT  3.936 24.265 7.032 24.949 ;
     RECT  8.064 23.987 9.288 24.949 ;
     RECT  3.936 24.949 9.288 25.043 ;
     RECT  2.304 23.987 2.328 25.045 ;
     RECT  2.256 25.045 2.328 25.189 ;
     RECT  2.256 25.189 2.76 25.195 ;
     RECT  3.936 25.043 7.032 25.195 ;
     RECT  8.064 25.043 9.288 25.269 ;
     RECT  10.32 24.299 12.648 25.269 ;
     RECT  2.736 25.195 2.76 25.323 ;
     RECT  19.296 24.821 62.952 25.323 ;
     RECT  8.064 25.269 12.648 25.357 ;
     RECT  19.536 25.323 62.952 25.379 ;
     RECT  47.088 25.379 62.952 25.387 ;
     RECT  15.216 24.939 18.312 25.417 ;
     RECT  15.216 25.417 18.264 25.451 ;
     RECT  19.536 25.379 46.008 25.523 ;
     RECT  19.536 25.523 30.792 25.571 ;
     RECT  2.832 25.525 2.856 25.609 ;
     RECT  8.064 25.357 8.808 25.899 ;
     RECT  4.752 25.195 7.032 26.155 ;
     RECT  31.92 25.523 46.008 26.243 ;
     RECT  4.992 26.155 7.032 26.389 ;
     RECT  8.064 25.899 8.568 26.389 ;
     RECT  10.128 25.357 12.648 26.389 ;
     RECT  19.536 25.571 30.408 26.549 ;
     RECT  3.936 26.485 3.96 26.569 ;
     RECT  47.184 25.387 62.952 26.581 ;
     RECT  10.128 26.389 13.08 26.629 ;
     RECT  14.208 25.813 14.232 26.629 ;
     RECT  32.256 26.243 46.008 26.677 ;
     RECT  47.136 26.581 62.952 26.677 ;
     RECT  10.128 26.629 14.232 26.761 ;
     RECT  10.128 26.761 13.704 26.795 ;
     RECT  32.256 26.677 62.952 26.832 ;
     RECT  18.24 25.451 18.264 26.869 ;
     RECT  19.344 26.549 30.408 26.869 ;
     RECT  18.24 26.869 30.408 26.953 ;
     RECT  10.32 26.795 13.704 27.059 ;
     RECT  19.44 26.953 30.408 27.059 ;
     RECT  4.992 26.389 8.568 27.061 ;
     RECT  19.44 27.059 27.864 27.179 ;
     RECT  51.744 26.832 62.952 27.385 ;
     RECT  51.744 27.385 56.664 27.435 ;
     RECT  57.744 27.385 62.952 27.435 ;
     RECT  32.256 26.832 50.76 27.443 ;
     RECT  15.216 25.451 17.16 27.445 ;
     RECT  32.256 27.443 50.664 27.499 ;
     RECT  57.792 27.435 62.904 27.691 ;
     RECT  15.216 27.445 17.208 27.701 ;
     RECT  14.784 27.701 17.208 27.755 ;
     RECT  4.992 27.061 9 27.875 ;
     RECT  32.256 27.499 46.008 27.877 ;
     RECT  19.44 27.179 22.152 27.883 ;
     RECT  51.888 27.435 56.664 27.913 ;
     RECT  13.632 27.059 13.704 27.971 ;
     RECT  14.784 27.755 17.16 27.971 ;
     RECT  47.04 27.499 50.664 27.971 ;
     RECT  13.68 27.971 13.704 28.067 ;
     RECT  50.208 27.971 50.664 28.067 ;
     RECT  2.832 28.261 2.856 28.405 ;
     RECT  52.512 27.913 56.664 28.405 ;
     RECT  57.792 27.691 62.76 28.405 ;
     RECT  2.688 28.405 3.432 28.453 ;
     RECT  4.992 27.875 8.424 28.453 ;
     RECT  28.848 27.059 30.408 28.459 ;
     RECT  31.536 27.877 46.008 28.459 ;
     RECT  2.688 28.453 8.424 28.489 ;
     RECT  2.688 28.489 2.904 28.547 ;
     RECT  19.536 27.883 22.152 28.741 ;
     RECT  23.328 27.179 27.864 28.741 ;
     RECT  50.64 28.067 50.664 28.789 ;
     RECT  4.272 28.489 8.424 28.837 ;
     RECT  19.536 28.741 27.864 28.837 ;
     RECT  28.848 28.459 30.312 28.837 ;
     RECT  19.536 28.837 30.312 28.931 ;
     RECT  4.272 28.837 9.336 28.981 ;
     RECT  10.32 27.059 12.648 28.981 ;
     RECT  52.512 28.405 62.76 28.981 ;
     RECT  50.64 28.789 51.048 29.015 ;
     RECT  19.536 28.931 22.248 29.035 ;
     RECT  47.04 27.971 49.152 29.045 ;
     RECT  50.64 29.015 51.192 29.045 ;
     RECT  1.68 28.981 1.704 29.065 ;
     RECT  4.272 28.981 12.648 29.075 ;
     RECT  15.216 27.971 17.16 29.077 ;
     RECT  47.04 29.045 51.192 29.113 ;
     RECT  2.88 28.547 2.904 29.123 ;
     RECT  4.272 29.075 9.336 29.133 ;
     RECT  7.92 29.133 9.336 29.219 ;
     RECT  10.32 29.075 12.648 29.365 ;
     RECT  15.216 29.077 17.256 29.429 ;
     RECT  18.24 26.953 18.264 29.429 ;
     RECT  19.536 29.035 22.152 29.429 ;
     RECT  32.256 28.459 46.008 29.461 ;
     RECT  15.216 29.429 22.152 29.517 ;
     RECT  10.32 29.365 13.464 29.547 ;
     RECT  47.04 29.113 51.144 29.547 ;
     RECT  52.464 28.981 62.76 29.547 ;
     RECT  31.872 29.461 46.008 29.663 ;
     RECT  47.04 29.547 50.76 29.663 ;
     RECT  4.272 29.133 6.936 29.795 ;
     RECT  9.312 29.219 9.336 29.795 ;
     RECT  4.272 29.795 4.296 30.005 ;
     RECT  3.936 30.005 4.296 30.085 ;
     RECT  0.24 24.525 0.552 30.133 ;
     RECT  2.304 29.941 2.328 30.133 ;
     RECT  3.792 30.085 4.296 30.133 ;
     RECT  10.32 29.547 13.32 30.181 ;
     RECT  23.328 28.931 30.312 30.517 ;
     RECT  23.328 30.517 30.792 30.565 ;
     RECT  31.872 29.663 50.76 30.565 ;
     RECT  2.304 30.133 4.296 30.611 ;
     RECT  5.424 29.795 6.936 30.757 ;
     RECT  7.92 29.219 8.184 30.757 ;
     RECT  2.304 30.611 4.008 30.763 ;
     RECT  52.464 29.547 62.472 30.773 ;
     RECT  2.304 30.763 2.328 30.815 ;
     RECT  18.24 29.517 18.264 30.815 ;
     RECT  19.536 29.517 22.152 30.815 ;
     RECT  23.328 30.565 50.76 30.861 ;
     RECT  2.256 30.815 2.328 30.899 ;
     RECT  18.24 30.815 22.152 30.899 ;
     RECT  5.424 30.757 8.184 30.965 ;
     RECT  9.552 30.181 13.32 31.221 ;
     RECT  31.344 30.861 50.76 31.237 ;
     RECT  31.344 31.237 51.48 31.349 ;
     RECT  52.464 30.773 62.616 31.349 ;
     RECT  3.408 30.763 4.008 31.379 ;
     RECT  9.552 31.221 13.656 31.379 ;
     RECT  31.344 31.349 62.616 31.381 ;
     RECT  9.648 31.379 13.56 31.427 ;
     RECT  3.648 31.379 4.008 31.437 ;
     RECT  9.648 31.427 12.648 31.667 ;
     RECT  5.088 30.965 8.184 31.765 ;
     RECT  2.304 30.899 2.328 31.797 ;
     RECT  19.488 30.899 22.152 31.797 ;
     RECT  23.328 30.861 30.264 31.797 ;
     RECT  4.56 31.765 8.184 31.827 ;
     RECT  4.56 31.827 8.616 31.851 ;
     RECT  2.304 31.797 2.664 31.885 ;
     RECT  31.344 31.381 62.76 31.909 ;
     RECT  5.424 31.851 8.616 31.915 ;
     RECT  0.144 30.133 0.552 31.955 ;
     RECT  2.304 31.885 2.328 31.955 ;
     RECT  19.488 31.797 30.264 31.955 ;
     RECT  31.296 31.909 62.76 31.989 ;
     RECT  31.296 31.989 62.808 31.993 ;
     RECT  23.328 31.955 30.264 32.149 ;
     RECT  23.328 32.149 30.792 32.195 ;
     RECT  18.24 30.899 18.264 32.351 ;
     RECT  19.488 31.955 22.248 32.351 ;
     RECT  18.24 32.351 22.248 32.435 ;
     RECT  28.848 32.195 30.792 32.435 ;
     RECT  32.064 31.993 62.808 32.485 ;
     RECT  23.328 32.195 27.864 32.496 ;
     RECT  5.424 31.915 8.184 32.531 ;
     RECT  15.216 29.517 17.256 32.579 ;
     RECT  32.064 32.485 62.856 32.579 ;
     RECT  52.512 32.579 62.856 32.683 ;
     RECT  5.64 32.531 8.184 32.963 ;
     RECT  8.16 32.963 8.184 32.979 ;
     RECT  10.32 31.667 12.648 32.979 ;
     RECT  3.408 32.927 3.432 33.011 ;
     RECT  32.064 32.579 51.384 33.071 ;
     RECT  19.392 32.435 22.248 33.107 ;
     RECT  9.936 32.979 12.648 33.205 ;
     RECT  9.936 33.205 13.272 33.235 ;
     RECT  52.512 32.683 62.808 33.259 ;
     RECT  9.696 33.235 13.272 33.299 ;
     RECT  9.696 33.299 12.648 33.323 ;
     RECT  8.16 32.979 8.712 33.347 ;
     RECT  0.24 31.955 0.552 33.397 ;
     RECT  31.296 33.071 51.384 33.589 ;
     RECT  52.512 33.259 52.536 33.589 ;
     RECT  9.312 33.541 9.336 33.683 ;
     RECT  28.848 32.435 30.264 33.781 ;
     RECT  31.296 33.589 52.536 33.781 ;
     RECT  14.112 33.829 14.136 33.845 ;
     RECT  28.848 33.781 52.536 33.865 ;
     RECT  3.936 33.781 3.96 33.875 ;
     RECT  14.112 33.845 14.232 33.913 ;
     RECT  14.208 33.913 14.232 34.115 ;
     RECT  23.328 32.496 27.768 34.259 ;
     RECT  15.216 32.579 17.16 34.323 ;
     RECT  0.24 33.397 0.792 34.357 ;
     RECT  15.12 34.323 17.16 34.357 ;
     RECT  18.24 32.435 18.264 34.357 ;
     RECT  32.016 33.865 52.536 34.357 ;
     RECT  53.568 33.259 62.808 34.357 ;
     RECT  15.12 34.357 18.264 34.411 ;
     RECT  32.016 34.357 62.808 34.411 ;
     RECT  0.144 34.357 0.792 34.441 ;
     RECT  3.984 34.357 4.008 34.441 ;
     RECT  32.256 34.411 62.808 34.539 ;
     RECT  15.216 34.411 18.264 34.691 ;
     RECT  18.192 34.691 18.264 34.693 ;
     RECT  19.392 33.107 22.152 34.693 ;
     RECT  2.448 34.117 2.472 34.741 ;
     RECT  2.448 34.741 2.856 34.825 ;
     RECT  2.448 34.825 2.472 34.835 ;
     RECT  0.24 34.441 0.792 34.931 ;
     RECT  18.192 34.693 22.152 34.931 ;
     RECT  8.16 33.347 8.184 34.997 ;
     RECT  18.24 34.931 22.152 35.209 ;
     RECT  5.64 32.963 6.936 35.317 ;
     RECT  7.968 34.997 8.184 35.363 ;
     RECT  32.256 34.539 51.384 35.423 ;
     RECT  5.04 35.317 6.936 35.459 ;
     RECT  31.92 35.423 51.384 35.507 ;
     RECT  32.016 35.507 51.384 35.509 ;
     RECT  52.464 34.539 62.808 35.509 ;
     RECT  32.016 35.509 62.808 35.555 ;
     RECT  51.648 35.555 62.808 35.637 ;
     RECT  32.016 35.555 50.664 35.691 ;
     RECT  8.16 35.363 8.184 35.701 ;
     RECT  32.112 35.691 50.664 35.819 ;
     RECT  51.648 35.637 62.856 35.819 ;
     RECT  0.24 34.931 0.552 35.893 ;
     RECT  52.368 35.819 62.856 35.987 ;
     RECT  8.16 35.701 8.856 36.115 ;
     RECT  10.32 33.323 12.648 36.115 ;
     RECT  15.216 34.691 17.16 36.213 ;
     RECT  0.144 35.893 0.552 36.275 ;
     RECT  14.784 36.213 17.16 36.301 ;
     RECT  28.848 33.865 30.264 36.383 ;
     RECT  8.16 36.115 12.648 36.395 ;
     RECT  5.184 35.459 6.936 36.435 ;
     RECT  8.16 36.395 8.184 36.435 ;
     RECT  19.488 35.209 22.152 36.435 ;
     RECT  9.984 36.395 12.648 36.469 ;
     RECT  23.328 34.259 27.72 36.515 ;
     RECT  5.184 36.435 8.184 36.523 ;
     RECT  19.488 36.435 22.248 36.523 ;
     RECT  32.256 35.819 50.664 36.533 ;
     RECT  18.24 35.209 18.264 36.575 ;
     RECT  19.488 36.523 22.152 36.575 ;
     RECT  9.984 36.469 13.128 36.597 ;
     RECT  15.216 36.301 17.16 36.597 ;
     RECT  18.24 36.575 22.152 36.597 ;
     RECT  5.184 36.523 6.984 36.709 ;
     RECT  5.088 36.709 6.984 36.779 ;
     RECT  5.088 36.779 6.888 36.793 ;
     RECT  3.984 36.853 4.008 36.901 ;
     RECT  9.984 36.597 13.224 36.997 ;
     RECT  3.984 36.901 4.536 37.045 ;
     RECT  28.848 36.383 30.792 37.045 ;
     RECT  32.256 36.533 51.288 37.045 ;
     RECT  3.936 37.045 4.536 37.099 ;
     RECT  32.256 37.045 51.336 37.173 ;
     RECT  52.464 35.987 62.856 37.173 ;
     RECT  28.848 37.045 31.08 37.227 ;
     RECT  9.984 36.997 13.368 37.237 ;
     RECT  15.216 36.597 22.152 37.283 ;
     RECT  8.16 36.523 8.184 37.395 ;
     RECT  9.984 37.237 13.56 37.429 ;
     RECT  9.696 37.429 13.56 37.513 ;
     RECT  8.16 37.395 8.28 37.573 ;
     RECT  3.936 37.099 3.96 37.619 ;
     RECT  18.144 37.283 22.152 37.621 ;
     RECT  5.52 36.793 6.888 37.645 ;
     RECT  10.32 37.513 13.56 37.715 ;
     RECT  18.144 37.621 22.392 37.715 ;
     RECT  32.256 37.173 62.856 37.867 ;
     RECT  18.24 37.715 22.392 37.877 ;
     RECT  23.376 36.515 27.72 37.877 ;
     RECT  7.968 37.573 8.28 37.919 ;
     RECT  7.968 37.919 9.144 37.971 ;
     RECT  32.256 37.867 51.288 37.995 ;
     RECT  7.248 37.971 9.144 38.003 ;
     RECT  32.256 37.995 50.568 38.005 ;
     RECT  7.248 38.003 8.184 38.059 ;
     RECT  28.848 37.227 30.792 38.059 ;
     RECT  7.392 38.059 8.184 38.187 ;
     RECT  31.92 38.005 50.568 38.208 ;
     RECT  3.744 38.197 3.768 38.291 ;
     RECT  13.632 38.389 13.656 38.473 ;
     RECT  52.272 37.867 62.856 38.579 ;
     RECT  2.88 38.325 2.904 38.635 ;
     RECT  52.32 38.579 62.856 38.635 ;
     RECT  7.968 38.187 8.184 38.963 ;
     RECT  18.24 37.877 27.72 39.061 ;
     RECT  28.848 38.059 30.264 39.061 ;
     RECT  8.16 38.963 8.184 39.157 ;
     RECT  8.16 39.157 8.616 39.251 ;
     RECT  31.968 38.208 50.568 39.275 ;
     RECT  52.368 38.635 62.856 39.531 ;
     RECT  52.368 39.531 62.808 39.659 ;
     RECT  10.32 37.715 12.648 39.699 ;
     RECT  13.68 39.397 13.704 39.699 ;
     RECT  32.256 39.275 50.568 39.699 ;
     RECT  52.368 39.659 62.76 39.699 ;
     RECT  10.32 39.699 13.704 39.733 ;
     RECT  9.648 39.733 13.704 39.787 ;
     RECT  18.24 39.061 30.264 39.787 ;
     RECT  5.52 37.645 5.952 39.829 ;
     RECT  4.848 39.829 5.952 39.839 ;
     RECT  4.848 39.839 6.936 39.915 ;
     RECT  23.712 39.787 30.264 39.915 ;
     RECT  1.68 38.149 1.704 39.923 ;
     RECT  5.328 39.915 6.936 39.923 ;
     RECT  9.648 39.787 12.648 39.923 ;
     RECT  3.504 39.925 3.528 40.019 ;
     RECT  13.68 39.787 13.704 40.019 ;
     RECT  10.224 39.923 12.648 40.067 ;
     RECT  23.76 39.915 30.264 40.363 ;
     RECT  8.16 39.251 8.184 40.501 ;
     RECT  15.216 37.283 17.16 40.501 ;
     RECT  18.24 39.787 22.152 40.501 ;
     RECT  23.856 40.363 30.264 40.501 ;
     RECT  5.328 39.923 6.312 40.595 ;
     RECT  10.224 40.067 12.216 40.595 ;
     RECT  15.216 40.501 22.152 40.595 ;
     RECT  23.856 40.501 30.312 40.595 ;
     RECT  1.728 40.405 1.752 40.619 ;
     RECT  23.856 40.595 30.264 40.633 ;
     RECT  8.064 40.501 8.184 40.693 ;
     RECT  5.328 40.595 5.952 40.875 ;
     RECT  3.6 40.565 3.624 40.896 ;
     RECT  8.064 40.693 9.096 41.161 ;
     RECT  8.064 41.161 8.184 41.397 ;
     RECT  10.32 40.595 12.216 41.461 ;
     RECT  32.256 39.699 62.76 41.557 ;
     RECT  2.4 41.029 2.424 41.567 ;
     RECT  0.24 36.275 0.552 41.589 ;
     RECT  2.4 41.567 2.808 41.651 ;
     RECT  3.888 41.567 4.536 41.651 ;
     RECT  23.856 40.633 27.816 41.651 ;
     RECT  0.24 41.589 0.648 41.677 ;
     RECT  7.872 41.397 8.184 41.699 ;
     RECT  26.208 41.651 27.816 41.797 ;
     RECT  28.848 40.633 30.264 41.797 ;
     RECT  5.64 40.875 5.952 42.003 ;
     RECT  31.92 41.557 62.76 42.027 ;
     RECT  31.92 42.027 51.288 42.085 ;
     RECT  5.64 42.003 6.312 42.091 ;
     RECT  26.208 41.797 30.264 42.091 ;
     RECT  18.24 40.595 22.152 42.143 ;
     RECT  2.4 41.651 2.424 42.227 ;
     RECT  8.16 41.699 8.184 42.227 ;
     RECT  10.32 41.461 13.128 42.227 ;
     RECT  14.112 42.143 14.136 42.227 ;
     RECT  15.216 40.595 17.16 42.421 ;
     RECT  18.144 42.143 22.152 42.421 ;
     RECT  10.32 42.227 12.024 42.505 ;
     RECT  30 42.091 30.264 42.549 ;
     RECT  31.872 42.085 51.288 42.671 ;
     RECT  10.32 42.505 11.832 42.707 ;
     RECT  13.104 42.227 13.128 42.707 ;
     RECT  31.824 42.671 51.288 42.755 ;
     RECT  15.216 42.421 22.152 42.795 ;
     RECT  19.488 42.795 22.152 42.949 ;
     RECT  30 42.549 30.408 42.997 ;
     RECT  26.208 42.091 28.968 43.081 ;
     RECT  30 42.997 30.84 43.081 ;
     RECT  8.88 43.141 8.904 43.189 ;
     RECT  10.32 42.707 11.544 43.189 ;
     RECT  7.44 43.141 7.464 43.219 ;
     RECT  4.128 41.651 4.344 43.235 ;
     RECT  6.96 43.219 7.464 43.243 ;
     RECT  8.88 43.189 11.544 43.243 ;
     RECT  28.848 43.081 28.968 43.295 ;
     RECT  30 43.081 30.264 43.295 ;
     RECT  6.96 43.243 6.984 43.307 ;
     RECT  19.488 42.949 22.248 43.371 ;
     RECT  3.408 43.253 3.432 43.379 ;
     RECT  28.848 43.295 30.264 43.379 ;
     RECT  15.216 42.795 18.264 43.427 ;
     RECT  0.24 41.677 0.552 43.717 ;
     RECT  52.512 42.027 62.76 43.763 ;
     RECT  1.728 43.765 1.752 43.795 ;
     RECT  32.112 42.755 51.288 43.795 ;
     RECT  0.24 43.717 0.696 43.819 ;
     RECT  2.88 43.765 2.904 43.849 ;
     RECT  1.728 43.795 1.848 43.859 ;
     RECT  19.488 43.371 22.152 43.871 ;
     RECT  1.824 43.859 1.848 43.883 ;
     RECT  13.008 43.701 13.032 43.883 ;
     RECT  31.536 43.795 51.288 43.883 ;
     RECT  19.248 43.871 22.152 43.955 ;
     RECT  52.512 43.763 57.72 43.957 ;
     RECT  32.256 43.883 51.288 44.005 ;
     RECT  52.464 43.957 57.72 44.005 ;
     RECT  18.24 43.427 18.264 44.021 ;
     RECT  8.064 43.861 8.088 44.075 ;
     RECT  9.12 43.243 11.544 44.075 ;
     RECT  32.256 44.005 57.72 44.089 ;
     RECT  18.24 44.021 18.36 44.109 ;
     RECT  58.704 43.763 62.76 44.405 ;
     RECT  52.464 44.089 57.72 44.435 ;
     RECT  32.256 44.089 51.288 44.531 ;
     RECT  23.856 41.651 25.176 44.581 ;
     RECT  58.704 44.405 62.808 44.581 ;
     RECT  23.616 44.581 25.176 44.597 ;
     RECT  26.208 43.081 27.72 44.597 ;
     RECT  23.616 44.597 27.72 44.665 ;
     RECT  9.648 44.075 11.544 44.688 ;
     RECT  28.848 43.379 28.872 44.773 ;
     RECT  30 43.379 30.264 44.773 ;
     RECT  5.64 42.091 5.952 44.965 ;
     RECT  19.488 43.955 22.152 44.965 ;
     RECT  28.848 44.773 30.264 45.157 ;
     RECT  19.392 44.965 22.152 45.215 ;
     RECT  7.392 45.157 7.416 45.241 ;
     RECT  19.392 45.215 22.824 45.299 ;
     RECT  23.808 44.665 27.72 45.299 ;
     RECT  52.512 44.435 57.72 45.301 ;
     RECT  58.704 44.581 62.856 45.301 ;
     RECT  8.592 45.267 8.616 45.355 ;
     RECT  32.256 44.531 50.664 45.385 ;
     RECT  52.512 45.301 62.856 45.395 ;
     RECT  52.512 45.395 57.72 45.523 ;
     RECT  15.216 43.427 17.16 45.539 ;
     RECT  23.856 45.299 27.72 45.541 ;
     RECT  28.704 45.157 30.264 45.541 ;
     RECT  32.256 45.385 46.008 45.541 ;
     RECT  15.312 45.539 17.16 45.551 ;
     RECT  18.24 44.109 18.264 45.551 ;
     RECT  23.856 45.541 30.264 45.587 ;
     RECT  23.856 45.587 28.968 45.611 ;
     RECT  58.704 45.395 62.856 45.625 ;
     RECT  2.352 45.599 2.376 45.683 ;
     RECT  47.184 45.385 50.664 45.685 ;
     RECT  47.184 45.685 50.952 45.779 ;
     RECT  30 45.587 30.264 45.791 ;
     RECT  31.344 45.541 46.008 45.791 ;
     RECT  26.16 45.611 28.968 45.931 ;
     RECT  10.32 44.688 11.544 46.099 ;
     RECT  4.656 44.965 5.952 46.117 ;
     RECT  52.416 45.523 57.72 46.175 ;
     RECT  30 45.791 46.008 46.211 ;
     RECT  15.312 45.551 18.264 46.259 ;
     RECT  26.16 45.931 27.72 46.259 ;
     RECT  30 46.211 39.912 46.259 ;
     RECT  19.392 45.299 22.152 46.357 ;
     RECT  9.072 46.357 9.096 46.443 ;
     RECT  0.24 43.819 0.552 46.645 ;
     RECT  4.656 46.117 6.072 46.693 ;
     RECT  10.32 46.099 11.832 46.693 ;
     RECT  28.848 45.931 28.968 46.693 ;
     RECT  30 46.259 30.264 46.693 ;
     RECT  41.04 46.211 46.008 46.751 ;
     RECT  47.184 45.779 50.712 46.751 ;
     RECT  51.888 46.175 57.72 46.751 ;
     RECT  58.704 45.625 62.808 46.751 ;
     RECT  4.656 46.693 6.84 46.773 ;
     RECT  19.248 46.357 22.152 46.787 ;
     RECT  0.24 46.645 1.128 46.827 ;
     RECT  51.888 46.751 62.808 46.837 ;
     RECT  3.696 46.773 6.84 46.861 ;
     RECT  19.248 46.787 20.424 46.861 ;
     RECT  51.888 46.837 63 46.931 ;
     RECT  41.04 46.751 50.712 46.933 ;
     RECT  4.656 46.861 6.84 46.965 ;
     RECT  10.32 46.693 11.976 46.965 ;
     RECT  15.312 46.259 17.16 46.965 ;
     RECT  51.888 46.931 62.76 46.965 ;
     RECT  4.656 46.965 7.608 47.027 ;
     RECT  5.64 47.027 7.608 47.053 ;
     RECT  10.32 46.965 12.168 47.075 ;
     RECT  14.064 46.965 17.16 47.075 ;
     RECT  41.04 46.933 50.76 47.211 ;
     RECT  15.312 47.075 17.16 47.251 ;
     RECT  18.24 46.259 18.264 47.251 ;
     RECT  14.064 47.075 14.088 47.269 ;
     RECT  51.84 46.965 62.76 47.275 ;
     RECT  41.136 47.211 50.76 47.317 ;
     RECT  51.84 47.275 62.712 47.317 ;
     RECT  13.296 47.269 14.088 47.363 ;
     RECT  15.312 47.251 18.264 47.363 ;
     RECT  21.552 46.787 22.152 47.363 ;
     RECT  23.856 45.611 25.176 47.363 ;
     RECT  28.848 46.693 30.264 47.363 ;
     RECT  31.344 46.259 39.912 47.363 ;
     RECT  41.136 47.317 62.712 47.363 ;
     RECT  41.136 47.363 51.432 47.403 ;
     RECT  32.64 47.363 39.912 47.411 ;
     RECT  41.136 47.403 50.664 47.507 ;
     RECT  41.136 47.507 46.2 47.555 ;
     RECT  47.28 47.507 50.664 47.595 ;
     RECT  7.584 47.053 7.608 47.603 ;
     RECT  52.416 47.363 62.712 47.603 ;
     RECT  41.136 47.555 46.008 47.659 ;
     RECT  41.184 47.659 46.008 47.787 ;
     RECT  31.344 47.363 31.656 47.851 ;
     RECT  26.208 46.259 27.72 47.855 ;
     RECT  26.16 47.855 27.72 47.939 ;
     RECT  48.288 47.595 50.664 47.939 ;
     RECT  41.232 47.787 46.008 47.987 ;
     RECT  15.504 47.363 18.264 48.053 ;
     RECT  19.248 46.861 20.376 48.053 ;
     RECT  42.336 47.987 46.008 48.083 ;
     RECT  15.504 48.053 20.376 48.141 ;
     RECT  10.32 47.075 11.976 48.245 ;
     RECT  5.64 47.053 6.072 48.277 ;
     RECT  58.704 47.603 62.712 48.277 ;
     RECT  5.088 48.277 6.072 48.309 ;
     RECT  5.088 48.309 6.504 48.363 ;
     RECT  58.704 48.277 62.904 48.363 ;
     RECT  5.64 48.363 6.504 48.373 ;
     RECT  13.296 47.363 13.32 48.373 ;
     RECT  9.984 48.245 11.976 48.419 ;
     RECT  52.416 47.603 57.72 48.421 ;
     RECT  32.64 47.411 39.096 48.431 ;
     RECT  10.32 48.419 11.976 48.457 ;
     RECT  26.208 47.939 27.72 48.515 ;
     RECT  41.232 47.987 41.256 48.515 ;
     RECT  58.704 48.363 62.856 48.555 ;
     RECT  58.704 48.555 60.6 48.851 ;
     RECT  13.296 48.373 13.704 48.853 ;
     RECT  48.288 47.939 50.232 48.901 ;
     RECT  28.848 47.363 28.872 48.915 ;
     RECT  30 47.363 30.264 48.915 ;
     RECT  5.64 48.373 6.888 48.949 ;
     RECT  21.84 47.363 22.152 48.997 ;
     RECT  48.288 48.901 50.376 49.013 ;
     RECT  5.64 48.949 7.464 49.033 ;
     RECT  19.392 48.141 20.376 49.033 ;
     RECT  15.504 48.141 18.264 49.043 ;
     RECT  47.28 47.595 47.304 49.055 ;
     RECT  48.288 49.013 50.52 49.055 ;
     RECT  23.856 47.363 25.08 49.091 ;
     RECT  28.848 48.915 30.264 49.093 ;
     RECT  42.528 48.083 46.008 49.107 ;
     RECT  28.848 49.093 30.36 49.139 ;
     RECT  47.28 49.055 50.52 49.141 ;
     RECT  52.368 48.421 57.72 49.141 ;
     RECT  5.64 49.033 6.888 49.187 ;
     RECT  13.056 48.853 13.704 49.379 ;
     RECT  41.568 49.107 46.008 49.427 ;
     RECT  21.648 48.997 22.152 49.439 ;
     RECT  21.648 49.439 22.824 49.461 ;
     RECT  47.28 49.141 50.664 49.461 ;
     RECT  15.504 49.043 18.024 49.475 ;
     RECT  21.456 49.461 22.824 49.523 ;
     RECT  21.456 49.523 22.152 49.549 ;
     RECT  61.584 48.555 62.856 49.583 ;
     RECT  61.584 49.583 62.904 49.589 ;
     RECT  10.32 48.457 11.544 49.619 ;
     RECT  47.28 49.461 50.712 49.619 ;
     RECT  51.888 49.141 57.72 49.619 ;
     RECT  61.344 49.589 62.904 49.667 ;
     RECT  61.344 49.667 62.76 49.811 ;
     RECT  5.64 49.187 5.952 49.861 ;
     RECT  24.48 49.091 25.08 49.861 ;
     RECT  31.68 48.431 39.096 49.861 ;
     RECT  58.704 48.851 59.952 49.957 ;
     RECT  5.472 49.861 5.952 50.027 ;
     RECT  31.632 49.861 39.096 50.027 ;
     RECT  58.704 49.957 60.072 50.041 ;
     RECT  19.2 49.967 19.224 50.051 ;
     RECT  30 49.139 30.36 50.051 ;
     RECT  7.728 50.005 7.752 50.091 ;
     RECT  24.48 49.861 25.224 50.091 ;
     RECT  24.48 50.091 25.08 50.099 ;
     RECT  20.352 49.033 20.376 50.101 ;
     RECT  61.584 49.811 62.76 50.185 ;
     RECT  13.68 49.379 13.704 50.195 ;
     RECT  31.68 50.027 39.096 50.195 ;
     RECT  42.528 49.427 46.008 50.389 ;
     RECT  47.28 49.619 50.664 50.389 ;
     RECT  61.584 50.185 62.616 50.579 ;
     RECT  52.368 49.619 57.72 50.629 ;
     RECT  58.704 50.041 59.952 50.629 ;
     RECT  21.84 49.549 22.152 50.677 ;
     RECT  26.208 48.515 27.552 50.677 ;
     RECT  28.848 49.139 28.872 50.677 ;
     RECT  52.368 50.629 59.952 50.731 ;
     RECT  15.504 49.475 17.16 50.773 ;
     RECT  10.32 49.619 11.352 50.805 ;
     RECT  31.872 50.195 39.096 50.819 ;
     RECT  9.552 50.805 11.352 50.893 ;
     RECT  32.64 50.819 39.096 50.965 ;
     RECT  42.528 50.389 50.664 51.061 ;
     RECT  42.144 51.061 50.664 51.109 ;
     RECT  42.144 51.109 51.192 51.205 ;
     RECT  61.584 50.579 62.52 51.205 ;
     RECT  21.648 50.677 22.152 51.301 ;
     RECT  32.64 50.965 39.624 51.307 ;
     RECT  41.184 51.205 51.192 51.307 ;
     RECT  21.648 51.301 22.824 51.311 ;
     RECT  30.336 50.051 30.36 51.311 ;
     RECT  50.976 51.307 51.192 51.311 ;
     RECT  52.368 50.731 57.72 51.311 ;
     RECT  61.248 51.205 62.52 51.311 ;
     RECT  19.44 50.101 20.376 51.347 ;
     RECT  26.208 50.677 28.872 51.347 ;
     RECT  5.64 50.027 5.952 51.359 ;
     RECT  21.648 51.311 23.112 51.395 ;
     RECT  26.208 51.347 27.96 51.395 ;
     RECT  30.048 51.311 30.36 51.395 ;
     RECT  5.64 51.359 6.84 51.443 ;
     RECT  19.44 51.347 20.328 51.493 ;
     RECT  18.768 51.493 20.328 51.577 ;
     RECT  50.976 51.311 57.72 51.577 ;
     RECT  5.64 51.443 6.312 51.603 ;
     RECT  24.72 50.099 25.08 51.603 ;
     RECT  26.208 51.395 27.552 51.603 ;
     RECT  5.088 51.603 6.312 51.661 ;
     RECT  7.968 51.573 7.992 51.661 ;
     RECT  41.904 51.307 49.848 51.661 ;
     RECT  19.44 51.577 20.328 51.683 ;
     RECT  5.088 51.661 6.216 51.691 ;
     RECT  19.776 51.683 20.328 51.691 ;
     RECT  31.536 51.603 31.56 51.691 ;
     RECT  61.056 51.311 62.52 51.695 ;
     RECT  61.008 51.695 62.52 51.733 ;
     RECT  61.008 51.733 62.616 51.779 ;
     RECT  57.696 51.577 57.72 51.781 ;
     RECT  58.704 50.731 59.952 51.781 ;
     RECT  61.44 51.779 62.616 51.781 ;
     RECT  15.312 50.773 17.16 51.859 ;
     RECT  13.872 51.859 13.896 51.893 ;
     RECT  15.312 51.859 18.072 51.893 ;
     RECT  57.696 51.781 59.952 51.893 ;
     RECT  61.44 51.781 62.856 51.893 ;
     RECT  10.32 50.893 11.352 51.923 ;
     RECT  13.872 51.893 18.072 51.947 ;
     RECT  20.304 51.691 20.328 51.947 ;
     RECT  41.904 51.661 47.304 51.981 ;
     RECT  40.656 51.381 40.68 51.987 ;
     RECT  50.976 51.577 56.52 52.019 ;
     RECT  61.44 51.893 63 52.019 ;
     RECT  40.416 51.987 40.68 52.075 ;
     RECT  42.768 51.981 47.304 52.139 ;
     RECT  51.168 52.019 56.52 52.163 ;
     RECT  57.696 51.893 60.408 52.211 ;
     RECT  48.288 51.661 49.848 52.259 ;
     RECT  5.64 51.691 6.216 52.403 ;
     RECT  12.816 51.493 12.84 52.405 ;
     RECT  24.72 51.603 27.552 52.469 ;
     RECT  51.696 52.163 56.52 52.489 ;
     RECT  61.44 52.019 62.712 52.489 ;
     RECT  12.816 52.405 13.128 52.499 ;
     RECT  21.648 51.395 22.152 52.499 ;
     RECT  10.752 51.923 11.352 52.547 ;
     RECT  32.64 51.307 38.856 52.597 ;
     RECT  39.888 52.405 39.912 52.597 ;
     RECT  32.64 52.597 39.912 52.691 ;
     RECT  18.768 52.693 18.792 52.779 ;
     RECT  32.64 52.691 38.664 52.787 ;
     RECT  21.84 52.499 22.152 52.819 ;
     RECT  32.64 52.787 38.616 52.819 ;
     RECT  13.104 52.499 13.128 52.931 ;
     RECT  14.832 51.947 17.16 52.947 ;
     RECT  21.84 52.819 23.064 52.947 ;
     RECT  57.696 52.211 59.952 52.971 ;
     RECT  14.208 52.947 17.16 52.979 ;
     RECT  11.04 52.547 11.352 52.981 ;
     RECT  52.464 52.489 56.52 52.981 ;
     RECT  57.696 52.971 57.72 52.981 ;
     RECT  15.504 52.979 17.16 53.027 ;
     RECT  32.256 52.819 38.616 53.029 ;
     RECT  8.4 52.947 8.424 53.035 ;
     RECT  14.208 52.979 14.232 53.035 ;
     RECT  61.44 52.489 62.376 53.039 ;
     RECT  24.432 52.469 27.552 53.075 ;
     RECT  11.04 52.981 11.448 53.099 ;
     RECT  8.496 53.039 8.52 53.123 ;
     RECT  21.84 52.947 23.256 53.123 ;
     RECT  60.96 53.039 62.376 53.123 ;
     RECT  30.336 51.395 30.36 53.173 ;
     RECT  58.704 52.971 59.952 53.221 ;
     RECT  26.304 53.075 27.552 53.231 ;
     RECT  29.04 53.173 29.064 53.231 ;
     RECT  20.256 52.725 20.28 53.267 ;
     RECT  30.336 53.173 30.792 53.267 ;
     RECT  39.936 53.173 39.96 53.267 ;
     RECT  61.584 53.123 62.376 53.267 ;
     RECT  58.704 53.221 60.456 53.305 ;
     RECT  26.304 53.231 29.064 53.315 ;
     RECT  29.04 53.315 29.064 53.355 ;
     RECT  58.704 53.305 59.952 53.363 ;
     RECT  40.992 52.371 41.256 53.471 ;
     RECT  23.376 53.365 23.4 53.493 ;
     RECT  24.432 53.075 24.744 53.493 ;
     RECT  39.984 53.471 41.256 53.507 ;
     RECT  21.84 53.123 22.152 53.557 ;
     RECT  30.336 53.267 30.6 53.557 ;
     RECT  23.376 53.493 24.744 53.581 ;
     RECT  31.776 53.029 38.616 53.581 ;
     RECT  52.464 52.981 57.72 53.581 ;
     RECT  23.376 53.581 23.496 53.603 ;
     RECT  5.64 52.403 5.952 53.685 ;
     RECT  48.432 52.259 49.848 53.685 ;
     RECT  51.312 53.471 51.336 53.685 ;
     RECT  52.464 53.581 56.52 53.685 ;
     RECT  5.64 53.685 6.936 53.795 ;
     RECT  51.312 53.685 56.52 53.843 ;
     RECT  47.232 52.139 47.304 53.855 ;
     RECT  48.432 53.685 50.136 53.855 ;
     RECT  39.984 53.507 41.112 53.931 ;
     RECT  47.232 53.855 50.136 53.931 ;
     RECT  29.616 53.557 30.6 53.995 ;
     RECT  52.512 53.843 56.52 53.995 ;
     RECT  31.872 53.581 38.616 54.047 ;
     RECT  47.232 53.931 49.608 54.059 ;
     RECT  41.088 53.931 41.112 54.123 ;
     RECT  31.872 54.047 38.76 54.131 ;
     RECT  42.768 52.139 46.008 54.133 ;
     RECT  47.232 54.059 47.304 54.133 ;
     RECT  42.768 54.133 47.304 54.163 ;
     RECT  52.608 53.995 56.52 54.179 ;
     RECT  42.432 54.163 47.304 54.227 ;
     RECT  42.432 54.227 46.2 54.251 ;
     RECT  31.872 54.131 38.616 54.371 ;
     RECT  39.984 53.931 40.008 54.371 ;
     RECT  18.768 54.037 18.792 54.373 ;
     RECT  50.88 54.005 51.096 54.379 ;
     RECT  11.04 53.099 11.352 54.421 ;
     RECT  8.16 54.037 8.184 54.453 ;
     RECT  12.96 54.229 12.984 54.483 ;
     RECT  17.904 54.373 18.792 54.515 ;
     RECT  8.112 54.453 8.184 54.563 ;
     RECT  12.96 54.483 13.944 54.571 ;
     RECT  23.472 53.603 23.496 54.571 ;
     RECT  58.848 53.363 59.952 54.613 ;
     RECT  18.72 54.515 18.792 54.623 ;
     RECT  20.016 53.941 20.04 54.623 ;
     RECT  57.696 53.581 57.72 54.623 ;
     RECT  58.848 54.613 60.504 54.623 ;
     RECT  9.408 54.581 9.432 54.669 ;
     RECT  57.696 54.623 60.504 54.699 ;
     RECT  12.96 54.571 12.984 54.707 ;
     RECT  18.72 54.623 20.04 54.707 ;
     RECT  32.496 54.371 38.616 54.707 ;
     RECT  21.648 53.557 22.152 54.709 ;
     RECT  26.304 53.315 27.72 54.709 ;
     RECT  61.584 53.267 61.608 54.709 ;
     RECT  8.16 54.563 8.184 54.755 ;
     RECT  19.92 54.707 20.04 54.763 ;
     RECT  21.024 54.709 22.152 54.767 ;
     RECT  21.024 54.767 23.208 54.773 ;
     RECT  20.352 54.773 23.208 54.803 ;
     RECT  25.776 54.709 27.72 54.803 ;
     RECT  48.72 54.059 49.608 54.803 ;
     RECT  50.88 54.379 50.904 54.803 ;
     RECT  61.152 54.709 61.608 54.803 ;
     RECT  21.744 54.803 23.208 54.851 ;
     RECT  29.616 53.995 30.36 54.851 ;
     RECT  47.232 54.227 47.304 54.851 ;
     RECT  32.496 54.707 38.52 54.861 ;
     RECT  20.352 54.803 20.568 54.899 ;
     RECT  26.208 54.803 27.72 54.899 ;
     RECT  42.768 54.251 46.2 54.899 ;
     RECT  57.696 54.699 59.952 54.925 ;
     RECT  48.84 54.803 49.608 55.187 ;
     RECT  18.72 54.707 18.744 55.283 ;
     RECT  26.304 54.899 27.72 55.283 ;
     RECT  39.648 55.343 39.672 55.349 ;
     RECT  9.6 55.285 9.624 55.413 ;
     RECT  10.848 54.421 11.352 55.413 ;
     RECT  47.28 54.851 47.304 55.413 ;
     RECT  39.648 55.349 40.536 55.427 ;
     RECT  40.416 55.427 40.536 55.437 ;
     RECT  40.416 55.437 40.44 55.475 ;
     RECT  23.184 54.851 23.208 55.501 ;
     RECT  47.28 55.413 47.4 55.523 ;
     RECT  9.6 55.413 11.352 55.667 ;
     RECT  42.768 54.899 46.008 55.907 ;
     RECT  15.504 53.027 16.752 55.919 ;
     RECT  32.544 54.861 38.52 55.919 ;
     RECT  9.6 55.667 9.624 55.955 ;
     RECT  10.848 55.667 11.352 55.979 ;
     RECT  19.536 55.891 19.56 55.979 ;
     RECT  28.8 55.349 28.824 55.979 ;
     RECT  8.496 55.919 8.52 56.003 ;
     RECT  15.504 55.919 17.064 56.003 ;
     RECT  23.52 55.919 23.544 56.003 ;
     RECT  30.24 54.851 30.36 56.005 ;
     RECT  18.24 55.925 18.264 56.013 ;
     RECT  45.984 55.907 46.008 56.101 ;
     RECT  47.28 55.523 47.304 56.101 ;
     RECT  10.896 55.979 11.352 56.181 ;
     RECT  10.896 56.181 11.784 56.269 ;
     RECT  29.808 56.005 30.36 56.341 ;
     RECT  51.216 55.525 51.24 56.341 ;
     RECT  61.584 54.803 61.608 56.341 ;
     RECT  60.96 56.341 61.608 56.373 ;
     RECT  26.304 55.283 27.552 56.437 ;
     RECT  29.808 56.341 30.744 56.437 ;
     RECT  31.968 55.919 38.52 56.437 ;
     RECT  41.616 55.525 41.64 56.437 ;
     RECT  42.768 55.907 45 56.437 ;
     RECT  52.608 54.179 55.704 56.437 ;
     RECT  57.696 54.925 57.72 56.437 ;
     RECT  58.848 54.925 59.952 56.437 ;
     RECT  60.96 56.373 61.704 56.437 ;
     RECT  26.304 56.437 28.248 56.483 ;
     RECT  58.848 56.437 61.704 56.483 ;
     RECT  29.52 56.437 38.52 56.491 ;
     RECT  59.04 56.483 61.704 56.521 ;
     RECT  13.056 56.437 13.08 56.531 ;
     RECT  41.616 56.437 45 56.531 ;
     RECT  61.584 56.521 61.704 56.531 ;
     RECT  9.504 56.629 9.528 56.723 ;
     RECT  29.52 56.491 30.36 56.723 ;
     RECT  52.608 56.437 57.72 56.747 ;
     RECT  48.84 55.187 49.152 56.821 ;
     RECT  24.72 53.581 24.744 56.869 ;
     RECT  15.504 56.003 16.752 56.917 ;
     RECT  41.616 56.531 41.64 56.949 ;
     RECT  42.768 56.531 45 56.949 ;
     RECT  45.984 56.101 47.304 56.949 ;
     RECT  48.672 56.821 49.152 56.963 ;
     RECT  14.832 56.917 16.752 56.979 ;
     RECT  31.344 56.491 38.52 57.003 ;
     RECT  39.888 56.677 39.912 57.003 ;
     RECT  40.992 56.949 41.64 57.003 ;
     RECT  42.768 56.949 47.304 57.003 ;
     RECT  10.896 56.269 11.352 57.013 ;
     RECT  14.832 56.979 17.736 57.013 ;
     RECT  32.64 57.003 38.52 57.013 ;
     RECT  40.992 57.003 41.016 57.013 ;
     RECT  51.216 56.341 51.48 57.013 ;
     RECT  52.608 56.747 56.28 57.013 ;
     RECT  62.784 56.885 62.808 57.013 ;
     RECT  14.208 57.013 17.736 57.059 ;
     RECT  32.64 57.013 38.76 57.059 ;
     RECT  42.768 57.003 46.008 57.059 ;
     RECT  14.208 57.059 14.856 57.067 ;
     RECT  15.936 57.059 17.736 57.067 ;
     RECT  42.768 57.059 44.904 57.067 ;
     RECT  51.216 57.013 56.28 57.067 ;
     RECT  15.936 57.067 16.752 57.097 ;
     RECT  10.8 57.013 11.352 57.107 ;
     RECT  14.208 57.067 14.232 57.107 ;
     RECT  51.888 57.067 56.28 57.107 ;
     RECT  62.688 57.013 62.808 57.107 ;
     RECT  40.896 57.013 41.016 57.131 ;
     RECT  52.416 57.107 55.704 57.299 ;
     RECT  21.744 54.851 22.152 57.301 ;
     RECT  11.04 57.107 11.352 57.445 ;
     RECT  24.72 56.869 25.464 57.445 ;
     RECT  42.768 57.067 44.616 57.503 ;
     RECT  19.728 57.427 19.752 57.515 ;
     RECT  50.448 57.171 50.712 57.525 ;
     RECT  59.04 56.521 59.952 57.541 ;
     RECT  29.712 56.723 30.36 57.555 ;
     RECT  31.344 57.003 31.608 57.555 ;
     RECT  11.04 57.445 11.832 57.579 ;
     RECT  42.144 57.503 44.616 57.587 ;
     RECT  58.8 57.541 59.952 57.589 ;
     RECT  61.584 56.531 61.608 57.635 ;
     RECT  26.688 56.483 28.248 57.643 ;
     RECT  26.784 57.643 28.248 57.673 ;
     RECT  29.712 57.555 31.608 57.673 ;
     RECT  62.64 57.589 62.664 57.683 ;
     RECT  24 57.445 25.464 57.685 ;
     RECT  13.488 57.653 13.512 57.741 ;
     RECT  27.072 57.673 28.248 57.779 ;
     RECT  40.416 57.781 40.44 57.875 ;
     RECT  23.472 57.685 25.464 58.021 ;
     RECT  37.92 57.059 38.76 58.027 ;
     RECT  38.04 58.027 38.76 58.069 ;
     RECT  50.256 57.525 50.712 58.069 ;
     RECT  52.416 57.299 52.44 58.091 ;
     RECT  31.584 57.673 31.608 58.115 ;
     RECT  32.64 57.059 33.096 58.117 ;
     RECT  34.08 57.059 36.936 58.117 ;
     RECT  58.704 57.589 59.952 58.117 ;
     RECT  9.984 58.037 10.008 58.125 ;
     RECT  23.232 58.021 25.464 58.155 ;
     RECT  38.04 58.069 39.288 58.155 ;
     RECT  50.256 58.069 51.384 58.155 ;
     RECT  32.64 58.117 36.936 58.163 ;
     RECT  53.808 57.299 55.704 58.163 ;
     RECT  47.232 57.003 47.304 58.165 ;
     RECT  48.72 56.963 49.152 58.165 ;
     RECT  47.04 58.165 49.152 58.259 ;
     RECT  62.832 58.165 62.856 58.259 ;
     RECT  16.44 57.097 16.752 58.293 ;
     RECT  57.696 56.747 57.72 58.357 ;
     RECT  16.44 58.293 17.496 58.381 ;
     RECT  35.136 58.163 35.4 58.403 ;
     RECT  57.6 58.357 57.72 58.421 ;
     RECT  58.704 58.117 60.072 58.421 ;
     RECT  42.72 57.587 44.616 58.489 ;
     RECT  23.472 58.155 25.464 58.501 ;
     RECT  27.12 57.779 28.248 58.547 ;
     RECT  57.6 58.421 60.072 58.595 ;
     RECT  23.472 58.501 25.752 58.603 ;
     RECT  53.808 58.163 55.416 58.645 ;
     RECT  27.24 58.547 28.248 58.677 ;
     RECT  50.256 58.155 50.712 58.681 ;
     RECT  29.712 57.673 29.976 58.731 ;
     RECT  57.6 58.595 59.952 58.731 ;
     RECT  32.64 58.163 34.104 58.741 ;
     RECT  27.24 58.677 28.344 58.835 ;
     RECT  29.904 58.731 29.976 58.835 ;
     RECT  23.472 58.603 25.176 58.931 ;
     RECT  61.488 58.963 61.512 59.051 ;
     RECT  32.544 58.741 34.104 59.077 ;
     RECT  48.84 58.259 49.152 59.077 ;
     RECT  50.256 58.681 50.376 59.077 ;
     RECT  21.648 57.301 22.152 59.125 ;
     RECT  23.472 58.931 23.592 59.125 ;
     RECT  31.968 59.077 34.104 59.179 ;
     RECT  48.84 59.077 50.376 59.179 ;
     RECT  21.072 59.125 23.592 59.219 ;
     RECT  42.768 58.489 44.616 59.221 ;
     RECT  45.984 57.059 46.008 59.221 ;
     RECT  41.28 58.597 41.304 59.231 ;
     RECT  32.544 59.179 34.104 59.267 ;
     RECT  16.44 58.381 17.448 59.307 ;
     RECT  28.848 59.231 28.872 59.315 ;
     RECT  40.992 59.231 41.304 59.315 ;
     RECT  41.28 59.315 41.304 59.317 ;
     RECT  36.384 58.163 36.936 59.381 ;
     RECT  38.04 58.155 38.856 59.381 ;
     RECT  41.28 59.317 41.448 59.381 ;
     RECT  50.256 59.179 50.376 59.411 ;
     RECT  21.072 59.219 23.496 59.459 ;
     RECT  29.952 58.835 29.976 59.459 ;
     RECT  50.256 59.411 50.28 59.459 ;
     RECT  19.344 59.423 19.368 59.507 ;
     RECT  21.072 59.459 23.4 59.507 ;
     RECT  47.28 58.259 47.304 59.507 ;
     RECT  41.28 59.381 41.592 59.605 ;
     RECT  14.256 59.539 14.28 59.627 ;
     RECT  12.528 59.567 12.552 59.651 ;
     RECT  57.696 58.731 59.952 59.667 ;
     RECT  52.32 59.605 52.344 59.691 ;
     RECT  53.52 58.645 55.416 59.691 ;
     RECT  56.4 58.741 56.424 59.691 ;
     RECT  21.072 59.507 22.824 59.699 ;
     RECT  41.28 59.605 41.784 59.699 ;
     RECT  36.384 59.381 38.856 59.701 ;
     RECT  21.072 59.699 22.248 59.731 ;
     RECT  57.696 59.667 60.216 59.755 ;
     RECT  27.24 58.835 27.552 59.759 ;
     RECT  24.72 58.931 25.176 59.765 ;
     RECT  36.384 59.701 39.624 59.785 ;
     RECT  42.768 59.221 46.008 59.797 ;
     RECT  57.696 59.755 59.952 59.807 ;
     RECT  18.384 59.731 18.408 59.819 ;
     RECT  20.592 59.731 22.248 59.819 ;
     RECT  37.728 59.785 39.624 59.819 ;
     RECT  24.72 59.765 25.368 59.853 ;
     RECT  24.72 59.853 24.744 59.891 ;
     RECT  42.768 59.797 46.92 59.891 ;
     RECT  54.24 59.691 55.416 59.891 ;
     RECT  56.784 59.807 59.952 59.891 ;
     RECT  61.872 59.807 61.896 59.891 ;
     RECT  42.768 59.891 45.192 59.893 ;
     RECT  16.44 59.307 17.208 59.941 ;
     RECT  37.92 59.819 39.624 59.987 ;
     RECT  26.88 59.759 27.552 59.989 ;
     RECT  15.936 59.941 17.208 60.025 ;
     RECT  16.32 60.025 17.208 60.045 ;
     RECT  26.064 59.989 27.552 60.075 ;
     RECT  29.088 59.845 29.4 60.075 ;
     RECT  32.544 59.267 33.096 60.083 ;
     RECT  41.904 59.893 45.192 60.139 ;
     RECT  16.32 60.045 16.752 60.275 ;
     RECT  21.84 59.819 22.248 60.275 ;
     RECT  35.184 58.403 35.4 60.277 ;
     RECT  36.384 59.785 36.744 60.277 ;
     RECT  48.84 59.179 49.152 60.277 ;
     RECT  37.92 59.987 38.472 60.323 ;
     RECT  54.24 59.891 54.648 60.323 ;
     RECT  35.184 60.277 36.744 60.331 ;
     RECT  46.752 59.891 46.92 60.331 ;
     RECT  55.776 60.277 55.8 60.419 ;
     RECT  35.184 60.331 36.408 60.467 ;
     RECT  50.16 60.277 50.184 60.467 ;
     RECT  53.136 60.277 53.16 60.467 ;
     RECT  57.696 59.891 59.952 60.467 ;
     RECT  29.376 60.075 29.4 60.515 ;
     RECT  34.08 59.267 34.104 60.563 ;
     RECT  37.92 60.323 38.352 60.563 ;
     RECT  61.44 60.533 61.464 60.621 ;
     RECT  51.792 60.213 51.816 60.767 ;
     RECT  54.24 60.323 54.552 60.767 ;
     RECT  18.24 60.767 18.264 60.851 ;
     RECT  26.304 60.075 27.552 60.851 ;
     RECT  42.336 60.139 45.192 60.853 ;
     RECT  42.336 60.853 45.528 61.043 ;
     RECT  54.144 60.767 54.552 61.093 ;
     RECT  51.552 60.767 51.816 61.189 ;
     RECT  56.976 60.853 57 61.237 ;
     RECT  48.72 60.277 49.152 61.285 ;
     RECT  46.752 60.331 46.776 61.331 ;
     RECT  32.64 60.083 33.096 61.333 ;
     RECT  31.536 61.237 31.56 61.365 ;
     RECT  32.64 61.333 33.672 61.365 ;
     RECT  48.48 61.285 49.152 61.381 ;
     RECT  31.536 61.365 33.672 61.395 ;
     RECT  38.04 60.563 38.352 61.395 ;
     RECT  51.552 61.189 52.392 61.419 ;
     RECT  56.592 61.237 57 61.419 ;
     RECT  31.392 61.395 33.672 61.475 ;
     RECT  38.04 61.395 39.24 61.477 ;
     RECT  31.392 61.475 31.56 61.483 ;
     RECT  58.128 60.467 59.952 61.523 ;
     RECT  31.536 61.483 31.56 61.547 ;
     RECT  54.048 61.093 54.552 61.547 ;
     RECT  38.04 61.477 39.336 61.561 ;
     RECT  19.536 60.181 19.56 61.571 ;
     RECT  25.2 61.477 25.224 61.611 ;
     RECT  28.752 61.477 28.776 61.611 ;
     RECT  23.904 61.535 23.928 61.619 ;
     RECT  42.336 61.043 45 61.619 ;
     RECT  51.504 61.535 51.528 61.619 ;
     RECT  44.976 61.619 45 61.705 ;
     RECT  48.192 61.381 49.152 61.765 ;
     RECT  58.128 61.523 58.152 61.813 ;
     RECT  57.408 61.813 58.152 61.867 ;
     RECT  57.408 61.867 57.432 61.907 ;
     RECT  27.12 60.851 27.552 62.005 ;
     RECT  46.368 61.587 46.392 62.111 ;
     RECT  35.376 60.467 36.408 62.149 ;
     RECT  38.04 61.561 38.352 62.149 ;
     RECT  28.8 62.111 28.824 62.195 ;
     RECT  32.64 61.475 33.672 62.195 ;
     RECT  35.376 62.149 38.352 62.195 ;
     RECT  43.248 61.619 43.752 62.195 ;
     RECT  26.784 62.005 27.552 62.291 ;
     RECT  59.64 61.523 59.952 62.547 ;
     RECT  45.984 62.111 46.392 62.581 ;
     RECT  54.24 61.547 54.552 62.581 ;
     RECT  58.992 62.547 59.952 62.581 ;
     RECT  58.992 62.581 60.456 62.635 ;
     RECT  43.296 62.195 43.752 62.675 ;
     RECT  23.952 62.053 23.976 62.723 ;
     RECT  35.376 62.195 36.12 62.723 ;
     RECT  53.856 62.581 54.552 62.763 ;
     RECT  30.144 62.687 30.168 62.771 ;
     RECT  51.312 62.687 51.336 62.771 ;
     RECT  59.64 62.635 60.456 62.771 ;
     RECT  41.856 62.709 41.88 62.797 ;
     RECT  45.984 62.581 46.968 62.819 ;
     RECT  50.208 62.341 50.232 62.901 ;
     RECT  52.464 62.901 52.488 62.989 ;
     RECT  36.096 62.723 36.12 63.011 ;
     RECT  45.792 62.821 45.816 63.023 ;
     RECT  45.552 63.023 45.816 63.107 ;
     RECT  46.8 62.819 46.968 63.251 ;
     RECT  43.44 62.675 43.752 63.263 ;
     RECT  54.24 62.763 54.552 63.263 ;
     RECT  50.208 62.901 51.144 63.275 ;
     RECT  37.344 62.195 38.352 63.299 ;
     RECT  46.944 63.251 46.968 63.299 ;
     RECT  47.952 61.765 49.152 63.299 ;
     RECT  61.536 61.477 61.56 63.299 ;
     RECT  45.792 63.107 45.816 63.339 ;
     RECT  56.64 63.205 56.664 63.339 ;
     RECT  43.44 63.263 44.472 63.347 ;
     RECT  54.24 63.263 55.272 63.347 ;
     RECT  50.496 63.275 51.144 63.491 ;
     RECT  0.24 46.827 0.552 63.743 ;
     RECT  5.64 53.795 5.952 63.743 ;
     RECT  11.04 57.579 11.352 63.743 ;
     RECT  16.44 60.275 16.752 63.743 ;
     RECT  21.84 60.275 22.152 63.743 ;
     RECT  27.24 62.291 27.552 63.743 ;
     RECT  32.64 62.195 32.952 63.743 ;
     RECT  38.04 63.299 38.352 63.743 ;
     RECT  43.44 63.347 43.752 63.743 ;
     RECT  48.84 63.299 49.152 63.743 ;
     RECT  54.24 63.347 54.552 63.743 ;
     RECT  59.64 62.771 59.952 63.743 ;
     RECT  51.12 63.491 51.144 63.779 ;
     RECT  0.432 63.743 0.552 64.013 ;
     RECT  5.832 63.743 5.952 64.013 ;
     RECT  11.232 63.743 11.352 64.013 ;
     RECT  16.632 63.743 16.752 64.013 ;
     RECT  22.032 63.743 22.152 64.013 ;
     RECT  27.432 63.743 27.552 64.013 ;
     RECT  32.832 63.743 32.952 64.013 ;
     RECT  38.232 63.743 38.352 64.013 ;
     RECT  43.632 63.743 43.752 64.013 ;
     RECT  49.032 63.743 49.152 64.013 ;
     RECT  54.432 63.743 54.552 64.013 ;
     RECT  59.832 63.743 59.952 64.013 ;
    LAYER M6 ;
     RECT  0 6.396 0.133 7.26 ;
     RECT  0 33.396 0.133 34.26 ;
     RECT  0.133 6.144 0.299 7.712 ;
     RECT  0.133 35.904 0.299 35.936 ;
     RECT  0 38.796 0.629 39.66 ;
     RECT  0.613 41.6 0.629 41.632 ;
     RECT  0 11.796 0.661 12.66 ;
     RECT  0 44.196 0.661 45.06 ;
     RECT  0.629 38.796 0.683 41.632 ;
     RECT  0 0.996 0.853 1.86 ;
     RECT  0 22.596 0.901 23.46 ;
     RECT  0.853 0.996 1.093 2.144 ;
     RECT  0.901 22.596 1.093 24.48 ;
     RECT  0.299 6.272 1.139 7.26 ;
     RECT  0 17.196 1.333 18.06 ;
     RECT  1.333 17.196 1.573 18.784 ;
     RECT  0.133 20.288 1.573 20.32 ;
     RECT  0 27.996 1.669 28.86 ;
     RECT  0.661 11.264 1.859 12.66 ;
     RECT  1.573 17.196 2.003 20.32 ;
     RECT  2.003 17.196 2.149 20.064 ;
     RECT  1.093 22.08 2.245 24.48 ;
     RECT  1.669 27.996 2.274 29.024 ;
     RECT  2.245 30.848 2.274 30.88 ;
     RECT  2.274 27.996 2.293 30.88 ;
     RECT  0.661 43.776 2.293 45.06 ;
     RECT  1.093 46.784 2.293 46.816 ;
     RECT  2.293 27.996 2.347 31.008 ;
     RECT  2.293 43.776 2.387 46.816 ;
     RECT  1.859 11.796 2.414 12.66 ;
     RECT  2.414 11.796 2.483 12.768 ;
     RECT  0.683 38.796 2.606 40.608 ;
     RECT  2.606 38.796 2.613 41.632 ;
     RECT  2.347 30.144 2.629 31.008 ;
     RECT  1.093 0.996 2.677 3.232 ;
     RECT  2.245 4.544 2.677 4.576 ;
     RECT  2.245 21.376 2.677 25.184 ;
     RECT  2.421 9.792 2.821 9.824 ;
     RECT  0.133 33.396 2.821 34.4 ;
     RECT  2.613 38.592 2.869 41.632 ;
     RECT  2.629 30.144 3.397 31.84 ;
     RECT  2.821 33.396 3.397 34.784 ;
     RECT  2.387 43.776 3.397 45.06 ;
     RECT  2.677 0.996 3.435 4.576 ;
     RECT  1.139 6.396 3.493 7.26 ;
     RECT  3.435 0.996 3.635 3.36 ;
     RECT  2.805 36.608 3.701 36.64 ;
     RECT  2.869 38.336 3.701 41.632 ;
     RECT  3.701 36.608 3.893 36.832 ;
     RECT  2.677 21.376 3.925 26.144 ;
     RECT  2.347 27.996 3.925 28.86 ;
     RECT  3.397 30.144 3.925 34.784 ;
     RECT  3.893 36.608 3.925 36.896 ;
     RECT  3.701 38.208 3.925 41.632 ;
     RECT  2.869 14.4 4.085 14.432 ;
     RECT  2.149 16.448 4.085 20.064 ;
     RECT  4.085 14.4 4.139 20.064 ;
     RECT  2.821 9.792 4.165 10.336 ;
     RECT  2.483 11.796 4.165 12.66 ;
     RECT  3.925 36.608 4.309 41.632 ;
     RECT  3.397 43.264 4.309 45.06 ;
     RECT  3.925 27.996 4.595 34.784 ;
     RECT  4.139 14.4 4.597 15.648 ;
     RECT  4.165 9.792 4.787 12.66 ;
     RECT  3.493 6.144 4.837 7.26 ;
     RECT  4.837 6.144 4.907 7.84 ;
     RECT  4.139 17.024 4.917 20.064 ;
     RECT  3.925 21.376 4.917 26.528 ;
     RECT  3.635 0.996 4.981 1.86 ;
     RECT  4.595 32.832 5.029 34.784 ;
     RECT  4.309 36.608 5.029 45.06 ;
     RECT  4.981 0.996 5.077 2.016 ;
     RECT  3.635 3.328 5.077 3.36 ;
     RECT  0 49.596 5.077 50.46 ;
     RECT  4.595 27.996 5.123 31.136 ;
     RECT  4.597 14.208 5.154 15.648 ;
     RECT  5.077 0.996 5.171 3.36 ;
     RECT  5.029 32.832 5.363 45.06 ;
     RECT  5.154 13.952 5.509 15.648 ;
     RECT  4.917 17.024 5.509 26.528 ;
     RECT  5.509 13.952 6.202 26.528 ;
     RECT  5.077 48.32 6.227 51.68 ;
     RECT  5.077 4.672 6.229 4.704 ;
     RECT  4.907 6.144 6.229 7.26 ;
     RECT  4.787 11.796 6.229 12.66 ;
     RECT  6.202 13.952 6.229 15.456 ;
     RECT  6.202 17.088 6.229 26.528 ;
     RECT  5.123 27.996 6.229 31.008 ;
     RECT  5.363 32.832 6.323 40.544 ;
     RECT  5.363 42.048 6.323 45.06 ;
     RECT  6.227 48.32 6.515 51.616 ;
     RECT  6.229 17.088 6.757 31.008 ;
     RECT  2.387 46.784 6.851 46.816 ;
     RECT  6.757 17.088 6.899 31.392 ;
     RECT  5.171 0.996 6.901 2.72 ;
     RECT  0 54.996 6.901 55.86 ;
     RECT  6.229 4.672 6.997 7.26 ;
     RECT  6.229 11.796 7.275 15.456 ;
     RECT  4.787 9.792 7.381 9.824 ;
     RECT  7.275 11.796 7.381 14.816 ;
     RECT  6.323 43.2 7.381 45.06 ;
     RECT  6.515 48.96 7.475 51.616 ;
     RECT  6.899 17.196 7.477 31.392 ;
     RECT  6.323 32.832 7.477 39.904 ;
     RECT  6.901 0.832 7.525 2.72 ;
     RECT  6.997 4.672 7.525 7.392 ;
     RECT  7.525 0.832 7.861 7.392 ;
     RECT  7.861 41.408 7.909 41.44 ;
     RECT  7.381 9.792 7.915 14.816 ;
     RECT  7.909 41.408 7.979 41.568 ;
     RECT  7.861 0.832 8.003 8.352 ;
     RECT  7.475 49.596 8.003 51.616 ;
     RECT  7.477 17.196 8.053 39.904 ;
     RECT  8.003 0.832 8.149 3.808 ;
     RECT  7.915 10.688 8.291 14.816 ;
     RECT  6.901 53.696 8.309 55.86 ;
     RECT  8.309 52.992 8.363 55.86 ;
     RECT  8.363 52.992 8.435 53.088 ;
     RECT  8.003 5.248 8.483 8.352 ;
     RECT  8.363 54.592 8.485 55.86 ;
     RECT  7.381 43.2 8.565 45.216 ;
     RECT  6.901 46.976 8.565 47.008 ;
     RECT  8.565 43.2 8.619 47.008 ;
     RECT  8.053 17.196 8.725 41.12 ;
     RECT  8.725 16.704 8.811 41.12 ;
     RECT  8.619 43.2 9.107 46.432 ;
     RECT  8.485 54.592 9.443 55.968 ;
     RECT  8.149 0.768 9.493 3.808 ;
     RECT  9.443 54.996 9.493 55.968 ;
     RECT  8.483 5.888 9.637 8.352 ;
     RECT  8.291 10.688 9.637 14.56 ;
     RECT  9.954 58.048 10.027 58.08 ;
     RECT  9.493 0.768 10.213 4.064 ;
     RECT  10.213 0.192 10.261 4.064 ;
     RECT  9.637 5.888 10.261 14.56 ;
     RECT  10.261 0.192 10.347 14.56 ;
     RECT  9.107 43.2 10.485 45.216 ;
     RECT  10.485 43.2 10.549 45.664 ;
     RECT  8.811 17.196 10.741 41.12 ;
     RECT  10.549 43.2 10.741 45.856 ;
     RECT  8.003 49.596 10.741 51.424 ;
     RECT  8.435 53.056 10.741 53.088 ;
     RECT  9.493 54.996 10.789 56.672 ;
     RECT  10.347 5.888 10.859 14.56 ;
     RECT  10.741 17.196 10.923 45.856 ;
     RECT  9.973 48.256 10.933 48.288 ;
     RECT  10.741 49.596 10.933 53.088 ;
     RECT  10.933 48.256 11.307 53.088 ;
     RECT  10.789 54.996 11.371 57.056 ;
     RECT  11.307 48.256 11.459 50.46 ;
     RECT  11.307 51.904 11.459 53.088 ;
     RECT  10.923 17.196 11.509 42.464 ;
     RECT  10.923 44.196 11.797 45.856 ;
     RECT  11.509 17.024 11.843 42.464 ;
     RECT  10.859 10.688 11.941 14.56 ;
     RECT  11.797 44.196 12.021 46.176 ;
     RECT  10.859 5.888 12.035 9.184 ;
     RECT  11.843 41.6 12.035 42.464 ;
     RECT  11.941 10.688 12.277 14.688 ;
     RECT  12.277 10.688 12.469 14.816 ;
     RECT  11.843 17.024 12.469 40.032 ;
     RECT  0 60.396 12.517 61.26 ;
     RECT  12.469 10.688 12.538 40.032 ;
     RECT  12.035 41.6 12.563 41.824 ;
     RECT  12.538 10.688 12.782 14.816 ;
     RECT  12.021 44.196 12.917 47.008 ;
     RECT  12.917 43.84 12.981 47.008 ;
     RECT  11.371 54.996 13.045 56.224 ;
     RECT  11.797 57.536 13.045 57.568 ;
     RECT  12.981 43.712 13.054 47.008 ;
     RECT  12.035 5.888 13.093 8.48 ;
     RECT  13.045 54.996 13.109 57.568 ;
     RECT  13.109 54.996 13.523 57.696 ;
     RECT  11.459 48.384 13.715 50.46 ;
     RECT  13.523 54.996 13.877 57.056 ;
     RECT  13.877 54.528 13.955 57.056 ;
     RECT  13.093 5.76 13.986 8.48 ;
     RECT  12.782 10.304 13.986 14.816 ;
     RECT  14.101 42.176 14.187 42.208 ;
     RECT  12.538 17.196 14.197 40.032 ;
     RECT  11.459 51.904 14.197 51.936 ;
     RECT  13.986 5.76 14.266 14.816 ;
     RECT  14.266 10.368 14.291 14.816 ;
     RECT  12.517 59.584 14.291 61.26 ;
     RECT  10.347 0.192 14.821 4.192 ;
     RECT  13.054 44.196 14.867 47.008 ;
     RECT  14.291 10.368 14.915 13.792 ;
     RECT  14.266 5.76 15.019 9.056 ;
     RECT  14.197 16.192 15.397 40.032 ;
     RECT  14.291 60.396 15.925 61.26 ;
     RECT  13.715 49.596 15.973 50.46 ;
     RECT  14.197 51.904 15.973 53.024 ;
     RECT  15.397 15.424 16.238 40.032 ;
     RECT  15.925 41.472 16.238 41.504 ;
     RECT  16.238 15.424 16.307 41.504 ;
     RECT  14.915 10.432 16.309 13.792 ;
     RECT  14.867 44.196 16.309 45.728 ;
     RECT  16.309 43.904 16.427 45.728 ;
     RECT  14.821 0.064 16.837 4.192 ;
     RECT  15.019 5.76 16.837 8.48 ;
     RECT  16.309 10.432 16.933 14.112 ;
     RECT  16.307 15.424 16.933 40.032 ;
     RECT  16.933 10.432 16.981 40.032 ;
     RECT  15.973 49.596 17.123 53.024 ;
     RECT  15.925 59.968 17.173 61.26 ;
     RECT  15.925 47.296 17.365 47.328 ;
     RECT  17.173 59.776 17.413 61.26 ;
     RECT  13.955 54.996 17.442 57.056 ;
     RECT  17.413 59.264 17.442 61.26 ;
     RECT  17.442 54.996 17.515 61.26 ;
     RECT  17.515 59.264 17.643 61.26 ;
     RECT  17.515 54.996 17.747 57.056 ;
     RECT  16.427 44.196 17.893 45.728 ;
     RECT  17.365 47.296 17.893 48.096 ;
     RECT  16.307 41.472 17.909 41.504 ;
     RECT  16.981 10.304 17.941 40.032 ;
     RECT  17.909 41.408 17.941 41.504 ;
     RECT  17.893 44.196 18.101 48.096 ;
     RECT  17.123 49.596 18.101 50.46 ;
     RECT  17.941 10.304 18.133 41.504 ;
     RECT  18.101 44.196 18.325 50.46 ;
     RECT  17.747 54.996 18.709 55.968 ;
     RECT  18.325 44.032 18.757 50.46 ;
     RECT  17.123 51.904 18.757 53.024 ;
     RECT  18.709 54.784 18.757 55.968 ;
     RECT  18.757 44.032 18.795 55.968 ;
     RECT  16.837 0.064 18.949 8.48 ;
     RECT  18.133 10.304 18.949 42.208 ;
     RECT  18.949 0.064 19.141 42.208 ;
     RECT  18.795 44.032 19.141 46.88 ;
     RECT  17.643 59.776 19.333 61.26 ;
     RECT  18.795 48.96 19.427 55.968 ;
     RECT  19.427 49.596 19.627 55.968 ;
     RECT  19.141 0.064 19.691 46.88 ;
     RECT  19.691 0.064 19.883 46.816 ;
     RECT  19.883 0.064 20.003 9.12 ;
     RECT  19.883 10.432 20.435 46.816 ;
     RECT  19.627 49.596 20.523 55.86 ;
     RECT  20.003 5.696 20.915 9.12 ;
     RECT  19.333 59.456 21.061 61.26 ;
     RECT  20.523 49.596 21.445 51.936 ;
     RECT  19.717 57.472 21.675 57.504 ;
     RECT  21.445 49.472 21.779 51.936 ;
     RECT  20.435 10.432 22.213 45.728 ;
     RECT  20.003 0.064 22.259 4.32 ;
     RECT  22.213 10.304 22.259 45.728 ;
     RECT  22.259 10.304 22.597 42.08 ;
     RECT  20.523 53.632 23.029 55.86 ;
     RECT  20.915 5.696 23.093 8.608 ;
     RECT  22.597 9.984 23.093 42.08 ;
     RECT  21.061 59.136 23.221 61.26 ;
     RECT  23.029 52.864 23.477 55.86 ;
     RECT  23.477 52.864 23.555 55.968 ;
     RECT  21.779 49.472 23.893 51.552 ;
     RECT  23.221 58.112 23.893 61.26 ;
     RECT  22.259 43.648 23.925 45.728 ;
     RECT  23.893 47.296 23.925 51.552 ;
     RECT  23.925 43.648 23.979 51.552 ;
     RECT  23.979 43.648 23.998 46.688 ;
     RECT  23.093 5.696 24.037 42.08 ;
     RECT  23.998 43.648 24.037 45.6 ;
     RECT  24.037 5.696 24.107 45.6 ;
     RECT  24.107 5.696 24.171 42.08 ;
     RECT  23.979 48.064 24.421 51.552 ;
     RECT  23.555 52.864 24.421 55.86 ;
     RECT  24.171 5.696 25.139 8.288 ;
     RECT  23.893 58.112 25.235 61.6 ;
     RECT  25.235 58.112 25.429 61.26 ;
     RECT  25.429 57.6 25.771 61.26 ;
     RECT  24.171 9.6 26.037 42.08 ;
     RECT  24.107 43.648 26.037 45.6 ;
     RECT  26.037 9.6 26.101 45.6 ;
     RECT  24.421 48.064 26.149 55.86 ;
     RECT  26.101 9.6 26.195 46.24 ;
     RECT  26.149 47.872 26.219 55.86 ;
     RECT  25.771 57.6 26.819 57.632 ;
     RECT  26.219 48.064 26.923 55.86 ;
     RECT  22.259 0.064 27.109 4.192 ;
     RECT  25.139 5.888 27.109 8.288 ;
     RECT  25.771 59.392 27.109 61.26 ;
     RECT  26.923 48.064 27.371 53.28 ;
     RECT  27.371 52.864 27.563 53.28 ;
     RECT  27.109 0.064 27.683 8.288 ;
     RECT  27.683 5.888 27.701 8.288 ;
     RECT  26.195 9.6 27.701 45.728 ;
     RECT  27.061 57.728 27.781 57.76 ;
     RECT  27.109 59.392 27.781 61.6 ;
     RECT  27.701 5.888 28.069 45.728 ;
     RECT  26.923 54.784 28.213 55.86 ;
     RECT  27.781 57.728 28.213 61.6 ;
     RECT  28.069 5.888 28.267 45.92 ;
     RECT  28.213 54.784 28.789 61.6 ;
     RECT  27.371 48.064 28.853 51.552 ;
     RECT  27.563 53.184 29.029 53.28 ;
     RECT  29.029 53.184 29.075 53.344 ;
     RECT  28.853 47.616 29.877 51.552 ;
     RECT  28.789 54.784 29.939 62.176 ;
     RECT  29.075 53.312 29.989 53.344 ;
     RECT  29.939 54.784 29.989 57.76 ;
     RECT  29.939 59.392 30.133 62.176 ;
     RECT  30.133 59.392 30.202 62.752 ;
     RECT  28.267 5.888 30.379 45.472 ;
     RECT  29.877 47.488 30.645 51.552 ;
     RECT  30.379 6.396 30.709 45.472 ;
     RECT  30.645 47.168 30.709 51.552 ;
     RECT  29.989 53.312 30.757 57.76 ;
     RECT  30.709 6.396 31.525 51.552 ;
     RECT  30.202 59.392 31.525 61.472 ;
     RECT  31.525 6.396 31.925 51.68 ;
     RECT  31.525 59.392 31.925 61.536 ;
     RECT  31.925 6.272 32.181 51.68 ;
     RECT  30.757 53.184 32.181 57.76 ;
     RECT  32.181 6.272 32.491 57.76 ;
     RECT  32.491 53.312 32.533 57.76 ;
     RECT  31.925 59.136 32.533 61.536 ;
     RECT  27.683 0.064 32.875 4.192 ;
     RECT  32.533 53.312 33.077 61.536 ;
     RECT  32.491 6.272 33.109 51.936 ;
     RECT  32.875 0.064 33.131 3.68 ;
     RECT  33.109 5.056 33.195 51.936 ;
     RECT  33.077 53.312 33.299 62.176 ;
     RECT  33.131 0.128 33.387 3.68 ;
     RECT  33.387 0.256 33.406 3.68 ;
     RECT  33.406 0.384 33.539 3.68 ;
     RECT  33.539 0.512 33.779 3.68 ;
     RECT  33.299 57.728 33.85 62.176 ;
     RECT  33.779 0.512 34.019 3.488 ;
     RECT  33.195 6.016 34.165 51.936 ;
     RECT  33.299 53.312 34.165 56.096 ;
     RECT  33.85 57.728 34.366 58.016 ;
     RECT  34.165 6.016 34.981 56.096 ;
     RECT  34.981 5.12 35.075 56.096 ;
     RECT  35.075 5.12 35.267 8.544 ;
     RECT  34.366 57.728 35.701 57.76 ;
     RECT  35.701 57.6 35.77 57.76 ;
     RECT  33.85 59.392 35.939 62.176 ;
     RECT  35.267 6.016 36.533 8.544 ;
     RECT  35.075 10.176 36.533 56.096 ;
     RECT  36.533 6.016 36.651 56.096 ;
     RECT  34.019 0.576 37.045 3.488 ;
     RECT  36.651 54.336 37.091 56.096 ;
     RECT  37.045 0.512 37.093 3.488 ;
     RECT  37.093 0.384 37.285 3.488 ;
     RECT  36.651 6.016 37.331 53.024 ;
     RECT  35.77 57.728 37.909 57.76 ;
     RECT  37.909 57.728 38.133 58.016 ;
     RECT  35.939 59.392 38.133 61.472 ;
     RECT  37.331 6.144 38.725 53.024 ;
     RECT  37.091 54.72 38.725 56.096 ;
     RECT  38.133 57.728 39.301 61.472 ;
     RECT  39.301 57.728 39.339 61.536 ;
     RECT  37.285 0.32 39.413 3.488 ;
     RECT  38.725 6.144 39.877 56.096 ;
     RECT  39.339 57.728 39.877 57.824 ;
     RECT  39.413 0.128 40.693 3.488 ;
     RECT  39.877 6.144 40.693 57.824 ;
     RECT  40.693 5.056 40.747 57.824 ;
     RECT  40.747 5.056 40.787 5.088 ;
     RECT  40.693 0.128 40.933 3.616 ;
     RECT  39.339 59.392 40.981 61.536 ;
     RECT  40.981 59.264 41.845 61.536 ;
     RECT  41.845 59.264 41.914 62.752 ;
     RECT  40.933 0.128 42.037 4.064 ;
     RECT  41.914 59.264 42.411 61.6 ;
     RECT  42.037 0.064 42.549 4.064 ;
     RECT  42.549 0.064 42.594 5.088 ;
     RECT  40.747 6.396 42.594 57.824 ;
     RECT  42.594 0.064 42.709 57.824 ;
     RECT  42.411 59.264 42.709 61.536 ;
     RECT  42.709 0.064 42.731 61.536 ;
     RECT  42.731 0.064 42.795 4.064 ;
     RECT  42.731 5.952 43.955 61.536 ;
     RECT  43.955 5.952 44.101 57.824 ;
     RECT  42.795 0.064 44.387 3.872 ;
     RECT  44.101 5.632 44.523 57.824 ;
     RECT  43.955 59.264 44.965 61.536 ;
     RECT  44.387 0.064 45.059 3.616 ;
     RECT  44.965 59.264 45.059 61.664 ;
     RECT  45.059 59.456 45.155 61.664 ;
     RECT  44.523 5.952 45.355 57.824 ;
     RECT  44.437 63.296 45.541 63.328 ;
     RECT  45.355 5.952 45.779 56.992 ;
     RECT  45.541 63.04 45.827 63.328 ;
     RECT  45.155 60.396 45.973 61.664 ;
     RECT  45.827 63.04 45.973 63.2 ;
     RECT  45.973 60.396 46.059 63.2 ;
     RECT  45.059 0.064 46.067 2.72 ;
     RECT  46.059 60.396 46.403 61.664 ;
     RECT  46.403 60.396 46.645 61.472 ;
     RECT  46.645 59.84 46.714 61.472 ;
     RECT  46.059 63.04 46.835 63.2 ;
     RECT  46.714 60.288 46.931 61.472 ;
     RECT  46.835 63.04 46.979 63.072 ;
     RECT  45.779 6.272 47.029 56.992 ;
     RECT  47.029 6.272 47.403 58.208 ;
     RECT  46.693 3.712 48.179 3.744 ;
     RECT  47.403 57.728 48.179 58.208 ;
     RECT  48.179 57.728 48.709 57.76 ;
     RECT  46.931 60.396 48.709 61.472 ;
     RECT  48.709 57.536 48.755 57.76 ;
     RECT  47.403 6.272 49.899 55.968 ;
     RECT  48.709 60.288 50.082 61.472 ;
     RECT  49.899 6.272 50.091 9.76 ;
     RECT  48.421 4.224 50.101 4.448 ;
     RECT  50.082 59.136 50.101 61.472 ;
     RECT  48.661 63.232 50.101 63.264 ;
     RECT  49.899 11.392 50.437 55.968 ;
     RECT  48.755 57.536 50.437 57.568 ;
     RECT  50.101 59.136 50.531 63.264 ;
     RECT  50.437 11.392 50.677 57.568 ;
     RECT  50.531 59.136 50.677 62.944 ;
     RECT  50.677 11.392 52.019 62.944 ;
     RECT  50.101 4.224 52.115 4.576 ;
     RECT  50.091 6.272 52.405 9.696 ;
     RECT  52.019 11.584 52.499 62.944 ;
     RECT  52.405 6.208 53.493 9.696 ;
     RECT  52.499 11.584 53.843 62.752 ;
     RECT  53.843 58.624 53.891 62.752 ;
     RECT  53.891 58.624 54.083 61.536 ;
     RECT  53.843 11.584 54.085 57.248 ;
     RECT  52.115 4.224 54.709 4.256 ;
     RECT  46.067 0.064 54.755 1.86 ;
     RECT  54.755 0.32 54.851 1.86 ;
     RECT  54.085 11.328 55.141 57.248 ;
     RECT  54.083 58.624 55.141 61.472 ;
     RECT  54.709 4.032 55.189 4.256 ;
     RECT  53.493 6.016 55.189 9.696 ;
     RECT  55.141 11.328 55.787 61.472 ;
     RECT  55.189 4.032 55.813 9.696 ;
     RECT  55.787 11.328 55.813 61.408 ;
     RECT  54.851 0.832 56.043 1.86 ;
     RECT  55.813 4.032 56.314 61.408 ;
     RECT  56.314 58.112 56.427 61.408 ;
     RECT  55.237 63.296 56.675 63.328 ;
     RECT  56.043 0.996 57.333 1.86 ;
     RECT  56.314 4.032 57.387 56.736 ;
     RECT  56.427 58.368 57.397 61.408 ;
     RECT  57.387 4.032 57.635 4.064 ;
     RECT  57.387 5.888 57.635 56.736 ;
     RECT  57.635 10.56 57.643 56.736 ;
     RECT  57.635 5.888 57.707 9.184 ;
     RECT  57.397 58.368 58.229 61.856 ;
     RECT  57.707 9.152 58.739 9.184 ;
     RECT  58.229 57.6 58.981 61.856 ;
     RECT  57.643 10.56 59.051 55.86 ;
     RECT  58.981 57.6 59.051 62.624 ;
     RECT  57.707 5.888 59.125 7.26 ;
     RECT  59.125 5.056 59.173 7.26 ;
     RECT  59.051 10.56 59.173 53.28 ;
     RECT  59.173 5.056 59.194 7.968 ;
     RECT  59.194 5.888 59.243 7.968 ;
     RECT  59.051 57.6 59.246 61.26 ;
     RECT  59.246 57.536 59.315 61.26 ;
     RECT  57.333 0.996 59.76 2.528 ;
     RECT  59.76 1.408 60.083 2.528 ;
     RECT  59.315 58.432 60.083 61.26 ;
     RECT  59.243 5.888 60.179 7.26 ;
     RECT  60.083 59.008 60.227 61.26 ;
     RECT  60.083 1.408 60.467 1.86 ;
     RECT  59.173 10.368 60.467 53.28 ;
     RECT  59.051 62.592 60.467 62.624 ;
     RECT  59.051 54.656 60.515 55.86 ;
     RECT  60.467 1.572 60.544 1.86 ;
     RECT  60.179 6.016 60.544 7.26 ;
     RECT  60.227 60.544 60.544 61.26 ;
     RECT  60.515 54.72 60.661 55.86 ;
     RECT  60.661 54.72 60.715 56.48 ;
     RECT  60.715 56.384 60.73 56.48 ;
     RECT  60.467 11.904 60.843 53.088 ;
     RECT  60.843 13.952 61.035 53.088 ;
     RECT  60.544 6.016 61.043 6.816 ;
     RECT  60.843 11.904 61.227 12.256 ;
     RECT  60.715 54.72 61.227 54.752 ;
     RECT  60.467 10.368 61.246 10.4 ;
     RECT  61.227 11.904 61.291 11.936 ;
     RECT  61.285 4.544 61.355 4.576 ;
     RECT  60.544 60.544 61.483 60.576 ;
     RECT  60.227 59.008 61.523 59.04 ;
     RECT  61.035 13.952 61.667 52.512 ;
     RECT  60.73 56.384 61.715 56.416 ;
     RECT  61.861 59.84 61.931 59.872 ;
     RECT  61.043 6.784 61.995 6.816 ;
     RECT  61.909 9.152 61.995 9.184 ;
     RECT  62.245 7.936 62.315 8.544 ;
     RECT  61.667 14.784 62.341 52.512 ;
     RECT  62.341 14.784 62.435 53.216 ;
     RECT  62.37 11.84 62.443 11.872 ;
     RECT  62.435 14.784 62.579 23.776 ;
     RECT  62.435 25.28 62.579 53.216 ;
     RECT  62.315 8.32 62.59 8.544 ;
     RECT  62.579 14.784 62.627 16.16 ;
     RECT  62.579 17.536 62.627 23.776 ;
     RECT  62.579 38.592 62.627 53.216 ;
     RECT  62.627 51.84 62.635 53.216 ;
     RECT  62.627 38.592 62.673 50.528 ;
     RECT  62.59 8.512 62.699 8.544 ;
     RECT  62.579 25.28 62.723 25.312 ;
     RECT  62.579 26.752 62.723 36.704 ;
     RECT  62.635 51.84 62.723 52.448 ;
     RECT  62.126 3.968 62.763 4 ;
     RECT  62.723 26.752 62.763 34.336 ;
     RECT  62.627 14.848 62.771 16.16 ;
     RECT  62.763 26.752 62.771 29.536 ;
     RECT  62.763 31.424 62.771 34.336 ;
     RECT  62.723 35.648 62.771 36.704 ;
     RECT  62.673 38.592 62.771 50.144 ;
     RECT  62.771 38.592 62.819 49.632 ;
     RECT  62.629 56.896 62.821 57.632 ;
     RECT  62.771 31.936 62.827 34.336 ;
     RECT  62.819 45.056 62.827 49.632 ;
     RECT  62.821 56.896 62.842 58.208 ;
     RECT  62.627 17.536 62.867 23.328 ;
     RECT  62.771 26.752 62.867 29.088 ;
     RECT  62.771 35.648 62.867 36.576 ;
     RECT  62.827 45.568 62.867 49.632 ;
     RECT  62.771 16.128 62.891 16.16 ;
     RECT  62.827 31.936 62.891 33.056 ;
     RECT  62.867 35.968 62.891 36.576 ;
     RECT  62.819 38.592 62.891 43.296 ;
     RECT  62.867 46.848 62.891 49.632 ;
     RECT  62.723 51.84 62.891 51.936 ;
     RECT  62.842 58.176 62.891 58.208 ;
     RECT  62.867 17.536 62.915 19.104 ;
     RECT  62.869 11.904 62.955 11.936 ;
     RECT  62.867 20.608 62.955 23.328 ;
     RECT  62.867 27.392 62.955 29.088 ;
     RECT  62.891 32.896 62.955 33.056 ;
     RECT  62.891 35.968 62.955 36 ;
     RECT  62.891 38.912 62.955 39.968 ;
     RECT  62.891 41.6 62.955 43.296 ;
     RECT  62.891 48.32 62.955 49.632 ;
     RECT  62.915 17.536 62.963 17.696 ;
     RECT  62.955 21.12 62.963 23.328 ;
     RECT  62.955 27.392 62.963 27.424 ;
     RECT  62.963 22.4 63.011 23.328 ;
     RECT  63.011 23.296 63.019 23.328 ;
     RECT  62.955 28.8 63.019 28.832 ;
     RECT  62.955 33.024 63.019 33.056 ;
     RECT  62.955 38.912 63.019 38.944 ;
     RECT  62.955 41.6 63.019 42.592 ;
     RECT  62.955 48.32 63.019 48.352 ;
     RECT  62.963 17.536 63.034 17.568 ;
     RECT  62.891 46.848 63.034 46.88 ;
     RECT  62.891 51.904 63.034 51.936 ;
    LAYER M7 ;
     RECT  21.312 0.053 21.664 0.117 ;
     RECT  25.088 0.053 25.952 0.117 ;
     RECT  33.088 0.053 33.12 0.117 ;
     RECT  42.048 0.053 42.08 0.117 ;
     RECT  19.136 0.117 19.168 0.181 ;
     RECT  25.088 0.117 26.208 0.181 ;
     RECT  29.312 0.117 29.6 0.181 ;
     RECT  21.312 0.117 21.728 0.245 ;
     RECT  25.088 0.181 27.04 0.245 ;
     RECT  29.248 0.181 29.6 0.245 ;
     RECT  41.536 0.117 42.464 0.245 ;
     RECT  39.424 0.117 39.456 0.309 ;
     RECT  40.768 0.245 42.464 0.309 ;
     RECT  19.008 0.181 19.168 0.363 ;
     RECT  33.088 0.117 33.376 0.373 ;
     RECT  37.952 0.309 37.984 0.437 ;
     RECT  39.424 0.309 43.424 0.491 ;
     RECT  21.184 0.245 21.728 0.501 ;
     RECT  24.128 0.245 30.24 0.501 ;
     RECT  37.952 0.437 38.112 0.501 ;
     RECT  39.424 0.491 40.8 0.501 ;
     RECT  32.704 0.373 33.376 0.531 ;
     RECT  42.56 0.491 43.424 0.531 ;
     RECT  37.952 0.501 40.8 0.619 ;
     RECT  21.184 0.501 30.24 0.629 ;
     RECT  37.952 0.619 40.544 0.683 ;
     RECT  20.352 0.629 30.24 0.747 ;
     RECT  32.704 0.531 33.544 0.747 ;
     RECT  20.352 0.747 24.288 0.811 ;
     RECT  26.368 0.747 30.24 0.811 ;
     RECT  38.08 0.683 40.544 0.811 ;
     RECT  49.456 0.531 49.744 0.821 ;
     RECT  54.856 0.531 55.144 0.821 ;
     RECT  20.352 0.811 20.384 0.875 ;
     RECT  21.76 0.811 24.288 0.875 ;
     RECT  40.512 0.811 40.544 0.875 ;
     RECT  24.256 0.875 24.288 1.451 ;
     RECT  38.08 0.811 38.944 2.027 ;
     RECT  26.368 0.811 29.664 2.283 ;
     RECT  32.832 0.747 33.544 2.421 ;
     RECT  26.368 2.283 28.832 2.667 ;
     RECT  32.448 2.421 33.544 2.795 ;
     RECT  21.76 0.875 22.744 2.859 ;
     RECT  26.368 2.667 28.144 2.869 ;
     RECT  25.088 2.869 28.144 3.307 ;
     RECT  2.56 2.805 2.592 3.317 ;
     RECT  42.56 0.531 44.344 3.381 ;
     RECT  25.6 3.307 28.144 3.499 ;
     RECT  32.576 2.795 33.544 3.563 ;
     RECT  41.344 3.381 44.344 3.573 ;
     RECT  32.704 3.563 33.544 3.755 ;
     RECT  32.832 3.755 33.544 3.883 ;
     RECT  9.472 2.229 9.504 3.957 ;
     RECT  40.704 3.573 44.344 4.075 ;
     RECT  54.856 0.821 56.032 4.213 ;
     RECT  19.008 0.363 19.04 4.469 ;
     RECT  2.56 3.317 3.296 4.533 ;
     RECT  60.256 0.531 60.544 4.533 ;
     RECT  62.144 3.957 62.752 4.533 ;
     RECT  9.472 3.957 10.336 4.843 ;
     RECT  60.256 4.533 62.752 5.045 ;
     RECT  42.56 4.075 44.344 5.099 ;
     RECT  54.4 4.213 56.032 5.173 ;
     RECT  57.344 2.485 57.376 5.173 ;
     RECT  54.4 5.173 57.376 5.227 ;
     RECT  42.624 5.099 44.344 5.621 ;
     RECT  22.456 2.859 22.744 5.685 ;
     RECT  17.056 0.531 17.344 5.877 ;
     RECT  11.656 0.531 11.944 5.941 ;
     RECT  54.4 5.227 57.056 6.005 ;
     RECT  59.136 5.045 62.752 6.005 ;
     RECT  58.624 6.005 62.752 6.059 ;
     RECT  0.856 0.531 1.144 6.133 ;
     RECT  9.472 4.843 9.504 6.197 ;
     RECT  21.504 5.685 22.744 6.197 ;
     RECT  24.128 5.941 24.16 6.197 ;
     RECT  42.624 5.621 44.512 6.197 ;
     RECT  53.504 6.005 57.056 6.197 ;
     RECT  25.6 3.499 25.632 6.251 ;
     RECT  33.152 3.883 33.544 6.261 ;
     RECT  19.008 4.469 19.808 6.315 ;
     RECT  6.256 0.531 6.544 6.773 ;
     RECT  11.656 5.941 12.832 6.773 ;
     RECT  53.12 6.197 57.056 6.773 ;
     RECT  21.504 6.197 24.16 6.827 ;
     RECT  49.456 0.821 50.912 6.837 ;
     RECT  52.672 6.773 57.056 6.837 ;
     RECT  6.256 6.773 6.816 7.349 ;
     RECT  31.936 6.261 33.544 7.349 ;
     RECT  42.624 6.197 45.152 7.541 ;
     RECT  0.256 6.133 1.144 7.723 ;
     RECT  42.368 7.541 45.152 7.733 ;
     RECT  4.864 6.133 4.896 7.851 ;
     RECT  26.112 7.349 26.144 7.861 ;
     RECT  27.856 3.499 28.144 7.861 ;
     RECT  30.336 5.877 30.368 7.925 ;
     RECT  31.936 7.349 34.336 7.925 ;
     RECT  58.624 6.059 58.656 7.925 ;
     RECT  60.256 6.059 62.752 7.925 ;
     RECT  30.336 7.925 34.336 8.107 ;
     RECT  36.8 6.837 36.832 8.245 ;
     RECT  49.456 6.837 57.056 8.245 ;
     RECT  58.624 7.925 62.752 8.245 ;
     RECT  6.256 7.349 7.072 8.309 ;
     RECT  9.472 6.197 10.016 8.363 ;
     RECT  31.936 8.107 34.336 8.491 ;
     RECT  42.048 7.733 45.152 8.565 ;
     RECT  42.048 8.565 45.792 8.885 ;
     RECT  47.36 8.501 47.392 8.885 ;
     RECT  16.192 5.877 17.344 9.013 ;
     RECT  19.008 6.315 19.68 9.077 ;
     RECT  38.656 2.027 38.944 9.077 ;
     RECT  40.704 4.075 40.736 9.077 ;
     RECT  42.048 8.885 47.392 9.077 ;
     RECT  49.456 8.245 62.752 9.195 ;
     RECT  38.656 9.077 47.648 9.205 ;
     RECT  11.656 6.773 12.96 9.397 ;
     RECT  14.976 9.013 17.344 9.397 ;
     RECT  36.8 8.245 36.96 9.461 ;
     RECT  9.984 8.363 10.016 9.653 ;
     RECT  11.656 9.397 17.344 9.653 ;
     RECT  30.336 8.107 30.368 9.653 ;
     RECT  2.56 4.533 3.424 9.781 ;
     RECT  26.112 7.861 28.144 9.973 ;
     RECT  29.696 9.653 30.368 9.973 ;
     RECT  22.456 6.827 24.16 10.165 ;
     RECT  26.112 9.973 30.368 10.165 ;
     RECT  38.656 9.205 47.776 10.165 ;
     RECT  36.544 9.461 36.96 10.539 ;
     RECT  38.656 10.165 47.84 10.613 ;
     RECT  49.456 9.195 57.696 10.613 ;
     RECT  22.456 10.165 30.368 10.677 ;
     RECT  9.984 9.653 17.344 10.741 ;
     RECT  19.008 9.077 20.896 10.741 ;
     RECT  38.656 10.613 57.696 10.859 ;
     RECT  22.456 10.677 31.072 10.923 ;
     RECT  32.448 8.491 34.336 10.933 ;
     RECT  25.216 10.923 31.072 11.371 ;
     RECT  36.8 10.539 36.96 11.381 ;
     RECT  38.656 10.859 40.544 11.381 ;
     RECT  9.984 10.741 20.896 11.435 ;
     RECT  42.048 10.859 57.696 11.445 ;
     RECT  59.2 9.195 62.752 11.445 ;
     RECT  22.456 10.923 23.136 11.691 ;
     RECT  42.048 11.445 62.752 11.893 ;
     RECT  6.256 8.309 7.904 12.149 ;
     RECT  42.048 11.893 62.944 12.203 ;
     RECT  32.448 10.933 35.36 12.213 ;
     RECT  36.8 11.381 40.544 12.213 ;
     RECT  9.984 11.435 10.016 12.725 ;
     RECT  32.448 12.213 40.544 12.725 ;
     RECT  42.048 12.203 50.08 12.725 ;
     RECT  2.432 9.781 3.424 12.779 ;
     RECT  9.728 12.725 10.016 12.779 ;
     RECT  25.28 11.371 31.072 12.917 ;
     RECT  6.256 12.149 8.416 13.045 ;
     RECT  9.728 12.779 9.76 13.045 ;
     RECT  22.456 11.691 22.744 13.045 ;
     RECT  6.256 13.045 9.76 13.163 ;
     RECT  11.656 11.435 20.896 13.227 ;
     RECT  25.088 12.917 31.072 13.237 ;
     RECT  32.448 12.725 50.08 13.237 ;
     RECT  11.656 13.227 15.52 13.739 ;
     RECT  6.256 13.163 7.072 13.941 ;
     RECT  25.088 13.237 50.08 13.941 ;
     RECT  51.776 12.203 62.944 13.941 ;
     RECT  3.392 12.779 3.424 14.197 ;
     RECT  5.184 13.941 7.072 14.197 ;
     RECT  3.392 14.197 7.072 14.443 ;
     RECT  8.384 13.163 9.76 14.571 ;
     RECT  4.096 14.443 7.072 14.773 ;
     RECT  8.384 14.571 8.608 14.773 ;
     RECT  25.088 13.941 62.944 14.891 ;
     RECT  26.112 14.891 62.944 15.147 ;
     RECT  4.096 14.773 8.608 15.467 ;
     RECT  17.056 13.227 20.896 15.595 ;
     RECT  11.656 13.739 12.32 15.925 ;
     RECT  17.056 15.595 19.872 16.043 ;
     RECT  26.112 15.147 40.352 16.171 ;
     RECT  14.208 13.739 15.52 16.235 ;
     RECT  4.096 15.467 7.072 16.491 ;
     RECT  22.456 13.045 23.776 16.501 ;
     RECT  26.112 16.171 30.752 16.619 ;
     RECT  8.384 15.467 8.608 16.693 ;
     RECT  42.112 15.147 62.944 16.811 ;
     RECT  15.488 16.235 15.52 17.003 ;
     RECT  11.656 15.925 12.512 17.013 ;
     RECT  32.064 16.171 40.352 17.013 ;
     RECT  42.112 16.811 44.448 17.013 ;
     RECT  45.888 16.811 62.944 17.525 ;
     RECT  26.24 16.619 30.752 17.643 ;
     RECT  11.52 17.013 12.512 18.165 ;
     RECT  22.456 16.501 24.48 18.165 ;
     RECT  26.24 17.643 30.176 18.165 ;
     RECT  32.064 17.013 44.448 18.165 ;
     RECT  45.888 17.525 63.008 18.165 ;
     RECT  32.064 18.165 63.008 18.219 ;
     RECT  22.456 18.165 30.176 18.347 ;
     RECT  37.568 18.219 63.008 18.539 ;
     RECT  4.608 16.491 7.072 18.613 ;
     RECT  8.384 16.693 8.8 18.613 ;
     RECT  17.056 16.043 19.04 18.613 ;
     RECT  22.456 18.347 28.768 18.667 ;
     RECT  22.456 18.667 25.312 18.741 ;
     RECT  42.112 18.539 63.008 18.923 ;
     RECT  30.08 18.347 30.176 19.317 ;
     RECT  32.064 18.219 36.064 19.317 ;
     RECT  42.24 18.923 63.008 19.435 ;
     RECT  22.208 18.741 25.312 19.627 ;
     RECT  22.208 19.627 25.248 19.637 ;
     RECT  30.08 19.317 36.064 19.637 ;
     RECT  37.568 18.539 40.8 19.637 ;
     RECT  17.056 18.613 19.68 19.893 ;
     RECT  21.056 19.637 25.248 19.893 ;
     RECT  26.88 18.667 28.768 19.893 ;
     RECT  30.08 19.637 40.8 19.893 ;
     RECT  17.056 19.893 25.248 20.011 ;
     RECT  17.056 20.011 24.992 20.139 ;
     RECT  26.88 19.893 40.8 20.267 ;
     RECT  37.568 20.267 40.8 20.277 ;
     RECT  4.608 18.613 8.8 20.523 ;
     RECT  37.568 20.277 41.056 20.587 ;
     RECT  17.056 20.139 24.288 20.725 ;
     RECT  6.256 20.523 8.8 20.779 ;
     RECT  26.88 20.267 35.872 20.843 ;
     RECT  37.568 20.587 40.544 20.971 ;
     RECT  7.936 20.779 8.8 21.109 ;
     RECT  11.52 18.165 12.64 21.301 ;
     RECT  11.456 21.301 12.64 21.355 ;
     RECT  15.744 20.725 24.288 21.355 ;
     RECT  29.76 20.843 35.872 21.355 ;
     RECT  37.568 20.971 40.48 21.483 ;
     RECT  15.744 21.355 19.936 21.867 ;
     RECT  4.608 20.523 4.64 21.931 ;
     RECT  0.856 7.723 1.144 22.069 ;
     RECT  6.256 20.779 6.544 22.069 ;
     RECT  26.88 20.843 28.144 22.197 ;
     RECT  37.568 21.483 40.352 22.315 ;
     RECT  32.064 21.355 35.872 22.325 ;
     RECT  14.08 19.893 14.112 22.389 ;
     RECT  14.08 22.389 14.24 22.443 ;
     RECT  37.568 22.315 39.968 22.443 ;
     RECT  42.624 19.435 63.008 22.453 ;
     RECT  11.456 21.355 11.944 23.019 ;
     RECT  0.856 22.069 1.568 23.029 ;
     RECT  16 21.867 19.936 23.029 ;
     RECT  21.44 21.355 24.288 23.029 ;
     RECT  32.064 22.325 36.192 23.029 ;
     RECT  16 23.029 24.288 23.083 ;
     RECT  26.88 22.197 28.256 23.083 ;
     RECT  29.76 21.355 30.112 23.083 ;
     RECT  42.176 22.453 63.008 23.339 ;
     RECT  4.032 22.197 4.064 23.595 ;
     RECT  7.936 21.109 8.864 23.595 ;
     RECT  42.176 23.339 62.944 23.595 ;
     RECT  31.936 23.029 36.192 23.605 ;
     RECT  37.568 22.443 39.648 23.605 ;
     RECT  8.64 23.595 8.864 23.861 ;
     RECT  31.936 23.605 39.648 23.861 ;
     RECT  0.856 23.029 1.696 23.979 ;
     RECT  42.176 23.595 44.344 23.979 ;
     RECT  31.936 23.861 39.84 24.053 ;
     RECT  5.568 22.069 6.544 24.555 ;
     RECT  16.512 23.083 24.288 24.555 ;
     RECT  31.936 24.053 40.544 24.565 ;
     RECT  16.512 24.555 23.648 24.757 ;
     RECT  8.64 23.861 9.696 24.821 ;
     RECT  11.52 23.019 11.944 24.821 ;
     RECT  8.64 24.821 11.944 24.875 ;
     RECT  31.936 24.565 40.672 24.875 ;
     RECT  14.208 22.443 14.24 24.885 ;
     RECT  15.872 24.757 23.648 24.885 ;
     RECT  9.984 24.875 11.944 24.949 ;
     RECT  29.888 23.083 30.112 24.949 ;
     RECT  29.632 24.949 30.112 25.003 ;
     RECT  8.64 24.875 8.672 25.013 ;
     RECT  25.088 24.693 25.248 25.077 ;
     RECT  25.088 25.077 25.632 25.131 ;
     RECT  32.064 24.875 39.84 25.131 ;
     RECT  9.984 24.949 12.32 25.195 ;
     RECT  42.56 23.979 44.344 25.269 ;
     RECT  45.632 23.595 62.944 25.269 ;
     RECT  25.216 25.131 25.632 25.387 ;
     RECT  27.136 23.083 28.256 25.387 ;
     RECT  29.632 25.003 29.92 25.387 ;
     RECT  11.008 25.195 12.32 25.515 ;
     RECT  6.256 24.555 6.544 25.653 ;
     RECT  8.064 25.013 8.672 25.653 ;
     RECT  6.256 25.653 8.672 25.707 ;
     RECT  14.208 24.885 23.648 25.909 ;
     RECT  13.696 25.909 23.648 25.963 ;
     RECT  2.816 25.269 2.848 26.101 ;
     RECT  13.696 25.963 22.744 26.283 ;
     RECT  32.064 25.131 39.2 26.411 ;
     RECT  42.56 25.269 62.944 26.411 ;
     RECT  25.536 25.387 25.632 26.741 ;
     RECT  36.608 26.411 39.2 26.795 ;
     RECT  11.392 25.515 12.32 26.805 ;
     RECT  13.696 26.283 19.04 26.859 ;
     RECT  11.392 26.805 12.384 27.115 ;
     RECT  42.56 26.411 44.576 27.253 ;
     RECT  42.176 27.253 44.576 27.435 ;
     RECT  46.208 26.411 62.944 27.435 ;
     RECT  42.56 27.435 44.576 27.691 ;
     RECT  15.872 26.859 19.04 27.701 ;
     RECT  20.608 26.283 22.744 27.701 ;
     RECT  46.4 27.435 49.744 27.755 ;
     RECT  15.872 27.701 22.744 27.819 ;
     RECT  13.696 26.859 13.728 27.883 ;
     RECT  24.448 26.741 25.632 27.883 ;
     RECT  27.712 25.387 28.256 27.883 ;
     RECT  36.864 26.795 39.2 27.883 ;
     RECT  6.256 25.707 8.224 28.459 ;
     RECT  51.392 27.435 62.944 28.789 ;
     RECT  0.856 23.979 1.144 28.981 ;
     RECT  2.688 26.101 2.848 28.981 ;
     RECT  27.856 27.883 28.256 28.981 ;
     RECT  29.632 25.387 29.664 28.981 ;
     RECT  51.392 28.789 63.008 29.045 ;
     RECT  6.256 28.459 8.096 29.099 ;
     RECT  25.536 27.883 25.632 29.099 ;
     RECT  15.872 27.819 20.64 29.163 ;
     RECT  32.064 26.411 34.72 29.301 ;
     RECT  42.816 27.691 44.576 29.365 ;
     RECT  36.864 27.883 37.344 29.429 ;
     RECT  38.656 27.883 39.2 29.429 ;
     RECT  48.512 27.755 49.744 29.429 ;
     RECT  51.136 29.045 63.008 29.429 ;
     RECT  32.064 29.301 35.296 29.493 ;
     RECT  36.864 29.429 39.2 29.493 ;
     RECT  40.896 27.829 41.12 29.557 ;
     RECT  46.4 27.755 47.136 29.557 ;
     RECT  48.512 29.429 63.008 29.557 ;
     RECT  27.856 28.981 29.664 29.621 ;
     RECT  11.52 27.115 12.384 29.675 ;
     RECT  25.6 29.099 25.632 29.675 ;
     RECT  40.768 29.557 41.12 29.675 ;
     RECT  46.4 29.557 63.008 29.739 ;
     RECT  0.856 28.981 2.848 29.995 ;
     RECT  42.816 29.365 45.024 30.133 ;
     RECT  2.816 29.995 2.848 30.187 ;
     RECT  32.064 29.493 39.2 30.251 ;
     RECT  27.856 29.621 30.368 30.453 ;
     RECT  32.064 30.251 37.344 30.453 ;
     RECT  42.368 30.133 45.024 30.581 ;
     RECT  46.4 29.739 46.432 30.581 ;
     RECT  38.656 30.251 39.2 30.645 ;
     RECT  40.768 29.675 40.928 30.645 ;
     RECT  6.256 29.099 7.776 30.837 ;
     RECT  22.336 27.819 22.744 30.891 ;
     RECT  27.856 30.453 37.344 30.901 ;
     RECT  26.624 30.901 37.344 31.083 ;
     RECT  47.744 29.739 63.008 31.083 ;
     RECT  6.256 30.837 7.968 31.147 ;
     RECT  38.656 30.645 40.928 31.285 ;
     RECT  42.368 30.581 46.432 31.285 ;
     RECT  4.288 28.405 4.32 31.403 ;
     RECT  6.256 31.147 6.816 31.403 ;
     RECT  13.632 30.325 13.664 31.403 ;
     RECT  15.872 29.163 20.512 31.403 ;
     RECT  11.52 29.675 11.944 31.733 ;
     RECT  2.944 30.709 2.976 31.851 ;
     RECT  20.48 31.403 20.512 31.861 ;
     RECT  26.624 31.083 29.216 32.107 ;
     RECT  30.784 31.083 37.344 32.107 ;
     RECT  15.872 31.403 19.04 32.235 ;
     RECT  31.296 32.107 37.344 32.245 ;
     RECT  38.656 31.285 46.432 32.245 ;
     RECT  47.744 31.083 53.152 32.437 ;
     RECT  10.752 31.733 11.944 32.555 ;
     RECT  20.48 31.861 21.152 32.693 ;
     RECT  25.024 31.029 25.056 32.757 ;
     RECT  26.624 32.107 28.144 32.757 ;
     RECT  25.024 32.757 28.144 32.811 ;
     RECT  26.24 32.811 28.144 32.939 ;
     RECT  47.744 32.437 53.216 32.949 ;
     RECT  54.592 31.083 63.008 32.949 ;
     RECT  31.296 32.245 46.432 33.013 ;
     RECT  47.744 32.949 63.008 33.013 ;
     RECT  31.296 33.013 63.008 33.067 ;
     RECT  26.624 32.939 28.144 33.131 ;
     RECT  10.88 32.555 11.944 33.141 ;
     RECT  15.872 32.235 17.952 33.259 ;
     RECT  15.872 33.259 17.76 33.323 ;
     RECT  3.968 32.821 4 33.835 ;
     RECT  19.968 32.693 21.152 33.835 ;
     RECT  6.256 31.403 6.544 33.845 ;
     RECT  14.912 33.781 14.944 33.845 ;
     RECT  0.856 29.995 1.144 34.357 ;
     RECT  17.056 33.323 17.76 34.805 ;
     RECT  19.968 33.835 20 34.805 ;
     RECT  22.456 30.891 22.744 34.933 ;
     RECT  5.056 33.845 6.544 35.371 ;
     RECT  22.336 34.933 22.744 35.445 ;
     RECT  31.296 33.067 62.88 35.765 ;
     RECT  0.256 34.357 1.144 35.947 ;
     RECT  8.704 34.677 8.736 35.947 ;
     RECT  31.04 35.765 62.88 35.957 ;
     RECT  25.088 34.485 25.12 36.021 ;
     RECT  26.752 33.131 28.144 36.021 ;
     RECT  10.88 33.141 12.32 36.149 ;
     RECT  31.04 35.957 62.944 36.405 ;
     RECT  14.784 33.845 14.944 36.523 ;
     RECT  25.088 36.021 28.144 36.523 ;
     RECT  25.088 36.523 26.208 36.587 ;
     RECT  3.52 34.421 3.744 36.597 ;
     RECT  17.056 34.805 20 36.651 ;
     RECT  2.816 36.597 3.744 36.661 ;
     RECT  5.376 35.371 6.544 36.661 ;
     RECT  27.856 36.523 28.144 36.725 ;
     RECT  9.728 36.149 12.32 36.789 ;
     RECT  19.968 36.651 20 37.099 ;
     RECT  17.056 36.651 18.208 37.109 ;
     RECT  30.912 36.405 62.944 37.227 ;
     RECT  8.064 36.213 8.096 37.301 ;
     RECT  22.336 35.445 23.776 37.365 ;
     RECT  7.872 37.301 8.096 37.429 ;
     RECT  9.728 36.789 12.448 37.429 ;
     RECT  2.816 36.661 6.544 37.557 ;
     RECT  7.872 37.429 12.448 37.557 ;
     RECT  2.816 37.557 12.448 37.621 ;
     RECT  14.144 37.173 14.176 37.621 ;
     RECT  22.336 37.365 24.288 37.675 ;
     RECT  36.864 37.227 62.944 37.675 ;
     RECT  2.816 37.621 14.176 38.059 ;
     RECT  31.04 37.227 35.488 38.251 ;
     RECT  37.568 37.675 62.944 38.315 ;
     RECT  2.816 38.059 8.608 38.379 ;
     RECT  16.256 37.109 18.208 38.517 ;
     RECT  2.816 38.379 4.512 38.581 ;
     RECT  43.456 38.315 62.944 38.901 ;
     RECT  6.256 38.379 8.608 39.211 ;
     RECT  27.856 36.725 29.216 39.211 ;
     RECT  37.568 38.315 40.992 39.733 ;
     RECT  25.664 36.587 26.208 39.787 ;
     RECT  43.456 38.901 63.008 39.797 ;
     RECT  2.624 38.581 4.512 39.861 ;
     RECT  16.256 38.517 19.296 39.861 ;
     RECT  20.736 39.221 20.768 39.861 ;
     RECT  6.256 39.211 8.096 39.915 ;
     RECT  0.856 35.947 1.144 40.437 ;
     RECT  32.064 38.251 35.488 40.437 ;
     RECT  36.864 39.733 40.992 40.437 ;
     RECT  43.264 39.797 63.008 40.437 ;
     RECT  25.664 39.787 26.144 40.491 ;
     RECT  2.624 39.861 4.896 40.555 ;
     RECT  7.872 39.915 8.096 40.555 ;
     RECT  10.24 38.059 14.176 40.555 ;
     RECT  36.864 40.437 63.008 40.619 ;
     RECT  22.456 37.675 24.288 41.067 ;
     RECT  7.872 40.555 7.968 41.451 ;
     RECT  36.864 40.619 42.016 41.451 ;
     RECT  16.256 39.861 20.768 41.461 ;
     RECT  0.64 40.437 1.144 41.643 ;
     RECT  2.624 40.555 4.512 41.643 ;
     RECT  15.936 41.461 20.768 41.643 ;
     RECT  36.864 41.451 41.632 41.643 ;
     RECT  26.048 40.491 26.144 41.781 ;
     RECT  27.856 39.211 28.768 42.037 ;
     RECT  31.872 40.437 35.488 42.101 ;
     RECT  36.864 41.643 41.376 42.101 ;
     RECT  10.496 40.555 14.176 42.219 ;
     RECT  31.872 42.101 41.376 42.795 ;
     RECT  41.344 42.795 41.376 42.933 ;
     RECT  43.328 40.619 63.008 42.933 ;
     RECT  31.872 42.795 39.968 42.987 ;
     RECT  7.936 41.451 7.968 43.243 ;
     RECT  22.456 41.067 24.096 43.371 ;
     RECT  31.872 42.987 39.648 43.499 ;
     RECT  27.856 42.037 29.6 43.573 ;
     RECT  26.048 41.781 26.208 43.701 ;
     RECT  27.856 43.573 29.792 43.701 ;
     RECT  10.496 42.219 13.024 43.755 ;
     RECT  0.856 41.643 1.144 43.829 ;
     RECT  31.872 43.499 35.04 43.829 ;
     RECT  31.616 43.829 35.04 43.947 ;
     RECT  26.048 43.701 29.792 43.957 ;
     RECT  26.048 43.957 29.92 44.021 ;
     RECT  25.792 44.021 29.92 45.173 ;
     RECT  41.344 42.933 63.008 45.173 ;
     RECT  10.496 43.755 12.96 45.227 ;
     RECT  25.792 45.173 30.048 45.227 ;
     RECT  22.456 43.371 23.84 45.291 ;
     RECT  29.76 45.227 30.048 45.301 ;
     RECT  29.76 45.301 30.112 45.355 ;
     RECT  31.616 43.947 34.016 45.557 ;
     RECT  0.856 43.829 2.336 45.675 ;
     RECT  10.496 45.227 12.064 45.686 ;
     RECT  40.96 45.173 63.008 45.739 ;
     RECT  10.56 45.686 12.064 45.867 ;
     RECT  15.936 41.643 20.192 46.251 ;
     RECT  51.904 45.739 63.008 46.251 ;
     RECT  31.616 45.557 34.272 46.443 ;
     RECT  22.456 45.291 23.392 46.645 ;
     RECT  36.352 43.499 39.648 46.827 ;
     RECT  52.224 46.251 63.008 46.891 ;
     RECT  8.576 45.301 8.608 47.019 ;
     RECT  10.752 45.867 12.064 47.019 ;
     RECT  30.016 45.355 30.112 47.157 ;
     RECT  31.616 46.443 33.544 47.157 ;
     RECT  36.352 46.827 39.2 47.157 ;
     RECT  15.936 46.251 17.344 47.339 ;
     RECT  22.456 46.645 23.968 47.339 ;
     RECT  30.016 47.157 33.544 47.477 ;
     RECT  25.792 45.227 28.256 47.605 ;
     RECT  29.888 47.477 33.544 47.605 ;
     RECT  40.96 45.739 50.528 47.797 ;
     RECT  40.96 47.797 50.912 47.915 ;
     RECT  35.712 47.157 39.2 47.925 ;
     RECT  42.368 47.915 50.912 48.043 ;
     RECT  35.52 47.925 39.2 48.117 ;
     RECT  25.792 47.605 33.544 48.309 ;
     RECT  52.224 46.891 62.944 48.309 ;
     RECT  17.056 47.339 17.344 48.949 ;
     RECT  18.752 46.251 20.192 48.949 ;
     RECT  35.52 48.117 39.328 49.013 ;
     RECT  43.136 48.043 50.912 49.013 ;
     RECT  52.224 48.309 63.008 49.013 ;
     RECT  40.96 47.915 40.992 49.333 ;
     RECT  43.136 49.013 63.008 49.333 ;
     RECT  10.752 47.019 11.944 49.973 ;
     RECT  17.056 48.949 20.192 50.027 ;
     RECT  22.456 47.339 23.392 50.677 ;
     RECT  40.96 49.333 63.008 50.677 ;
     RECT  35.456 49.013 39.328 51.125 ;
     RECT  35.456 51.125 39.392 51.253 ;
     RECT  40.832 50.677 63.008 51.253 ;
     RECT  19.904 50.027 20.192 51.371 ;
     RECT  7.936 50.037 7.968 51.627 ;
     RECT  35.456 51.253 63.008 51.627 ;
     RECT  17.056 50.027 18.144 51.947 ;
     RECT  35.52 51.627 63.008 51.947 ;
     RECT  35.52 51.947 62.88 52.587 ;
     RECT  21.632 50.677 23.392 52.853 ;
     RECT  20.16 51.371 20.192 52.981 ;
     RECT  21.632 52.853 23.52 52.981 ;
     RECT  25.792 48.309 33.824 52.981 ;
     RECT  35.52 52.587 51.68 52.981 ;
     RECT  25.792 52.981 51.68 53.355 ;
     RECT  20.16 52.981 23.52 53.675 ;
     RECT  37.504 53.355 51.68 53.739 ;
     RECT  20.16 53.675 21.152 53.941 ;
     RECT  19.968 53.941 21.152 54.123 ;
     RECT  25.792 53.355 35.808 54.379 ;
     RECT  8.32 52.981 8.352 54.507 ;
     RECT  52.992 52.587 62.88 54.507 ;
     RECT  19.968 54.123 20.512 54.645 ;
     RECT  25.792 54.379 35.744 54.763 ;
     RECT  37.504 53.739 51.616 54.763 ;
     RECT  19.584 54.645 20.512 54.891 ;
     RECT  38.656 54.763 48.16 55.403 ;
     RECT  26.304 54.763 35.744 55.925 ;
     RECT  19.584 54.891 19.616 55.979 ;
     RECT  22.456 53.675 23.52 55.979 ;
     RECT  26.304 55.925 35.872 55.979 ;
     RECT  9.984 49.973 11.944 56.491 ;
     RECT  13.888 54.517 13.92 56.491 ;
     RECT  53.12 54.507 62.88 56.491 ;
     RECT  17.056 51.947 17.344 57.013 ;
     RECT  11.328 56.491 11.944 57.067 ;
     RECT  53.12 56.491 60.544 57.067 ;
     RECT  22.456 55.979 23.264 57.461 ;
     RECT  11.656 57.067 11.944 57.525 ;
     RECT  26.304 55.979 30.688 57.643 ;
     RECT  38.656 55.403 38.944 57.973 ;
     RECT  9.984 56.491 10.016 58.091 ;
     RECT  38.144 57.973 38.944 58.101 ;
     RECT  40.512 55.403 48.16 58.101 ;
     RECT  38.144 58.101 48.16 58.219 ;
     RECT  61.888 56.491 62.88 58.219 ;
     RECT  26.304 57.643 29.92 58.549 ;
     RECT  53.12 57.067 53.152 58.677 ;
     RECT  54.464 57.067 60.544 58.677 ;
     RECT  25.728 58.549 29.92 58.795 ;
     RECT  53.12 58.677 60.544 58.795 ;
     RECT  56.768 58.795 60.544 58.997 ;
     RECT  61.888 58.219 61.92 58.997 ;
     RECT  32.128 55.979 35.872 59.125 ;
     RECT  17.056 57.013 17.504 59.253 ;
     RECT  25.728 58.795 28.896 59.307 ;
     RECT  38.144 58.219 46.688 59.435 ;
     RECT  21.632 57.461 23.264 59.499 ;
     RECT  38.144 59.435 42.592 59.499 ;
     RECT  11.656 57.525 13.152 59.627 ;
     RECT  49.456 54.763 51.616 59.637 ;
     RECT  53.12 58.795 55.264 59.637 ;
     RECT  38.144 59.499 40.544 59.755 ;
     RECT  25.728 59.307 28.832 59.819 ;
     RECT  40.512 59.755 40.544 59.819 ;
     RECT  44.056 59.435 46.688 59.883 ;
     RECT  56.768 58.997 61.92 59.883 ;
     RECT  21.632 59.499 22.744 60.075 ;
     RECT  26.304 59.819 28.832 60.075 ;
     RECT  49.456 59.637 55.264 60.277 ;
     RECT  31.936 59.125 35.872 60.331 ;
     RECT  38.144 59.755 38.944 60.331 ;
     RECT  41.856 59.499 42.592 60.331 ;
     RECT  49.456 60.277 55.776 60.331 ;
     RECT  59.008 59.883 61.472 60.587 ;
     RECT  17.056 59.253 17.632 60.843 ;
     RECT  26.304 60.075 26.336 60.843 ;
     RECT  54.336 60.331 55.776 60.843 ;
     RECT  44.056 59.883 45.536 60.907 ;
     RECT  31.936 60.331 34.336 61.419 ;
     RECT  35.84 60.331 35.872 61.419 ;
     RECT  59.008 60.587 60.544 61.419 ;
     RECT  46.848 60.277 46.88 61.429 ;
     RECT  46.016 61.429 46.88 61.483 ;
     RECT  49.456 60.331 52.384 61.483 ;
     RECT  54.856 60.843 55.776 61.483 ;
     RECT  41.856 60.331 42.4 61.611 ;
     RECT  51.52 61.483 52.384 61.611 ;
     RECT  27.856 60.075 28.832 62.187 ;
     RECT  33.088 61.419 34.336 62.187 ;
     RECT  46.016 61.483 46.048 62.187 ;
     RECT  30.144 61.429 30.176 62.763 ;
     RECT  41.856 61.611 41.888 62.763 ;
     RECT  49.456 61.483 50.144 62.763 ;
     RECT  52.352 61.611 52.384 62.955 ;
     RECT  0.856 45.675 1.144 63.999 ;
     RECT  6.256 39.915 6.544 63.999 ;
     RECT  11.656 59.627 11.944 63.999 ;
     RECT  17.056 60.843 17.344 63.999 ;
     RECT  22.456 60.075 22.744 63.999 ;
     RECT  27.856 62.187 28.144 63.999 ;
     RECT  33.256 62.187 33.544 63.999 ;
     RECT  38.656 60.331 38.944 63.999 ;
     RECT  44.056 60.907 44.344 63.999 ;
     RECT  49.456 62.763 49.744 63.999 ;
     RECT  54.856 61.483 55.144 63.999 ;
     RECT  60.256 61.419 60.544 63.999 ;
  END
END dsfd_r2l_vr_512x1__hcol
END LIBRARY
